VERSION 5.7 ;
  NOWIREEXTENSIONATPIN ON ;
  DIVIDERCHAR "/" ;
  BUSBITCHARS "[]" ;
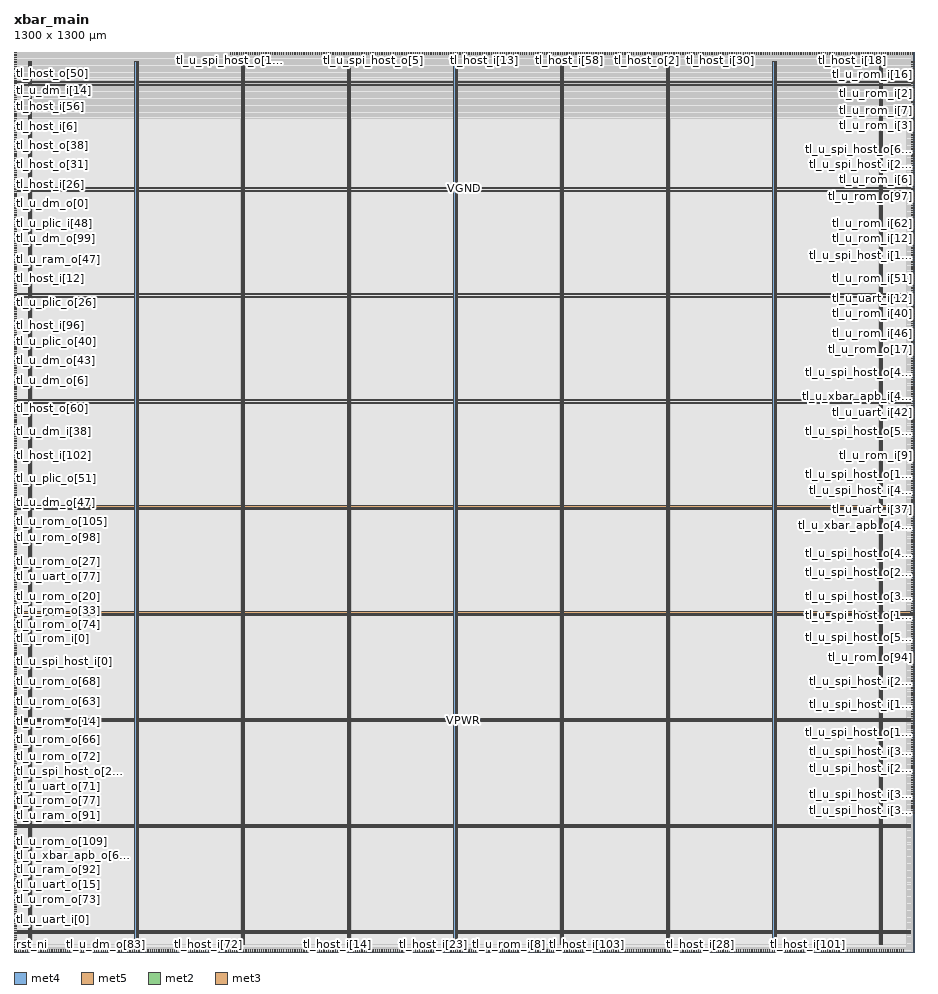
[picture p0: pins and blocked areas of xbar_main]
MACRO xbar_main
  CLASS BLOCK ;
  FOREIGN xbar_main ;
  ORIGIN 0.000 0.000 ;
  SIZE 1300.000 BY 1300.000 ;
  PIN VGND
    DIRECTION INOUT ;
    USE GROUND ;
    PORT
      LAYER met4 ;
        RECT 24.340 10.640 25.940 1286.800 ;
    END
    PORT
      LAYER met4 ;
        RECT 177.940 10.640 179.540 1286.800 ;
    END
    PORT
      LAYER met4 ;
        RECT 331.540 10.640 333.140 1286.800 ;
    END
    PORT
      LAYER met4 ;
        RECT 485.140 10.640 486.740 1286.800 ;
    END
    PORT
      LAYER met4 ;
        RECT 638.740 10.640 640.340 1286.800 ;
    END
    PORT
      LAYER met4 ;
        RECT 792.340 10.640 793.940 1286.800 ;
    END
    PORT
      LAYER met4 ;
        RECT 945.940 10.640 947.540 1286.800 ;
    END
    PORT
      LAYER met4 ;
        RECT 1099.540 10.640 1101.140 1286.800 ;
    END
    PORT
      LAYER met4 ;
        RECT 1253.140 10.640 1254.740 1286.800 ;
    END
    PORT
      LAYER met5 ;
        RECT 5.280 30.030 1294.680 31.630 ;
    END
    PORT
      LAYER met5 ;
        RECT 5.280 183.210 1294.680 184.810 ;
    END
    PORT
      LAYER met5 ;
        RECT 5.280 336.390 1294.680 337.990 ;
    END
    PORT
      LAYER met5 ;
        RECT 5.280 489.570 1294.680 491.170 ;
    END
    PORT
      LAYER met5 ;
        RECT 5.280 642.750 1294.680 644.350 ;
    END
    PORT
      LAYER met5 ;
        RECT 5.280 795.930 1294.680 797.530 ;
    END
    PORT
      LAYER met5 ;
        RECT 5.280 949.110 1294.680 950.710 ;
    END
    PORT
      LAYER met5 ;
        RECT 5.280 1102.290 1294.680 1103.890 ;
    END
    PORT
      LAYER met5 ;
        RECT 5.280 1255.470 1294.680 1257.070 ;
    END
  END VGND
  PIN VPWR
    DIRECTION INOUT ;
    USE POWER ;
    PORT
      LAYER met4 ;
        RECT 21.040 10.640 22.640 1286.800 ;
    END
    PORT
      LAYER met4 ;
        RECT 174.640 10.640 176.240 1286.800 ;
    END
    PORT
      LAYER met4 ;
        RECT 328.240 10.640 329.840 1286.800 ;
    END
    PORT
      LAYER met4 ;
        RECT 481.840 10.640 483.440 1286.800 ;
    END
    PORT
      LAYER met4 ;
        RECT 635.440 10.640 637.040 1286.800 ;
    END
    PORT
      LAYER met4 ;
        RECT 789.040 10.640 790.640 1286.800 ;
    END
    PORT
      LAYER met4 ;
        RECT 942.640 10.640 944.240 1286.800 ;
    END
    PORT
      LAYER met4 ;
        RECT 1096.240 10.640 1097.840 1286.800 ;
    END
    PORT
      LAYER met4 ;
        RECT 1249.840 10.640 1251.440 1286.800 ;
    END
    PORT
      LAYER met5 ;
        RECT 5.280 26.730 1294.680 28.330 ;
    END
    PORT
      LAYER met5 ;
        RECT 5.280 179.910 1294.680 181.510 ;
    END
    PORT
      LAYER met5 ;
        RECT 5.280 333.090 1294.680 334.690 ;
    END
    PORT
      LAYER met5 ;
        RECT 5.280 486.270 1294.680 487.870 ;
    END
    PORT
      LAYER met5 ;
        RECT 5.280 639.450 1294.680 641.050 ;
    END
    PORT
      LAYER met5 ;
        RECT 5.280 792.630 1294.680 794.230 ;
    END
    PORT
      LAYER met5 ;
        RECT 5.280 945.810 1294.680 947.410 ;
    END
    PORT
      LAYER met5 ;
        RECT 5.280 1098.990 1294.680 1100.590 ;
    END
    PORT
      LAYER met5 ;
        RECT 5.280 1252.170 1294.680 1253.770 ;
    END
  END VPWR
  PIN clk_i
    DIRECTION INPUT ;
    USE SIGNAL ;
    PORT
      LAYER met2 ;
        RECT 0.090 0.000 0.370 4.000 ;
    END
  END clk_i
  PIN rst_ni
    DIRECTION INPUT ;
    USE SIGNAL ;
    PORT
      LAYER met2 ;
        RECT 3.310 0.000 3.590 4.000 ;
    END
  END rst_ni
  PIN tl_host_i[0]
    DIRECTION INPUT ;
    USE SIGNAL ;
    ANTENNAGATEAREA 1.491900 ;
    ANTENNADIFFAREA 0.869400 ;
    PORT
      LAYER met3 ;
        RECT 0.000 1224.040 4.000 1224.640 ;
    END
  END tl_host_i[0]
  PIN tl_host_i[100]
    DIRECTION INPUT ;
    USE SIGNAL ;
    ANTENNAGATEAREA 1.491900 ;
    ANTENNADIFFAREA 0.869400 ;
    PORT
      LAYER met3 ;
        RECT 0.000 1105.040 4.000 1105.640 ;
    END
  END tl_host_i[100]
  PIN tl_host_i[101]
    DIRECTION INPUT ;
    USE SIGNAL ;
    ANTENNAGATEAREA 1.808400 ;
    ANTENNADIFFAREA 0.869400 ;
    PORT
      LAYER met2 ;
        RECT 1146.410 0.000 1146.690 4.000 ;
    END
  END tl_host_i[101]
  PIN tl_host_i[102]
    DIRECTION INPUT ;
    USE SIGNAL ;
    ANTENNAGATEAREA 1.560900 ;
    ANTENNADIFFAREA 0.869400 ;
    PORT
      LAYER met3 ;
        RECT 0.000 717.440 4.000 718.040 ;
    END
  END tl_host_i[102]
  PIN tl_host_i[103]
    DIRECTION INPUT ;
    USE SIGNAL ;
    ANTENNAGATEAREA 1.491900 ;
    ANTENNADIFFAREA 0.869400 ;
    PORT
      LAYER met2 ;
        RECT 827.630 0.000 827.910 4.000 ;
    END
  END tl_host_i[103]
  PIN tl_host_i[104]
    DIRECTION INPUT ;
    USE SIGNAL ;
    ANTENNAGATEAREA 1.808400 ;
    ANTENNADIFFAREA 0.869400 ;
    PORT
      LAYER met2 ;
        RECT 850.170 0.000 850.450 4.000 ;
    END
  END tl_host_i[104]
  PIN tl_host_i[105]
    DIRECTION INPUT ;
    USE SIGNAL ;
    ANTENNAGATEAREA 1.560900 ;
    ANTENNADIFFAREA 0.869400 ;
    PORT
      LAYER met2 ;
        RECT 6.530 0.000 6.810 4.000 ;
    END
  END tl_host_i[105]
  PIN tl_host_i[106]
    DIRECTION INPUT ;
    USE SIGNAL ;
    ANTENNAGATEAREA 1.313400 ;
    ANTENNADIFFAREA 0.869400 ;
    PORT
      LAYER met2 ;
        RECT 29.070 0.000 29.350 4.000 ;
    END
  END tl_host_i[106]
  PIN tl_host_i[107]
    DIRECTION INPUT ;
    USE SIGNAL ;
    ANTENNAGATEAREA 1.491900 ;
    ANTENNADIFFAREA 0.869400 ;
    PORT
      LAYER met3 ;
        RECT 0.000 877.240 4.000 877.840 ;
    END
  END tl_host_i[107]
  PIN tl_host_i[108]
    DIRECTION INPUT ;
    USE SIGNAL ;
    ANTENNAGATEAREA 1.491900 ;
    ANTENNADIFFAREA 0.869400 ;
    PORT
      LAYER met2 ;
        RECT 248.030 0.000 248.310 4.000 ;
    END
  END tl_host_i[108]
  PIN tl_host_i[109]
    DIRECTION INPUT ;
    USE SIGNAL ;
    ANTENNAGATEAREA 0.647700 ;
    ANTENNADIFFAREA 0.434700 ;
    PORT
      LAYER met2 ;
        RECT 241.590 0.000 241.870 4.000 ;
    END
  END tl_host_i[109]
  PIN tl_host_i[10]
    DIRECTION INPUT ;
    USE SIGNAL ;
    ANTENNAGATEAREA 1.313400 ;
    ANTENNADIFFAREA 0.869400 ;
    PORT
      LAYER met2 ;
        RECT 122.450 0.000 122.730 4.000 ;
    END
  END tl_host_i[10]
  PIN tl_host_i[11]
    DIRECTION INPUT ;
    USE SIGNAL ;
    ANTENNAGATEAREA 1.313400 ;
    ANTENNADIFFAREA 0.869400 ;
    PORT
      LAYER met2 ;
        RECT 1165.730 0.000 1166.010 4.000 ;
    END
  END tl_host_i[11]
  PIN tl_host_i[12]
    DIRECTION INPUT ;
    USE SIGNAL ;
    ANTENNAGATEAREA 1.560900 ;
    ANTENNADIFFAREA 0.869400 ;
    PORT
      LAYER met3 ;
        RECT 0.000 972.440 4.000 973.040 ;
    END
  END tl_host_i[12]
  PIN tl_host_i[13]
    DIRECTION INPUT ;
    USE SIGNAL ;
    ANTENNAGATEAREA 1.560900 ;
    ANTENNADIFFAREA 0.869400 ;
    PORT
      LAYER met2 ;
        RECT 679.510 1296.000 679.790 1300.000 ;
    END
  END tl_host_i[13]
  PIN tl_host_i[14]
    DIRECTION INPUT ;
    USE SIGNAL ;
    ANTENNAGATEAREA 1.491900 ;
    ANTENNADIFFAREA 0.869400 ;
    PORT
      LAYER met2 ;
        RECT 466.990 0.000 467.270 4.000 ;
    END
  END tl_host_i[14]
  PIN tl_host_i[15]
    DIRECTION INPUT ;
    USE SIGNAL ;
    ANTENNAGATEAREA 1.491900 ;
    ANTENNADIFFAREA 0.869400 ;
    PORT
      LAYER met2 ;
        RECT 512.070 0.000 512.350 4.000 ;
    END
  END tl_host_i[15]
  PIN tl_host_i[16]
    DIRECTION INPUT ;
    USE SIGNAL ;
    ANTENNAGATEAREA 1.560900 ;
    ANTENNADIFFAREA 0.869400 ;
    PORT
      LAYER met2 ;
        RECT 1011.170 0.000 1011.450 4.000 ;
    END
  END tl_host_i[16]
  PIN tl_host_i[17]
    DIRECTION INPUT ;
    USE SIGNAL ;
    ANTENNAGATEAREA 1.560900 ;
    ANTENNADIFFAREA 0.869400 ;
    PORT
      LAYER met2 ;
        RECT 769.670 1296.000 769.950 1300.000 ;
    END
  END tl_host_i[17]
  PIN tl_host_i[18]
    DIRECTION INPUT ;
    USE SIGNAL ;
    ANTENNAGATEAREA 1.808400 ;
    ANTENNADIFFAREA 0.869400 ;
    PORT
      LAYER met2 ;
        RECT 1210.810 1296.000 1211.090 1300.000 ;
    END
  END tl_host_i[18]
  PIN tl_host_i[19]
    DIRECTION INPUT ;
    USE SIGNAL ;
    ANTENNAGATEAREA 1.560900 ;
    ANTENNADIFFAREA 0.869400 ;
    PORT
      LAYER met3 ;
        RECT 0.000 697.040 4.000 697.640 ;
    END
  END tl_host_i[19]
  PIN tl_host_i[1]
    DIRECTION INPUT ;
    USE SIGNAL ;
    ANTENNAGATEAREA 1.560900 ;
    ANTENNADIFFAREA 0.869400 ;
    PORT
      LAYER met3 ;
        RECT 0.000 816.040 4.000 816.640 ;
    END
  END tl_host_i[1]
  PIN tl_host_i[20]
    DIRECTION INPUT ;
    USE SIGNAL ;
    ANTENNAGATEAREA 1.808400 ;
    ANTENNADIFFAREA 0.869400 ;
    PORT
      LAYER met2 ;
        RECT 173.970 0.000 174.250 4.000 ;
    END
  END tl_host_i[20]
  PIN tl_host_i[21]
    DIRECTION INPUT ;
    USE SIGNAL ;
    ANTENNAGATEAREA 1.491900 ;
    ANTENNADIFFAREA 0.869400 ;
    PORT
      LAYER met2 ;
        RECT 1085.230 0.000 1085.510 4.000 ;
    END
  END tl_host_i[21]
  PIN tl_host_i[22]
    DIRECTION INPUT ;
    USE SIGNAL ;
    ANTENNAGATEAREA 1.808400 ;
    ANTENNADIFFAREA 0.869400 ;
    PORT
      LAYER met2 ;
        RECT 956.430 1296.000 956.710 1300.000 ;
    END
  END tl_host_i[22]
  PIN tl_host_i[23]
    DIRECTION INPUT ;
    USE SIGNAL ;
    ANTENNAGATEAREA 1.808400 ;
    ANTENNADIFFAREA 0.869400 ;
    PORT
      LAYER met2 ;
        RECT 605.450 0.000 605.730 4.000 ;
    END
  END tl_host_i[23]
  PIN tl_host_i[24]
    DIRECTION INPUT ;
    USE SIGNAL ;
    ANTENNAGATEAREA 1.491900 ;
    ANTENNADIFFAREA 0.869400 ;
    PORT
      LAYER met3 ;
        RECT 0.000 914.640 4.000 915.240 ;
    END
  END tl_host_i[24]
  PIN tl_host_i[25]
    DIRECTION INPUT ;
    USE SIGNAL ;
    ANTENNAGATEAREA 1.313400 ;
    ANTENNADIFFAREA 0.869400 ;
    PORT
      LAYER met2 ;
        RECT 64.490 0.000 64.770 4.000 ;
    END
  END tl_host_i[25]
  PIN tl_host_i[26]
    DIRECTION INPUT ;
    USE SIGNAL ;
    ANTENNAGATEAREA 1.491900 ;
    ANTENNADIFFAREA 0.869400 ;
    PORT
      LAYER met3 ;
        RECT 0.000 1108.440 4.000 1109.040 ;
    END
  END tl_host_i[26]
  PIN tl_host_i[27]
    DIRECTION INPUT ;
    USE SIGNAL ;
    ANTENNAGATEAREA 2.055900 ;
    ANTENNADIFFAREA 0.869400 ;
    PORT
      LAYER met2 ;
        RECT 48.390 0.000 48.670 4.000 ;
    END
  END tl_host_i[27]
  PIN tl_host_i[28]
    DIRECTION INPUT ;
    USE SIGNAL ;
    ANTENNAGATEAREA 1.491900 ;
    ANTENNADIFFAREA 0.869400 ;
    PORT
      LAYER met2 ;
        RECT 991.850 0.000 992.130 4.000 ;
    END
  END tl_host_i[28]
  PIN tl_host_i[29]
    DIRECTION INPUT ;
    USE SIGNAL ;
    ANTENNAGATEAREA 1.491900 ;
    ANTENNADIFFAREA 0.869400 ;
    PORT
      LAYER met2 ;
        RECT 486.310 0.000 486.590 4.000 ;
    END
  END tl_host_i[29]
  PIN tl_host_i[2]
    DIRECTION INPUT ;
    USE SIGNAL ;
    ANTENNAGATEAREA 1.808400 ;
    ANTENNADIFFAREA 0.869400 ;
    PORT
      LAYER met3 ;
        RECT 0.000 663.040 4.000 663.640 ;
    END
  END tl_host_i[2]
  PIN tl_host_i[30]
    DIRECTION INPUT ;
    USE SIGNAL ;
    ANTENNAGATEAREA 1.560900 ;
    ANTENNADIFFAREA 0.869400 ;
    PORT
      LAYER met2 ;
        RECT 1020.830 1296.000 1021.110 1300.000 ;
    END
  END tl_host_i[30]
  PIN tl_host_i[31]
    DIRECTION INPUT ;
    USE SIGNAL ;
    ANTENNAGATEAREA 1.491900 ;
    ANTENNADIFFAREA 0.869400 ;
    PORT
      LAYER met2 ;
        RECT 1059.470 0.000 1059.750 4.000 ;
    END
  END tl_host_i[31]
  PIN tl_host_i[32]
    DIRECTION INPUT ;
    USE SIGNAL ;
    ANTENNAGATEAREA 1.808400 ;
    ANTENNADIFFAREA 0.869400 ;
    PORT
      LAYER met2 ;
        RECT 702.050 0.000 702.330 4.000 ;
    END
  END tl_host_i[32]
  PIN tl_host_i[33]
    DIRECTION INPUT ;
    USE SIGNAL ;
    ANTENNAGATEAREA 1.808400 ;
    ANTENNADIFFAREA 0.869400 ;
    PORT
      LAYER met2 ;
        RECT 96.690 0.000 96.970 4.000 ;
    END
  END tl_host_i[33]
  PIN tl_host_i[34]
    DIRECTION INPUT ;
    USE SIGNAL ;
    ANTENNAGATEAREA 2.711400 ;
    ANTENNADIFFAREA 0.869400 ;
    PORT
      LAYER met2 ;
        RECT 12.970 0.000 13.250 4.000 ;
    END
  END tl_host_i[34]
  PIN tl_host_i[35]
    DIRECTION INPUT ;
    USE SIGNAL ;
    ANTENNAGATEAREA 1.560900 ;
    ANTENNADIFFAREA 0.869400 ;
    PORT
      LAYER met2 ;
        RECT 917.790 0.000 918.070 4.000 ;
    END
  END tl_host_i[35]
  PIN tl_host_i[36]
    DIRECTION INPUT ;
    USE SIGNAL ;
    ANTENNAGATEAREA 1.560900 ;
    ANTENNADIFFAREA 0.869400 ;
    PORT
      LAYER met3 ;
        RECT 0.000 863.640 4.000 864.240 ;
    END
  END tl_host_i[36]
  PIN tl_host_i[37]
    DIRECTION INPUT ;
    USE SIGNAL ;
    ANTENNAGATEAREA 1.491900 ;
    ANTENNADIFFAREA 0.869400 ;
    PORT
      LAYER met2 ;
        RECT 1062.690 0.000 1062.970 4.000 ;
    END
  END tl_host_i[37]
  PIN tl_host_i[38]
    DIRECTION INPUT ;
    USE SIGNAL ;
    ANTENNAGATEAREA 1.313400 ;
    ANTENNADIFFAREA 0.869400 ;
    PORT
      LAYER met2 ;
        RECT 77.370 0.000 77.650 4.000 ;
    END
  END tl_host_i[38]
  PIN tl_host_i[39]
    DIRECTION INPUT ;
    USE SIGNAL ;
    ANTENNAGATEAREA 1.808400 ;
    ANTENNADIFFAREA 0.869400 ;
    PORT
      LAYER met2 ;
        RECT 995.070 0.000 995.350 4.000 ;
    END
  END tl_host_i[39]
  PIN tl_host_i[3]
    DIRECTION INPUT ;
    USE SIGNAL ;
    ANTENNAGATEAREA 1.491900 ;
    ANTENNADIFFAREA 0.869400 ;
    PORT
      LAYER met2 ;
        RECT 1230.130 0.000 1230.410 4.000 ;
    END
  END tl_host_i[3]
  PIN tl_host_i[40]
    DIRECTION INPUT ;
    USE SIGNAL ;
    ANTENNAGATEAREA 1.560900 ;
    ANTENNADIFFAREA 0.869400 ;
    PORT
      LAYER met3 ;
        RECT 0.000 761.640 4.000 762.240 ;
    END
  END tl_host_i[40]
  PIN tl_host_i[41]
    DIRECTION INPUT ;
    USE SIGNAL ;
    ANTENNAGATEAREA 1.491900 ;
    ANTENNADIFFAREA 0.869400 ;
    PORT
      LAYER met2 ;
        RECT 1036.930 0.000 1037.210 4.000 ;
    END
  END tl_host_i[41]
  PIN tl_host_i[42]
    DIRECTION INPUT ;
    USE SIGNAL ;
    ANTENNAGATEAREA 1.560900 ;
    ANTENNADIFFAREA 0.869400 ;
    PORT
      LAYER met2 ;
        RECT 1078.790 0.000 1079.070 4.000 ;
    END
  END tl_host_i[42]
  PIN tl_host_i[43]
    DIRECTION INPUT ;
    USE SIGNAL ;
    ANTENNAGATEAREA 1.917900 ;
    ANTENNADIFFAREA 0.869400 ;
    PORT
      LAYER met3 ;
        RECT 0.000 629.040 4.000 629.640 ;
    END
  END tl_host_i[43]
  PIN tl_host_i[44]
    DIRECTION INPUT ;
    USE SIGNAL ;
    ANTENNAGATEAREA 1.560900 ;
    ANTENNADIFFAREA 0.869400 ;
    PORT
      LAYER met3 ;
        RECT 0.000 969.040 4.000 969.640 ;
    END
  END tl_host_i[44]
  PIN tl_host_i[45]
    DIRECTION INPUT ;
    USE SIGNAL ;
    ANTENNAGATEAREA 1.560900 ;
    ANTENNADIFFAREA 0.869400 ;
    PORT
      LAYER met2 ;
        RECT 998.290 0.000 998.570 4.000 ;
    END
  END tl_host_i[45]
  PIN tl_host_i[46]
    DIRECTION INPUT ;
    USE SIGNAL ;
    ANTENNAGATEAREA 1.808400 ;
    ANTENNADIFFAREA 0.869400 ;
    PORT
      LAYER met2 ;
        RECT 933.890 1296.000 934.170 1300.000 ;
    END
  END tl_host_i[46]
  PIN tl_host_i[47]
    DIRECTION INPUT ;
    USE SIGNAL ;
    ANTENNAGATEAREA 1.808400 ;
    ANTENNADIFFAREA 0.869400 ;
    PORT
      LAYER met3 ;
        RECT 0.000 656.240 4.000 656.840 ;
    END
  END tl_host_i[47]
  PIN tl_host_i[48]
    DIRECTION INPUT ;
    USE SIGNAL ;
    ANTENNAGATEAREA 1.508400 ;
    ANTENNADIFFAREA 0.869400 ;
    PORT
      LAYER met3 ;
        RECT 0.000 992.840 4.000 993.440 ;
    END
  END tl_host_i[48]
  PIN tl_host_i[49]
    DIRECTION INPUT ;
    USE SIGNAL ;
    ANTENNAGATEAREA 1.808400 ;
    ANTENNADIFFAREA 0.869400 ;
    PORT
      LAYER met3 ;
        RECT 0.000 639.240 4.000 639.840 ;
    END
  END tl_host_i[49]
  PIN tl_host_i[4]
    DIRECTION INPUT ;
    USE SIGNAL ;
    ANTENNAGATEAREA 1.808400 ;
    ANTENNADIFFAREA 0.869400 ;
    PORT
      LAYER met2 ;
        RECT 61.270 0.000 61.550 4.000 ;
    END
  END tl_host_i[4]
  PIN tl_host_i[50]
    DIRECTION INPUT ;
    USE SIGNAL ;
    ANTENNAGATEAREA 1.808400 ;
    ANTENNADIFFAREA 0.869400 ;
    PORT
      LAYER met2 ;
        RECT 708.490 0.000 708.770 4.000 ;
    END
  END tl_host_i[50]
  PIN tl_host_i[51]
    DIRECTION INPUT ;
    USE SIGNAL ;
    ANTENNAGATEAREA 1.808400 ;
    ANTENNADIFFAREA 0.869400 ;
    PORT
      LAYER met3 ;
        RECT 0.000 686.840 4.000 687.440 ;
    END
  END tl_host_i[51]
  PIN tl_host_i[52]
    DIRECTION INPUT ;
    USE SIGNAL ;
    ANTENNAGATEAREA 1.313400 ;
    ANTENNADIFFAREA 0.869400 ;
    PORT
      LAYER met2 ;
        RECT 1139.970 0.000 1140.250 4.000 ;
    END
  END tl_host_i[52]
  PIN tl_host_i[53]
    DIRECTION INPUT ;
    USE SIGNAL ;
    ANTENNAGATEAREA 1.560900 ;
    ANTENNADIFFAREA 0.869400 ;
    PORT
      LAYER met2 ;
        RECT 666.630 0.000 666.910 4.000 ;
    END
  END tl_host_i[53]
  PIN tl_host_i[54]
    DIRECTION INPUT ;
    USE SIGNAL ;
    ANTENNAGATEAREA 1.808400 ;
    ANTENNADIFFAREA 0.869400 ;
    PORT
      LAYER met3 ;
        RECT 0.000 1173.040 4.000 1173.640 ;
    END
  END tl_host_i[54]
  PIN tl_host_i[55]
    DIRECTION INPUT ;
    USE SIGNAL ;
    ANTENNAGATEAREA 1.808400 ;
    ANTENNADIFFAREA 0.869400 ;
    PORT
      LAYER met3 ;
        RECT 0.000 846.640 4.000 847.240 ;
    END
  END tl_host_i[55]
  PIN tl_host_i[56]
    DIRECTION INPUT ;
    USE SIGNAL ;
    ANTENNAGATEAREA 1.491900 ;
    ANTENNADIFFAREA 0.869400 ;
    PORT
      LAYER met3 ;
        RECT 0.000 1220.640 4.000 1221.240 ;
    END
  END tl_host_i[56]
  PIN tl_host_i[57]
    DIRECTION INPUT ;
    USE SIGNAL ;
    ANTENNAGATEAREA 1.491900 ;
    ANTENNADIFFAREA 0.869400 ;
    PORT
      LAYER met3 ;
        RECT 0.000 1162.840 4.000 1163.440 ;
    END
  END tl_host_i[57]
  PIN tl_host_i[58]
    DIRECTION INPUT ;
    USE SIGNAL ;
    ANTENNAGATEAREA 1.313400 ;
    ANTENNADIFFAREA 0.869400 ;
    PORT
      LAYER met2 ;
        RECT 801.870 1296.000 802.150 1300.000 ;
    END
  END tl_host_i[58]
  PIN tl_host_i[59]
    DIRECTION INPUT ;
    USE SIGNAL ;
    ANTENNAGATEAREA 1.560900 ;
    ANTENNADIFFAREA 0.869400 ;
    PORT
      LAYER met2 ;
        RECT 888.810 0.000 889.090 4.000 ;
    END
  END tl_host_i[59]
  PIN tl_host_i[5]
    DIRECTION INPUT ;
    USE SIGNAL ;
    ANTENNAGATEAREA 1.917900 ;
    ANTENNADIFFAREA 0.869400 ;
    PORT
      LAYER met3 ;
        RECT 0.000 999.640 4.000 1000.240 ;
    END
  END tl_host_i[5]
  PIN tl_host_i[60]
    DIRECTION INPUT ;
    USE SIGNAL ;
    ANTENNAGATEAREA 1.491900 ;
    ANTENNADIFFAREA 0.869400 ;
    PORT
      LAYER met2 ;
        RECT 966.090 1296.000 966.370 1300.000 ;
    END
  END tl_host_i[60]
  PIN tl_host_i[61]
    DIRECTION INPUT ;
    USE SIGNAL ;
    ANTENNAGATEAREA 0.593700 ;
    ANTENNADIFFAREA 0.434700 ;
    PORT
      LAYER met2 ;
        RECT 322.090 0.000 322.370 4.000 ;
    END
  END tl_host_i[61]
  PIN tl_host_i[62]
    DIRECTION INPUT ;
    USE SIGNAL ;
    ANTENNAGATEAREA 0.593700 ;
    ANTENNADIFFAREA 0.434700 ;
    PORT
      LAYER met2 ;
        RECT 386.490 0.000 386.770 4.000 ;
    END
  END tl_host_i[62]
  PIN tl_host_i[63]
    DIRECTION INPUT ;
    USE SIGNAL ;
    ANTENNAGATEAREA 0.593700 ;
    ANTENNADIFFAREA 0.434700 ;
    PORT
      LAYER met2 ;
        RECT 351.070 0.000 351.350 4.000 ;
    END
  END tl_host_i[63]
  PIN tl_host_i[64]
    DIRECTION INPUT ;
    USE SIGNAL ;
    ANTENNAGATEAREA 0.647700 ;
    ANTENNADIFFAREA 0.434700 ;
    PORT
      LAYER met2 ;
        RECT 412.250 0.000 412.530 4.000 ;
    END
  END tl_host_i[64]
  PIN tl_host_i[65]
    DIRECTION INPUT ;
    USE SIGNAL ;
    ANTENNAGATEAREA 0.593700 ;
    ANTENNADIFFAREA 0.434700 ;
    PORT
      LAYER met2 ;
        RECT 380.050 0.000 380.330 4.000 ;
    END
  END tl_host_i[65]
  PIN tl_host_i[66]
    DIRECTION INPUT ;
    USE SIGNAL ;
    ANTENNAGATEAREA 0.647700 ;
    ANTENNADIFFAREA 0.434700 ;
    PORT
      LAYER met2 ;
        RECT 450.890 0.000 451.170 4.000 ;
    END
  END tl_host_i[66]
  PIN tl_host_i[67]
    DIRECTION INPUT ;
    USE SIGNAL ;
    ANTENNAGATEAREA 0.647700 ;
    ANTENNADIFFAREA 0.434700 ;
    PORT
      LAYER met2 ;
        RECT 534.610 0.000 534.890 4.000 ;
    END
  END tl_host_i[67]
  PIN tl_host_i[68]
    DIRECTION INPUT ;
    USE SIGNAL ;
    ANTENNAGATEAREA 0.647700 ;
    ANTENNADIFFAREA 0.434700 ;
    PORT
      LAYER met2 ;
        RECT 428.350 0.000 428.630 4.000 ;
    END
  END tl_host_i[68]
  PIN tl_host_i[69]
    DIRECTION INPUT ;
    USE SIGNAL ;
    ANTENNAGATEAREA 0.631200 ;
    ANTENNADIFFAREA 0.434700 ;
    PORT
      LAYER met2 ;
        RECT 209.390 0.000 209.670 4.000 ;
    END
  END tl_host_i[69]
  PIN tl_host_i[6]
    DIRECTION INPUT ;
    USE SIGNAL ;
    ANTENNAGATEAREA 1.560900 ;
    ANTENNADIFFAREA 0.869400 ;
    PORT
      LAYER met3 ;
        RECT 0.000 1203.640 4.000 1204.240 ;
    END
  END tl_host_i[6]
  PIN tl_host_i[70]
    DIRECTION INPUT ;
    USE SIGNAL ;
    ANTENNAGATEAREA 0.682200 ;
    ANTENNADIFFAREA 0.434700 ;
    PORT
      LAYER met2 ;
        RECT 219.050 0.000 219.330 4.000 ;
    END
  END tl_host_i[70]
  PIN tl_host_i[71]
    DIRECTION INPUT ;
    USE SIGNAL ;
    ANTENNAGATEAREA 0.682200 ;
    ANTENNADIFFAREA 0.434700 ;
    PORT
      LAYER met2 ;
        RECT 309.210 0.000 309.490 4.000 ;
    END
  END tl_host_i[71]
  PIN tl_host_i[72]
    DIRECTION INPUT ;
    USE SIGNAL ;
    ANTENNAGATEAREA 0.682200 ;
    ANTENNADIFFAREA 0.434700 ;
    PORT
      LAYER met2 ;
        RECT 280.230 0.000 280.510 4.000 ;
    END
  END tl_host_i[72]
  PIN tl_host_i[73]
    DIRECTION INPUT ;
    USE SIGNAL ;
    ANTENNAGATEAREA 0.631200 ;
    ANTENNADIFFAREA 0.434700 ;
    PORT
      LAYER met2 ;
        RECT 254.470 0.000 254.750 4.000 ;
    END
  END tl_host_i[73]
  PIN tl_host_i[74]
    DIRECTION INPUT ;
    USE SIGNAL ;
    ANTENNAGATEAREA 0.631200 ;
    ANTENNADIFFAREA 0.434700 ;
    PORT
      LAYER met2 ;
        RECT 235.150 0.000 235.430 4.000 ;
    END
  END tl_host_i[74]
  PIN tl_host_i[75]
    DIRECTION INPUT ;
    USE SIGNAL ;
    ANTENNAGATEAREA 0.631200 ;
    ANTENNADIFFAREA 0.434700 ;
    PORT
      LAYER met2 ;
        RECT 267.350 0.000 267.630 4.000 ;
    END
  END tl_host_i[75]
  PIN tl_host_i[76]
    DIRECTION INPUT ;
    USE SIGNAL ;
    ANTENNAGATEAREA 0.631200 ;
    ANTENNADIFFAREA 0.434700 ;
    PORT
      LAYER met2 ;
        RECT 128.890 0.000 129.170 4.000 ;
    END
  END tl_host_i[76]
  PIN tl_host_i[77]
    DIRECTION INPUT ;
    USE SIGNAL ;
    ANTENNAGATEAREA 0.631200 ;
    ANTENNADIFFAREA 0.434700 ;
    PORT
      LAYER met2 ;
        RECT 157.870 0.000 158.150 4.000 ;
    END
  END tl_host_i[77]
  PIN tl_host_i[78]
    DIRECTION INPUT ;
    USE SIGNAL ;
    ANTENNAGATEAREA 0.560700 ;
    ANTENNADIFFAREA 0.434700 ;
    PORT
      LAYER met2 ;
        RECT 135.330 0.000 135.610 4.000 ;
    END
  END tl_host_i[78]
  PIN tl_host_i[79]
    DIRECTION INPUT ;
    USE SIGNAL ;
    ANTENNAGATEAREA 0.647700 ;
    ANTENNADIFFAREA 0.434700 ;
    PORT
      LAYER met2 ;
        RECT 215.830 0.000 216.110 4.000 ;
    END
  END tl_host_i[79]
  PIN tl_host_i[7]
    DIRECTION INPUT ;
    USE SIGNAL ;
    ANTENNAGATEAREA 1.491900 ;
    ANTENNADIFFAREA 0.869400 ;
    PORT
      LAYER met2 ;
        RECT 1091.670 0.000 1091.950 4.000 ;
    END
  END tl_host_i[7]
  PIN tl_host_i[80]
    DIRECTION INPUT ;
    USE SIGNAL ;
    ANTENNAGATEAREA 0.631200 ;
    ANTENNADIFFAREA 0.434700 ;
    PORT
      LAYER met2 ;
        RECT 186.850 0.000 187.130 4.000 ;
    END
  END tl_host_i[80]
  PIN tl_host_i[81]
    DIRECTION INPUT ;
    USE SIGNAL ;
    ANTENNAGATEAREA 0.560700 ;
    ANTENNADIFFAREA 0.434700 ;
    PORT
      LAYER met2 ;
        RECT 141.770 0.000 142.050 4.000 ;
    END
  END tl_host_i[81]
  PIN tl_host_i[82]
    DIRECTION INPUT ;
    USE SIGNAL ;
    ANTENNAGATEAREA 0.631200 ;
    ANTENNADIFFAREA 0.434700 ;
    PORT
      LAYER met2 ;
        RECT 125.670 0.000 125.950 4.000 ;
    END
  END tl_host_i[82]
  PIN tl_host_i[83]
    DIRECTION INPUT ;
    USE SIGNAL ;
    ANTENNAGATEAREA 0.682200 ;
    ANTENNADIFFAREA 0.434700 ;
    PORT
      LAYER met2 ;
        RECT 106.350 0.000 106.630 4.000 ;
    END
  END tl_host_i[83]
  PIN tl_host_i[84]
    DIRECTION INPUT ;
    USE SIGNAL ;
    ANTENNAGATEAREA 0.682200 ;
    ANTENNADIFFAREA 0.434700 ;
    PORT
      LAYER met2 ;
        RECT 83.810 0.000 84.090 4.000 ;
    END
  END tl_host_i[84]
  PIN tl_host_i[85]
    DIRECTION INPUT ;
    USE SIGNAL ;
    ANTENNAGATEAREA 0.593700 ;
    ANTENNADIFFAREA 0.434700 ;
    PORT
      LAYER met2 ;
        RECT 341.410 0.000 341.690 4.000 ;
    END
  END tl_host_i[85]
  PIN tl_host_i[86]
    DIRECTION INPUT ;
    USE SIGNAL ;
    ANTENNAGATEAREA 0.682200 ;
    ANTENNADIFFAREA 0.434700 ;
    PORT
      LAYER met2 ;
        RECT 334.970 0.000 335.250 4.000 ;
    END
  END tl_host_i[86]
  PIN tl_host_i[87]
    DIRECTION INPUT ;
    USE SIGNAL ;
    ANTENNAGATEAREA 0.631200 ;
    ANTENNADIFFAREA 0.434700 ;
    PORT
      LAYER met2 ;
        RECT 438.010 0.000 438.290 4.000 ;
    END
  END tl_host_i[87]
  PIN tl_host_i[88]
    DIRECTION INPUT ;
    USE SIGNAL ;
    ANTENNAGATEAREA 0.631200 ;
    ANTENNADIFFAREA 0.434700 ;
    PORT
      LAYER met2 ;
        RECT 396.150 0.000 396.430 4.000 ;
    END
  END tl_host_i[88]
  PIN tl_host_i[89]
    DIRECTION INPUT ;
    USE SIGNAL ;
    ANTENNAGATEAREA 0.647700 ;
    ANTENNADIFFAREA 0.434700 ;
    PORT
      LAYER met2 ;
        RECT 302.770 0.000 303.050 4.000 ;
    END
  END tl_host_i[89]
  PIN tl_host_i[8]
    DIRECTION INPUT ;
    USE SIGNAL ;
    ANTENNAGATEAREA 1.313400 ;
    ANTENNADIFFAREA 0.869400 ;
    PORT
      LAYER met2 ;
        RECT 788.990 1296.000 789.270 1300.000 ;
    END
  END tl_host_i[8]
  PIN tl_host_i[90]
    DIRECTION INPUT ;
    USE SIGNAL ;
    ANTENNAGATEAREA 0.631200 ;
    ANTENNADIFFAREA 0.434700 ;
    PORT
      LAYER met2 ;
        RECT 421.910 0.000 422.190 4.000 ;
    END
  END tl_host_i[90]
  PIN tl_host_i[91]
    DIRECTION INPUT ;
    USE SIGNAL ;
    ANTENNAGATEAREA 0.631200 ;
    ANTENNADIFFAREA 0.434700 ;
    PORT
      LAYER met2 ;
        RECT 376.830 0.000 377.110 4.000 ;
    END
  END tl_host_i[91]
  PIN tl_host_i[92]
    DIRECTION INPUT ;
    USE SIGNAL ;
    ANTENNAGATEAREA 0.631200 ;
    ANTENNADIFFAREA 0.434700 ;
    PORT
      LAYER met2 ;
        RECT 399.370 0.000 399.650 4.000 ;
    END
  END tl_host_i[92]
  PIN tl_host_i[93]
    DIRECTION INPUT ;
    USE SIGNAL ;
    ANTENNAGATEAREA 2.072400 ;
    ANTENNADIFFAREA 0.869400 ;
    PORT
      LAYER met2 ;
        RECT 1101.330 1296.000 1101.610 1300.000 ;
    END
  END tl_host_i[93]
  PIN tl_host_i[94]
    DIRECTION INPUT ;
    USE SIGNAL ;
    ANTENNAGATEAREA 1.491900 ;
    ANTENNADIFFAREA 0.869400 ;
    PORT
      LAYER met2 ;
        RECT 1072.350 0.000 1072.630 4.000 ;
    END
  END tl_host_i[94]
  PIN tl_host_i[95]
    DIRECTION INPUT ;
    USE SIGNAL ;
    ANTENNAGATEAREA 1.808400 ;
    ANTENNADIFFAREA 0.869400 ;
    PORT
      LAYER met2 ;
        RECT 1098.110 1296.000 1098.390 1300.000 ;
    END
  END tl_host_i[95]
  PIN tl_host_i[96]
    DIRECTION INPUT ;
    USE SIGNAL ;
    ANTENNAGATEAREA 1.808400 ;
    ANTENNADIFFAREA 0.869400 ;
    PORT
      LAYER met3 ;
        RECT 0.000 904.440 4.000 905.040 ;
    END
  END tl_host_i[96]
  PIN tl_host_i[97]
    DIRECTION INPUT ;
    USE SIGNAL ;
    ANTENNAGATEAREA 1.491900 ;
    ANTENNADIFFAREA 0.869400 ;
    PORT
      LAYER met2 ;
        RECT 734.250 1296.000 734.530 1300.000 ;
    END
  END tl_host_i[97]
  PIN tl_host_i[98]
    DIRECTION INPUT ;
    USE SIGNAL ;
    ANTENNAGATEAREA 1.491900 ;
    ANTENNADIFFAREA 0.869400 ;
    PORT
      LAYER met2 ;
        RECT 41.950 0.000 42.230 4.000 ;
    END
  END tl_host_i[98]
  PIN tl_host_i[99]
    DIRECTION INPUT ;
    USE SIGNAL ;
    ANTENNAGATEAREA 1.808400 ;
    ANTENNADIFFAREA 0.869400 ;
    PORT
      LAYER met3 ;
        RECT 0.000 1037.040 4.000 1037.640 ;
    END
  END tl_host_i[99]
  PIN tl_host_i[9]
    DIRECTION INPUT ;
    USE SIGNAL ;
    ANTENNAGATEAREA 1.808400 ;
    ANTENNADIFFAREA 0.869400 ;
    PORT
      LAYER met2 ;
        RECT 695.610 1296.000 695.890 1300.000 ;
    END
  END tl_host_i[9]
  PIN tl_host_o[0]
    DIRECTION OUTPUT ;
    USE SIGNAL ;
    ANTENNADIFFAREA 0.445500 ;
    PORT
      LAYER met2 ;
        RECT 231.930 0.000 232.210 4.000 ;
    END
  END tl_host_o[0]
  PIN tl_host_o[10]
    DIRECTION OUTPUT ;
    USE SIGNAL ;
    ANTENNADIFFAREA 0.445500 ;
    PORT
      LAYER met3 ;
        RECT 0.000 754.840 4.000 755.440 ;
    END
  END tl_host_o[10]
  PIN tl_host_o[11]
    DIRECTION OUTPUT ;
    USE SIGNAL ;
    ANTENNADIFFAREA 0.445500 ;
    PORT
      LAYER met2 ;
        RECT 663.410 0.000 663.690 4.000 ;
    END
  END tl_host_o[11]
  PIN tl_host_o[12]
    DIRECTION OUTPUT ;
    USE SIGNAL ;
    ANTENNADIFFAREA 0.445500 ;
    PORT
      LAYER met2 ;
        RECT 949.990 1296.000 950.270 1300.000 ;
    END
  END tl_host_o[12]
  PIN tl_host_o[13]
    DIRECTION OUTPUT ;
    USE SIGNAL ;
    ANTENNADIFFAREA 0.445500 ;
    PORT
      LAYER met2 ;
        RECT 1181.830 0.000 1182.110 4.000 ;
    END
  END tl_host_o[13]
  PIN tl_host_o[14]
    DIRECTION OUTPUT ;
    USE SIGNAL ;
    ANTENNADIFFAREA 0.445500 ;
    PORT
      LAYER met3 ;
        RECT 0.000 1213.840 4.000 1214.440 ;
    END
  END tl_host_o[14]
  PIN tl_host_o[15]
    DIRECTION OUTPUT ;
    USE SIGNAL ;
    ANTENNADIFFAREA 0.445500 ;
    PORT
      LAYER met2 ;
        RECT 1249.450 0.000 1249.730 4.000 ;
    END
  END tl_host_o[15]
  PIN tl_host_o[16]
    DIRECTION OUTPUT ;
    USE SIGNAL ;
    ANTENNADIFFAREA 0.445500 ;
    PORT
      LAYER met2 ;
        RECT 978.970 1296.000 979.250 1300.000 ;
    END
  END tl_host_o[16]
  PIN tl_host_o[17]
    DIRECTION OUTPUT ;
    USE SIGNAL ;
    ANTENNADIFFAREA 0.445500 ;
    PORT
      LAYER met2 ;
        RECT 1007.950 1296.000 1008.230 1300.000 ;
    END
  END tl_host_o[17]
  PIN tl_host_o[18]
    DIRECTION OUTPUT ;
    USE SIGNAL ;
    ANTENNADIFFAREA 0.445500 ;
    PORT
      LAYER met2 ;
        RECT 1133.530 0.000 1133.810 4.000 ;
    END
  END tl_host_o[18]
  PIN tl_host_o[19]
    DIRECTION OUTPUT ;
    USE SIGNAL ;
    ANTENNADIFFAREA 0.445500 ;
    PORT
      LAYER met2 ;
        RECT 1149.630 1296.000 1149.910 1300.000 ;
    END
  END tl_host_o[19]
  PIN tl_host_o[1]
    DIRECTION OUTPUT ;
    USE SIGNAL ;
    ANTENNADIFFAREA 0.445500 ;
    PORT
      LAYER met2 ;
        RECT 1078.790 1296.000 1079.070 1300.000 ;
    END
  END tl_host_o[1]
  PIN tl_host_o[20]
    DIRECTION OUTPUT ;
    USE SIGNAL ;
    ANTENNADIFFAREA 0.445500 ;
    PORT
      LAYER met2 ;
        RECT 763.230 0.000 763.510 4.000 ;
    END
  END tl_host_o[20]
  PIN tl_host_o[21]
    DIRECTION OUTPUT ;
    USE SIGNAL ;
    ANTENNADIFFAREA 0.445500 ;
    PORT
      LAYER met2 ;
        RECT 692.390 0.000 692.670 4.000 ;
    END
  END tl_host_o[21]
  PIN tl_host_o[22]
    DIRECTION OUTPUT ;
    USE SIGNAL ;
    ANTENNADIFFAREA 0.445500 ;
    PORT
      LAYER met3 ;
        RECT 0.000 1227.440 4.000 1228.040 ;
    END
  END tl_host_o[22]
  PIN tl_host_o[23]
    DIRECTION OUTPUT ;
    USE SIGNAL ;
    ANTENNADIFFAREA 0.445500 ;
    PORT
      LAYER met2 ;
        RECT 892.030 1296.000 892.310 1300.000 ;
    END
  END tl_host_o[23]
  PIN tl_host_o[24]
    DIRECTION OUTPUT ;
    USE SIGNAL ;
    ANTENNADIFFAREA 0.445500 ;
    PORT
      LAYER met2 ;
        RECT 817.970 1296.000 818.250 1300.000 ;
    END
  END tl_host_o[24]
  PIN tl_host_o[25]
    DIRECTION OUTPUT ;
    USE SIGNAL ;
    ANTENNADIFFAREA 0.445500 ;
    PORT
      LAYER met2 ;
        RECT 824.410 1296.000 824.690 1300.000 ;
    END
  END tl_host_o[25]
  PIN tl_host_o[26]
    DIRECTION OUTPUT ;
    USE SIGNAL ;
    ANTENNADIFFAREA 0.445500 ;
    PORT
      LAYER met2 ;
        RECT 763.230 1296.000 763.510 1300.000 ;
    END
  END tl_host_o[26]
  PIN tl_host_o[27]
    DIRECTION OUTPUT ;
    USE SIGNAL ;
    ANTENNADIFFAREA 0.445500 ;
    PORT
      LAYER met2 ;
        RECT 805.090 0.000 805.370 4.000 ;
    END
  END tl_host_o[27]
  PIN tl_host_o[28]
    DIRECTION OUTPUT ;
    USE SIGNAL ;
    ANTENNADIFFAREA 0.445500 ;
    PORT
      LAYER met2 ;
        RECT 779.330 0.000 779.610 4.000 ;
    END
  END tl_host_o[28]
  PIN tl_host_o[29]
    DIRECTION OUTPUT ;
    USE SIGNAL ;
    ANTENNADIFFAREA 0.445500 ;
    PORT
      LAYER met2 ;
        RECT 953.210 1296.000 953.490 1300.000 ;
    END
  END tl_host_o[29]
  PIN tl_host_o[2]
    DIRECTION OUTPUT ;
    USE SIGNAL ;
    ANTENNADIFFAREA 0.445500 ;
    PORT
      LAYER met2 ;
        RECT 914.570 1296.000 914.850 1300.000 ;
    END
  END tl_host_o[2]
  PIN tl_host_o[30]
    DIRECTION OUTPUT ;
    USE SIGNAL ;
    ANTENNADIFFAREA 0.445500 ;
    PORT
      LAYER met2 ;
        RECT 1265.550 0.000 1265.830 4.000 ;
    END
  END tl_host_o[30]
  PIN tl_host_o[31]
    DIRECTION OUTPUT ;
    USE SIGNAL ;
    ANTENNADIFFAREA 0.445500 ;
    PORT
      LAYER met3 ;
        RECT 0.000 1125.440 4.000 1126.040 ;
    END
  END tl_host_o[31]
  PIN tl_host_o[32]
    DIRECTION OUTPUT ;
    USE SIGNAL ;
    ANTENNADIFFAREA 0.445500 ;
    PORT
      LAYER met2 ;
        RECT 1233.350 0.000 1233.630 4.000 ;
    END
  END tl_host_o[32]
  PIN tl_host_o[33]
    DIRECTION OUTPUT ;
    USE SIGNAL ;
    ANTENNADIFFAREA 0.445500 ;
    PORT
      LAYER met2 ;
        RECT 1178.610 1296.000 1178.890 1300.000 ;
    END
  END tl_host_o[33]
  PIN tl_host_o[34]
    DIRECTION OUTPUT ;
    USE SIGNAL ;
    ANTENNADIFFAREA 0.445500 ;
    PORT
      LAYER met2 ;
        RECT 1162.510 1296.000 1162.790 1300.000 ;
    END
  END tl_host_o[34]
  PIN tl_host_o[35]
    DIRECTION OUTPUT ;
    USE SIGNAL ;
    ANTENNADIFFAREA 0.445500 ;
    PORT
      LAYER met2 ;
        RECT 760.010 1296.000 760.290 1300.000 ;
    END
  END tl_host_o[35]
  PIN tl_host_o[36]
    DIRECTION OUTPUT ;
    USE SIGNAL ;
    ANTENNADIFFAREA 0.445500 ;
    PORT
      LAYER met2 ;
        RECT 1275.210 1296.000 1275.490 1300.000 ;
    END
  END tl_host_o[36]
  PIN tl_host_o[37]
    DIRECTION OUTPUT ;
    USE SIGNAL ;
    ANTENNADIFFAREA 0.445500 ;
    PORT
      LAYER met2 ;
        RECT 834.070 0.000 834.350 4.000 ;
    END
  END tl_host_o[37]
  PIN tl_host_o[38]
    DIRECTION OUTPUT ;
    USE SIGNAL ;
    ANTENNADIFFAREA 0.445500 ;
    PORT
      LAYER met3 ;
        RECT 0.000 1176.440 4.000 1177.040 ;
    END
  END tl_host_o[38]
  PIN tl_host_o[39]
    DIRECTION OUTPUT ;
    USE SIGNAL ;
    ANTENNADIFFAREA 0.445500 ;
    PORT
      LAYER met2 ;
        RECT 1255.890 0.000 1256.170 4.000 ;
    END
  END tl_host_o[39]
  PIN tl_host_o[3]
    DIRECTION OUTPUT ;
    USE SIGNAL ;
    ANTENNADIFFAREA 0.445500 ;
    PORT
      LAYER met2 ;
        RECT 1110.990 1296.000 1111.270 1300.000 ;
    END
  END tl_host_o[3]
  PIN tl_host_o[40]
    DIRECTION OUTPUT ;
    USE SIGNAL ;
    ANTENNADIFFAREA 0.445500 ;
    PORT
      LAYER met2 ;
        RECT 776.110 1296.000 776.390 1300.000 ;
    END
  END tl_host_o[40]
  PIN tl_host_o[41]
    DIRECTION OUTPUT ;
    USE SIGNAL ;
    ANTENNADIFFAREA 0.445500 ;
    PORT
      LAYER met2 ;
        RECT 1239.790 1296.000 1240.070 1300.000 ;
    END
  END tl_host_o[41]
  PIN tl_host_o[42]
    DIRECTION OUTPUT ;
    USE SIGNAL ;
    ANTENNADIFFAREA 0.445500 ;
    PORT
      LAYER met2 ;
        RECT 888.810 1296.000 889.090 1300.000 ;
    END
  END tl_host_o[42]
  PIN tl_host_o[43]
    DIRECTION OUTPUT ;
    USE SIGNAL ;
    ANTENNADIFFAREA 0.445500 ;
    PORT
      LAYER met2 ;
        RECT 1275.210 0.000 1275.490 4.000 ;
    END
  END tl_host_o[43]
  PIN tl_host_o[44]
    DIRECTION OUTPUT ;
    USE SIGNAL ;
    ANTENNADIFFAREA 0.445500 ;
    PORT
      LAYER met2 ;
        RECT 1036.930 1296.000 1037.210 1300.000 ;
    END
  END tl_host_o[44]
  PIN tl_host_o[45]
    DIRECTION OUTPUT ;
    USE SIGNAL ;
    ANTENNADIFFAREA 0.445500 ;
    PORT
      LAYER met2 ;
        RECT 885.590 1296.000 885.870 1300.000 ;
    END
  END tl_host_o[45]
  PIN tl_host_o[46]
    DIRECTION OUTPUT ;
    USE SIGNAL ;
    ANTENNADIFFAREA 0.445500 ;
    PORT
      LAYER met2 ;
        RECT 1133.530 1296.000 1133.810 1300.000 ;
    END
  END tl_host_o[46]
  PIN tl_host_o[47]
    DIRECTION OUTPUT ;
    USE SIGNAL ;
    ANTENNADIFFAREA 0.445500 ;
    PORT
      LAYER met2 ;
        RECT 666.630 1296.000 666.910 1300.000 ;
    END
  END tl_host_o[47]
  PIN tl_host_o[48]
    DIRECTION OUTPUT ;
    USE SIGNAL ;
    ANTENNADIFFAREA 0.445500 ;
    PORT
      LAYER met3 ;
        RECT 0.000 1210.440 4.000 1211.040 ;
    END
  END tl_host_o[48]
  PIN tl_host_o[49]
    DIRECTION OUTPUT ;
    USE SIGNAL ;
    ANTENNADIFFAREA 0.445500 ;
    PORT
      LAYER met2 ;
        RECT 1172.170 1296.000 1172.450 1300.000 ;
    END
  END tl_host_o[49]
  PIN tl_host_o[4]
    DIRECTION OUTPUT ;
    USE SIGNAL ;
    ANTENNADIFFAREA 0.445500 ;
    PORT
      LAYER met2 ;
        RECT 788.990 0.000 789.270 4.000 ;
    END
  END tl_host_o[4]
  PIN tl_host_o[50]
    DIRECTION OUTPUT ;
    USE SIGNAL ;
    ANTENNADIFFAREA 0.445500 ;
    PORT
      LAYER met3 ;
        RECT 0.000 1268.240 4.000 1268.840 ;
    END
  END tl_host_o[50]
  PIN tl_host_o[51]
    DIRECTION OUTPUT ;
    USE SIGNAL ;
    ANTENNADIFFAREA 0.445500 ;
    PORT
      LAYER met2 ;
        RECT 779.330 1296.000 779.610 1300.000 ;
    END
  END tl_host_o[51]
  PIN tl_host_o[52]
    DIRECTION OUTPUT ;
    USE SIGNAL ;
    ANTENNADIFFAREA 0.445500 ;
    PORT
      LAYER met2 ;
        RECT 1049.810 1296.000 1050.090 1300.000 ;
    END
  END tl_host_o[52]
  PIN tl_host_o[53]
    DIRECTION OUTPUT ;
    USE SIGNAL ;
    ANTENNADIFFAREA 0.445500 ;
    PORT
      LAYER met3 ;
        RECT 0.000 1264.840 4.000 1265.440 ;
    END
  END tl_host_o[53]
  PIN tl_host_o[54]
    DIRECTION OUTPUT ;
    USE SIGNAL ;
    ANTENNADIFFAREA 0.445500 ;
    PORT
      LAYER met2 ;
        RECT 760.010 0.000 760.290 4.000 ;
    END
  END tl_host_o[54]
  PIN tl_host_o[55]
    DIRECTION OUTPUT ;
    USE SIGNAL ;
    ANTENNADIFFAREA 0.445500 ;
    PORT
      LAYER met2 ;
        RECT 795.430 0.000 795.710 4.000 ;
    END
  END tl_host_o[55]
  PIN tl_host_o[56]
    DIRECTION OUTPUT ;
    USE SIGNAL ;
    ANTENNADIFFAREA 0.445500 ;
    PORT
      LAYER met3 ;
        RECT 0.000 765.040 4.000 765.640 ;
    END
  END tl_host_o[56]
  PIN tl_host_o[57]
    DIRECTION OUTPUT ;
    USE SIGNAL ;
    ANTENNADIFFAREA 0.445500 ;
    PORT
      LAYER met2 ;
        RECT 711.710 0.000 711.990 4.000 ;
    END
  END tl_host_o[57]
  PIN tl_host_o[58]
    DIRECTION OUTPUT ;
    USE SIGNAL ;
    ANTENNADIFFAREA 0.445500 ;
    PORT
      LAYER met2 ;
        RECT 837.290 1296.000 837.570 1300.000 ;
    END
  END tl_host_o[58]
  PIN tl_host_o[59]
    DIRECTION OUTPUT ;
    USE SIGNAL ;
    ANTENNADIFFAREA 0.445500 ;
    PORT
      LAYER met2 ;
        RECT 1194.710 1296.000 1194.990 1300.000 ;
    END
  END tl_host_o[59]
  PIN tl_host_o[5]
    DIRECTION OUTPUT ;
    USE SIGNAL ;
    ANTENNADIFFAREA 0.445500 ;
    PORT
      LAYER met2 ;
        RECT 866.270 1296.000 866.550 1300.000 ;
    END
  END tl_host_o[5]
  PIN tl_host_o[60]
    DIRECTION OUTPUT ;
    USE SIGNAL ;
    ANTENNADIFFAREA 0.445500 ;
    PORT
      LAYER met3 ;
        RECT 0.000 785.440 4.000 786.040 ;
    END
  END tl_host_o[60]
  PIN tl_host_o[61]
    DIRECTION OUTPUT ;
    USE SIGNAL ;
    ANTENNADIFFAREA 0.445500 ;
    PORT
      LAYER met2 ;
        RECT 1001.510 1296.000 1001.790 1300.000 ;
    END
  END tl_host_o[61]
  PIN tl_host_o[62]
    DIRECTION OUTPUT ;
    USE SIGNAL ;
    ANTENNADIFFAREA 0.445500 ;
    PORT
      LAYER met2 ;
        RECT 834.070 1296.000 834.350 1300.000 ;
    END
  END tl_host_o[62]
  PIN tl_host_o[63]
    DIRECTION OUTPUT ;
    USE SIGNAL ;
    ANTENNADIFFAREA 0.445500 ;
    PORT
      LAYER met2 ;
        RECT 656.970 1296.000 657.250 1300.000 ;
    END
  END tl_host_o[63]
  PIN tl_host_o[64]
    DIRECTION OUTPUT ;
    USE SIGNAL ;
    ANTENNADIFFAREA 0.445500 ;
    PORT
      LAYER met2 ;
        RECT 1130.310 1296.000 1130.590 1300.000 ;
    END
  END tl_host_o[64]
  PIN tl_host_o[65]
    DIRECTION OUTPUT ;
    USE SIGNAL ;
    ANTENNADIFFAREA 0.445500 ;
    PORT
      LAYER met2 ;
        RECT 898.470 1296.000 898.750 1300.000 ;
    END
  END tl_host_o[65]
  PIN tl_host_o[6]
    DIRECTION OUTPUT ;
    USE SIGNAL ;
    ANTENNADIFFAREA 0.445500 ;
    PORT
      LAYER met2 ;
        RECT 1085.230 1296.000 1085.510 1300.000 ;
    END
  END tl_host_o[6]
  PIN tl_host_o[7]
    DIRECTION OUTPUT ;
    USE SIGNAL ;
    ANTENNADIFFAREA 0.445500 ;
    PORT
      LAYER met2 ;
        RECT 1249.450 1296.000 1249.730 1300.000 ;
    END
  END tl_host_o[7]
  PIN tl_host_o[8]
    DIRECTION OUTPUT ;
    USE SIGNAL ;
    ANTENNADIFFAREA 0.445500 ;
    PORT
      LAYER met2 ;
        RECT 866.270 0.000 866.550 4.000 ;
    END
  END tl_host_o[8]
  PIN tl_host_o[9]
    DIRECTION OUTPUT ;
    USE SIGNAL ;
    ANTENNADIFFAREA 0.445500 ;
    PORT
      LAYER met2 ;
        RECT 1265.550 1296.000 1265.830 1300.000 ;
    END
  END tl_host_o[9]
  PIN tl_u_dm_i[0]
    DIRECTION INPUT ;
    USE SIGNAL ;
    ANTENNAGATEAREA 0.593700 ;
    ANTENNADIFFAREA 0.434700 ;
    PORT
      LAYER met2 ;
        RECT 338.190 0.000 338.470 4.000 ;
    END
  END tl_u_dm_i[0]
  PIN tl_u_dm_i[10]
    DIRECTION INPUT ;
    USE SIGNAL ;
    ANTENNAGATEAREA 0.647700 ;
    ANTENNADIFFAREA 0.434700 ;
    PORT
      LAYER met3 ;
        RECT 0.000 809.240 4.000 809.840 ;
    END
  END tl_u_dm_i[10]
  PIN tl_u_dm_i[11]
    DIRECTION INPUT ;
    USE SIGNAL ;
    ANTENNAGATEAREA 0.560700 ;
    ANTENNADIFFAREA 0.434700 ;
    PORT
      LAYER met2 ;
        RECT 669.850 0.000 670.130 4.000 ;
    END
  END tl_u_dm_i[11]
  PIN tl_u_dm_i[12]
    DIRECTION INPUT ;
    USE SIGNAL ;
    ANTENNAGATEAREA 0.560700 ;
    ANTENNADIFFAREA 0.434700 ;
    PORT
      LAYER met2 ;
        RECT 863.050 1296.000 863.330 1300.000 ;
    END
  END tl_u_dm_i[12]
  PIN tl_u_dm_i[13]
    DIRECTION INPUT ;
    USE SIGNAL ;
    ANTENNAGATEAREA 0.682200 ;
    ANTENNADIFFAREA 0.434700 ;
    PORT
      LAYER met2 ;
        RECT 734.250 0.000 734.530 4.000 ;
    END
  END tl_u_dm_i[13]
  PIN tl_u_dm_i[14]
    DIRECTION INPUT ;
    USE SIGNAL ;
    ANTENNAGATEAREA 0.631200 ;
    ANTENNADIFFAREA 0.434700 ;
    PORT
      LAYER met3 ;
        RECT 0.000 1254.640 4.000 1255.240 ;
    END
  END tl_u_dm_i[14]
  PIN tl_u_dm_i[15]
    DIRECTION INPUT ;
    USE SIGNAL ;
    ANTENNAGATEAREA 0.560700 ;
    ANTENNADIFFAREA 0.434700 ;
    PORT
      LAYER met2 ;
        RECT 1236.570 0.000 1236.850 4.000 ;
    END
  END tl_u_dm_i[15]
  PIN tl_u_dm_i[16]
    DIRECTION INPUT ;
    USE SIGNAL ;
    ANTENNAGATEAREA 0.631200 ;
    ANTENNADIFFAREA 0.434700 ;
    PORT
      LAYER met2 ;
        RECT 1175.390 1296.000 1175.670 1300.000 ;
    END
  END tl_u_dm_i[16]
  PIN tl_u_dm_i[17]
    DIRECTION INPUT ;
    USE SIGNAL ;
    ANTENNAGATEAREA 0.631200 ;
    ANTENNADIFFAREA 0.434700 ;
    PORT
      LAYER met2 ;
        RECT 985.410 1296.000 985.690 1300.000 ;
    END
  END tl_u_dm_i[17]
  PIN tl_u_dm_i[18]
    DIRECTION INPUT ;
    USE SIGNAL ;
    ANTENNAGATEAREA 0.631200 ;
    ANTENNADIFFAREA 0.434700 ;
    PORT
      LAYER met2 ;
        RECT 1075.570 0.000 1075.850 4.000 ;
    END
  END tl_u_dm_i[18]
  PIN tl_u_dm_i[19]
    DIRECTION INPUT ;
    USE SIGNAL ;
    ANTENNAGATEAREA 0.560700 ;
    ANTENNADIFFAREA 0.434700 ;
    PORT
      LAYER met2 ;
        RECT 1246.230 1296.000 1246.510 1300.000 ;
    END
  END tl_u_dm_i[19]
  PIN tl_u_dm_i[1]
    DIRECTION INPUT ;
    USE SIGNAL ;
    ANTENNAGATEAREA 0.647700 ;
    ANTENNADIFFAREA 0.434700 ;
    PORT
      LAYER met2 ;
        RECT 792.210 1296.000 792.490 1300.000 ;
    END
  END tl_u_dm_i[1]
  PIN tl_u_dm_i[20]
    DIRECTION INPUT ;
    USE SIGNAL ;
    ANTENNAGATEAREA 0.560700 ;
    ANTENNADIFFAREA 0.434700 ;
    PORT
      LAYER met2 ;
        RECT 946.770 0.000 947.050 4.000 ;
    END
  END tl_u_dm_i[20]
  PIN tl_u_dm_i[21]
    DIRECTION INPUT ;
    USE SIGNAL ;
    ANTENNAGATEAREA 0.560700 ;
    ANTENNADIFFAREA 0.434700 ;
    PORT
      LAYER met2 ;
        RECT 721.370 0.000 721.650 4.000 ;
    END
  END tl_u_dm_i[21]
  PIN tl_u_dm_i[22]
    DIRECTION INPUT ;
    USE SIGNAL ;
    ANTENNAGATEAREA 0.631200 ;
    ANTENNADIFFAREA 0.434700 ;
    PORT
      LAYER met3 ;
        RECT 0.000 1295.440 4.000 1296.040 ;
    END
  END tl_u_dm_i[22]
  PIN tl_u_dm_i[23]
    DIRECTION INPUT ;
    USE SIGNAL ;
    ANTENNAGATEAREA 0.631200 ;
    ANTENNADIFFAREA 0.434700 ;
    PORT
      LAYER met2 ;
        RECT 840.510 1296.000 840.790 1300.000 ;
    END
  END tl_u_dm_i[23]
  PIN tl_u_dm_i[24]
    DIRECTION INPUT ;
    USE SIGNAL ;
    ANTENNAGATEAREA 0.593700 ;
    ANTENNADIFFAREA 0.434700 ;
    PORT
      LAYER met2 ;
        RECT 1268.770 1296.000 1269.050 1300.000 ;
    END
  END tl_u_dm_i[24]
  PIN tl_u_dm_i[25]
    DIRECTION INPUT ;
    USE SIGNAL ;
    ANTENNAGATEAREA 0.560700 ;
    ANTENNADIFFAREA 0.434700 ;
    PORT
      LAYER met2 ;
        RECT 1014.390 1296.000 1014.670 1300.000 ;
    END
  END tl_u_dm_i[25]
  PIN tl_u_dm_i[26]
    DIRECTION INPUT ;
    USE SIGNAL ;
    ANTENNAGATEAREA 0.593700 ;
    ANTENNADIFFAREA 0.434700 ;
    PORT
      LAYER met2 ;
        RECT 798.650 1296.000 798.930 1300.000 ;
    END
  END tl_u_dm_i[26]
  PIN tl_u_dm_i[27]
    DIRECTION INPUT ;
    USE SIGNAL ;
    ANTENNAGATEAREA 0.647700 ;
    ANTENNADIFFAREA 0.434700 ;
    PORT
      LAYER met2 ;
        RECT 1214.030 0.000 1214.310 4.000 ;
    END
  END tl_u_dm_i[27]
  PIN tl_u_dm_i[28]
    DIRECTION INPUT ;
    USE SIGNAL ;
    ANTENNAGATEAREA 0.682200 ;
    ANTENNADIFFAREA 0.434700 ;
    PORT
      LAYER met2 ;
        RECT 1175.390 0.000 1175.670 4.000 ;
    END
  END tl_u_dm_i[28]
  PIN tl_u_dm_i[29]
    DIRECTION INPUT ;
    USE SIGNAL ;
    ANTENNAGATEAREA 0.631200 ;
    ANTENNADIFFAREA 0.434700 ;
    PORT
      LAYER met2 ;
        RECT 988.630 1296.000 988.910 1300.000 ;
    END
  END tl_u_dm_i[29]
  PIN tl_u_dm_i[2]
    DIRECTION INPUT ;
    USE SIGNAL ;
    ANTENNAGATEAREA 0.560700 ;
    ANTENNADIFFAREA 0.434700 ;
    PORT
      LAYER met2 ;
        RECT 808.310 1296.000 808.590 1300.000 ;
    END
  END tl_u_dm_i[2]
  PIN tl_u_dm_i[30]
    DIRECTION INPUT ;
    USE SIGNAL ;
    ANTENNAGATEAREA 0.560700 ;
    ANTENNADIFFAREA 0.434700 ;
    PORT
      LAYER met2 ;
        RECT 772.890 0.000 773.170 4.000 ;
    END
  END tl_u_dm_i[30]
  PIN tl_u_dm_i[31]
    DIRECTION INPUT ;
    USE SIGNAL ;
    ANTENNAGATEAREA 0.929700 ;
    ANTENNADIFFAREA 0.434700 ;
    PORT
      LAYER met2 ;
        RECT 1226.910 1296.000 1227.190 1300.000 ;
    END
  END tl_u_dm_i[31]
  PIN tl_u_dm_i[32]
    DIRECTION INPUT ;
    USE SIGNAL ;
    ANTENNAGATEAREA 0.593700 ;
    ANTENNADIFFAREA 0.434700 ;
    PORT
      LAYER met2 ;
        RECT 853.390 0.000 853.670 4.000 ;
    END
  END tl_u_dm_i[32]
  PIN tl_u_dm_i[33]
    DIRECTION INPUT ;
    USE SIGNAL ;
    ANTENNAGATEAREA 0.647700 ;
    ANTENNADIFFAREA 0.434700 ;
    PORT
      LAYER met2 ;
        RECT 1271.990 1296.000 1272.270 1300.000 ;
    END
  END tl_u_dm_i[33]
  PIN tl_u_dm_i[34]
    DIRECTION INPUT ;
    USE SIGNAL ;
    ANTENNAGATEAREA 0.647700 ;
    ANTENNADIFFAREA 0.434700 ;
    PORT
      LAYER met2 ;
        RECT 1181.830 1296.000 1182.110 1300.000 ;
    END
  END tl_u_dm_i[34]
  PIN tl_u_dm_i[35]
    DIRECTION INPUT ;
    USE SIGNAL ;
    ANTENNAGATEAREA 0.647700 ;
    ANTENNADIFFAREA 0.434700 ;
    PORT
      LAYER met2 ;
        RECT 753.570 1296.000 753.850 1300.000 ;
    END
  END tl_u_dm_i[35]
  PIN tl_u_dm_i[36]
    DIRECTION INPUT ;
    USE SIGNAL ;
    ANTENNAGATEAREA 0.647700 ;
    ANTENNADIFFAREA 0.434700 ;
    PORT
      LAYER met2 ;
        RECT 1123.870 1296.000 1124.150 1300.000 ;
    END
  END tl_u_dm_i[36]
  PIN tl_u_dm_i[37]
    DIRECTION INPUT ;
    USE SIGNAL ;
    ANTENNAGATEAREA 0.647700 ;
    ANTENNADIFFAREA 0.434700 ;
    PORT
      LAYER met2 ;
        RECT 901.690 0.000 901.970 4.000 ;
    END
  END tl_u_dm_i[37]
  PIN tl_u_dm_i[38]
    DIRECTION INPUT ;
    USE SIGNAL ;
    ANTENNAGATEAREA 0.647700 ;
    ANTENNADIFFAREA 0.434700 ;
    PORT
      LAYER met3 ;
        RECT 0.000 751.440 4.000 752.040 ;
    END
  END tl_u_dm_i[38]
  PIN tl_u_dm_i[39]
    DIRECTION INPUT ;
    USE SIGNAL ;
    ANTENNAGATEAREA 0.647700 ;
    ANTENNADIFFAREA 0.434700 ;
    PORT
      LAYER met2 ;
        RECT 985.410 0.000 985.690 4.000 ;
    END
  END tl_u_dm_i[39]
  PIN tl_u_dm_i[3]
    DIRECTION INPUT ;
    USE SIGNAL ;
    ANTENNAGATEAREA 0.560700 ;
    ANTENNADIFFAREA 0.434700 ;
    PORT
      LAYER met2 ;
        RECT 879.150 1296.000 879.430 1300.000 ;
    END
  END tl_u_dm_i[3]
  PIN tl_u_dm_i[40]
    DIRECTION INPUT ;
    USE SIGNAL ;
    ANTENNAGATEAREA 0.647700 ;
    ANTENNADIFFAREA 0.434700 ;
    PORT
      LAYER met2 ;
        RECT 908.130 1296.000 908.410 1300.000 ;
    END
  END tl_u_dm_i[40]
  PIN tl_u_dm_i[41]
    DIRECTION INPUT ;
    USE SIGNAL ;
    ANTENNAGATEAREA 0.647700 ;
    ANTENNADIFFAREA 0.434700 ;
    PORT
      LAYER met2 ;
        RECT 827.630 1296.000 827.910 1300.000 ;
    END
  END tl_u_dm_i[41]
  PIN tl_u_dm_i[42]
    DIRECTION INPUT ;
    USE SIGNAL ;
    ANTENNAGATEAREA 0.593700 ;
    ANTENNADIFFAREA 0.434700 ;
    PORT
      LAYER met2 ;
        RECT 1217.250 1296.000 1217.530 1300.000 ;
    END
  END tl_u_dm_i[42]
  PIN tl_u_dm_i[43]
    DIRECTION INPUT ;
    USE SIGNAL ;
    ANTENNAGATEAREA 0.631200 ;
    ANTENNADIFFAREA 0.434700 ;
    PORT
      LAYER met2 ;
        RECT 1194.710 0.000 1194.990 4.000 ;
    END
  END tl_u_dm_i[43]
  PIN tl_u_dm_i[44]
    DIRECTION INPUT ;
    USE SIGNAL ;
    ANTENNAGATEAREA 0.631200 ;
    ANTENNADIFFAREA 0.434700 ;
    PORT
      LAYER met2 ;
        RECT 1004.730 1296.000 1005.010 1300.000 ;
    END
  END tl_u_dm_i[44]
  PIN tl_u_dm_i[45]
    DIRECTION INPUT ;
    USE SIGNAL ;
    ANTENNAGATEAREA 0.647700 ;
    ANTENNADIFFAREA 0.434700 ;
    PORT
      LAYER met2 ;
        RECT 1082.010 1296.000 1082.290 1300.000 ;
    END
  END tl_u_dm_i[45]
  PIN tl_u_dm_i[46]
    DIRECTION INPUT ;
    USE SIGNAL ;
    ANTENNAGATEAREA 0.560700 ;
    ANTENNADIFFAREA 0.434700 ;
    PORT
      LAYER met2 ;
        RECT 1114.210 1296.000 1114.490 1300.000 ;
    END
  END tl_u_dm_i[46]
  PIN tl_u_dm_i[47]
    DIRECTION INPUT ;
    USE SIGNAL ;
    ANTENNAGATEAREA 0.631200 ;
    ANTENNADIFFAREA 0.434700 ;
    PORT
      LAYER met2 ;
        RECT 846.950 1296.000 847.230 1300.000 ;
    END
  END tl_u_dm_i[47]
  PIN tl_u_dm_i[48]
    DIRECTION INPUT ;
    USE SIGNAL ;
    ANTENNAGATEAREA 0.647700 ;
    ANTENNADIFFAREA 0.434700 ;
    PORT
      LAYER met3 ;
        RECT 0.000 941.840 4.000 942.440 ;
    END
  END tl_u_dm_i[48]
  PIN tl_u_dm_i[49]
    DIRECTION INPUT ;
    USE SIGNAL ;
    ANTENNAGATEAREA 0.560700 ;
    ANTENNADIFFAREA 0.434700 ;
    PORT
      LAYER met2 ;
        RECT 1281.650 1296.000 1281.930 1300.000 ;
    END
  END tl_u_dm_i[49]
  PIN tl_u_dm_i[4]
    DIRECTION INPUT ;
    USE SIGNAL ;
    ANTENNAGATEAREA 0.560700 ;
    ANTENNADIFFAREA 0.434700 ;
    PORT
      LAYER met2 ;
        RECT 830.850 0.000 831.130 4.000 ;
    END
  END tl_u_dm_i[4]
  PIN tl_u_dm_i[50]
    DIRECTION INPUT ;
    USE SIGNAL ;
    ANTENNAGATEAREA 1.177200 ;
    ANTENNADIFFAREA 0.434700 ;
    PORT
      LAYER met2 ;
        RECT 650.530 0.000 650.810 4.000 ;
    END
  END tl_u_dm_i[50]
  PIN tl_u_dm_i[51]
    DIRECTION INPUT ;
    USE SIGNAL ;
    ANTENNAGATEAREA 0.647700 ;
    ANTENNADIFFAREA 0.434700 ;
    PORT
      LAYER met2 ;
        RECT 1185.050 1296.000 1185.330 1300.000 ;
    END
  END tl_u_dm_i[51]
  PIN tl_u_dm_i[52]
    DIRECTION INPUT ;
    USE SIGNAL ;
    ANTENNAGATEAREA 0.631200 ;
    ANTENNADIFFAREA 0.434700 ;
    PORT
      LAYER met2 ;
        RECT 959.650 1296.000 959.930 1300.000 ;
    END
  END tl_u_dm_i[52]
  PIN tl_u_dm_i[53]
    DIRECTION INPUT ;
    USE SIGNAL ;
    ANTENNAGATEAREA 0.682200 ;
    ANTENNADIFFAREA 0.434700 ;
    PORT
      LAYER met3 ;
        RECT 0.000 792.240 4.000 792.840 ;
    END
  END tl_u_dm_i[53]
  PIN tl_u_dm_i[54]
    DIRECTION INPUT ;
    USE SIGNAL ;
    ANTENNAGATEAREA 0.631200 ;
    ANTENNADIFFAREA 0.434700 ;
    PORT
      LAYER met2 ;
        RECT 956.430 0.000 956.710 4.000 ;
    END
  END tl_u_dm_i[54]
  PIN tl_u_dm_i[55]
    DIRECTION INPUT ;
    USE SIGNAL ;
    ANTENNAGATEAREA 0.593700 ;
    ANTENNADIFFAREA 0.434700 ;
    PORT
      LAYER met2 ;
        RECT 966.090 0.000 966.370 4.000 ;
    END
  END tl_u_dm_i[55]
  PIN tl_u_dm_i[56]
    DIRECTION INPUT ;
    USE SIGNAL ;
    ANTENNAGATEAREA 0.560700 ;
    ANTENNADIFFAREA 0.434700 ;
    PORT
      LAYER met3 ;
        RECT 0.000 856.840 4.000 857.440 ;
    END
  END tl_u_dm_i[56]
  PIN tl_u_dm_i[57]
    DIRECTION INPUT ;
    USE SIGNAL ;
    ANTENNAGATEAREA 0.647700 ;
    ANTENNADIFFAREA 0.434700 ;
    PORT
      LAYER met2 ;
        RECT 705.270 0.000 705.550 4.000 ;
    END
  END tl_u_dm_i[57]
  PIN tl_u_dm_i[58]
    DIRECTION INPUT ;
    USE SIGNAL ;
    ANTENNAGATEAREA 0.631200 ;
    ANTENNADIFFAREA 0.434700 ;
    PORT
      LAYER met2 ;
        RECT 1072.350 1296.000 1072.630 1300.000 ;
    END
  END tl_u_dm_i[58]
  PIN tl_u_dm_i[59]
    DIRECTION INPUT ;
    USE SIGNAL ;
    ANTENNAGATEAREA 0.593700 ;
    ANTENNADIFFAREA 0.434700 ;
    PORT
      LAYER met2 ;
        RECT 1188.270 1296.000 1188.550 1300.000 ;
    END
  END tl_u_dm_i[59]
  PIN tl_u_dm_i[5]
    DIRECTION INPUT ;
    USE SIGNAL ;
    ANTENNAGATEAREA 0.631200 ;
    ANTENNADIFFAREA 0.434700 ;
    PORT
      LAYER met2 ;
        RECT 1204.370 1296.000 1204.650 1300.000 ;
    END
  END tl_u_dm_i[5]
  PIN tl_u_dm_i[60]
    DIRECTION INPUT ;
    USE SIGNAL ;
    ANTENNAGATEAREA 0.631200 ;
    ANTENNADIFFAREA 0.434700 ;
    PORT
      LAYER met3 ;
        RECT 0.000 935.040 4.000 935.640 ;
    END
  END tl_u_dm_i[60]
  PIN tl_u_dm_i[61]
    DIRECTION INPUT ;
    USE SIGNAL ;
    ANTENNAGATEAREA 0.647700 ;
    ANTENNADIFFAREA 0.434700 ;
    PORT
      LAYER met2 ;
        RECT 1284.870 1296.000 1285.150 1300.000 ;
    END
  END tl_u_dm_i[61]
  PIN tl_u_dm_i[62]
    DIRECTION INPUT ;
    USE SIGNAL ;
    ANTENNAGATEAREA 0.631200 ;
    ANTENNADIFFAREA 0.434700 ;
    PORT
      LAYER met2 ;
        RECT 1139.970 1296.000 1140.250 1300.000 ;
    END
  END tl_u_dm_i[62]
  PIN tl_u_dm_i[63]
    DIRECTION INPUT ;
    USE SIGNAL ;
    ANTENNAGATEAREA 0.631200 ;
    ANTENNADIFFAREA 0.434700 ;
    PORT
      LAYER met2 ;
        RECT 660.190 1296.000 660.470 1300.000 ;
    END
  END tl_u_dm_i[63]
  PIN tl_u_dm_i[64]
    DIRECTION INPUT ;
    USE SIGNAL ;
    ANTENNAGATEAREA 0.647700 ;
    ANTENNADIFFAREA 0.434700 ;
    PORT
      LAYER met2 ;
        RECT 811.530 1296.000 811.810 1300.000 ;
    END
  END tl_u_dm_i[64]
  PIN tl_u_dm_i[65]
    DIRECTION INPUT ;
    USE SIGNAL ;
    ANTENNAGATEAREA 0.631200 ;
    ANTENNADIFFAREA 0.434700 ;
    PORT
      LAYER met2 ;
        RECT 1297.750 1296.000 1298.030 1300.000 ;
    END
  END tl_u_dm_i[65]
  PIN tl_u_dm_i[6]
    DIRECTION INPUT ;
    USE SIGNAL ;
    ANTENNAGATEAREA 0.631200 ;
    ANTENNADIFFAREA 0.434700 ;
    PORT
      LAYER met2 ;
        RECT 1017.610 1296.000 1017.890 1300.000 ;
    END
  END tl_u_dm_i[6]
  PIN tl_u_dm_i[7]
    DIRECTION INPUT ;
    USE SIGNAL ;
    ANTENNAGATEAREA 0.631200 ;
    ANTENNADIFFAREA 0.434700 ;
    PORT
      LAYER met2 ;
        RECT 1278.430 1296.000 1278.710 1300.000 ;
    END
  END tl_u_dm_i[7]
  PIN tl_u_dm_i[8]
    DIRECTION INPUT ;
    USE SIGNAL ;
    ANTENNAGATEAREA 0.560700 ;
    ANTENNADIFFAREA 0.434700 ;
    PORT
      LAYER met2 ;
        RECT 695.610 0.000 695.890 4.000 ;
    END
  END tl_u_dm_i[8]
  PIN tl_u_dm_i[9]
    DIRECTION INPUT ;
    USE SIGNAL ;
    ANTENNAGATEAREA 0.560700 ;
    ANTENNADIFFAREA 0.434700 ;
    PORT
      LAYER met2 ;
        RECT 1262.330 1296.000 1262.610 1300.000 ;
    END
  END tl_u_dm_i[9]
  PIN tl_u_dm_o[0]
    DIRECTION OUTPUT ;
    USE SIGNAL ;
    ANTENNADIFFAREA 0.445500 ;
    PORT
      LAYER met3 ;
        RECT 0.000 1091.440 4.000 1092.040 ;
    END
  END tl_u_dm_o[0]
  PIN tl_u_dm_o[100]
    DIRECTION OUTPUT ;
    USE SIGNAL ;
    ANTENNADIFFAREA 0.445500 ;
    PORT
      LAYER met3 ;
        RECT 0.000 948.640 4.000 949.240 ;
    END
  END tl_u_dm_o[100]
  PIN tl_u_dm_o[101]
    DIRECTION OUTPUT ;
    USE SIGNAL ;
    ANTENNADIFFAREA 0.445500 ;
    PORT
      LAYER met2 ;
        RECT 885.590 0.000 885.870 4.000 ;
    END
  END tl_u_dm_o[101]
  PIN tl_u_dm_o[102]
    DIRECTION OUTPUT ;
    USE SIGNAL ;
    ANTENNADIFFAREA 0.445500 ;
    PORT
      LAYER met3 ;
        RECT 0.000 778.640 4.000 779.240 ;
    END
  END tl_u_dm_o[102]
  PIN tl_u_dm_o[103]
    DIRECTION OUTPUT ;
    USE SIGNAL ;
    ANTENNADIFFAREA 0.445500 ;
    PORT
      LAYER met2 ;
        RECT 911.350 0.000 911.630 4.000 ;
    END
  END tl_u_dm_o[103]
  PIN tl_u_dm_o[104]
    DIRECTION OUTPUT ;
    USE SIGNAL ;
    ANTENNADIFFAREA 0.445500 ;
    PORT
      LAYER met2 ;
        RECT 978.970 0.000 979.250 4.000 ;
    END
  END tl_u_dm_o[104]
  PIN tl_u_dm_o[105]
    DIRECTION OUTPUT ;
    USE SIGNAL ;
    ANTENNADIFFAREA 0.445500 ;
    PORT
      LAYER met2 ;
        RECT 277.010 0.000 277.290 4.000 ;
    END
  END tl_u_dm_o[105]
  PIN tl_u_dm_o[106]
    DIRECTION OUTPUT ;
    USE SIGNAL ;
    ANTENNADIFFAREA 0.445500 ;
    PORT
      LAYER met2 ;
        RECT 35.510 0.000 35.790 4.000 ;
    END
  END tl_u_dm_o[106]
  PIN tl_u_dm_o[107]
    DIRECTION OUTPUT ;
    USE SIGNAL ;
    ANTENNADIFFAREA 0.445500 ;
    PORT
      LAYER met3 ;
        RECT 0.000 1081.240 4.000 1081.840 ;
    END
  END tl_u_dm_o[107]
  PIN tl_u_dm_o[108]
    DIRECTION OUTPUT ;
    USE SIGNAL ;
    ANTENNADIFFAREA 0.445500 ;
    PORT
      LAYER met2 ;
        RECT 560.370 0.000 560.650 4.000 ;
    END
  END tl_u_dm_o[108]
  PIN tl_u_dm_o[109]
    DIRECTION OUTPUT ;
    USE SIGNAL ;
    ANTENNADIFFAREA 0.445500 ;
    PORT
      LAYER met2 ;
        RECT 312.430 0.000 312.710 4.000 ;
    END
  END tl_u_dm_o[109]
  PIN tl_u_dm_o[10]
    DIRECTION OUTPUT ;
    USE SIGNAL ;
    ANTENNADIFFAREA 0.445500 ;
    PORT
      LAYER met2 ;
        RECT 119.230 0.000 119.510 4.000 ;
    END
  END tl_u_dm_o[10]
  PIN tl_u_dm_o[11]
    DIRECTION OUTPUT ;
    USE SIGNAL ;
    ANTENNADIFFAREA 0.445500 ;
    PORT
      LAYER met2 ;
        RECT 1197.930 0.000 1198.210 4.000 ;
    END
  END tl_u_dm_o[11]
  PIN tl_u_dm_o[12]
    DIRECTION OUTPUT ;
    USE SIGNAL ;
    ANTENNADIFFAREA 0.445500 ;
    PORT
      LAYER met3 ;
        RECT 0.000 731.040 4.000 731.640 ;
    END
  END tl_u_dm_o[12]
  PIN tl_u_dm_o[13]
    DIRECTION OUTPUT ;
    USE SIGNAL ;
    ANTENNADIFFAREA 0.445500 ;
    PORT
      LAYER met2 ;
        RECT 927.450 1296.000 927.730 1300.000 ;
    END
  END tl_u_dm_o[13]
  PIN tl_u_dm_o[14]
    DIRECTION OUTPUT ;
    USE SIGNAL ;
    ANTENNADIFFAREA 0.445500 ;
    PORT
      LAYER met2 ;
        RECT 524.950 0.000 525.230 4.000 ;
    END
  END tl_u_dm_o[14]
  PIN tl_u_dm_o[15]
    DIRECTION OUTPUT ;
    USE SIGNAL ;
    ANTENNADIFFAREA 0.445500 ;
    PORT
      LAYER met2 ;
        RECT 521.730 0.000 522.010 4.000 ;
    END
  END tl_u_dm_o[15]
  PIN tl_u_dm_o[16]
    DIRECTION OUTPUT ;
    USE SIGNAL ;
    ANTENNADIFFAREA 0.445500 ;
    PORT
      LAYER met2 ;
        RECT 1207.590 0.000 1207.870 4.000 ;
    END
  END tl_u_dm_o[16]
  PIN tl_u_dm_o[17]
    DIRECTION OUTPUT ;
    USE SIGNAL ;
    ANTENNADIFFAREA 0.445500 ;
    PORT
      LAYER met2 ;
        RECT 1120.650 1296.000 1120.930 1300.000 ;
    END
  END tl_u_dm_o[17]
  PIN tl_u_dm_o[18]
    DIRECTION OUTPUT ;
    USE SIGNAL ;
    ANTENNADIFFAREA 0.445500 ;
    PORT
      LAYER met2 ;
        RECT 1091.670 1296.000 1091.950 1300.000 ;
    END
  END tl_u_dm_o[18]
  PIN tl_u_dm_o[19]
    DIRECTION OUTPUT ;
    USE SIGNAL ;
    ANTENNADIFFAREA 0.445500 ;
    PORT
      LAYER met3 ;
        RECT 0.000 669.840 4.000 670.440 ;
    END
  END tl_u_dm_o[19]
  PIN tl_u_dm_o[1]
    DIRECTION OUTPUT ;
    USE SIGNAL ;
    ANTENNADIFFAREA 0.445500 ;
    PORT
      LAYER met3 ;
        RECT 0.000 805.840 4.000 806.440 ;
    END
  END tl_u_dm_o[1]
  PIN tl_u_dm_o[20]
    DIRECTION OUTPUT ;
    USE SIGNAL ;
    ANTENNADIFFAREA 0.445500 ;
    PORT
      LAYER met2 ;
        RECT 164.310 0.000 164.590 4.000 ;
    END
  END tl_u_dm_o[20]
  PIN tl_u_dm_o[21]
    DIRECTION OUTPUT ;
    USE SIGNAL ;
    ANTENNADIFFAREA 0.445500 ;
    PORT
      LAYER met2 ;
        RECT 949.990 0.000 950.270 4.000 ;
    END
  END tl_u_dm_o[21]
  PIN tl_u_dm_o[22]
    DIRECTION OUTPUT ;
    USE SIGNAL ;
    ANTENNADIFFAREA 0.445500 ;
    PORT
      LAYER met2 ;
        RECT 1094.890 1296.000 1095.170 1300.000 ;
    END
  END tl_u_dm_o[22]
  PIN tl_u_dm_o[23]
    DIRECTION OUTPUT ;
    USE SIGNAL ;
    ANTENNADIFFAREA 0.445500 ;
    PORT
      LAYER met2 ;
        RECT 608.670 0.000 608.950 4.000 ;
    END
  END tl_u_dm_o[23]
  PIN tl_u_dm_o[24]
    DIRECTION OUTPUT ;
    USE SIGNAL ;
    ANTENNADIFFAREA 0.445500 ;
    PORT
      LAYER met3 ;
        RECT 0.000 1016.640 4.000 1017.240 ;
    END
  END tl_u_dm_o[24]
  PIN tl_u_dm_o[25]
    DIRECTION OUTPUT ;
    USE SIGNAL ;
    ANTENNADIFFAREA 0.445500 ;
    PORT
      LAYER met2 ;
        RECT 74.150 0.000 74.430 4.000 ;
    END
  END tl_u_dm_o[25]
  PIN tl_u_dm_o[26]
    DIRECTION OUTPUT ;
    USE SIGNAL ;
    ANTENNADIFFAREA 0.445500 ;
    PORT
      LAYER met3 ;
        RECT 0.000 890.840 4.000 891.440 ;
    END
  END tl_u_dm_o[26]
  PIN tl_u_dm_o[27]
    DIRECTION OUTPUT ;
    USE SIGNAL ;
    ANTENNADIFFAREA 0.445500 ;
    PORT
      LAYER met2 ;
        RECT 640.870 0.000 641.150 4.000 ;
    END
  END tl_u_dm_o[27]
  PIN tl_u_dm_o[28]
    DIRECTION OUTPUT ;
    USE SIGNAL ;
    ANTENNADIFFAREA 0.445500 ;
    PORT
      LAYER met2 ;
        RECT 1271.990 0.000 1272.270 4.000 ;
    END
  END tl_u_dm_o[28]
  PIN tl_u_dm_o[29]
    DIRECTION OUTPUT ;
    USE SIGNAL ;
    ANTENNADIFFAREA 0.445500 ;
    PORT
      LAYER met2 ;
        RECT 492.750 0.000 493.030 4.000 ;
    END
  END tl_u_dm_o[29]
  PIN tl_u_dm_o[2]
    DIRECTION OUTPUT ;
    USE SIGNAL ;
    ANTENNADIFFAREA 0.445500 ;
    PORT
      LAYER met3 ;
        RECT 0.000 782.040 4.000 782.640 ;
    END
  END tl_u_dm_o[2]
  PIN tl_u_dm_o[30]
    DIRECTION OUTPUT ;
    USE SIGNAL ;
    ANTENNADIFFAREA 0.445500 ;
    PORT
      LAYER met2 ;
        RECT 782.550 1296.000 782.830 1300.000 ;
    END
  END tl_u_dm_o[30]
  PIN tl_u_dm_o[31]
    DIRECTION OUTPUT ;
    USE SIGNAL ;
    ANTENNADIFFAREA 0.445500 ;
    PORT
      LAYER met2 ;
        RECT 1020.830 0.000 1021.110 4.000 ;
    END
  END tl_u_dm_o[31]
  PIN tl_u_dm_o[32]
    DIRECTION OUTPUT ;
    USE SIGNAL ;
    ANTENNADIFFAREA 0.445500 ;
    PORT
      LAYER met2 ;
        RECT 1127.090 0.000 1127.370 4.000 ;
    END
  END tl_u_dm_o[32]
  PIN tl_u_dm_o[33]
    DIRECTION OUTPUT ;
    USE SIGNAL ;
    ANTENNADIFFAREA 0.445500 ;
    PORT
      LAYER met2 ;
        RECT 624.770 0.000 625.050 4.000 ;
    END
  END tl_u_dm_o[33]
  PIN tl_u_dm_o[34]
    DIRECTION OUTPUT ;
    USE SIGNAL ;
    ANTENNADIFFAREA 0.445500 ;
    PORT
      LAYER met2 ;
        RECT 25.850 0.000 26.130 4.000 ;
    END
  END tl_u_dm_o[34]
  PIN tl_u_dm_o[35]
    DIRECTION OUTPUT ;
    USE SIGNAL ;
    ANTENNADIFFAREA 0.445500 ;
    PORT
      LAYER met2 ;
        RECT 908.130 0.000 908.410 4.000 ;
    END
  END tl_u_dm_o[35]
  PIN tl_u_dm_o[36]
    DIRECTION OUTPUT ;
    USE SIGNAL ;
    ANTENNADIFFAREA 0.445500 ;
    PORT
      LAYER met3 ;
        RECT 0.000 727.640 4.000 728.240 ;
    END
  END tl_u_dm_o[36]
  PIN tl_u_dm_o[37]
    DIRECTION OUTPUT ;
    USE SIGNAL ;
    ANTENNADIFFAREA 0.445500 ;
    PORT
      LAYER met2 ;
        RECT 940.330 0.000 940.610 4.000 ;
    END
  END tl_u_dm_o[37]
  PIN tl_u_dm_o[38]
    DIRECTION OUTPUT ;
    USE SIGNAL ;
    ANTENNADIFFAREA 0.445500 ;
    PORT
      LAYER met2 ;
        RECT 103.130 0.000 103.410 4.000 ;
    END
  END tl_u_dm_o[38]
  PIN tl_u_dm_o[39]
    DIRECTION OUTPUT ;
    USE SIGNAL ;
    ANTENNADIFFAREA 0.445500 ;
    PORT
      LAYER met2 ;
        RECT 724.590 0.000 724.870 4.000 ;
    END
  END tl_u_dm_o[39]
  PIN tl_u_dm_o[3]
    DIRECTION OUTPUT ;
    USE SIGNAL ;
    ANTENNADIFFAREA 0.445500 ;
    PORT
      LAYER met2 ;
        RECT 1098.110 0.000 1098.390 4.000 ;
    END
  END tl_u_dm_o[3]
  PIN tl_u_dm_o[40]
    DIRECTION OUTPUT ;
    USE SIGNAL ;
    ANTENNADIFFAREA 0.445500 ;
    PORT
      LAYER met3 ;
        RECT 0.000 1166.240 4.000 1166.840 ;
    END
  END tl_u_dm_o[40]
  PIN tl_u_dm_o[41]
    DIRECTION OUTPUT ;
    USE SIGNAL ;
    ANTENNADIFFAREA 0.445500 ;
    PORT
      LAYER met2 ;
        RECT 1017.610 0.000 1017.890 4.000 ;
    END
  END tl_u_dm_o[41]
  PIN tl_u_dm_o[42]
    DIRECTION OUTPUT ;
    USE SIGNAL ;
    ANTENNADIFFAREA 0.445500 ;
    PORT
      LAYER met2 ;
        RECT 969.310 0.000 969.590 4.000 ;
    END
  END tl_u_dm_o[42]
  PIN tl_u_dm_o[43]
    DIRECTION OUTPUT ;
    USE SIGNAL ;
    ANTENNADIFFAREA 0.445500 ;
    PORT
      LAYER met3 ;
        RECT 0.000 853.440 4.000 854.040 ;
    END
  END tl_u_dm_o[43]
  PIN tl_u_dm_o[44]
    DIRECTION OUTPUT ;
    USE SIGNAL ;
    ANTENNADIFFAREA 0.445500 ;
    PORT
      LAYER met3 ;
        RECT 0.000 1183.240 4.000 1183.840 ;
    END
  END tl_u_dm_o[44]
  PIN tl_u_dm_o[45]
    DIRECTION OUTPUT ;
    USE SIGNAL ;
    ANTENNADIFFAREA 0.445500 ;
    PORT
      LAYER met2 ;
        RECT 1049.810 0.000 1050.090 4.000 ;
    END
  END tl_u_dm_o[45]
  PIN tl_u_dm_o[46]
    DIRECTION OUTPUT ;
    USE SIGNAL ;
    ANTENNADIFFAREA 0.445500 ;
    PORT
      LAYER met2 ;
        RECT 692.390 1296.000 692.670 1300.000 ;
    END
  END tl_u_dm_o[46]
  PIN tl_u_dm_o[47]
    DIRECTION OUTPUT ;
    USE SIGNAL ;
    ANTENNADIFFAREA 0.445500 ;
    PORT
      LAYER met3 ;
        RECT 0.000 649.440 4.000 650.040 ;
    END
  END tl_u_dm_o[47]
  PIN tl_u_dm_o[48]
    DIRECTION OUTPUT ;
    USE SIGNAL ;
    ANTENNADIFFAREA 0.445500 ;
    PORT
      LAYER met3 ;
        RECT 0.000 1186.640 4.000 1187.240 ;
    END
  END tl_u_dm_o[48]
  PIN tl_u_dm_o[49]
    DIRECTION OUTPUT ;
    USE SIGNAL ;
    ANTENNADIFFAREA 0.445500 ;
    PORT
      LAYER met3 ;
        RECT 0.000 646.040 4.000 646.640 ;
    END
  END tl_u_dm_o[49]
  PIN tl_u_dm_o[4]
    DIRECTION OUTPUT ;
    USE SIGNAL ;
    ANTENNADIFFAREA 0.445500 ;
    PORT
      LAYER met2 ;
        RECT 1123.870 0.000 1124.150 4.000 ;
    END
  END tl_u_dm_o[4]
  PIN tl_u_dm_o[50]
    DIRECTION OUTPUT ;
    USE SIGNAL ;
    ANTENNADIFFAREA 0.445500 ;
    PORT
      LAYER met2 ;
        RECT 782.550 0.000 782.830 4.000 ;
    END
  END tl_u_dm_o[50]
  PIN tl_u_dm_o[51]
    DIRECTION OUTPUT ;
    USE SIGNAL ;
    ANTENNADIFFAREA 0.445500 ;
    PORT
      LAYER met3 ;
        RECT 0.000 676.640 4.000 677.240 ;
    END
  END tl_u_dm_o[51]
  PIN tl_u_dm_o[52]
    DIRECTION OUTPUT ;
    USE SIGNAL ;
    ANTENNADIFFAREA 0.445500 ;
    PORT
      LAYER met2 ;
        RECT 892.030 0.000 892.310 4.000 ;
    END
  END tl_u_dm_o[52]
  PIN tl_u_dm_o[53]
    DIRECTION OUTPUT ;
    USE SIGNAL ;
    ANTENNADIFFAREA 0.445500 ;
    PORT
      LAYER met2 ;
        RECT 1149.630 0.000 1149.910 4.000 ;
    END
  END tl_u_dm_o[53]
  PIN tl_u_dm_o[54]
    DIRECTION OUTPUT ;
    USE SIGNAL ;
    ANTENNADIFFAREA 0.445500 ;
    PORT
      LAYER met3 ;
        RECT 0.000 799.040 4.000 799.640 ;
    END
  END tl_u_dm_o[54]
  PIN tl_u_dm_o[55]
    DIRECTION OUTPUT ;
    USE SIGNAL ;
    ANTENNADIFFAREA 0.445500 ;
    PORT
      LAYER met3 ;
        RECT 0.000 822.840 4.000 823.440 ;
    END
  END tl_u_dm_o[55]
  PIN tl_u_dm_o[56]
    DIRECTION OUTPUT ;
    USE SIGNAL ;
    ANTENNADIFFAREA 0.445500 ;
    PORT
      LAYER met3 ;
        RECT 0.000 1271.640 4.000 1272.240 ;
    END
  END tl_u_dm_o[56]
  PIN tl_u_dm_o[57]
    DIRECTION OUTPUT ;
    USE SIGNAL ;
    ANTENNADIFFAREA 0.445500 ;
    PORT
      LAYER met3 ;
        RECT 0.000 894.240 4.000 894.840 ;
    END
  END tl_u_dm_o[57]
  PIN tl_u_dm_o[58]
    DIRECTION OUTPUT ;
    USE SIGNAL ;
    ANTENNADIFFAREA 0.445500 ;
    PORT
      LAYER met2 ;
        RECT 946.770 1296.000 947.050 1300.000 ;
    END
  END tl_u_dm_o[58]
  PIN tl_u_dm_o[59]
    DIRECTION OUTPUT ;
    USE SIGNAL ;
    ANTENNADIFFAREA 0.445500 ;
    PORT
      LAYER met2 ;
        RECT 1004.730 0.000 1005.010 4.000 ;
    END
  END tl_u_dm_o[59]
  PIN tl_u_dm_o[5]
    DIRECTION OUTPUT ;
    USE SIGNAL ;
    ANTENNADIFFAREA 0.445500 ;
    PORT
      LAYER met2 ;
        RECT 1294.530 1296.000 1294.810 1300.000 ;
    END
  END tl_u_dm_o[5]
  PIN tl_u_dm_o[60]
    DIRECTION OUTPUT ;
    USE SIGNAL ;
    ANTENNADIFFAREA 0.445500 ;
    PORT
      LAYER met2 ;
        RECT 1024.050 1296.000 1024.330 1300.000 ;
    END
  END tl_u_dm_o[60]
  PIN tl_u_dm_o[61]
    DIRECTION OUTPUT ;
    USE SIGNAL ;
    ANTENNADIFFAREA 0.445500 ;
    PORT
      LAYER met2 ;
        RECT 257.690 0.000 257.970 4.000 ;
    END
  END tl_u_dm_o[61]
  PIN tl_u_dm_o[62]
    DIRECTION OUTPUT ;
    USE SIGNAL ;
    ANTENNADIFFAREA 0.445500 ;
    PORT
      LAYER met2 ;
        RECT 347.850 0.000 348.130 4.000 ;
    END
  END tl_u_dm_o[62]
  PIN tl_u_dm_o[63]
    DIRECTION OUTPUT ;
    USE SIGNAL ;
    ANTENNADIFFAREA 0.445500 ;
    PORT
      LAYER met2 ;
        RECT 357.510 0.000 357.790 4.000 ;
    END
  END tl_u_dm_o[63]
  PIN tl_u_dm_o[64]
    DIRECTION OUTPUT ;
    USE SIGNAL ;
    ANTENNADIFFAREA 0.445500 ;
    PORT
      LAYER met2 ;
        RECT 392.930 0.000 393.210 4.000 ;
    END
  END tl_u_dm_o[64]
  PIN tl_u_dm_o[65]
    DIRECTION OUTPUT ;
    USE SIGNAL ;
    ANTENNADIFFAREA 0.445500 ;
    PORT
      LAYER met2 ;
        RECT 409.030 0.000 409.310 4.000 ;
    END
  END tl_u_dm_o[65]
  PIN tl_u_dm_o[66]
    DIRECTION OUTPUT ;
    USE SIGNAL ;
    ANTENNADIFFAREA 0.445500 ;
    PORT
      LAYER met2 ;
        RECT 547.490 0.000 547.770 4.000 ;
    END
  END tl_u_dm_o[66]
  PIN tl_u_dm_o[67]
    DIRECTION OUTPUT ;
    USE SIGNAL ;
    ANTENNADIFFAREA 0.445500 ;
    PORT
      LAYER met2 ;
        RECT 550.710 0.000 550.990 4.000 ;
    END
  END tl_u_dm_o[67]
  PIN tl_u_dm_o[68]
    DIRECTION OUTPUT ;
    USE SIGNAL ;
    ANTENNADIFFAREA 0.445500 ;
    PORT
      LAYER met2 ;
        RECT 457.330 0.000 457.610 4.000 ;
    END
  END tl_u_dm_o[68]
  PIN tl_u_dm_o[69]
    DIRECTION OUTPUT ;
    USE SIGNAL ;
    ANTENNADIFFAREA 0.445500 ;
    PORT
      LAYER met2 ;
        RECT 228.710 0.000 228.990 4.000 ;
    END
  END tl_u_dm_o[69]
  PIN tl_u_dm_o[6]
    DIRECTION OUTPUT ;
    USE SIGNAL ;
    ANTENNADIFFAREA 0.445500 ;
    PORT
      LAYER met3 ;
        RECT 0.000 836.440 4.000 837.040 ;
    END
  END tl_u_dm_o[6]
  PIN tl_u_dm_o[70]
    DIRECTION OUTPUT ;
    USE SIGNAL ;
    ANTENNADIFFAREA 0.445500 ;
    PORT
      LAYER met2 ;
        RECT 244.810 0.000 245.090 4.000 ;
    END
  END tl_u_dm_o[70]
  PIN tl_u_dm_o[71]
    DIRECTION OUTPUT ;
    USE SIGNAL ;
    ANTENNADIFFAREA 0.445500 ;
    PORT
      LAYER met2 ;
        RECT 363.950 0.000 364.230 4.000 ;
    END
  END tl_u_dm_o[71]
  PIN tl_u_dm_o[72]
    DIRECTION OUTPUT ;
    USE SIGNAL ;
    ANTENNADIFFAREA 0.445500 ;
    PORT
      LAYER met2 ;
        RECT 299.550 0.000 299.830 4.000 ;
    END
  END tl_u_dm_o[72]
  PIN tl_u_dm_o[73]
    DIRECTION OUTPUT ;
    USE SIGNAL ;
    ANTENNADIFFAREA 0.445500 ;
    PORT
      LAYER met2 ;
        RECT 354.290 0.000 354.570 4.000 ;
    END
  END tl_u_dm_o[73]
  PIN tl_u_dm_o[74]
    DIRECTION OUTPUT ;
    USE SIGNAL ;
    ANTENNADIFFAREA 0.445500 ;
    PORT
      LAYER met2 ;
        RECT 264.130 0.000 264.410 4.000 ;
    END
  END tl_u_dm_o[74]
  PIN tl_u_dm_o[75]
    DIRECTION OUTPUT ;
    USE SIGNAL ;
    ANTENNADIFFAREA 0.445500 ;
    PORT
      LAYER met2 ;
        RECT 360.730 0.000 361.010 4.000 ;
    END
  END tl_u_dm_o[75]
  PIN tl_u_dm_o[76]
    DIRECTION OUTPUT ;
    USE SIGNAL ;
    ANTENNADIFFAREA 0.445500 ;
    PORT
      LAYER met2 ;
        RECT 151.430 0.000 151.710 4.000 ;
    END
  END tl_u_dm_o[76]
  PIN tl_u_dm_o[77]
    DIRECTION OUTPUT ;
    USE SIGNAL ;
    ANTENNADIFFAREA 0.445500 ;
    PORT
      LAYER met2 ;
        RECT 170.750 0.000 171.030 4.000 ;
    END
  END tl_u_dm_o[77]
  PIN tl_u_dm_o[78]
    DIRECTION OUTPUT ;
    USE SIGNAL ;
    ANTENNADIFFAREA 0.445500 ;
    PORT
      LAYER met2 ;
        RECT 202.950 0.000 203.230 4.000 ;
    END
  END tl_u_dm_o[78]
  PIN tl_u_dm_o[79]
    DIRECTION OUTPUT ;
    USE SIGNAL ;
    ANTENNADIFFAREA 0.445500 ;
    PORT
      LAYER met2 ;
        RECT 305.990 0.000 306.270 4.000 ;
    END
  END tl_u_dm_o[79]
  PIN tl_u_dm_o[7]
    DIRECTION OUTPUT ;
    USE SIGNAL ;
    ANTENNADIFFAREA 0.445500 ;
    PORT
      LAYER met2 ;
        RECT 1088.450 0.000 1088.730 4.000 ;
    END
  END tl_u_dm_o[7]
  PIN tl_u_dm_o[80]
    DIRECTION OUTPUT ;
    USE SIGNAL ;
    ANTENNADIFFAREA 0.445500 ;
    PORT
      LAYER met2 ;
        RECT 190.070 0.000 190.350 4.000 ;
    END
  END tl_u_dm_o[80]
  PIN tl_u_dm_o[81]
    DIRECTION OUTPUT ;
    USE SIGNAL ;
    ANTENNADIFFAREA 0.445500 ;
    PORT
      LAYER met2 ;
        RECT 296.330 0.000 296.610 4.000 ;
    END
  END tl_u_dm_o[81]
  PIN tl_u_dm_o[82]
    DIRECTION OUTPUT ;
    USE SIGNAL ;
    ANTENNADIFFAREA 0.445500 ;
    PORT
      LAYER met2 ;
        RECT 177.190 0.000 177.470 4.000 ;
    END
  END tl_u_dm_o[82]
  PIN tl_u_dm_o[83]
    DIRECTION OUTPUT ;
    USE SIGNAL ;
    ANTENNADIFFAREA 0.445500 ;
    PORT
      LAYER met2 ;
        RECT 132.110 0.000 132.390 4.000 ;
    END
  END tl_u_dm_o[83]
  PIN tl_u_dm_o[84]
    DIRECTION OUTPUT ;
    USE SIGNAL ;
    ANTENNADIFFAREA 0.445500 ;
    PORT
      LAYER met2 ;
        RECT 93.470 0.000 93.750 4.000 ;
    END
  END tl_u_dm_o[84]
  PIN tl_u_dm_o[85]
    DIRECTION OUTPUT ;
    USE SIGNAL ;
    ANTENNADIFFAREA 0.445500 ;
    PORT
      LAYER met2 ;
        RECT 370.390 0.000 370.670 4.000 ;
    END
  END tl_u_dm_o[85]
  PIN tl_u_dm_o[86]
    DIRECTION OUTPUT ;
    USE SIGNAL ;
    ANTENNADIFFAREA 0.445500 ;
    PORT
      LAYER met2 ;
        RECT 331.750 0.000 332.030 4.000 ;
    END
  END tl_u_dm_o[86]
  PIN tl_u_dm_o[87]
    DIRECTION OUTPUT ;
    USE SIGNAL ;
    ANTENNADIFFAREA 0.445500 ;
    PORT
      LAYER met2 ;
        RECT 473.430 0.000 473.710 4.000 ;
    END
  END tl_u_dm_o[87]
  PIN tl_u_dm_o[88]
    DIRECTION OUTPUT ;
    USE SIGNAL ;
    ANTENNADIFFAREA 0.445500 ;
    PORT
      LAYER met2 ;
        RECT 431.570 0.000 431.850 4.000 ;
    END
  END tl_u_dm_o[88]
  PIN tl_u_dm_o[89]
    DIRECTION OUTPUT ;
    USE SIGNAL ;
    ANTENNADIFFAREA 0.445500 ;
    PORT
      LAYER met2 ;
        RECT 463.770 0.000 464.050 4.000 ;
    END
  END tl_u_dm_o[89]
  PIN tl_u_dm_o[8]
    DIRECTION OUTPUT ;
    USE SIGNAL ;
    ANTENNADIFFAREA 0.445500 ;
    PORT
      LAYER met2 ;
        RECT 740.690 1296.000 740.970 1300.000 ;
    END
  END tl_u_dm_o[8]
  PIN tl_u_dm_o[90]
    DIRECTION OUTPUT ;
    USE SIGNAL ;
    ANTENNADIFFAREA 0.445500 ;
    PORT
      LAYER met2 ;
        RECT 505.630 0.000 505.910 4.000 ;
    END
  END tl_u_dm_o[90]
  PIN tl_u_dm_o[91]
    DIRECTION OUTPUT ;
    USE SIGNAL ;
    ANTENNADIFFAREA 0.445500 ;
    PORT
      LAYER met2 ;
        RECT 454.110 0.000 454.390 4.000 ;
    END
  END tl_u_dm_o[91]
  PIN tl_u_dm_o[92]
    DIRECTION OUTPUT ;
    USE SIGNAL ;
    ANTENNADIFFAREA 0.445500 ;
    PORT
      LAYER met2 ;
        RECT 499.190 0.000 499.470 4.000 ;
    END
  END tl_u_dm_o[92]
  PIN tl_u_dm_o[93]
    DIRECTION OUTPUT ;
    USE SIGNAL ;
    ANTENNADIFFAREA 0.445500 ;
    PORT
      LAYER met2 ;
        RECT 795.430 1296.000 795.710 1300.000 ;
    END
  END tl_u_dm_o[93]
  PIN tl_u_dm_o[94]
    DIRECTION OUTPUT ;
    USE SIGNAL ;
    ANTENNADIFFAREA 0.445500 ;
    PORT
      LAYER met2 ;
        RECT 972.530 0.000 972.810 4.000 ;
    END
  END tl_u_dm_o[94]
  PIN tl_u_dm_o[95]
    DIRECTION OUTPUT ;
    USE SIGNAL ;
    ANTENNADIFFAREA 0.445500 ;
    PORT
      LAYER met2 ;
        RECT 718.150 1296.000 718.430 1300.000 ;
    END
  END tl_u_dm_o[95]
  PIN tl_u_dm_o[96]
    DIRECTION OUTPUT ;
    USE SIGNAL ;
    ANTENNADIFFAREA 0.445500 ;
    PORT
      LAYER met3 ;
        RECT 0.000 693.640 4.000 694.240 ;
    END
  END tl_u_dm_o[96]
  PIN tl_u_dm_o[97]
    DIRECTION OUTPUT ;
    USE SIGNAL ;
    ANTENNADIFFAREA 0.445500 ;
    PORT
      LAYER met2 ;
        RECT 727.810 1296.000 728.090 1300.000 ;
    END
  END tl_u_dm_o[97]
  PIN tl_u_dm_o[98]
    DIRECTION OUTPUT ;
    USE SIGNAL ;
    ANTENNADIFFAREA 0.445500 ;
    PORT
      LAYER met2 ;
        RECT 38.730 0.000 39.010 4.000 ;
    END
  END tl_u_dm_o[98]
  PIN tl_u_dm_o[99]
    DIRECTION OUTPUT ;
    USE SIGNAL ;
    ANTENNADIFFAREA 0.445500 ;
    PORT
      LAYER met3 ;
        RECT 0.000 1030.240 4.000 1030.840 ;
    END
  END tl_u_dm_o[99]
  PIN tl_u_dm_o[9]
    DIRECTION OUTPUT ;
    USE SIGNAL ;
    ANTENNADIFFAREA 0.445500 ;
    PORT
      LAYER met2 ;
        RECT 698.830 1296.000 699.110 1300.000 ;
    END
  END tl_u_dm_o[9]
  PIN tl_u_plic_i[0]
    DIRECTION INPUT ;
    USE SIGNAL ;
    ANTENNAGATEAREA 0.631200 ;
    ANTENNADIFFAREA 0.434700 ;
    PORT
      LAYER met2 ;
        RECT 199.730 0.000 200.010 4.000 ;
    END
  END tl_u_plic_i[0]
  PIN tl_u_plic_i[10]
    DIRECTION INPUT ;
    USE SIGNAL ;
    ANTENNAGATEAREA 0.647700 ;
    ANTENNADIFFAREA 0.434700 ;
    PORT
      LAYER met3 ;
        RECT 0.000 826.240 4.000 826.840 ;
    END
  END tl_u_plic_i[10]
  PIN tl_u_plic_i[11]
    DIRECTION INPUT ;
    USE SIGNAL ;
    ANTENNAGATEAREA 0.860700 ;
    ANTENNADIFFAREA 0.434700 ;
    PORT
      LAYER met2 ;
        RECT 9.750 0.000 10.030 4.000 ;
    END
  END tl_u_plic_i[11]
  PIN tl_u_plic_i[12]
    DIRECTION INPUT ;
    USE SIGNAL ;
    ANTENNAGATEAREA 0.560700 ;
    ANTENNADIFFAREA 0.434700 ;
    PORT
      LAYER met2 ;
        RECT 1062.690 1296.000 1062.970 1300.000 ;
    END
  END tl_u_plic_i[12]
  PIN tl_u_plic_i[13]
    DIRECTION INPUT ;
    USE SIGNAL ;
    ANTENNAGATEAREA 0.647700 ;
    ANTENNADIFFAREA 0.434700 ;
    PORT
      LAYER met2 ;
        RECT 1110.990 0.000 1111.270 4.000 ;
    END
  END tl_u_plic_i[13]
  PIN tl_u_plic_i[14]
    DIRECTION INPUT ;
    USE SIGNAL ;
    ANTENNAGATEAREA 0.631200 ;
    ANTENNADIFFAREA 0.434700 ;
    PORT
      LAYER met3 ;
        RECT 0.000 1118.640 4.000 1119.240 ;
    END
  END tl_u_plic_i[14]
  PIN tl_u_plic_i[15]
    DIRECTION INPUT ;
    USE SIGNAL ;
    ANTENNAGATEAREA 0.647700 ;
    ANTENNADIFFAREA 0.434700 ;
    PORT
      LAYER met2 ;
        RECT 1156.070 0.000 1156.350 4.000 ;
    END
  END tl_u_plic_i[15]
  PIN tl_u_plic_i[16]
    DIRECTION INPUT ;
    USE SIGNAL ;
    ANTENNAGATEAREA 0.631200 ;
    ANTENNADIFFAREA 0.434700 ;
    PORT
      LAYER met2 ;
        RECT 1168.950 1296.000 1169.230 1300.000 ;
    END
  END tl_u_plic_i[16]
  PIN tl_u_plic_i[17]
    DIRECTION INPUT ;
    USE SIGNAL ;
    ANTENNAGATEAREA 0.593700 ;
    ANTENNADIFFAREA 0.434700 ;
    PORT
      LAYER met2 ;
        RECT 882.370 1296.000 882.650 1300.000 ;
    END
  END tl_u_plic_i[17]
  PIN tl_u_plic_i[18]
    DIRECTION INPUT ;
    USE SIGNAL ;
    ANTENNAGATEAREA 0.631200 ;
    ANTENNADIFFAREA 0.434700 ;
    PORT
      LAYER met2 ;
        RECT 1094.890 0.000 1095.170 4.000 ;
    END
  END tl_u_plic_i[18]
  PIN tl_u_plic_i[19]
    DIRECTION INPUT ;
    USE SIGNAL ;
    ANTENNAGATEAREA 0.647700 ;
    ANTENNADIFFAREA 0.434700 ;
    PORT
      LAYER met2 ;
        RECT 821.190 1296.000 821.470 1300.000 ;
    END
  END tl_u_plic_i[19]
  PIN tl_u_plic_i[1]
    DIRECTION INPUT ;
    USE SIGNAL ;
    ANTENNAGATEAREA 0.647700 ;
    ANTENNADIFFAREA 0.434700 ;
    PORT
      LAYER met2 ;
        RECT 991.850 1296.000 992.130 1300.000 ;
    END
  END tl_u_plic_i[1]
  PIN tl_u_plic_i[20]
    DIRECTION INPUT ;
    USE SIGNAL ;
    ANTENNAGATEAREA 0.560700 ;
    ANTENNADIFFAREA 0.434700 ;
    PORT
      LAYER met2 ;
        RECT 933.890 0.000 934.170 4.000 ;
    END
  END tl_u_plic_i[20]
  PIN tl_u_plic_i[21]
    DIRECTION INPUT ;
    USE SIGNAL ;
    ANTENNAGATEAREA 0.647700 ;
    ANTENNADIFFAREA 0.434700 ;
    PORT
      LAYER met2 ;
        RECT 1159.290 0.000 1159.570 4.000 ;
    END
  END tl_u_plic_i[21]
  PIN tl_u_plic_i[22]
    DIRECTION INPUT ;
    USE SIGNAL ;
    ANTENNAGATEAREA 0.631200 ;
    ANTENNADIFFAREA 0.434700 ;
    PORT
      LAYER met3 ;
        RECT 0.000 1281.840 4.000 1282.440 ;
    END
  END tl_u_plic_i[22]
  PIN tl_u_plic_i[23]
    DIRECTION INPUT ;
    USE SIGNAL ;
    ANTENNAGATEAREA 0.631200 ;
    ANTENNADIFFAREA 0.434700 ;
    PORT
      LAYER met2 ;
        RECT 917.790 1296.000 918.070 1300.000 ;
    END
  END tl_u_plic_i[23]
  PIN tl_u_plic_i[24]
    DIRECTION INPUT ;
    USE SIGNAL ;
    ANTENNAGATEAREA 0.560700 ;
    ANTENNADIFFAREA 0.434700 ;
    PORT
      LAYER met2 ;
        RECT 1220.470 1296.000 1220.750 1300.000 ;
    END
  END tl_u_plic_i[24]
  PIN tl_u_plic_i[25]
    DIRECTION INPUT ;
    USE SIGNAL ;
    ANTENNAGATEAREA 0.647700 ;
    ANTENNADIFFAREA 0.434700 ;
    PORT
      LAYER met2 ;
        RECT 1230.130 1296.000 1230.410 1300.000 ;
    END
  END tl_u_plic_i[25]
  PIN tl_u_plic_i[26]
    DIRECTION INPUT ;
    USE SIGNAL ;
    ANTENNAGATEAREA 0.593700 ;
    ANTENNADIFFAREA 0.434700 ;
    PORT
      LAYER met2 ;
        RECT 998.290 1296.000 998.570 1300.000 ;
    END
  END tl_u_plic_i[26]
  PIN tl_u_plic_i[27]
    DIRECTION INPUT ;
    USE SIGNAL ;
    ANTENNAGATEAREA 0.560700 ;
    ANTENNADIFFAREA 0.434700 ;
    PORT
      LAYER met2 ;
        RECT 1046.590 0.000 1046.870 4.000 ;
    END
  END tl_u_plic_i[27]
  PIN tl_u_plic_i[28]
    DIRECTION INPUT ;
    USE SIGNAL ;
    ANTENNAGATEAREA 0.647700 ;
    ANTENNADIFFAREA 0.434700 ;
    PORT
      LAYER met2 ;
        RECT 740.690 0.000 740.970 4.000 ;
    END
  END tl_u_plic_i[28]
  PIN tl_u_plic_i[29]
    DIRECTION INPUT ;
    USE SIGNAL ;
    ANTENNAGATEAREA 0.593700 ;
    ANTENNADIFFAREA 0.434700 ;
    PORT
      LAYER met2 ;
        RECT 785.770 1296.000 786.050 1300.000 ;
    END
  END tl_u_plic_i[29]
  PIN tl_u_plic_i[2]
    DIRECTION INPUT ;
    USE SIGNAL ;
    ANTENNAGATEAREA 0.593700 ;
    ANTENNADIFFAREA 0.434700 ;
    PORT
      LAYER met2 ;
        RECT 853.390 1296.000 853.670 1300.000 ;
    END
  END tl_u_plic_i[2]
  PIN tl_u_plic_i[30]
    DIRECTION INPUT ;
    USE SIGNAL ;
    ANTENNAGATEAREA 0.593700 ;
    ANTENNADIFFAREA 0.434700 ;
    PORT
      LAYER met2 ;
        RECT 747.130 0.000 747.410 4.000 ;
    END
  END tl_u_plic_i[30]
  PIN tl_u_plic_i[31]
    DIRECTION INPUT ;
    USE SIGNAL ;
    ANTENNAGATEAREA 0.647700 ;
    ANTENNADIFFAREA 0.434700 ;
    PORT
      LAYER met3 ;
        RECT 0.000 768.440 4.000 769.040 ;
    END
  END tl_u_plic_i[31]
  PIN tl_u_plic_i[32]
    DIRECTION INPUT ;
    USE SIGNAL ;
    ANTENNAGATEAREA 0.631200 ;
    ANTENNADIFFAREA 0.434700 ;
    PORT
      LAYER met2 ;
        RECT 1114.210 0.000 1114.490 4.000 ;
    END
  END tl_u_plic_i[32]
  PIN tl_u_plic_i[33]
    DIRECTION INPUT ;
    USE SIGNAL ;
    ANTENNAGATEAREA 0.647700 ;
    ANTENNADIFFAREA 0.434700 ;
    PORT
      LAYER met2 ;
        RECT 911.350 1296.000 911.630 1300.000 ;
    END
  END tl_u_plic_i[33]
  PIN tl_u_plic_i[34]
    DIRECTION INPUT ;
    USE SIGNAL ;
    ANTENNAGATEAREA 0.682200 ;
    ANTENNADIFFAREA 0.434700 ;
    PORT
      LAYER met2 ;
        RECT 1239.790 0.000 1240.070 4.000 ;
    END
  END tl_u_plic_i[34]
  PIN tl_u_plic_i[35]
    DIRECTION INPUT ;
    USE SIGNAL ;
    ANTENNAGATEAREA 0.647700 ;
    ANTENNADIFFAREA 0.434700 ;
    PORT
      LAYER met2 ;
        RECT 1040.150 1296.000 1040.430 1300.000 ;
    END
  END tl_u_plic_i[35]
  PIN tl_u_plic_i[36]
    DIRECTION INPUT ;
    USE SIGNAL ;
    ANTENNAGATEAREA 0.593700 ;
    ANTENNADIFFAREA 0.434700 ;
    PORT
      LAYER met2 ;
        RECT 1288.090 1296.000 1288.370 1300.000 ;
    END
  END tl_u_plic_i[36]
  PIN tl_u_plic_i[37]
    DIRECTION INPUT ;
    USE SIGNAL ;
    ANTENNAGATEAREA 0.593700 ;
    ANTENNADIFFAREA 0.434700 ;
    PORT
      LAYER met2 ;
        RECT 679.510 0.000 679.790 4.000 ;
    END
  END tl_u_plic_i[37]
  PIN tl_u_plic_i[38]
    DIRECTION INPUT ;
    USE SIGNAL ;
    ANTENNAGATEAREA 0.631200 ;
    ANTENNADIFFAREA 0.434700 ;
    PORT
      LAYER met3 ;
        RECT 0.000 1288.640 4.000 1289.240 ;
    END
  END tl_u_plic_i[38]
  PIN tl_u_plic_i[39]
    DIRECTION INPUT ;
    USE SIGNAL ;
    ANTENNAGATEAREA 0.593700 ;
    ANTENNADIFFAREA 0.434700 ;
    PORT
      LAYER met2 ;
        RECT 808.310 0.000 808.590 4.000 ;
    END
  END tl_u_plic_i[39]
  PIN tl_u_plic_i[3]
    DIRECTION INPUT ;
    USE SIGNAL ;
    ANTENNAGATEAREA 0.647700 ;
    ANTENNADIFFAREA 0.434700 ;
    PORT
      LAYER met2 ;
        RECT 924.230 1296.000 924.510 1300.000 ;
    END
  END tl_u_plic_i[3]
  PIN tl_u_plic_i[40]
    DIRECTION INPUT ;
    USE SIGNAL ;
    ANTENNAGATEAREA 0.647700 ;
    ANTENNADIFFAREA 0.434700 ;
    PORT
      LAYER met2 ;
        RECT 872.710 1296.000 872.990 1300.000 ;
    END
  END tl_u_plic_i[40]
  PIN tl_u_plic_i[41]
    DIRECTION INPUT ;
    USE SIGNAL ;
    ANTENNAGATEAREA 0.647700 ;
    ANTENNADIFFAREA 0.434700 ;
    PORT
      LAYER met2 ;
        RECT 1046.590 1296.000 1046.870 1300.000 ;
    END
  END tl_u_plic_i[41]
  PIN tl_u_plic_i[42]
    DIRECTION INPUT ;
    USE SIGNAL ;
    ANTENNAGATEAREA 0.860700 ;
    ANTENNADIFFAREA 0.434700 ;
    PORT
      LAYER met2 ;
        RECT 766.450 1296.000 766.730 1300.000 ;
    END
  END tl_u_plic_i[42]
  PIN tl_u_plic_i[43]
    DIRECTION INPUT ;
    USE SIGNAL ;
    ANTENNAGATEAREA 0.647700 ;
    ANTENNADIFFAREA 0.434700 ;
    PORT
      LAYER met2 ;
        RECT 869.490 0.000 869.770 4.000 ;
    END
  END tl_u_plic_i[43]
  PIN tl_u_plic_i[44]
    DIRECTION INPUT ;
    USE SIGNAL ;
    ANTENNAGATEAREA 0.593700 ;
    ANTENNADIFFAREA 0.434700 ;
    PORT
      LAYER met2 ;
        RECT 921.010 1296.000 921.290 1300.000 ;
    END
  END tl_u_plic_i[44]
  PIN tl_u_plic_i[45]
    DIRECTION INPUT ;
    USE SIGNAL ;
    ANTENNAGATEAREA 0.647700 ;
    ANTENNADIFFAREA 0.434700 ;
    PORT
      LAYER met2 ;
        RECT 1065.910 1296.000 1066.190 1300.000 ;
    END
  END tl_u_plic_i[45]
  PIN tl_u_plic_i[46]
    DIRECTION INPUT ;
    USE SIGNAL ;
    ANTENNAGATEAREA 0.593700 ;
    ANTENNADIFFAREA 0.434700 ;
    PORT
      LAYER met2 ;
        RECT 1027.270 1296.000 1027.550 1300.000 ;
    END
  END tl_u_plic_i[46]
  PIN tl_u_plic_i[47]
    DIRECTION INPUT ;
    USE SIGNAL ;
    ANTENNAGATEAREA 0.631200 ;
    ANTENNADIFFAREA 0.434700 ;
    PORT
      LAYER met2 ;
        RECT 663.410 1296.000 663.690 1300.000 ;
    END
  END tl_u_plic_i[47]
  PIN tl_u_plic_i[48]
    DIRECTION INPUT ;
    USE SIGNAL ;
    ANTENNAGATEAREA 0.631200 ;
    ANTENNADIFFAREA 0.434700 ;
    PORT
      LAYER met3 ;
        RECT 0.000 1040.440 4.000 1041.040 ;
    END
  END tl_u_plic_i[48]
  PIN tl_u_plic_i[49]
    DIRECTION INPUT ;
    USE SIGNAL ;
    ANTENNAGATEAREA 0.647700 ;
    ANTENNADIFFAREA 0.434700 ;
    PORT
      LAYER met2 ;
        RECT 1291.310 1296.000 1291.590 1300.000 ;
    END
  END tl_u_plic_i[49]
  PIN tl_u_plic_i[4]
    DIRECTION INPUT ;
    USE SIGNAL ;
    ANTENNAGATEAREA 0.860700 ;
    ANTENNADIFFAREA 0.434700 ;
    PORT
      LAYER met2 ;
        RECT 1214.030 1296.000 1214.310 1300.000 ;
    END
  END tl_u_plic_i[4]
  PIN tl_u_plic_i[50]
    DIRECTION INPUT ;
    USE SIGNAL ;
    ANTENNAGATEAREA 0.682200 ;
    ANTENNADIFFAREA 0.434700 ;
    PORT
      LAYER met3 ;
        RECT 0.000 1292.040 4.000 1292.640 ;
    END
  END tl_u_plic_i[50]
  PIN tl_u_plic_i[51]
    DIRECTION INPUT ;
    USE SIGNAL ;
    ANTENNAGATEAREA 0.647700 ;
    ANTENNADIFFAREA 0.434700 ;
    PORT
      LAYER met2 ;
        RECT 859.830 1296.000 860.110 1300.000 ;
    END
  END tl_u_plic_i[51]
  PIN tl_u_plic_i[52]
    DIRECTION INPUT ;
    USE SIGNAL ;
    ANTENNAGATEAREA 0.647700 ;
    ANTENNADIFFAREA 0.434700 ;
    PORT
      LAYER met2 ;
        RECT 711.710 1296.000 711.990 1300.000 ;
    END
  END tl_u_plic_i[52]
  PIN tl_u_plic_i[53]
    DIRECTION INPUT ;
    USE SIGNAL ;
    ANTENNAGATEAREA 0.647700 ;
    ANTENNADIFFAREA 0.434700 ;
    PORT
      LAYER met3 ;
        RECT 0.000 1122.040 4.000 1122.640 ;
    END
  END tl_u_plic_i[53]
  PIN tl_u_plic_i[54]
    DIRECTION INPUT ;
    USE SIGNAL ;
    ANTENNAGATEAREA 0.593700 ;
    ANTENNADIFFAREA 0.434700 ;
    PORT
      LAYER met2 ;
        RECT 656.970 0.000 657.250 4.000 ;
    END
  END tl_u_plic_i[54]
  PIN tl_u_plic_i[55]
    DIRECTION INPUT ;
    USE SIGNAL ;
    ANTENNAGATEAREA 0.631200 ;
    ANTENNADIFFAREA 0.434700 ;
    PORT
      LAYER met2 ;
        RECT 1252.670 0.000 1252.950 4.000 ;
    END
  END tl_u_plic_i[55]
  PIN tl_u_plic_i[56]
    DIRECTION INPUT ;
    USE SIGNAL ;
    ANTENNAGATEAREA 0.647700 ;
    ANTENNADIFFAREA 0.434700 ;
    PORT
      LAYER met3 ;
        RECT 0.000 1071.040 4.000 1071.640 ;
    END
  END tl_u_plic_i[56]
  PIN tl_u_plic_i[57]
    DIRECTION INPUT ;
    USE SIGNAL ;
    ANTENNAGATEAREA 0.647700 ;
    ANTENNADIFFAREA 0.434700 ;
    PORT
      LAYER met2 ;
        RECT 731.030 0.000 731.310 4.000 ;
    END
  END tl_u_plic_i[57]
  PIN tl_u_plic_i[58]
    DIRECTION INPUT ;
    USE SIGNAL ;
    ANTENNAGATEAREA 0.593700 ;
    ANTENNADIFFAREA 0.434700 ;
    PORT
      LAYER met2 ;
        RECT 901.690 1296.000 901.970 1300.000 ;
    END
  END tl_u_plic_i[58]
  PIN tl_u_plic_i[59]
    DIRECTION INPUT ;
    USE SIGNAL ;
    ANTENNAGATEAREA 0.647700 ;
    ANTENNADIFFAREA 0.434700 ;
    PORT
      LAYER met2 ;
        RECT 1146.410 1296.000 1146.690 1300.000 ;
    END
  END tl_u_plic_i[59]
  PIN tl_u_plic_i[5]
    DIRECTION INPUT ;
    USE SIGNAL ;
    ANTENNAGATEAREA 0.593700 ;
    ANTENNADIFFAREA 0.434700 ;
    PORT
      LAYER met2 ;
        RECT 1243.010 1296.000 1243.290 1300.000 ;
    END
  END tl_u_plic_i[5]
  PIN tl_u_plic_i[60]
    DIRECTION INPUT ;
    USE SIGNAL ;
    ANTENNAGATEAREA 0.647700 ;
    ANTENNADIFFAREA 0.434700 ;
    PORT
      LAYER met3 ;
        RECT 0.000 758.240 4.000 758.840 ;
    END
  END tl_u_plic_i[60]
  PIN tl_u_plic_i[61]
    DIRECTION INPUT ;
    USE SIGNAL ;
    ANTENNAGATEAREA 0.647700 ;
    ANTENNADIFFAREA 0.434700 ;
    PORT
      LAYER met2 ;
        RECT 937.110 1296.000 937.390 1300.000 ;
    END
  END tl_u_plic_i[61]
  PIN tl_u_plic_i[62]
    DIRECTION INPUT ;
    USE SIGNAL ;
    ANTENNAGATEAREA 0.560700 ;
    ANTENNADIFFAREA 0.434700 ;
    PORT
      LAYER met2 ;
        RECT 1127.090 1296.000 1127.370 1300.000 ;
    END
  END tl_u_plic_i[62]
  PIN tl_u_plic_i[63]
    DIRECTION INPUT ;
    USE SIGNAL ;
    ANTENNAGATEAREA 0.682200 ;
    ANTENNADIFFAREA 0.434700 ;
    PORT
      LAYER met2 ;
        RECT 1233.350 1296.000 1233.630 1300.000 ;
    END
  END tl_u_plic_i[63]
  PIN tl_u_plic_i[64]
    DIRECTION INPUT ;
    USE SIGNAL ;
    ANTENNAGATEAREA 0.647700 ;
    ANTENNADIFFAREA 0.434700 ;
    PORT
      LAYER met2 ;
        RECT 1236.570 1296.000 1236.850 1300.000 ;
    END
  END tl_u_plic_i[64]
  PIN tl_u_plic_i[65]
    DIRECTION INPUT ;
    USE SIGNAL ;
    ANTENNAGATEAREA 0.631200 ;
    ANTENNADIFFAREA 0.434700 ;
    PORT
      LAYER met2 ;
        RECT 1207.590 1296.000 1207.870 1300.000 ;
    END
  END tl_u_plic_i[65]
  PIN tl_u_plic_i[6]
    DIRECTION INPUT ;
    USE SIGNAL ;
    ANTENNAGATEAREA 0.631200 ;
    ANTENNADIFFAREA 0.434700 ;
    PORT
      LAYER met2 ;
        RECT 1053.030 1296.000 1053.310 1300.000 ;
    END
  END tl_u_plic_i[6]
  PIN tl_u_plic_i[7]
    DIRECTION INPUT ;
    USE SIGNAL ;
    ANTENNAGATEAREA 0.860700 ;
    ANTENNADIFFAREA 0.434700 ;
    PORT
      LAYER met3 ;
        RECT 0.000 965.640 4.000 966.240 ;
    END
  END tl_u_plic_i[7]
  PIN tl_u_plic_i[8]
    DIRECTION INPUT ;
    USE SIGNAL ;
    ANTENNAGATEAREA 0.631200 ;
    ANTENNADIFFAREA 0.434700 ;
    PORT
      LAYER met2 ;
        RECT 817.970 0.000 818.250 4.000 ;
    END
  END tl_u_plic_i[8]
  PIN tl_u_plic_i[9]
    DIRECTION INPUT ;
    USE SIGNAL ;
    ANTENNAGATEAREA 0.593700 ;
    ANTENNADIFFAREA 0.434700 ;
    PORT
      LAYER met2 ;
        RECT 1104.550 1296.000 1104.830 1300.000 ;
    END
  END tl_u_plic_i[9]
  PIN tl_u_plic_o[0]
    DIRECTION OUTPUT ;
    USE SIGNAL ;
    ANTENNADIFFAREA 0.445500 ;
    PORT
      LAYER met3 ;
        RECT 0.000 741.240 4.000 741.840 ;
    END
  END tl_u_plic_o[0]
  PIN tl_u_plic_o[100]
    DIRECTION OUTPUT ;
    USE SIGNAL ;
    ANTENNADIFFAREA 0.445500 ;
    PORT
      LAYER met3 ;
        RECT 0.000 928.240 4.000 928.840 ;
    END
  END tl_u_plic_o[100]
  PIN tl_u_plic_o[101]
    DIRECTION OUTPUT ;
    USE SIGNAL ;
    ANTENNADIFFAREA 0.445500 ;
    PORT
      LAYER met2 ;
        RECT 875.930 0.000 876.210 4.000 ;
    END
  END tl_u_plic_o[101]
  PIN tl_u_plic_o[102]
    DIRECTION OUTPUT ;
    USE SIGNAL ;
    ANTENNADIFFAREA 0.445500 ;
    PORT
      LAYER met3 ;
        RECT 0.000 707.240 4.000 707.840 ;
    END
  END tl_u_plic_o[102]
  PIN tl_u_plic_o[103]
    DIRECTION OUTPUT ;
    USE SIGNAL ;
    ANTENNADIFFAREA 0.445500 ;
    PORT
      LAYER met2 ;
        RECT 882.370 0.000 882.650 4.000 ;
    END
  END tl_u_plic_o[103]
  PIN tl_u_plic_o[104]
    DIRECTION OUTPUT ;
    USE SIGNAL ;
    ANTENNADIFFAREA 0.445500 ;
    PORT
      LAYER met2 ;
        RECT 846.950 0.000 847.230 4.000 ;
    END
  END tl_u_plic_o[104]
  PIN tl_u_plic_o[105]
    DIRECTION OUTPUT ;
    USE SIGNAL ;
    ANTENNADIFFAREA 0.445500 ;
    PORT
      LAYER met2 ;
        RECT 273.790 0.000 274.070 4.000 ;
    END
  END tl_u_plic_o[105]
  PIN tl_u_plic_o[106]
    DIRECTION OUTPUT ;
    USE SIGNAL ;
    ANTENNADIFFAREA 0.445500 ;
    PORT
      LAYER met2 ;
        RECT 22.630 0.000 22.910 4.000 ;
    END
  END tl_u_plic_o[106]
  PIN tl_u_plic_o[107]
    DIRECTION OUTPUT ;
    USE SIGNAL ;
    ANTENNADIFFAREA 0.445500 ;
    PORT
      LAYER met3 ;
        RECT 0.000 880.640 4.000 881.240 ;
    END
  END tl_u_plic_o[107]
  PIN tl_u_plic_o[108]
    DIRECTION OUTPUT ;
    USE SIGNAL ;
    ANTENNADIFFAREA 0.445500 ;
    PORT
      LAYER met2 ;
        RECT 563.590 0.000 563.870 4.000 ;
    END
  END tl_u_plic_o[108]
  PIN tl_u_plic_o[109]
    DIRECTION OUTPUT ;
    USE SIGNAL ;
    ANTENNADIFFAREA 0.445500 ;
    PORT
      LAYER met2 ;
        RECT 222.270 0.000 222.550 4.000 ;
    END
  END tl_u_plic_o[109]
  PIN tl_u_plic_o[10]
    DIRECTION OUTPUT ;
    USE SIGNAL ;
    ANTENNADIFFAREA 0.445500 ;
    PORT
      LAYER met2 ;
        RECT 116.010 0.000 116.290 4.000 ;
    END
  END tl_u_plic_o[10]
  PIN tl_u_plic_o[11]
    DIRECTION OUTPUT ;
    USE SIGNAL ;
    ANTENNADIFFAREA 0.445500 ;
    PORT
      LAYER met2 ;
        RECT 1120.650 0.000 1120.930 4.000 ;
    END
  END tl_u_plic_o[11]
  PIN tl_u_plic_o[12]
    DIRECTION OUTPUT ;
    USE SIGNAL ;
    ANTENNADIFFAREA 0.445500 ;
    PORT
      LAYER met3 ;
        RECT 0.000 1047.240 4.000 1047.840 ;
    END
  END tl_u_plic_o[12]
  PIN tl_u_plic_o[13]
    DIRECTION OUTPUT ;
    USE SIGNAL ;
    ANTENNADIFFAREA 0.445500 ;
    PORT
      LAYER met2 ;
        RECT 685.950 1296.000 686.230 1300.000 ;
    END
  END tl_u_plic_o[13]
  PIN tl_u_plic_o[14]
    DIRECTION OUTPUT ;
    USE SIGNAL ;
    ANTENNADIFFAREA 0.445500 ;
    PORT
      LAYER met2 ;
        RECT 528.170 0.000 528.450 4.000 ;
    END
  END tl_u_plic_o[14]
  PIN tl_u_plic_o[15]
    DIRECTION OUTPUT ;
    USE SIGNAL ;
    ANTENNADIFFAREA 0.445500 ;
    PORT
      LAYER met2 ;
        RECT 515.290 0.000 515.570 4.000 ;
    END
  END tl_u_plic_o[15]
  PIN tl_u_plic_o[16]
    DIRECTION OUTPUT ;
    USE SIGNAL ;
    ANTENNADIFFAREA 0.445500 ;
    PORT
      LAYER met2 ;
        RECT 1040.150 0.000 1040.430 4.000 ;
    END
  END tl_u_plic_o[16]
  PIN tl_u_plic_o[17]
    DIRECTION OUTPUT ;
    USE SIGNAL ;
    ANTENNADIFFAREA 0.445500 ;
    PORT
      LAYER met2 ;
        RECT 1033.710 1296.000 1033.990 1300.000 ;
    END
  END tl_u_plic_o[17]
  PIN tl_u_plic_o[18]
    DIRECTION OUTPUT ;
    USE SIGNAL ;
    ANTENNADIFFAREA 0.445500 ;
    PORT
      LAYER met2 ;
        RECT 669.850 1296.000 670.130 1300.000 ;
    END
  END tl_u_plic_o[18]
  PIN tl_u_plic_o[19]
    DIRECTION OUTPUT ;
    USE SIGNAL ;
    ANTENNADIFFAREA 0.445500 ;
    PORT
      LAYER met3 ;
        RECT 0.000 931.640 4.000 932.240 ;
    END
  END tl_u_plic_o[19]
  PIN tl_u_plic_o[1]
    DIRECTION OUTPUT ;
    USE SIGNAL ;
    ANTENNADIFFAREA 0.445500 ;
    PORT
      LAYER met3 ;
        RECT 0.000 867.040 4.000 867.640 ;
    END
  END tl_u_plic_o[1]
  PIN tl_u_plic_o[20]
    DIRECTION OUTPUT ;
    USE SIGNAL ;
    ANTENNADIFFAREA 0.445500 ;
    PORT
      LAYER met2 ;
        RECT 621.550 0.000 621.830 4.000 ;
    END
  END tl_u_plic_o[20]
  PIN tl_u_plic_o[21]
    DIRECTION OUTPUT ;
    USE SIGNAL ;
    ANTENNADIFFAREA 0.445500 ;
    PORT
      LAYER met2 ;
        RECT 1210.810 0.000 1211.090 4.000 ;
    END
  END tl_u_plic_o[21]
  PIN tl_u_plic_o[22]
    DIRECTION OUTPUT ;
    USE SIGNAL ;
    ANTENNADIFFAREA 0.445500 ;
    PORT
      LAYER met2 ;
        RECT 747.130 1296.000 747.410 1300.000 ;
    END
  END tl_u_plic_o[22]
  PIN tl_u_plic_o[23]
    DIRECTION OUTPUT ;
    USE SIGNAL ;
    ANTENNADIFFAREA 0.445500 ;
    PORT
      LAYER met2 ;
        RECT 611.890 0.000 612.170 4.000 ;
    END
  END tl_u_plic_o[23]
  PIN tl_u_plic_o[24]
    DIRECTION OUTPUT ;
    USE SIGNAL ;
    ANTENNADIFFAREA 0.445500 ;
    PORT
      LAYER met3 ;
        RECT 0.000 1115.240 4.000 1115.840 ;
    END
  END tl_u_plic_o[24]
  PIN tl_u_plic_o[25]
    DIRECTION OUTPUT ;
    USE SIGNAL ;
    ANTENNADIFFAREA 0.445500 ;
    PORT
      LAYER met2 ;
        RECT 58.050 0.000 58.330 4.000 ;
    END
  END tl_u_plic_o[25]
  PIN tl_u_plic_o[26]
    DIRECTION OUTPUT ;
    USE SIGNAL ;
    ANTENNADIFFAREA 0.445500 ;
    PORT
      LAYER met3 ;
        RECT 0.000 938.440 4.000 939.040 ;
    END
  END tl_u_plic_o[26]
  PIN tl_u_plic_o[27]
    DIRECTION OUTPUT ;
    USE SIGNAL ;
    ANTENNADIFFAREA 0.445500 ;
    PORT
      LAYER met2 ;
        RECT 637.650 0.000 637.930 4.000 ;
    END
  END tl_u_plic_o[27]
  PIN tl_u_plic_o[28]
    DIRECTION OUTPUT ;
    USE SIGNAL ;
    ANTENNADIFFAREA 0.445500 ;
    PORT
      LAYER met2 ;
        RECT 1168.950 0.000 1169.230 4.000 ;
    END
  END tl_u_plic_o[28]
  PIN tl_u_plic_o[29]
    DIRECTION OUTPUT ;
    USE SIGNAL ;
    ANTENNADIFFAREA 0.445500 ;
    PORT
      LAYER met2 ;
        RECT 495.970 0.000 496.250 4.000 ;
    END
  END tl_u_plic_o[29]
  PIN tl_u_plic_o[2]
    DIRECTION OUTPUT ;
    USE SIGNAL ;
    ANTENNADIFFAREA 0.445500 ;
    PORT
      LAYER met3 ;
        RECT 0.000 1043.840 4.000 1044.440 ;
    END
  END tl_u_plic_o[2]
  PIN tl_u_plic_o[30]
    DIRECTION OUTPUT ;
    USE SIGNAL ;
    ANTENNADIFFAREA 0.445500 ;
    PORT
      LAYER met2 ;
        RECT 1056.250 1296.000 1056.530 1300.000 ;
    END
  END tl_u_plic_o[30]
  PIN tl_u_plic_o[31]
    DIRECTION OUTPUT ;
    USE SIGNAL ;
    ANTENNADIFFAREA 0.445500 ;
    PORT
      LAYER met2 ;
        RECT 930.670 0.000 930.950 4.000 ;
    END
  END tl_u_plic_o[31]
  PIN tl_u_plic_o[32]
    DIRECTION OUTPUT ;
    USE SIGNAL ;
    ANTENNADIFFAREA 0.445500 ;
    PORT
      LAYER met2 ;
        RECT 1185.050 0.000 1185.330 4.000 ;
    END
  END tl_u_plic_o[32]
  PIN tl_u_plic_o[33]
    DIRECTION OUTPUT ;
    USE SIGNAL ;
    ANTENNADIFFAREA 0.445500 ;
    PORT
      LAYER met2 ;
        RECT 618.330 0.000 618.610 4.000 ;
    END
  END tl_u_plic_o[33]
  PIN tl_u_plic_o[34]
    DIRECTION OUTPUT ;
    USE SIGNAL ;
    ANTENNADIFFAREA 0.445500 ;
    PORT
      LAYER met2 ;
        RECT 19.410 0.000 19.690 4.000 ;
    END
  END tl_u_plic_o[34]
  PIN tl_u_plic_o[35]
    DIRECTION OUTPUT ;
    USE SIGNAL ;
    ANTENNADIFFAREA 0.445500 ;
    PORT
      LAYER met2 ;
        RECT 1065.910 0.000 1066.190 4.000 ;
    END
  END tl_u_plic_o[35]
  PIN tl_u_plic_o[36]
    DIRECTION OUTPUT ;
    USE SIGNAL ;
    ANTENNADIFFAREA 0.445500 ;
    PORT
      LAYER met3 ;
        RECT 0.000 720.840 4.000 721.440 ;
    END
  END tl_u_plic_o[36]
  PIN tl_u_plic_o[37]
    DIRECTION OUTPUT ;
    USE SIGNAL ;
    ANTENNADIFFAREA 0.445500 ;
    PORT
      LAYER met2 ;
        RECT 1033.710 0.000 1033.990 4.000 ;
    END
  END tl_u_plic_o[37]
  PIN tl_u_plic_o[38]
    DIRECTION OUTPUT ;
    USE SIGNAL ;
    ANTENNADIFFAREA 0.445500 ;
    PORT
      LAYER met2 ;
        RECT 80.590 0.000 80.870 4.000 ;
    END
  END tl_u_plic_o[38]
  PIN tl_u_plic_o[39]
    DIRECTION OUTPUT ;
    USE SIGNAL ;
    ANTENNADIFFAREA 0.445500 ;
    PORT
      LAYER met2 ;
        RECT 1117.430 0.000 1117.710 4.000 ;
    END
  END tl_u_plic_o[39]
  PIN tl_u_plic_o[3]
    DIRECTION OUTPUT ;
    USE SIGNAL ;
    ANTENNADIFFAREA 0.445500 ;
    PORT
      LAYER met2 ;
        RECT 1281.650 0.000 1281.930 4.000 ;
    END
  END tl_u_plic_o[3]
  PIN tl_u_plic_o[40]
    DIRECTION OUTPUT ;
    USE SIGNAL ;
    ANTENNADIFFAREA 0.445500 ;
    PORT
      LAYER met3 ;
        RECT 0.000 870.440 4.000 871.040 ;
    END
  END tl_u_plic_o[40]
  PIN tl_u_plic_o[41]
    DIRECTION OUTPUT ;
    USE SIGNAL ;
    ANTENNADIFFAREA 0.445500 ;
    PORT
      LAYER met2 ;
        RECT 1014.390 0.000 1014.670 4.000 ;
    END
  END tl_u_plic_o[41]
  PIN tl_u_plic_o[42]
    DIRECTION OUTPUT ;
    USE SIGNAL ;
    ANTENNADIFFAREA 0.445500 ;
    PORT
      LAYER met2 ;
        RECT 1101.330 0.000 1101.610 4.000 ;
    END
  END tl_u_plic_o[42]
  PIN tl_u_plic_o[43]
    DIRECTION OUTPUT ;
    USE SIGNAL ;
    ANTENNADIFFAREA 0.445500 ;
    PORT
      LAYER met2 ;
        RECT 54.830 0.000 55.110 4.000 ;
    END
  END tl_u_plic_o[43]
  PIN tl_u_plic_o[44]
    DIRECTION OUTPUT ;
    USE SIGNAL ;
    ANTENNADIFFAREA 0.445500 ;
    PORT
      LAYER met3 ;
        RECT 0.000 748.040 4.000 748.640 ;
    END
  END tl_u_plic_o[44]
  PIN tl_u_plic_o[45]
    DIRECTION OUTPUT ;
    USE SIGNAL ;
    ANTENNADIFFAREA 0.445500 ;
    PORT
      LAYER met2 ;
        RECT 718.150 0.000 718.430 4.000 ;
    END
  END tl_u_plic_o[45]
  PIN tl_u_plic_o[46]
    DIRECTION OUTPUT ;
    USE SIGNAL ;
    ANTENNADIFFAREA 0.445500 ;
    PORT
      LAYER met2 ;
        RECT 689.170 1296.000 689.450 1300.000 ;
    END
  END tl_u_plic_o[46]
  PIN tl_u_plic_o[47]
    DIRECTION OUTPUT ;
    USE SIGNAL ;
    ANTENNADIFFAREA 0.445500 ;
    PORT
      LAYER met3 ;
        RECT 0.000 1057.440 4.000 1058.040 ;
    END
  END tl_u_plic_o[47]
  PIN tl_u_plic_o[48]
    DIRECTION OUTPUT ;
    USE SIGNAL ;
    ANTENNADIFFAREA 0.445500 ;
    PORT
      LAYER met3 ;
        RECT 0.000 819.440 4.000 820.040 ;
    END
  END tl_u_plic_o[48]
  PIN tl_u_plic_o[49]
    DIRECTION OUTPUT ;
    USE SIGNAL ;
    ANTENNADIFFAREA 0.445500 ;
    PORT
      LAYER met3 ;
        RECT 0.000 1128.840 4.000 1129.440 ;
    END
  END tl_u_plic_o[49]
  PIN tl_u_plic_o[4]
    DIRECTION OUTPUT ;
    USE SIGNAL ;
    ANTENNADIFFAREA 0.445500 ;
    PORT
      LAYER met2 ;
        RECT 627.990 0.000 628.270 4.000 ;
    END
  END tl_u_plic_o[4]
  PIN tl_u_plic_o[50]
    DIRECTION OUTPUT ;
    USE SIGNAL ;
    ANTENNADIFFAREA 0.445500 ;
    PORT
      LAYER met2 ;
        RECT 975.750 0.000 976.030 4.000 ;
    END
  END tl_u_plic_o[50]
  PIN tl_u_plic_o[51]
    DIRECTION OUTPUT ;
    USE SIGNAL ;
    ANTENNADIFFAREA 0.445500 ;
    PORT
      LAYER met3 ;
        RECT 0.000 683.440 4.000 684.040 ;
    END
  END tl_u_plic_o[51]
  PIN tl_u_plic_o[52]
    DIRECTION OUTPUT ;
    USE SIGNAL ;
    ANTENNADIFFAREA 0.445500 ;
    PORT
      LAYER met2 ;
        RECT 1188.270 0.000 1188.550 4.000 ;
    END
  END tl_u_plic_o[52]
  PIN tl_u_plic_o[53]
    DIRECTION OUTPUT ;
    USE SIGNAL ;
    ANTENNADIFFAREA 0.445500 ;
    PORT
      LAYER met2 ;
        RECT 769.670 0.000 769.950 4.000 ;
    END
  END tl_u_plic_o[53]
  PIN tl_u_plic_o[54]
    DIRECTION OUTPUT ;
    USE SIGNAL ;
    ANTENNADIFFAREA 0.445500 ;
    PORT
      LAYER met3 ;
        RECT 0.000 1149.240 4.000 1149.840 ;
    END
  END tl_u_plic_o[54]
  PIN tl_u_plic_o[55]
    DIRECTION OUTPUT ;
    USE SIGNAL ;
    ANTENNADIFFAREA 0.445500 ;
    PORT
      LAYER met3 ;
        RECT 0.000 775.240 4.000 775.840 ;
    END
  END tl_u_plic_o[55]
  PIN tl_u_plic_o[56]
    DIRECTION OUTPUT ;
    USE SIGNAL ;
    ANTENNADIFFAREA 0.445500 ;
    PORT
      LAYER met3 ;
        RECT 0.000 829.640 4.000 830.240 ;
    END
  END tl_u_plic_o[56]
  PIN tl_u_plic_o[57]
    DIRECTION OUTPUT ;
    USE SIGNAL ;
    ANTENNADIFFAREA 0.445500 ;
    PORT
      LAYER met3 ;
        RECT 0.000 1094.840 4.000 1095.440 ;
    END
  END tl_u_plic_o[57]
  PIN tl_u_plic_o[58]
    DIRECTION OUTPUT ;
    USE SIGNAL ;
    ANTENNADIFFAREA 0.445500 ;
    PORT
      LAYER met2 ;
        RECT 1191.490 1296.000 1191.770 1300.000 ;
    END
  END tl_u_plic_o[58]
  PIN tl_u_plic_o[59]
    DIRECTION OUTPUT ;
    USE SIGNAL ;
    ANTENNADIFFAREA 0.445500 ;
    PORT
      LAYER met2 ;
        RECT 1069.130 0.000 1069.410 4.000 ;
    END
  END tl_u_plic_o[59]
  PIN tl_u_plic_o[5]
    DIRECTION OUTPUT ;
    USE SIGNAL ;
    ANTENNADIFFAREA 0.445500 ;
    PORT
      LAYER met3 ;
        RECT 0.000 958.840 4.000 959.440 ;
    END
  END tl_u_plic_o[5]
  PIN tl_u_plic_o[60]
    DIRECTION OUTPUT ;
    USE SIGNAL ;
    ANTENNADIFFAREA 0.445500 ;
    PORT
      LAYER met2 ;
        RECT 904.910 1296.000 905.190 1300.000 ;
    END
  END tl_u_plic_o[60]
  PIN tl_u_plic_o[61]
    DIRECTION OUTPUT ;
    USE SIGNAL ;
    ANTENNADIFFAREA 0.445500 ;
    PORT
      LAYER met2 ;
        RECT 592.570 0.000 592.850 4.000 ;
    END
  END tl_u_plic_o[61]
  PIN tl_u_plic_o[62]
    DIRECTION OUTPUT ;
    USE SIGNAL ;
    ANTENNADIFFAREA 0.445500 ;
    PORT
      LAYER met2 ;
        RECT 573.250 0.000 573.530 4.000 ;
    END
  END tl_u_plic_o[62]
  PIN tl_u_plic_o[63]
    DIRECTION OUTPUT ;
    USE SIGNAL ;
    ANTENNADIFFAREA 0.445500 ;
    PORT
      LAYER met2 ;
        RECT 589.350 0.000 589.630 4.000 ;
    END
  END tl_u_plic_o[63]
  PIN tl_u_plic_o[64]
    DIRECTION OUTPUT ;
    USE SIGNAL ;
    ANTENNADIFFAREA 0.445500 ;
    PORT
      LAYER met2 ;
        RECT 537.830 0.000 538.110 4.000 ;
    END
  END tl_u_plic_o[64]
  PIN tl_u_plic_o[65]
    DIRECTION OUTPUT ;
    USE SIGNAL ;
    ANTENNADIFFAREA 0.445500 ;
    PORT
      LAYER met2 ;
        RECT 389.710 0.000 389.990 4.000 ;
    END
  END tl_u_plic_o[65]
  PIN tl_u_plic_o[66]
    DIRECTION OUTPUT ;
    USE SIGNAL ;
    ANTENNADIFFAREA 0.445500 ;
    PORT
      LAYER met2 ;
        RECT 553.930 0.000 554.210 4.000 ;
    END
  END tl_u_plic_o[66]
  PIN tl_u_plic_o[67]
    DIRECTION OUTPUT ;
    USE SIGNAL ;
    ANTENNADIFFAREA 0.445500 ;
    PORT
      LAYER met2 ;
        RECT 541.050 0.000 541.330 4.000 ;
    END
  END tl_u_plic_o[67]
  PIN tl_u_plic_o[68]
    DIRECTION OUTPUT ;
    USE SIGNAL ;
    ANTENNADIFFAREA 0.445500 ;
    PORT
      LAYER met2 ;
        RECT 444.450 0.000 444.730 4.000 ;
    END
  END tl_u_plic_o[68]
  PIN tl_u_plic_o[69]
    DIRECTION OUTPUT ;
    USE SIGNAL ;
    ANTENNADIFFAREA 0.445500 ;
    PORT
      LAYER met2 ;
        RECT 599.010 0.000 599.290 4.000 ;
    END
  END tl_u_plic_o[69]
  PIN tl_u_plic_o[6]
    DIRECTION OUTPUT ;
    USE SIGNAL ;
    ANTENNADIFFAREA 0.445500 ;
    PORT
      LAYER met3 ;
        RECT 0.000 812.640 4.000 813.240 ;
    END
  END tl_u_plic_o[6]
  PIN tl_u_plic_o[70]
    DIRECTION OUTPUT ;
    USE SIGNAL ;
    ANTENNADIFFAREA 0.445500 ;
    PORT
      LAYER met2 ;
        RECT 212.610 0.000 212.890 4.000 ;
    END
  END tl_u_plic_o[70]
  PIN tl_u_plic_o[71]
    DIRECTION OUTPUT ;
    USE SIGNAL ;
    ANTENNADIFFAREA 0.445500 ;
    PORT
      LAYER met2 ;
        RECT 318.870 0.000 319.150 4.000 ;
    END
  END tl_u_plic_o[71]
  PIN tl_u_plic_o[72]
    DIRECTION OUTPUT ;
    USE SIGNAL ;
    ANTENNADIFFAREA 0.445500 ;
    PORT
      LAYER met2 ;
        RECT 586.130 0.000 586.410 4.000 ;
    END
  END tl_u_plic_o[72]
  PIN tl_u_plic_o[73]
    DIRECTION OUTPUT ;
    USE SIGNAL ;
    ANTENNADIFFAREA 0.445500 ;
    PORT
      LAYER met2 ;
        RECT 418.690 0.000 418.970 4.000 ;
    END
  END tl_u_plic_o[73]
  PIN tl_u_plic_o[74]
    DIRECTION OUTPUT ;
    USE SIGNAL ;
    ANTENNADIFFAREA 0.445500 ;
    PORT
      LAYER met2 ;
        RECT 251.250 0.000 251.530 4.000 ;
    END
  END tl_u_plic_o[74]
  PIN tl_u_plic_o[75]
    DIRECTION OUTPUT ;
    USE SIGNAL ;
    ANTENNADIFFAREA 0.445500 ;
    PORT
      LAYER met2 ;
        RECT 373.610 0.000 373.890 4.000 ;
    END
  END tl_u_plic_o[75]
  PIN tl_u_plic_o[76]
    DIRECTION OUTPUT ;
    USE SIGNAL ;
    ANTENNADIFFAREA 0.445500 ;
    PORT
      LAYER met2 ;
        RECT 148.210 0.000 148.490 4.000 ;
    END
  END tl_u_plic_o[76]
  PIN tl_u_plic_o[77]
    DIRECTION OUTPUT ;
    USE SIGNAL ;
    ANTENNADIFFAREA 0.445500 ;
    PORT
      LAYER met2 ;
        RECT 154.650 0.000 154.930 4.000 ;
    END
  END tl_u_plic_o[77]
  PIN tl_u_plic_o[78]
    DIRECTION OUTPUT ;
    USE SIGNAL ;
    ANTENNADIFFAREA 0.445500 ;
    PORT
      LAYER met2 ;
        RECT 180.410 0.000 180.690 4.000 ;
    END
  END tl_u_plic_o[78]
  PIN tl_u_plic_o[79]
    DIRECTION OUTPUT ;
    USE SIGNAL ;
    ANTENNADIFFAREA 0.445500 ;
    PORT
      LAYER met2 ;
        RECT 289.890 0.000 290.170 4.000 ;
    END
  END tl_u_plic_o[79]
  PIN tl_u_plic_o[7]
    DIRECTION OUTPUT ;
    USE SIGNAL ;
    ANTENNADIFFAREA 0.445500 ;
    PORT
      LAYER met2 ;
        RECT 1082.010 0.000 1082.290 4.000 ;
    END
  END tl_u_plic_o[7]
  PIN tl_u_plic_o[80]
    DIRECTION OUTPUT ;
    USE SIGNAL ;
    ANTENNADIFFAREA 0.445500 ;
    PORT
      LAYER met2 ;
        RECT 225.490 0.000 225.770 4.000 ;
    END
  END tl_u_plic_o[80]
  PIN tl_u_plic_o[81]
    DIRECTION OUTPUT ;
    USE SIGNAL ;
    ANTENNADIFFAREA 0.445500 ;
    PORT
      LAYER met2 ;
        RECT 315.650 0.000 315.930 4.000 ;
    END
  END tl_u_plic_o[81]
  PIN tl_u_plic_o[82]
    DIRECTION OUTPUT ;
    USE SIGNAL ;
    ANTENNADIFFAREA 0.445500 ;
    PORT
      LAYER met2 ;
        RECT 183.630 0.000 183.910 4.000 ;
    END
  END tl_u_plic_o[82]
  PIN tl_u_plic_o[83]
    DIRECTION OUTPUT ;
    USE SIGNAL ;
    ANTENNADIFFAREA 0.445500 ;
    PORT
      LAYER met2 ;
        RECT 109.570 0.000 109.850 4.000 ;
    END
  END tl_u_plic_o[83]
  PIN tl_u_plic_o[84]
    DIRECTION OUTPUT ;
    USE SIGNAL ;
    ANTENNADIFFAREA 0.445500 ;
    PORT
      LAYER met2 ;
        RECT 90.250 0.000 90.530 4.000 ;
    END
  END tl_u_plic_o[84]
  PIN tl_u_plic_o[85]
    DIRECTION OUTPUT ;
    USE SIGNAL ;
    ANTENNADIFFAREA 0.445500 ;
    PORT
      LAYER met2 ;
        RECT 405.810 0.000 406.090 4.000 ;
    END
  END tl_u_plic_o[85]
  PIN tl_u_plic_o[86]
    DIRECTION OUTPUT ;
    USE SIGNAL ;
    ANTENNADIFFAREA 0.445500 ;
    PORT
      LAYER met2 ;
        RECT 328.530 0.000 328.810 4.000 ;
    END
  END tl_u_plic_o[86]
  PIN tl_u_plic_o[87]
    DIRECTION OUTPUT ;
    USE SIGNAL ;
    ANTENNADIFFAREA 0.445500 ;
    PORT
      LAYER met2 ;
        RECT 476.650 0.000 476.930 4.000 ;
    END
  END tl_u_plic_o[87]
  PIN tl_u_plic_o[88]
    DIRECTION OUTPUT ;
    USE SIGNAL ;
    ANTENNADIFFAREA 0.445500 ;
    PORT
      LAYER met2 ;
        RECT 402.590 0.000 402.870 4.000 ;
    END
  END tl_u_plic_o[88]
  PIN tl_u_plic_o[89]
    DIRECTION OUTPUT ;
    USE SIGNAL ;
    ANTENNADIFFAREA 0.445500 ;
    PORT
      LAYER met2 ;
        RECT 460.550 0.000 460.830 4.000 ;
    END
  END tl_u_plic_o[89]
  PIN tl_u_plic_o[8]
    DIRECTION OUTPUT ;
    USE SIGNAL ;
    ANTENNADIFFAREA 0.445500 ;
    PORT
      LAYER met2 ;
        RECT 737.470 1296.000 737.750 1300.000 ;
    END
  END tl_u_plic_o[8]
  PIN tl_u_plic_o[90]
    DIRECTION OUTPUT ;
    USE SIGNAL ;
    ANTENNADIFFAREA 0.445500 ;
    PORT
      LAYER met2 ;
        RECT 479.870 0.000 480.150 4.000 ;
    END
  END tl_u_plic_o[90]
  PIN tl_u_plic_o[91]
    DIRECTION OUTPUT ;
    USE SIGNAL ;
    ANTENNADIFFAREA 0.445500 ;
    PORT
      LAYER met2 ;
        RECT 425.130 0.000 425.410 4.000 ;
    END
  END tl_u_plic_o[91]
  PIN tl_u_plic_o[92]
    DIRECTION OUTPUT ;
    USE SIGNAL ;
    ANTENNADIFFAREA 0.445500 ;
    PORT
      LAYER met2 ;
        RECT 470.210 0.000 470.490 4.000 ;
    END
  END tl_u_plic_o[92]
  PIN tl_u_plic_o[93]
    DIRECTION OUTPUT ;
    USE SIGNAL ;
    ANTENNADIFFAREA 0.445500 ;
    PORT
      LAYER met2 ;
        RECT 975.750 1296.000 976.030 1300.000 ;
    END
  END tl_u_plic_o[93]
  PIN tl_u_plic_o[94]
    DIRECTION OUTPUT ;
    USE SIGNAL ;
    ANTENNADIFFAREA 0.445500 ;
    PORT
      LAYER met2 ;
        RECT 1268.770 0.000 1269.050 4.000 ;
    END
  END tl_u_plic_o[94]
  PIN tl_u_plic_o[95]
    DIRECTION OUTPUT ;
    USE SIGNAL ;
    ANTENNADIFFAREA 0.445500 ;
    PORT
      LAYER met2 ;
        RECT 708.490 1296.000 708.770 1300.000 ;
    END
  END tl_u_plic_o[95]
  PIN tl_u_plic_o[96]
    DIRECTION OUTPUT ;
    USE SIGNAL ;
    ANTENNADIFFAREA 0.445500 ;
    PORT
      LAYER met3 ;
        RECT 0.000 843.240 4.000 843.840 ;
    END
  END tl_u_plic_o[96]
  PIN tl_u_plic_o[97]
    DIRECTION OUTPUT ;
    USE SIGNAL ;
    ANTENNADIFFAREA 0.445500 ;
    PORT
      LAYER met2 ;
        RECT 731.030 1296.000 731.310 1300.000 ;
    END
  END tl_u_plic_o[97]
  PIN tl_u_plic_o[98]
    DIRECTION OUTPUT ;
    USE SIGNAL ;
    ANTENNADIFFAREA 0.445500 ;
    PORT
      LAYER met2 ;
        RECT 45.170 0.000 45.450 4.000 ;
    END
  END tl_u_plic_o[98]
  PIN tl_u_plic_o[99]
    DIRECTION OUTPUT ;
    USE SIGNAL ;
    ANTENNADIFFAREA 0.445500 ;
    PORT
      LAYER met3 ;
        RECT 0.000 1023.440 4.000 1024.040 ;
    END
  END tl_u_plic_o[99]
  PIN tl_u_plic_o[9]
    DIRECTION OUTPUT ;
    USE SIGNAL ;
    ANTENNADIFFAREA 0.445500 ;
    PORT
      LAYER met2 ;
        RECT 702.050 1296.000 702.330 1300.000 ;
    END
  END tl_u_plic_o[9]
  PIN tl_u_ram_i[0]
    DIRECTION INPUT ;
    USE SIGNAL ;
    ANTENNAGATEAREA 0.647700 ;
    ANTENNADIFFAREA 0.434700 ;
    PORT
      LAYER met2 ;
        RECT 293.110 0.000 293.390 4.000 ;
    END
  END tl_u_ram_i[0]
  PIN tl_u_ram_i[10]
    DIRECTION INPUT ;
    USE SIGNAL ;
    ANTENNAGATEAREA 0.647700 ;
    ANTENNADIFFAREA 0.434700 ;
    PORT
      LAYER met3 ;
        RECT 0.000 1020.040 4.000 1020.640 ;
    END
  END tl_u_ram_i[10]
  PIN tl_u_ram_i[11]
    DIRECTION INPUT ;
    USE SIGNAL ;
    ANTENNAGATEAREA 0.560700 ;
    ANTENNADIFFAREA 0.434700 ;
    PORT
      LAYER met2 ;
        RECT 647.310 0.000 647.590 4.000 ;
    END
  END tl_u_ram_i[11]
  PIN tl_u_ram_i[12]
    DIRECTION INPUT ;
    USE SIGNAL ;
    ANTENNAGATEAREA 0.560700 ;
    ANTENNADIFFAREA 0.434700 ;
    PORT
      LAYER met2 ;
        RECT 869.490 1296.000 869.770 1300.000 ;
    END
  END tl_u_ram_i[12]
  PIN tl_u_ram_i[13]
    DIRECTION INPUT ;
    USE SIGNAL ;
    ANTENNAGATEAREA 0.647700 ;
    ANTENNADIFFAREA 0.434700 ;
    PORT
      LAYER met2 ;
        RECT 1262.330 0.000 1262.610 4.000 ;
    END
  END tl_u_ram_i[13]
  PIN tl_u_ram_i[14]
    DIRECTION INPUT ;
    USE SIGNAL ;
    ANTENNAGATEAREA 0.631200 ;
    ANTENNADIFFAREA 0.434700 ;
    PORT
      LAYER met3 ;
        RECT 0.000 1207.040 4.000 1207.640 ;
    END
  END tl_u_ram_i[14]
  PIN tl_u_ram_i[15]
    DIRECTION INPUT ;
    USE SIGNAL ;
    ANTENNAGATEAREA 0.560700 ;
    ANTENNADIFFAREA 0.434700 ;
    PORT
      LAYER met2 ;
        RECT 1217.250 0.000 1217.530 4.000 ;
    END
  END tl_u_ram_i[15]
  PIN tl_u_ram_i[16]
    DIRECTION INPUT ;
    USE SIGNAL ;
    ANTENNAGATEAREA 0.593700 ;
    ANTENNADIFFAREA 0.434700 ;
    PORT
      LAYER met2 ;
        RECT 843.730 1296.000 844.010 1300.000 ;
    END
  END tl_u_ram_i[16]
  PIN tl_u_ram_i[17]
    DIRECTION INPUT ;
    USE SIGNAL ;
    ANTENNAGATEAREA 0.593700 ;
    ANTENNADIFFAREA 0.434700 ;
    PORT
      LAYER met2 ;
        RECT 724.590 1296.000 724.870 1300.000 ;
    END
  END tl_u_ram_i[17]
  PIN tl_u_ram_i[18]
    DIRECTION INPUT ;
    USE SIGNAL ;
    ANTENNAGATEAREA 0.647700 ;
    ANTENNADIFFAREA 0.434700 ;
    PORT
      LAYER met2 ;
        RECT 785.770 0.000 786.050 4.000 ;
    END
  END tl_u_ram_i[18]
  PIN tl_u_ram_i[19]
    DIRECTION INPUT ;
    USE SIGNAL ;
    ANTENNAGATEAREA 0.560700 ;
    ANTENNADIFFAREA 0.434700 ;
    PORT
      LAYER met2 ;
        RECT 1136.750 1296.000 1137.030 1300.000 ;
    END
  END tl_u_ram_i[19]
  PIN tl_u_ram_i[1]
    DIRECTION INPUT ;
    USE SIGNAL ;
    ANTENNAGATEAREA 0.631200 ;
    ANTENNADIFFAREA 0.434700 ;
    PORT
      LAYER met2 ;
        RECT 940.330 1296.000 940.610 1300.000 ;
    END
  END tl_u_ram_i[1]
  PIN tl_u_ram_i[20]
    DIRECTION INPUT ;
    USE SIGNAL ;
    ANTENNAGATEAREA 0.560700 ;
    ANTENNADIFFAREA 0.434700 ;
    PORT
      LAYER met2 ;
        RECT 953.210 0.000 953.490 4.000 ;
    END
  END tl_u_ram_i[20]
  PIN tl_u_ram_i[21]
    DIRECTION INPUT ;
    USE SIGNAL ;
    ANTENNAGATEAREA 0.560700 ;
    ANTENNADIFFAREA 0.434700 ;
    PORT
      LAYER met2 ;
        RECT 689.170 0.000 689.450 4.000 ;
    END
  END tl_u_ram_i[21]
  PIN tl_u_ram_i[22]
    DIRECTION INPUT ;
    USE SIGNAL ;
    ANTENNAGATEAREA 0.631200 ;
    ANTENNADIFFAREA 0.434700 ;
    PORT
      LAYER met3 ;
        RECT 0.000 1275.040 4.000 1275.640 ;
    END
  END tl_u_ram_i[22]
  PIN tl_u_ram_i[23]
    DIRECTION INPUT ;
    USE SIGNAL ;
    ANTENNAGATEAREA 0.631200 ;
    ANTENNADIFFAREA 0.434700 ;
    PORT
      LAYER met2 ;
        RECT 830.850 1296.000 831.130 1300.000 ;
    END
  END tl_u_ram_i[23]
  PIN tl_u_ram_i[24]
    DIRECTION INPUT ;
    USE SIGNAL ;
    ANTENNAGATEAREA 0.631200 ;
    ANTENNADIFFAREA 0.434700 ;
    PORT
      LAYER met2 ;
        RECT 875.930 1296.000 876.210 1300.000 ;
    END
  END tl_u_ram_i[24]
  PIN tl_u_ram_i[25]
    DIRECTION INPUT ;
    USE SIGNAL ;
    ANTENNAGATEAREA 0.631200 ;
    ANTENNADIFFAREA 0.434700 ;
    PORT
      LAYER met2 ;
        RECT 1059.470 1296.000 1059.750 1300.000 ;
    END
  END tl_u_ram_i[25]
  PIN tl_u_ram_i[26]
    DIRECTION INPUT ;
    USE SIGNAL ;
    ANTENNAGATEAREA 0.647700 ;
    ANTENNADIFFAREA 0.434700 ;
    PORT
      LAYER met2 ;
        RECT 1156.070 1296.000 1156.350 1300.000 ;
    END
  END tl_u_ram_i[26]
  PIN tl_u_ram_i[27]
    DIRECTION INPUT ;
    USE SIGNAL ;
    ANTENNAGATEAREA 0.560700 ;
    ANTENNADIFFAREA 0.434700 ;
    PORT
      LAYER met2 ;
        RECT 1162.510 0.000 1162.790 4.000 ;
    END
  END tl_u_ram_i[27]
  PIN tl_u_ram_i[28]
    DIRECTION INPUT ;
    USE SIGNAL ;
    ANTENNAGATEAREA 0.647700 ;
    ANTENNADIFFAREA 0.434700 ;
    PORT
      LAYER met2 ;
        RECT 756.790 0.000 757.070 4.000 ;
    END
  END tl_u_ram_i[28]
  PIN tl_u_ram_i[29]
    DIRECTION INPUT ;
    USE SIGNAL ;
    ANTENNAGATEAREA 0.593700 ;
    ANTENNADIFFAREA 0.434700 ;
    PORT
      LAYER met2 ;
        RECT 772.890 1296.000 773.170 1300.000 ;
    END
  END tl_u_ram_i[29]
  PIN tl_u_ram_i[2]
    DIRECTION INPUT ;
    USE SIGNAL ;
    ANTENNAGATEAREA 0.560700 ;
    ANTENNADIFFAREA 0.434700 ;
    PORT
      LAYER met2 ;
        RECT 805.090 1296.000 805.370 1300.000 ;
    END
  END tl_u_ram_i[2]
  PIN tl_u_ram_i[30]
    DIRECTION INPUT ;
    USE SIGNAL ;
    ANTENNAGATEAREA 0.631200 ;
    ANTENNADIFFAREA 0.434700 ;
    PORT
      LAYER met2 ;
        RECT 798.650 0.000 798.930 4.000 ;
    END
  END tl_u_ram_i[30]
  PIN tl_u_ram_i[31]
    DIRECTION INPUT ;
    USE SIGNAL ;
    ANTENNAGATEAREA 0.682200 ;
    ANTENNADIFFAREA 0.434700 ;
    PORT
      LAYER met3 ;
        RECT 0.000 907.840 4.000 908.440 ;
    END
  END tl_u_ram_i[31]
  PIN tl_u_ram_i[32]
    DIRECTION INPUT ;
    USE SIGNAL ;
    ANTENNAGATEAREA 0.631200 ;
    ANTENNADIFFAREA 0.434700 ;
    PORT
      LAYER met2 ;
        RECT 1024.050 0.000 1024.330 4.000 ;
    END
  END tl_u_ram_i[32]
  PIN tl_u_ram_i[33]
    DIRECTION INPUT ;
    USE SIGNAL ;
    ANTENNAGATEAREA 0.647700 ;
    ANTENNADIFFAREA 0.434700 ;
    PORT
      LAYER met2 ;
        RECT 856.610 1296.000 856.890 1300.000 ;
    END
  END tl_u_ram_i[33]
  PIN tl_u_ram_i[34]
    DIRECTION INPUT ;
    USE SIGNAL ;
    ANTENNAGATEAREA 0.682200 ;
    ANTENNADIFFAREA 0.434700 ;
    PORT
      LAYER met2 ;
        RECT 930.670 1296.000 930.950 1300.000 ;
    END
  END tl_u_ram_i[34]
  PIN tl_u_ram_i[35]
    DIRECTION INPUT ;
    USE SIGNAL ;
    ANTENNAGATEAREA 0.631200 ;
    ANTENNADIFFAREA 0.434700 ;
    PORT
      LAYER met2 ;
        RECT 1069.130 1296.000 1069.410 1300.000 ;
    END
  END tl_u_ram_i[35]
  PIN tl_u_ram_i[36]
    DIRECTION INPUT ;
    USE SIGNAL ;
    ANTENNAGATEAREA 0.631200 ;
    ANTENNADIFFAREA 0.434700 ;
    PORT
      LAYER met2 ;
        RECT 1259.110 1296.000 1259.390 1300.000 ;
    END
  END tl_u_ram_i[36]
  PIN tl_u_ram_i[37]
    DIRECTION INPUT ;
    USE SIGNAL ;
    ANTENNAGATEAREA 0.593700 ;
    ANTENNADIFFAREA 0.434700 ;
    PORT
      LAYER met2 ;
        RECT 673.070 0.000 673.350 4.000 ;
    END
  END tl_u_ram_i[37]
  PIN tl_u_ram_i[38]
    DIRECTION INPUT ;
    USE SIGNAL ;
    ANTENNAGATEAREA 0.647700 ;
    ANTENNADIFFAREA 0.434700 ;
    PORT
      LAYER met3 ;
        RECT 0.000 1285.240 4.000 1285.840 ;
    END
  END tl_u_ram_i[38]
  PIN tl_u_ram_i[39]
    DIRECTION INPUT ;
    USE SIGNAL ;
    ANTENNAGATEAREA 0.631200 ;
    ANTENNADIFFAREA 0.434700 ;
    PORT
      LAYER met2 ;
        RECT 1027.270 0.000 1027.550 4.000 ;
    END
  END tl_u_ram_i[39]
  PIN tl_u_ram_i[3]
    DIRECTION INPUT ;
    USE SIGNAL ;
    ANTENNAGATEAREA 0.631200 ;
    ANTENNADIFFAREA 0.434700 ;
    PORT
      LAYER met2 ;
        RECT 995.070 1296.000 995.350 1300.000 ;
    END
  END tl_u_ram_i[3]
  PIN tl_u_ram_i[40]
    DIRECTION INPUT ;
    USE SIGNAL ;
    ANTENNAGATEAREA 0.647700 ;
    ANTENNADIFFAREA 0.434700 ;
    PORT
      LAYER met2 ;
        RECT 1152.850 1296.000 1153.130 1300.000 ;
    END
  END tl_u_ram_i[40]
  PIN tl_u_ram_i[41]
    DIRECTION INPUT ;
    USE SIGNAL ;
    ANTENNAGATEAREA 0.631200 ;
    ANTENNADIFFAREA 0.434700 ;
    PORT
      LAYER met2 ;
        RECT 1143.190 1296.000 1143.470 1300.000 ;
    END
  END tl_u_ram_i[41]
  PIN tl_u_ram_i[42]
    DIRECTION INPUT ;
    USE SIGNAL ;
    ANTENNAGATEAREA 0.593700 ;
    ANTENNADIFFAREA 0.434700 ;
    PORT
      LAYER met2 ;
        RECT 1223.690 1296.000 1223.970 1300.000 ;
    END
  END tl_u_ram_i[42]
  PIN tl_u_ram_i[43]
    DIRECTION INPUT ;
    USE SIGNAL ;
    ANTENNAGATEAREA 0.682200 ;
    ANTENNADIFFAREA 0.434700 ;
    PORT
      LAYER met2 ;
        RECT 766.450 0.000 766.730 4.000 ;
    END
  END tl_u_ram_i[43]
  PIN tl_u_ram_i[44]
    DIRECTION INPUT ;
    USE SIGNAL ;
    ANTENNAGATEAREA 0.631200 ;
    ANTENNADIFFAREA 0.434700 ;
    PORT
      LAYER met2 ;
        RECT 1030.490 1296.000 1030.770 1300.000 ;
    END
  END tl_u_ram_i[44]
  PIN tl_u_ram_i[45]
    DIRECTION INPUT ;
    USE SIGNAL ;
    ANTENNAGATEAREA 0.593700 ;
    ANTENNADIFFAREA 0.434700 ;
    PORT
      LAYER met2 ;
        RECT 814.750 1296.000 815.030 1300.000 ;
    END
  END tl_u_ram_i[45]
  PIN tl_u_ram_i[46]
    DIRECTION INPUT ;
    USE SIGNAL ;
    ANTENNAGATEAREA 0.560700 ;
    ANTENNADIFFAREA 0.434700 ;
    PORT
      LAYER met2 ;
        RECT 1043.370 1296.000 1043.650 1300.000 ;
    END
  END tl_u_ram_i[46]
  PIN tl_u_ram_i[47]
    DIRECTION INPUT ;
    USE SIGNAL ;
    ANTENNAGATEAREA 0.631200 ;
    ANTENNADIFFAREA 0.434700 ;
    PORT
      LAYER met2 ;
        RECT 850.170 1296.000 850.450 1300.000 ;
    END
  END tl_u_ram_i[47]
  PIN tl_u_ram_i[48]
    DIRECTION INPUT ;
    USE SIGNAL ;
    ANTENNAGATEAREA 0.631200 ;
    ANTENNADIFFAREA 0.434700 ;
    PORT
      LAYER met3 ;
        RECT 0.000 1152.640 4.000 1153.240 ;
    END
  END tl_u_ram_i[48]
  PIN tl_u_ram_i[49]
    DIRECTION INPUT ;
    USE SIGNAL ;
    ANTENNAGATEAREA 0.631200 ;
    ANTENNADIFFAREA 0.434700 ;
    PORT
      LAYER met2 ;
        RECT 1252.670 1296.000 1252.950 1300.000 ;
    END
  END tl_u_ram_i[49]
  PIN tl_u_ram_i[4]
    DIRECTION INPUT ;
    USE SIGNAL ;
    ANTENNAGATEAREA 0.560700 ;
    ANTENNADIFFAREA 0.434700 ;
    PORT
      LAYER met2 ;
        RECT 895.250 0.000 895.530 4.000 ;
    END
  END tl_u_ram_i[4]
  PIN tl_u_ram_i[50]
    DIRECTION INPUT ;
    USE SIGNAL ;
    ANTENNAGATEAREA 0.682200 ;
    ANTENNADIFFAREA 0.434700 ;
    PORT
      LAYER met3 ;
        RECT 0.000 1298.840 4.000 1299.440 ;
    END
  END tl_u_ram_i[50]
  PIN tl_u_ram_i[51]
    DIRECTION INPUT ;
    USE SIGNAL ;
    ANTENNAGATEAREA 0.647700 ;
    ANTENNADIFFAREA 0.434700 ;
    PORT
      LAYER met2 ;
        RECT 1011.170 1296.000 1011.450 1300.000 ;
    END
  END tl_u_ram_i[51]
  PIN tl_u_ram_i[52]
    DIRECTION INPUT ;
    USE SIGNAL ;
    ANTENNAGATEAREA 0.631200 ;
    ANTENNADIFFAREA 0.434700 ;
    PORT
      LAYER met2 ;
        RECT 943.550 1296.000 943.830 1300.000 ;
    END
  END tl_u_ram_i[52]
  PIN tl_u_ram_i[53]
    DIRECTION INPUT ;
    USE SIGNAL ;
    ANTENNAGATEAREA 0.647700 ;
    ANTENNADIFFAREA 0.434700 ;
    PORT
      LAYER met3 ;
        RECT 0.000 1234.240 4.000 1234.840 ;
    END
  END tl_u_ram_i[53]
  PIN tl_u_ram_i[54]
    DIRECTION INPUT ;
    USE SIGNAL ;
    ANTENNAGATEAREA 0.647700 ;
    ANTENNADIFFAREA 0.434700 ;
    PORT
      LAYER met2 ;
        RECT 1243.010 0.000 1243.290 4.000 ;
    END
  END tl_u_ram_i[54]
  PIN tl_u_ram_i[55]
    DIRECTION INPUT ;
    USE SIGNAL ;
    ANTENNAGATEAREA 0.631200 ;
    ANTENNADIFFAREA 0.434700 ;
    PORT
      LAYER met2 ;
        RECT 1104.550 0.000 1104.830 4.000 ;
    END
  END tl_u_ram_i[55]
  PIN tl_u_ram_i[56]
    DIRECTION INPUT ;
    USE SIGNAL ;
    ANTENNAGATEAREA 0.631200 ;
    ANTENNADIFFAREA 0.434700 ;
    PORT
      LAYER met3 ;
        RECT 0.000 911.240 4.000 911.840 ;
    END
  END tl_u_ram_i[56]
  PIN tl_u_ram_i[57]
    DIRECTION INPUT ;
    USE SIGNAL ;
    ANTENNAGATEAREA 0.593700 ;
    ANTENNADIFFAREA 0.434700 ;
    PORT
      LAYER met2 ;
        RECT 1172.170 0.000 1172.450 4.000 ;
    END
  END tl_u_ram_i[57]
  PIN tl_u_ram_i[58]
    DIRECTION INPUT ;
    USE SIGNAL ;
    ANTENNAGATEAREA 0.631200 ;
    ANTENNADIFFAREA 0.434700 ;
    PORT
      LAYER met2 ;
        RECT 982.190 1296.000 982.470 1300.000 ;
    END
  END tl_u_ram_i[58]
  PIN tl_u_ram_i[59]
    DIRECTION INPUT ;
    USE SIGNAL ;
    ANTENNAGATEAREA 0.593700 ;
    ANTENNADIFFAREA 0.434700 ;
    PORT
      LAYER met2 ;
        RECT 1159.290 1296.000 1159.570 1300.000 ;
    END
  END tl_u_ram_i[59]
  PIN tl_u_ram_i[5]
    DIRECTION INPUT ;
    USE SIGNAL ;
    ANTENNAGATEAREA 0.631200 ;
    ANTENNADIFFAREA 0.434700 ;
    PORT
      LAYER met2 ;
        RECT 1201.150 1296.000 1201.430 1300.000 ;
    END
  END tl_u_ram_i[5]
  PIN tl_u_ram_i[60]
    DIRECTION INPUT ;
    USE SIGNAL ;
    ANTENNAGATEAREA 0.631200 ;
    ANTENNADIFFAREA 0.434700 ;
    PORT
      LAYER met3 ;
        RECT 0.000 873.840 4.000 874.440 ;
    END
  END tl_u_ram_i[60]
  PIN tl_u_ram_i[61]
    DIRECTION INPUT ;
    USE SIGNAL ;
    ANTENNAGATEAREA 0.647700 ;
    ANTENNADIFFAREA 0.434700 ;
    PORT
      LAYER met2 ;
        RECT 969.310 1296.000 969.590 1300.000 ;
    END
  END tl_u_ram_i[61]
  PIN tl_u_ram_i[62]
    DIRECTION INPUT ;
    USE SIGNAL ;
    ANTENNAGATEAREA 0.593700 ;
    ANTENNADIFFAREA 0.434700 ;
    PORT
      LAYER met2 ;
        RECT 962.870 1296.000 963.150 1300.000 ;
    END
  END tl_u_ram_i[62]
  PIN tl_u_ram_i[63]
    DIRECTION INPUT ;
    USE SIGNAL ;
    ANTENNAGATEAREA 0.860700 ;
    ANTENNADIFFAREA 0.434700 ;
    PORT
      LAYER met3 ;
        RECT 0.000 1067.640 4.000 1068.240 ;
    END
  END tl_u_ram_i[63]
  PIN tl_u_ram_i[64]
    DIRECTION INPUT ;
    USE SIGNAL ;
    ANTENNAGATEAREA 0.631200 ;
    ANTENNADIFFAREA 0.434700 ;
    PORT
      LAYER met2 ;
        RECT 1197.930 1296.000 1198.210 1300.000 ;
    END
  END tl_u_ram_i[64]
  PIN tl_u_ram_i[65]
    DIRECTION INPUT ;
    USE SIGNAL ;
    ANTENNAGATEAREA 0.593700 ;
    ANTENNADIFFAREA 0.434700 ;
    PORT
      LAYER met2 ;
        RECT 1117.430 1296.000 1117.710 1300.000 ;
    END
  END tl_u_ram_i[65]
  PIN tl_u_ram_i[6]
    DIRECTION INPUT ;
    USE SIGNAL ;
    ANTENNAGATEAREA 0.631200 ;
    ANTENNADIFFAREA 0.434700 ;
    PORT
      LAYER met2 ;
        RECT 1075.570 1296.000 1075.850 1300.000 ;
    END
  END tl_u_ram_i[6]
  PIN tl_u_ram_i[7]
    DIRECTION INPUT ;
    USE SIGNAL ;
    ANTENNAGATEAREA 0.631200 ;
    ANTENNADIFFAREA 0.434700 ;
    PORT
      LAYER met2 ;
        RECT 1255.890 1296.000 1256.170 1300.000 ;
    END
  END tl_u_ram_i[7]
  PIN tl_u_ram_i[8]
    DIRECTION INPUT ;
    USE SIGNAL ;
    ANTENNAGATEAREA 0.631200 ;
    ANTENNADIFFAREA 0.434700 ;
    PORT
      LAYER met2 ;
        RECT 685.950 0.000 686.230 4.000 ;
    END
  END tl_u_ram_i[8]
  PIN tl_u_ram_i[9]
    DIRECTION INPUT ;
    USE SIGNAL ;
    ANTENNAGATEAREA 0.647700 ;
    ANTENNADIFFAREA 0.434700 ;
    PORT
      LAYER met2 ;
        RECT 972.530 1296.000 972.810 1300.000 ;
    END
  END tl_u_ram_i[9]
  PIN tl_u_ram_o[0]
    DIRECTION OUTPUT ;
    USE SIGNAL ;
    ANTENNADIFFAREA 0.445500 ;
    PORT
      LAYER met3 ;
        RECT 0.000 1084.640 4.000 1085.240 ;
    END
  END tl_u_ram_o[0]
  PIN tl_u_ram_o[100]
    DIRECTION OUTPUT ;
    USE SIGNAL ;
    ANTENNADIFFAREA 0.445500 ;
    PORT
      LAYER met3 ;
        RECT 0.000 1142.440 4.000 1143.040 ;
    END
  END tl_u_ram_o[100]
  PIN tl_u_ram_o[101]
    DIRECTION OUTPUT ;
    USE SIGNAL ;
    ANTENNADIFFAREA 0.445500 ;
    PORT
      LAYER met2 ;
        RECT 1201.150 0.000 1201.430 4.000 ;
    END
  END tl_u_ram_o[101]
  PIN tl_u_ram_o[102]
    DIRECTION OUTPUT ;
    USE SIGNAL ;
    ANTENNADIFFAREA 0.445500 ;
    PORT
      LAYER met3 ;
        RECT 0.000 703.840 4.000 704.440 ;
    END
  END tl_u_ram_o[102]
  PIN tl_u_ram_o[103]
    DIRECTION OUTPUT ;
    USE SIGNAL ;
    ANTENNADIFFAREA 0.445500 ;
    PORT
      LAYER met2 ;
        RECT 1136.750 0.000 1137.030 4.000 ;
    END
  END tl_u_ram_o[103]
  PIN tl_u_ram_o[104]
    DIRECTION OUTPUT ;
    USE SIGNAL ;
    ANTENNADIFFAREA 0.445500 ;
    PORT
      LAYER met2 ;
        RECT 962.870 0.000 963.150 4.000 ;
    END
  END tl_u_ram_o[104]
  PIN tl_u_ram_o[105]
    DIRECTION OUTPUT ;
    USE SIGNAL ;
    ANTENNADIFFAREA 0.445500 ;
    PORT
      LAYER met3 ;
        RECT 0.000 642.640 4.000 643.240 ;
    END
  END tl_u_ram_o[105]
  PIN tl_u_ram_o[106]
    DIRECTION OUTPUT ;
    USE SIGNAL ;
    ANTENNADIFFAREA 0.445500 ;
    PORT
      LAYER met2 ;
        RECT 32.290 0.000 32.570 4.000 ;
    END
  END tl_u_ram_o[106]
  PIN tl_u_ram_o[107]
    DIRECTION OUTPUT ;
    USE SIGNAL ;
    ANTENNADIFFAREA 0.445500 ;
    PORT
      LAYER met3 ;
        RECT 0.000 1003.040 4.000 1003.640 ;
    END
  END tl_u_ram_o[107]
  PIN tl_u_ram_o[108]
    DIRECTION OUTPUT ;
    USE SIGNAL ;
    ANTENNADIFFAREA 0.445500 ;
    PORT
      LAYER met2 ;
        RECT 566.810 0.000 567.090 4.000 ;
    END
  END tl_u_ram_o[108]
  PIN tl_u_ram_o[109]
    DIRECTION OUTPUT ;
    USE SIGNAL ;
    ANTENNADIFFAREA 0.445500 ;
    PORT
      LAYER met2 ;
        RECT 344.630 0.000 344.910 4.000 ;
    END
  END tl_u_ram_o[109]
  PIN tl_u_ram_o[10]
    DIRECTION OUTPUT ;
    USE SIGNAL ;
    ANTENNADIFFAREA 0.445500 ;
    PORT
      LAYER met2 ;
        RECT 167.530 0.000 167.810 4.000 ;
    END
  END tl_u_ram_o[10]
  PIN tl_u_ram_o[11]
    DIRECTION OUTPUT ;
    USE SIGNAL ;
    ANTENNADIFFAREA 0.445500 ;
    PORT
      LAYER met2 ;
        RECT 814.750 0.000 815.030 4.000 ;
    END
  END tl_u_ram_o[11]
  PIN tl_u_ram_o[12]
    DIRECTION OUTPUT ;
    USE SIGNAL ;
    ANTENNADIFFAREA 0.445500 ;
    PORT
      LAYER met3 ;
        RECT 0.000 1179.840 4.000 1180.440 ;
    END
  END tl_u_ram_o[12]
  PIN tl_u_ram_o[13]
    DIRECTION OUTPUT ;
    USE SIGNAL ;
    ANTENNADIFFAREA 0.445500 ;
    PORT
      LAYER met2 ;
        RECT 682.730 1296.000 683.010 1300.000 ;
    END
  END tl_u_ram_o[13]
  PIN tl_u_ram_o[14]
    DIRECTION OUTPUT ;
    USE SIGNAL ;
    ANTENNADIFFAREA 0.445500 ;
    PORT
      LAYER met2 ;
        RECT 531.390 0.000 531.670 4.000 ;
    END
  END tl_u_ram_o[14]
  PIN tl_u_ram_o[15]
    DIRECTION OUTPUT ;
    USE SIGNAL ;
    ANTENNADIFFAREA 0.445500 ;
    PORT
      LAYER met2 ;
        RECT 518.510 0.000 518.790 4.000 ;
    END
  END tl_u_ram_o[15]
  PIN tl_u_ram_o[16]
    DIRECTION OUTPUT ;
    USE SIGNAL ;
    ANTENNADIFFAREA 0.445500 ;
    PORT
      LAYER met2 ;
        RECT 750.350 0.000 750.630 4.000 ;
    END
  END tl_u_ram_o[16]
  PIN tl_u_ram_o[17]
    DIRECTION OUTPUT ;
    USE SIGNAL ;
    ANTENNADIFFAREA 0.445500 ;
    PORT
      LAYER met2 ;
        RECT 895.250 1296.000 895.530 1300.000 ;
    END
  END tl_u_ram_o[17]
  PIN tl_u_ram_o[18]
    DIRECTION OUTPUT ;
    USE SIGNAL ;
    ANTENNADIFFAREA 0.445500 ;
    PORT
      LAYER met2 ;
        RECT 673.070 1296.000 673.350 1300.000 ;
    END
  END tl_u_ram_o[18]
  PIN tl_u_ram_o[19]
    DIRECTION OUTPUT ;
    USE SIGNAL ;
    ANTENNADIFFAREA 0.445500 ;
    PORT
      LAYER met3 ;
        RECT 0.000 673.240 4.000 673.840 ;
    END
  END tl_u_ram_o[19]
  PIN tl_u_ram_o[1]
    DIRECTION OUTPUT ;
    USE SIGNAL ;
    ANTENNADIFFAREA 0.445500 ;
    PORT
      LAYER met3 ;
        RECT 0.000 802.440 4.000 803.040 ;
    END
  END tl_u_ram_o[1]
  PIN tl_u_ram_o[20]
    DIRECTION OUTPUT ;
    USE SIGNAL ;
    ANTENNADIFFAREA 0.445500 ;
    PORT
      LAYER met2 ;
        RECT 615.110 0.000 615.390 4.000 ;
    END
  END tl_u_ram_o[20]
  PIN tl_u_ram_o[21]
    DIRECTION OUTPUT ;
    USE SIGNAL ;
    ANTENNADIFFAREA 0.445500 ;
    PORT
      LAYER met2 ;
        RECT 859.830 0.000 860.110 4.000 ;
    END
  END tl_u_ram_o[21]
  PIN tl_u_ram_o[22]
    DIRECTION OUTPUT ;
    USE SIGNAL ;
    ANTENNADIFFAREA 0.445500 ;
    PORT
      LAYER met2 ;
        RECT 750.350 1296.000 750.630 1300.000 ;
    END
  END tl_u_ram_o[22]
  PIN tl_u_ram_o[23]
    DIRECTION OUTPUT ;
    USE SIGNAL ;
    ANTENNADIFFAREA 0.445500 ;
    PORT
      LAYER met2 ;
        RECT 67.710 0.000 67.990 4.000 ;
    END
  END tl_u_ram_o[23]
  PIN tl_u_ram_o[24]
    DIRECTION OUTPUT ;
    USE SIGNAL ;
    ANTENNADIFFAREA 0.445500 ;
    PORT
      LAYER met3 ;
        RECT 0.000 975.840 4.000 976.440 ;
    END
  END tl_u_ram_o[24]
  PIN tl_u_ram_o[25]
    DIRECTION OUTPUT ;
    USE SIGNAL ;
    ANTENNADIFFAREA 0.445500 ;
    PORT
      LAYER met2 ;
        RECT 70.930 0.000 71.210 4.000 ;
    END
  END tl_u_ram_o[25]
  PIN tl_u_ram_o[26]
    DIRECTION OUTPUT ;
    USE SIGNAL ;
    ANTENNADIFFAREA 0.445500 ;
    PORT
      LAYER met3 ;
        RECT 0.000 955.440 4.000 956.040 ;
    END
  END tl_u_ram_o[26]
  PIN tl_u_ram_o[27]
    DIRECTION OUTPUT ;
    USE SIGNAL ;
    ANTENNADIFFAREA 0.445500 ;
    PORT
      LAYER met2 ;
        RECT 631.210 0.000 631.490 4.000 ;
    END
  END tl_u_ram_o[27]
  PIN tl_u_ram_o[28]
    DIRECTION OUTPUT ;
    USE SIGNAL ;
    ANTENNADIFFAREA 0.445500 ;
    PORT
      LAYER met2 ;
        RECT 904.910 0.000 905.190 4.000 ;
    END
  END tl_u_ram_o[28]
  PIN tl_u_ram_o[29]
    DIRECTION OUTPUT ;
    USE SIGNAL ;
    ANTENNADIFFAREA 0.445500 ;
    PORT
      LAYER met2 ;
        RECT 489.530 0.000 489.810 4.000 ;
    END
  END tl_u_ram_o[29]
  PIN tl_u_ram_o[2]
    DIRECTION OUTPUT ;
    USE SIGNAL ;
    ANTENNADIFFAREA 0.445500 ;
    PORT
      LAYER met3 ;
        RECT 0.000 1244.440 4.000 1245.040 ;
    END
  END tl_u_ram_o[2]
  PIN tl_u_ram_o[30]
    DIRECTION OUTPUT ;
    USE SIGNAL ;
    ANTENNADIFFAREA 0.445500 ;
    PORT
      LAYER met2 ;
        RECT 756.790 1296.000 757.070 1300.000 ;
    END
  END tl_u_ram_o[30]
  PIN tl_u_ram_o[31]
    DIRECTION OUTPUT ;
    USE SIGNAL ;
    ANTENNADIFFAREA 0.445500 ;
    PORT
      LAYER met2 ;
        RECT 1053.030 0.000 1053.310 4.000 ;
    END
  END tl_u_ram_o[31]
  PIN tl_u_ram_o[32]
    DIRECTION OUTPUT ;
    USE SIGNAL ;
    ANTENNADIFFAREA 0.445500 ;
    PORT
      LAYER met2 ;
        RECT 1204.370 0.000 1204.650 4.000 ;
    END
  END tl_u_ram_o[32]
  PIN tl_u_ram_o[33]
    DIRECTION OUTPUT ;
    USE SIGNAL ;
    ANTENNADIFFAREA 0.445500 ;
    PORT
      LAYER met2 ;
        RECT 602.230 0.000 602.510 4.000 ;
    END
  END tl_u_ram_o[33]
  PIN tl_u_ram_o[34]
    DIRECTION OUTPUT ;
    USE SIGNAL ;
    ANTENNADIFFAREA 0.445500 ;
    PORT
      LAYER met2 ;
        RECT 16.190 0.000 16.470 4.000 ;
    END
  END tl_u_ram_o[34]
  PIN tl_u_ram_o[35]
    DIRECTION OUTPUT ;
    USE SIGNAL ;
    ANTENNADIFFAREA 0.445500 ;
    PORT
      LAYER met2 ;
        RECT 837.290 0.000 837.570 4.000 ;
    END
  END tl_u_ram_o[35]
  PIN tl_u_ram_o[36]
    DIRECTION OUTPUT ;
    USE SIGNAL ;
    ANTENNADIFFAREA 0.445500 ;
    PORT
      LAYER met3 ;
        RECT 0.000 887.440 4.000 888.040 ;
    END
  END tl_u_ram_o[36]
  PIN tl_u_ram_o[37]
    DIRECTION OUTPUT ;
    USE SIGNAL ;
    ANTENNADIFFAREA 0.445500 ;
    PORT
      LAYER met2 ;
        RECT 840.510 0.000 840.790 4.000 ;
    END
  END tl_u_ram_o[37]
  PIN tl_u_ram_o[38]
    DIRECTION OUTPUT ;
    USE SIGNAL ;
    ANTENNADIFFAREA 0.445500 ;
    PORT
      LAYER met2 ;
        RECT 99.910 0.000 100.190 4.000 ;
    END
  END tl_u_ram_o[38]
  PIN tl_u_ram_o[39]
    DIRECTION OUTPUT ;
    USE SIGNAL ;
    ANTENNADIFFAREA 0.445500 ;
    PORT
      LAYER met2 ;
        RECT 792.210 0.000 792.490 4.000 ;
    END
  END tl_u_ram_o[39]
  PIN tl_u_ram_o[3]
    DIRECTION OUTPUT ;
    USE SIGNAL ;
    ANTENNADIFFAREA 0.445500 ;
    PORT
      LAYER met2 ;
        RECT 863.050 0.000 863.330 4.000 ;
    END
  END tl_u_ram_o[3]
  PIN tl_u_ram_o[40]
    DIRECTION OUTPUT ;
    USE SIGNAL ;
    ANTENNADIFFAREA 0.445500 ;
    PORT
      LAYER met3 ;
        RECT 0.000 1111.840 4.000 1112.440 ;
    END
  END tl_u_ram_o[40]
  PIN tl_u_ram_o[41]
    DIRECTION OUTPUT ;
    USE SIGNAL ;
    ANTENNADIFFAREA 0.445500 ;
    PORT
      LAYER met2 ;
        RECT 1001.510 0.000 1001.790 4.000 ;
    END
  END tl_u_ram_o[41]
  PIN tl_u_ram_o[42]
    DIRECTION OUTPUT ;
    USE SIGNAL ;
    ANTENNADIFFAREA 0.445500 ;
    PORT
      LAYER met2 ;
        RECT 821.190 0.000 821.470 4.000 ;
    END
  END tl_u_ram_o[42]
  PIN tl_u_ram_o[43]
    DIRECTION OUTPUT ;
    USE SIGNAL ;
    ANTENNADIFFAREA 0.445500 ;
    PORT
      LAYER met2 ;
        RECT 51.610 0.000 51.890 4.000 ;
    END
  END tl_u_ram_o[43]
  PIN tl_u_ram_o[44]
    DIRECTION OUTPUT ;
    USE SIGNAL ;
    ANTENNADIFFAREA 0.445500 ;
    PORT
      LAYER met3 ;
        RECT 0.000 1132.240 4.000 1132.840 ;
    END
  END tl_u_ram_o[44]
  PIN tl_u_ram_o[45]
    DIRECTION OUTPUT ;
    USE SIGNAL ;
    ANTENNADIFFAREA 0.445500 ;
    PORT
      LAYER met2 ;
        RECT 1007.950 0.000 1008.230 4.000 ;
    END
  END tl_u_ram_o[45]
  PIN tl_u_ram_o[46]
    DIRECTION OUTPUT ;
    USE SIGNAL ;
    ANTENNADIFFAREA 0.445500 ;
    PORT
      LAYER met2 ;
        RECT 705.270 1296.000 705.550 1300.000 ;
    END
  END tl_u_ram_o[46]
  PIN tl_u_ram_o[47]
    DIRECTION OUTPUT ;
    USE SIGNAL ;
    ANTENNADIFFAREA 0.445500 ;
    PORT
      LAYER met3 ;
        RECT 0.000 989.440 4.000 990.040 ;
    END
  END tl_u_ram_o[47]
  PIN tl_u_ram_o[48]
    DIRECTION OUTPUT ;
    USE SIGNAL ;
    ANTENNADIFFAREA 0.445500 ;
    PORT
      LAYER met3 ;
        RECT 0.000 986.040 4.000 986.640 ;
    END
  END tl_u_ram_o[48]
  PIN tl_u_ram_o[49]
    DIRECTION OUTPUT ;
    USE SIGNAL ;
    ANTENNADIFFAREA 0.445500 ;
    PORT
      LAYER met3 ;
        RECT 0.000 737.840 4.000 738.440 ;
    END
  END tl_u_ram_o[49]
  PIN tl_u_ram_o[4]
    DIRECTION OUTPUT ;
    USE SIGNAL ;
    ANTENNADIFFAREA 0.445500 ;
    PORT
      LAYER met2 ;
        RECT 634.430 0.000 634.710 4.000 ;
    END
  END tl_u_ram_o[4]
  PIN tl_u_ram_o[50]
    DIRECTION OUTPUT ;
    USE SIGNAL ;
    ANTENNADIFFAREA 0.445500 ;
    PORT
      LAYER met2 ;
        RECT 743.910 0.000 744.190 4.000 ;
    END
  END tl_u_ram_o[50]
  PIN tl_u_ram_o[51]
    DIRECTION OUTPUT ;
    USE SIGNAL ;
    ANTENNADIFFAREA 0.445500 ;
    PORT
      LAYER met3 ;
        RECT 0.000 680.040 4.000 680.640 ;
    END
  END tl_u_ram_o[51]
  PIN tl_u_ram_o[52]
    DIRECTION OUTPUT ;
    USE SIGNAL ;
    ANTENNADIFFAREA 0.445500 ;
    PORT
      LAYER met2 ;
        RECT 988.630 0.000 988.910 4.000 ;
    END
  END tl_u_ram_o[52]
  PIN tl_u_ram_o[53]
    DIRECTION OUTPUT ;
    USE SIGNAL ;
    ANTENNADIFFAREA 0.445500 ;
    PORT
      LAYER met2 ;
        RECT 1220.470 0.000 1220.750 4.000 ;
    END
  END tl_u_ram_o[53]
  PIN tl_u_ram_o[54]
    DIRECTION OUTPUT ;
    USE SIGNAL ;
    ANTENNADIFFAREA 0.445500 ;
    PORT
      LAYER met3 ;
        RECT 0.000 884.040 4.000 884.640 ;
    END
  END tl_u_ram_o[54]
  PIN tl_u_ram_o[55]
    DIRECTION OUTPUT ;
    USE SIGNAL ;
    ANTENNADIFFAREA 0.445500 ;
    PORT
      LAYER met3 ;
        RECT 0.000 1064.240 4.000 1064.840 ;
    END
  END tl_u_ram_o[55]
  PIN tl_u_ram_o[56]
    DIRECTION OUTPUT ;
    USE SIGNAL ;
    ANTENNADIFFAREA 0.445500 ;
    PORT
      LAYER met3 ;
        RECT 0.000 1278.440 4.000 1279.040 ;
    END
  END tl_u_ram_o[56]
  PIN tl_u_ram_o[57]
    DIRECTION OUTPUT ;
    USE SIGNAL ;
    ANTENNADIFFAREA 0.445500 ;
    PORT
      LAYER met3 ;
        RECT 0.000 996.240 4.000 996.840 ;
    END
  END tl_u_ram_o[57]
  PIN tl_u_ram_o[58]
    DIRECTION OUTPUT ;
    USE SIGNAL ;
    ANTENNADIFFAREA 0.445500 ;
    PORT
      LAYER met2 ;
        RECT 1107.770 1296.000 1108.050 1300.000 ;
    END
  END tl_u_ram_o[58]
  PIN tl_u_ram_o[59]
    DIRECTION OUTPUT ;
    USE SIGNAL ;
    ANTENNADIFFAREA 0.445500 ;
    PORT
      LAYER met2 ;
        RECT 753.570 0.000 753.850 4.000 ;
    END
  END tl_u_ram_o[59]
  PIN tl_u_ram_o[5]
    DIRECTION OUTPUT ;
    USE SIGNAL ;
    ANTENNADIFFAREA 0.445500 ;
    PORT
      LAYER met2 ;
        RECT 1165.730 1296.000 1166.010 1300.000 ;
    END
  END tl_u_ram_o[5]
  PIN tl_u_ram_o[60]
    DIRECTION OUTPUT ;
    USE SIGNAL ;
    ANTENNADIFFAREA 0.445500 ;
    PORT
      LAYER met2 ;
        RECT 676.290 1296.000 676.570 1300.000 ;
    END
  END tl_u_ram_o[60]
  PIN tl_u_ram_o[61]
    DIRECTION OUTPUT ;
    USE SIGNAL ;
    ANTENNADIFFAREA 0.445500 ;
    PORT
      LAYER met2 ;
        RECT 270.570 0.000 270.850 4.000 ;
    END
  END tl_u_ram_o[61]
  PIN tl_u_ram_o[62]
    DIRECTION OUTPUT ;
    USE SIGNAL ;
    ANTENNADIFFAREA 0.445500 ;
    PORT
      LAYER met2 ;
        RECT 576.470 0.000 576.750 4.000 ;
    END
  END tl_u_ram_o[62]
  PIN tl_u_ram_o[63]
    DIRECTION OUTPUT ;
    USE SIGNAL ;
    ANTENNADIFFAREA 0.445500 ;
    PORT
      LAYER met2 ;
        RECT 582.910 0.000 583.190 4.000 ;
    END
  END tl_u_ram_o[63]
  PIN tl_u_ram_o[64]
    DIRECTION OUTPUT ;
    USE SIGNAL ;
    ANTENNADIFFAREA 0.445500 ;
    PORT
      LAYER met2 ;
        RECT 447.670 0.000 447.950 4.000 ;
    END
  END tl_u_ram_o[64]
  PIN tl_u_ram_o[65]
    DIRECTION OUTPUT ;
    USE SIGNAL ;
    ANTENNADIFFAREA 0.445500 ;
    PORT
      LAYER met2 ;
        RECT 570.030 0.000 570.310 4.000 ;
    END
  END tl_u_ram_o[65]
  PIN tl_u_ram_o[66]
    DIRECTION OUTPUT ;
    USE SIGNAL ;
    ANTENNADIFFAREA 0.445500 ;
    PORT
      LAYER met2 ;
        RECT 557.150 0.000 557.430 4.000 ;
    END
  END tl_u_ram_o[66]
  PIN tl_u_ram_o[67]
    DIRECTION OUTPUT ;
    USE SIGNAL ;
    ANTENNADIFFAREA 0.445500 ;
    PORT
      LAYER met2 ;
        RECT 544.270 0.000 544.550 4.000 ;
    END
  END tl_u_ram_o[67]
  PIN tl_u_ram_o[68]
    DIRECTION OUTPUT ;
    USE SIGNAL ;
    ANTENNADIFFAREA 0.445500 ;
    PORT
      LAYER met2 ;
        RECT 434.790 0.000 435.070 4.000 ;
    END
  END tl_u_ram_o[68]
  PIN tl_u_ram_o[69]
    DIRECTION OUTPUT ;
    USE SIGNAL ;
    ANTENNADIFFAREA 0.445500 ;
    PORT
      LAYER met2 ;
        RECT 595.790 0.000 596.070 4.000 ;
    END
  END tl_u_ram_o[69]
  PIN tl_u_ram_o[6]
    DIRECTION OUTPUT ;
    USE SIGNAL ;
    ANTENNADIFFAREA 0.445500 ;
    PORT
      LAYER met3 ;
        RECT 0.000 734.440 4.000 735.040 ;
    END
  END tl_u_ram_o[6]
  PIN tl_u_ram_o[70]
    DIRECTION OUTPUT ;
    USE SIGNAL ;
    ANTENNADIFFAREA 0.445500 ;
    PORT
      LAYER met2 ;
        RECT 206.170 0.000 206.450 4.000 ;
    END
  END tl_u_ram_o[70]
  PIN tl_u_ram_o[71]
    DIRECTION OUTPUT ;
    USE SIGNAL ;
    ANTENNADIFFAREA 0.445500 ;
    PORT
      LAYER met2 ;
        RECT 579.690 0.000 579.970 4.000 ;
    END
  END tl_u_ram_o[71]
  PIN tl_u_ram_o[72]
    DIRECTION OUTPUT ;
    USE SIGNAL ;
    ANTENNADIFFAREA 0.445500 ;
    PORT
      LAYER met2 ;
        RECT 283.450 0.000 283.730 4.000 ;
    END
  END tl_u_ram_o[72]
  PIN tl_u_ram_o[73]
    DIRECTION OUTPUT ;
    USE SIGNAL ;
    ANTENNADIFFAREA 0.445500 ;
    PORT
      LAYER met2 ;
        RECT 415.470 0.000 415.750 4.000 ;
    END
  END tl_u_ram_o[73]
  PIN tl_u_ram_o[74]
    DIRECTION OUTPUT ;
    USE SIGNAL ;
    ANTENNADIFFAREA 0.445500 ;
    PORT
      LAYER met2 ;
        RECT 238.370 0.000 238.650 4.000 ;
    END
  END tl_u_ram_o[74]
  PIN tl_u_ram_o[75]
    DIRECTION OUTPUT ;
    USE SIGNAL ;
    ANTENNADIFFAREA 0.445500 ;
    PORT
      LAYER met2 ;
        RECT 383.270 0.000 383.550 4.000 ;
    END
  END tl_u_ram_o[75]
  PIN tl_u_ram_o[76]
    DIRECTION OUTPUT ;
    USE SIGNAL ;
    ANTENNADIFFAREA 0.445500 ;
    PORT
      LAYER met2 ;
        RECT 144.990 0.000 145.270 4.000 ;
    END
  END tl_u_ram_o[76]
  PIN tl_u_ram_o[77]
    DIRECTION OUTPUT ;
    USE SIGNAL ;
    ANTENNADIFFAREA 0.445500 ;
    PORT
      LAYER met2 ;
        RECT 196.510 0.000 196.790 4.000 ;
    END
  END tl_u_ram_o[77]
  PIN tl_u_ram_o[78]
    DIRECTION OUTPUT ;
    USE SIGNAL ;
    ANTENNADIFFAREA 0.445500 ;
    PORT
      LAYER met2 ;
        RECT 161.090 0.000 161.370 4.000 ;
    END
  END tl_u_ram_o[78]
  PIN tl_u_ram_o[79]
    DIRECTION OUTPUT ;
    USE SIGNAL ;
    ANTENNADIFFAREA 0.445500 ;
    PORT
      LAYER met2 ;
        RECT 260.910 0.000 261.190 4.000 ;
    END
  END tl_u_ram_o[79]
  PIN tl_u_ram_o[7]
    DIRECTION OUTPUT ;
    USE SIGNAL ;
    ANTENNADIFFAREA 0.445500 ;
    PORT
      LAYER met2 ;
        RECT 843.730 0.000 844.010 4.000 ;
    END
  END tl_u_ram_o[7]
  PIN tl_u_ram_o[80]
    DIRECTION OUTPUT ;
    USE SIGNAL ;
    ANTENNADIFFAREA 0.445500 ;
    PORT
      LAYER met2 ;
        RECT 193.290 0.000 193.570 4.000 ;
    END
  END tl_u_ram_o[80]
  PIN tl_u_ram_o[81]
    DIRECTION OUTPUT ;
    USE SIGNAL ;
    ANTENNADIFFAREA 0.445500 ;
    PORT
      LAYER met2 ;
        RECT 286.670 0.000 286.950 4.000 ;
    END
  END tl_u_ram_o[81]
  PIN tl_u_ram_o[82]
    DIRECTION OUTPUT ;
    USE SIGNAL ;
    ANTENNADIFFAREA 0.445500 ;
    PORT
      LAYER met2 ;
        RECT 138.550 0.000 138.830 4.000 ;
    END
  END tl_u_ram_o[82]
  PIN tl_u_ram_o[83]
    DIRECTION OUTPUT ;
    USE SIGNAL ;
    ANTENNADIFFAREA 0.445500 ;
    PORT
      LAYER met2 ;
        RECT 112.790 0.000 113.070 4.000 ;
    END
  END tl_u_ram_o[83]
  PIN tl_u_ram_o[84]
    DIRECTION OUTPUT ;
    USE SIGNAL ;
    ANTENNADIFFAREA 0.445500 ;
    PORT
      LAYER met2 ;
        RECT 87.030 0.000 87.310 4.000 ;
    END
  END tl_u_ram_o[84]
  PIN tl_u_ram_o[85]
    DIRECTION OUTPUT ;
    USE SIGNAL ;
    ANTENNADIFFAREA 0.445500 ;
    PORT
      LAYER met2 ;
        RECT 367.170 0.000 367.450 4.000 ;
    END
  END tl_u_ram_o[85]
  PIN tl_u_ram_o[86]
    DIRECTION OUTPUT ;
    USE SIGNAL ;
    ANTENNADIFFAREA 0.445500 ;
    PORT
      LAYER met2 ;
        RECT 325.310 0.000 325.590 4.000 ;
    END
  END tl_u_ram_o[86]
  PIN tl_u_ram_o[87]
    DIRECTION OUTPUT ;
    USE SIGNAL ;
    ANTENNADIFFAREA 0.445500 ;
    PORT
      LAYER met2 ;
        RECT 508.850 0.000 509.130 4.000 ;
    END
  END tl_u_ram_o[87]
  PIN tl_u_ram_o[88]
    DIRECTION OUTPUT ;
    USE SIGNAL ;
    ANTENNADIFFAREA 0.445500 ;
    PORT
      LAYER met2 ;
        RECT 441.230 0.000 441.510 4.000 ;
    END
  END tl_u_ram_o[88]
  PIN tl_u_ram_o[89]
    DIRECTION OUTPUT ;
    USE SIGNAL ;
    ANTENNADIFFAREA 0.445500 ;
    PORT
      LAYER met2 ;
        RECT 483.090 0.000 483.370 4.000 ;
    END
  END tl_u_ram_o[89]
  PIN tl_u_ram_o[8]
    DIRECTION OUTPUT ;
    USE SIGNAL ;
    ANTENNADIFFAREA 0.445500 ;
    PORT
      LAYER met2 ;
        RECT 743.910 1296.000 744.190 1300.000 ;
    END
  END tl_u_ram_o[8]
  PIN tl_u_ram_o[90]
    DIRECTION OUTPUT ;
    USE SIGNAL ;
    ANTENNADIFFAREA 0.445500 ;
    PORT
      LAYER met2 ;
        RECT 502.410 0.000 502.690 4.000 ;
    END
  END tl_u_ram_o[90]
  PIN tl_u_ram_o[91]
    DIRECTION OUTPUT ;
    USE SIGNAL ;
    ANTENNADIFFAREA 0.445500 ;
    PORT
      LAYER met3 ;
        RECT 0.000 197.240 4.000 197.840 ;
    END
  END tl_u_ram_o[91]
  PIN tl_u_ram_o[92]
    DIRECTION OUTPUT ;
    USE SIGNAL ;
    ANTENNADIFFAREA 0.445500 ;
    PORT
      LAYER met3 ;
        RECT 0.000 119.040 4.000 119.640 ;
    END
  END tl_u_ram_o[92]
  PIN tl_u_ram_o[93]
    DIRECTION OUTPUT ;
    USE SIGNAL ;
    ANTENNADIFFAREA 0.445500 ;
    PORT
      LAYER met2 ;
        RECT 1088.450 1296.000 1088.730 1300.000 ;
    END
  END tl_u_ram_o[93]
  PIN tl_u_ram_o[94]
    DIRECTION OUTPUT ;
    USE SIGNAL ;
    ANTENNADIFFAREA 0.445500 ;
    PORT
      LAYER met2 ;
        RECT 959.650 0.000 959.930 4.000 ;
    END
  END tl_u_ram_o[94]
  PIN tl_u_ram_o[95]
    DIRECTION OUTPUT ;
    USE SIGNAL ;
    ANTENNADIFFAREA 0.445500 ;
    PORT
      LAYER met2 ;
        RECT 714.930 1296.000 715.210 1300.000 ;
    END
  END tl_u_ram_o[95]
  PIN tl_u_ram_o[96]
    DIRECTION OUTPUT ;
    USE SIGNAL ;
    ANTENNADIFFAREA 0.445500 ;
    PORT
      LAYER met3 ;
        RECT 0.000 700.440 4.000 701.040 ;
    END
  END tl_u_ram_o[96]
  PIN tl_u_ram_o[97]
    DIRECTION OUTPUT ;
    USE SIGNAL ;
    ANTENNADIFFAREA 0.445500 ;
    PORT
      LAYER met2 ;
        RECT 721.370 1296.000 721.650 1300.000 ;
    END
  END tl_u_ram_o[97]
  PIN tl_u_ram_o[98]
    DIRECTION OUTPUT ;
    USE SIGNAL ;
    ANTENNADIFFAREA 0.445500 ;
    PORT
      LAYER met3 ;
        RECT 0.000 591.640 4.000 592.240 ;
    END
  END tl_u_ram_o[98]
  PIN tl_u_ram_o[99]
    DIRECTION OUTPUT ;
    USE SIGNAL ;
    ANTENNADIFFAREA 0.445500 ;
    PORT
      LAYER met3 ;
        RECT 0.000 710.640 4.000 711.240 ;
    END
  END tl_u_ram_o[99]
  PIN tl_u_ram_o[9]
    DIRECTION OUTPUT ;
    USE SIGNAL ;
    ANTENNADIFFAREA 0.445500 ;
    PORT
      LAYER met3 ;
        RECT 1296.000 1285.240 1300.000 1285.840 ;
    END
  END tl_u_ram_o[9]
  PIN tl_u_rom_i[0]
    DIRECTION INPUT ;
    USE SIGNAL ;
    ANTENNAGATEAREA 0.647700 ;
    ANTENNADIFFAREA 0.434700 ;
    PORT
      LAYER met3 ;
        RECT 0.000 452.240 4.000 452.840 ;
    END
  END tl_u_rom_i[0]
  PIN tl_u_rom_i[10]
    DIRECTION INPUT ;
    USE SIGNAL ;
    ANTENNAGATEAREA 0.593700 ;
    ANTENNADIFFAREA 0.434700 ;
    PORT
      LAYER met3 ;
        RECT 0.000 1145.840 4.000 1146.440 ;
    END
  END tl_u_rom_i[10]
  PIN tl_u_rom_i[11]
    DIRECTION INPUT ;
    USE SIGNAL ;
    ANTENNAGATEAREA 0.647700 ;
    ANTENNADIFFAREA 0.434700 ;
    PORT
      LAYER met2 ;
        RECT 644.090 0.000 644.370 4.000 ;
    END
  END tl_u_rom_i[11]
  PIN tl_u_rom_i[12]
    DIRECTION INPUT ;
    USE SIGNAL ;
    ANTENNAGATEAREA 0.593700 ;
    ANTENNADIFFAREA 0.434700 ;
    PORT
      LAYER met3 ;
        RECT 1296.000 1030.240 1300.000 1030.840 ;
    END
  END tl_u_rom_i[12]
  PIN tl_u_rom_i[13]
    DIRECTION INPUT ;
    USE SIGNAL ;
    ANTENNAGATEAREA 0.682200 ;
    ANTENNADIFFAREA 0.434700 ;
    PORT
      LAYER met2 ;
        RECT 698.830 0.000 699.110 4.000 ;
    END
  END tl_u_rom_i[13]
  PIN tl_u_rom_i[14]
    DIRECTION INPUT ;
    USE SIGNAL ;
    ANTENNAGATEAREA 0.647700 ;
    ANTENNADIFFAREA 0.434700 ;
    PORT
      LAYER met3 ;
        RECT 0.000 1026.840 4.000 1027.440 ;
    END
  END tl_u_rom_i[14]
  PIN tl_u_rom_i[15]
    DIRECTION INPUT ;
    USE SIGNAL ;
    ANTENNAGATEAREA 0.647700 ;
    ANTENNADIFFAREA 0.434700 ;
    PORT
      LAYER met2 ;
        RECT 1107.770 0.000 1108.050 4.000 ;
    END
  END tl_u_rom_i[15]
  PIN tl_u_rom_i[16]
    DIRECTION INPUT ;
    USE SIGNAL ;
    ANTENNAGATEAREA 0.631200 ;
    ANTENNADIFFAREA 0.434700 ;
    PORT
      LAYER met3 ;
        RECT 1296.000 1278.440 1300.000 1279.040 ;
    END
  END tl_u_rom_i[16]
  PIN tl_u_rom_i[17]
    DIRECTION INPUT ;
    USE SIGNAL ;
    ANTENNAGATEAREA 0.647700 ;
    ANTENNADIFFAREA 0.434700 ;
    PORT
      LAYER met3 ;
        RECT 1296.000 1054.040 1300.000 1054.640 ;
    END
  END tl_u_rom_i[17]
  PIN tl_u_rom_i[18]
    DIRECTION INPUT ;
    USE SIGNAL ;
    ANTENNAGATEAREA 0.647700 ;
    ANTENNADIFFAREA 0.434700 ;
    PORT
      LAYER met2 ;
        RECT 872.710 0.000 872.990 4.000 ;
    END
  END tl_u_rom_i[18]
  PIN tl_u_rom_i[19]
    DIRECTION INPUT ;
    USE SIGNAL ;
    ANTENNAGATEAREA 0.647700 ;
    ANTENNADIFFAREA 0.434700 ;
    PORT
      LAYER met3 ;
        RECT 1296.000 731.040 1300.000 731.640 ;
    END
  END tl_u_rom_i[19]
  PIN tl_u_rom_i[1]
    DIRECTION INPUT ;
    USE SIGNAL ;
    ANTENNAGATEAREA 0.647700 ;
    ANTENNADIFFAREA 0.434700 ;
    PORT
      LAYER met3 ;
        RECT 1296.000 1190.040 1300.000 1190.640 ;
    END
  END tl_u_rom_i[1]
  PIN tl_u_rom_i[20]
    DIRECTION INPUT ;
    USE SIGNAL ;
    ANTENNAGATEAREA 0.593700 ;
    ANTENNADIFFAREA 0.434700 ;
    PORT
      LAYER met2 ;
        RECT 811.530 0.000 811.810 4.000 ;
    END
  END tl_u_rom_i[20]
  PIN tl_u_rom_i[21]
    DIRECTION INPUT ;
    USE SIGNAL ;
    ANTENNAGATEAREA 0.647700 ;
    ANTENNADIFFAREA 0.434700 ;
    PORT
      LAYER met2 ;
        RECT 653.750 0.000 654.030 4.000 ;
    END
  END tl_u_rom_i[21]
  PIN tl_u_rom_i[22]
    DIRECTION INPUT ;
    USE SIGNAL ;
    ANTENNAGATEAREA 0.631200 ;
    ANTENNADIFFAREA 0.434700 ;
    PORT
      LAYER met3 ;
        RECT 0.000 1258.040 4.000 1258.640 ;
    END
  END tl_u_rom_i[22]
  PIN tl_u_rom_i[23]
    DIRECTION INPUT ;
    USE SIGNAL ;
    ANTENNAGATEAREA 0.682200 ;
    ANTENNADIFFAREA 0.434700 ;
    PORT
      LAYER met3 ;
        RECT 1296.000 884.040 1300.000 884.640 ;
    END
  END tl_u_rom_i[23]
  PIN tl_u_rom_i[24]
    DIRECTION INPUT ;
    USE SIGNAL ;
    ANTENNAGATEAREA 0.560700 ;
    ANTENNADIFFAREA 0.434700 ;
    PORT
      LAYER met3 ;
        RECT 1296.000 1145.840 1300.000 1146.440 ;
    END
  END tl_u_rom_i[24]
  PIN tl_u_rom_i[25]
    DIRECTION INPUT ;
    USE SIGNAL ;
    ANTENNAGATEAREA 0.682200 ;
    ANTENNADIFFAREA 0.434700 ;
    PORT
      LAYER met3 ;
        RECT 1296.000 693.640 1300.000 694.240 ;
    END
  END tl_u_rom_i[25]
  PIN tl_u_rom_i[26]
    DIRECTION INPUT ;
    USE SIGNAL ;
    ANTENNAGATEAREA 0.593700 ;
    ANTENNADIFFAREA 0.434700 ;
    PORT
      LAYER met3 ;
        RECT 1296.000 941.840 1300.000 942.440 ;
    END
  END tl_u_rom_i[26]
  PIN tl_u_rom_i[27]
    DIRECTION INPUT ;
    USE SIGNAL ;
    ANTENNAGATEAREA 0.647700 ;
    ANTENNADIFFAREA 0.434700 ;
    PORT
      LAYER met2 ;
        RECT 1043.370 0.000 1043.650 4.000 ;
    END
  END tl_u_rom_i[27]
  PIN tl_u_rom_i[28]
    DIRECTION INPUT ;
    USE SIGNAL ;
    ANTENNAGATEAREA 0.560700 ;
    ANTENNADIFFAREA 0.434700 ;
    PORT
      LAYER met2 ;
        RECT 801.870 0.000 802.150 4.000 ;
    END
  END tl_u_rom_i[28]
  PIN tl_u_rom_i[29]
    DIRECTION INPUT ;
    USE SIGNAL ;
    ANTENNAGATEAREA 0.647700 ;
    ANTENNADIFFAREA 0.434700 ;
    PORT
      LAYER met3 ;
        RECT 1296.000 873.840 1300.000 874.440 ;
    END
  END tl_u_rom_i[29]
  PIN tl_u_rom_i[2]
    DIRECTION INPUT ;
    USE SIGNAL ;
    ANTENNAGATEAREA 0.593700 ;
    ANTENNADIFFAREA 0.434700 ;
    PORT
      LAYER met3 ;
        RECT 1296.000 1251.240 1300.000 1251.840 ;
    END
  END tl_u_rom_i[2]
  PIN tl_u_rom_i[30]
    DIRECTION INPUT ;
    USE SIGNAL ;
    ANTENNAGATEAREA 0.560700 ;
    ANTENNADIFFAREA 0.434700 ;
    PORT
      LAYER met2 ;
        RECT 924.230 0.000 924.510 4.000 ;
    END
  END tl_u_rom_i[30]
  PIN tl_u_rom_i[31]
    DIRECTION INPUT ;
    USE SIGNAL ;
    ANTENNAGATEAREA 0.682200 ;
    ANTENNADIFFAREA 0.434700 ;
    PORT
      LAYER met3 ;
        RECT 0.000 1169.640 4.000 1170.240 ;
    END
  END tl_u_rom_i[31]
  PIN tl_u_rom_i[32]
    DIRECTION INPUT ;
    USE SIGNAL ;
    ANTENNAGATEAREA 0.647700 ;
    ANTENNADIFFAREA 0.434700 ;
    PORT
      LAYER met2 ;
        RECT 856.610 0.000 856.890 4.000 ;
    END
  END tl_u_rom_i[32]
  PIN tl_u_rom_i[33]
    DIRECTION INPUT ;
    USE SIGNAL ;
    ANTENNAGATEAREA 1.177200 ;
    ANTENNADIFFAREA 0.434700 ;
    PORT
      LAYER met2 ;
        RECT 879.150 0.000 879.430 4.000 ;
    END
  END tl_u_rom_i[33]
  PIN tl_u_rom_i[34]
    DIRECTION INPUT ;
    USE SIGNAL ;
    ANTENNAGATEAREA 0.860700 ;
    ANTENNADIFFAREA 0.434700 ;
    PORT
      LAYER met2 ;
        RECT 982.190 0.000 982.470 4.000 ;
    END
  END tl_u_rom_i[34]
  PIN tl_u_rom_i[35]
    DIRECTION INPUT ;
    USE SIGNAL ;
    ANTENNAGATEAREA 0.593700 ;
    ANTENNADIFFAREA 0.434700 ;
    PORT
      LAYER met3 ;
        RECT 1296.000 996.240 1300.000 996.840 ;
    END
  END tl_u_rom_i[35]
  PIN tl_u_rom_i[36]
    DIRECTION INPUT ;
    USE SIGNAL ;
    ANTENNAGATEAREA 0.560700 ;
    ANTENNADIFFAREA 0.434700 ;
    PORT
      LAYER met3 ;
        RECT 1296.000 782.040 1300.000 782.640 ;
    END
  END tl_u_rom_i[36]
  PIN tl_u_rom_i[37]
    DIRECTION INPUT ;
    USE SIGNAL ;
    ANTENNAGATEAREA 0.593700 ;
    ANTENNADIFFAREA 0.434700 ;
    PORT
      LAYER met2 ;
        RECT 676.290 0.000 676.570 4.000 ;
    END
  END tl_u_rom_i[37]
  PIN tl_u_rom_i[38]
    DIRECTION INPUT ;
    USE SIGNAL ;
    ANTENNAGATEAREA 0.647700 ;
    ANTENNADIFFAREA 0.434700 ;
    PORT
      LAYER met3 ;
        RECT 0.000 1009.840 4.000 1010.440 ;
    END
  END tl_u_rom_i[38]
  PIN tl_u_rom_i[39]
    DIRECTION INPUT ;
    USE SIGNAL ;
    ANTENNAGATEAREA 0.647700 ;
    ANTENNADIFFAREA 0.434700 ;
    PORT
      LAYER met2 ;
        RECT 1223.690 0.000 1223.970 4.000 ;
    END
  END tl_u_rom_i[39]
  PIN tl_u_rom_i[3]
    DIRECTION INPUT ;
    USE SIGNAL ;
    ANTENNAGATEAREA 0.647700 ;
    ANTENNADIFFAREA 0.434700 ;
    PORT
      LAYER met3 ;
        RECT 1296.000 1193.440 1300.000 1194.040 ;
    END
  END tl_u_rom_i[3]
  PIN tl_u_rom_i[40]
    DIRECTION INPUT ;
    USE SIGNAL ;
    ANTENNAGATEAREA 0.593700 ;
    ANTENNADIFFAREA 0.434700 ;
    PORT
      LAYER met3 ;
        RECT 1296.000 921.440 1300.000 922.040 ;
    END
  END tl_u_rom_i[40]
  PIN tl_u_rom_i[41]
    DIRECTION INPUT ;
    USE SIGNAL ;
    ANTENNAGATEAREA 0.560700 ;
    ANTENNADIFFAREA 0.434700 ;
    PORT
      LAYER met3 ;
        RECT 1296.000 958.840 1300.000 959.440 ;
    END
  END tl_u_rom_i[41]
  PIN tl_u_rom_i[42]
    DIRECTION INPUT ;
    USE SIGNAL ;
    ANTENNAGATEAREA 0.560700 ;
    ANTENNADIFFAREA 0.434700 ;
    PORT
      LAYER met3 ;
        RECT 1296.000 727.640 1300.000 728.240 ;
    END
  END tl_u_rom_i[42]
  PIN tl_u_rom_i[43]
    DIRECTION INPUT ;
    USE SIGNAL ;
    ANTENNAGATEAREA 0.560700 ;
    ANTENNADIFFAREA 0.434700 ;
    PORT
      LAYER met2 ;
        RECT 1152.850 0.000 1153.130 4.000 ;
    END
  END tl_u_rom_i[43]
  PIN tl_u_rom_i[44]
    DIRECTION INPUT ;
    USE SIGNAL ;
    ANTENNAGATEAREA 0.682200 ;
    ANTENNADIFFAREA 0.434700 ;
    PORT
      LAYER met3 ;
        RECT 1296.000 741.240 1300.000 741.840 ;
    END
  END tl_u_rom_i[44]
  PIN tl_u_rom_i[45]
    DIRECTION INPUT ;
    USE SIGNAL ;
    ANTENNAGATEAREA 0.647700 ;
    ANTENNADIFFAREA 0.434700 ;
    PORT
      LAYER met3 ;
        RECT 1296.000 809.240 1300.000 809.840 ;
    END
  END tl_u_rom_i[45]
  PIN tl_u_rom_i[46]
    DIRECTION INPUT ;
    USE SIGNAL ;
    ANTENNAGATEAREA 0.647700 ;
    ANTENNADIFFAREA 0.434700 ;
    PORT
      LAYER met3 ;
        RECT 1296.000 904.440 1300.000 905.040 ;
    END
  END tl_u_rom_i[46]
  PIN tl_u_rom_i[47]
    DIRECTION INPUT ;
    USE SIGNAL ;
    ANTENNAGATEAREA 0.682200 ;
    ANTENNADIFFAREA 0.434700 ;
    PORT
      LAYER met3 ;
        RECT 1296.000 931.640 1300.000 932.240 ;
    END
  END tl_u_rom_i[47]
  PIN tl_u_rom_i[48]
    DIRECTION INPUT ;
    USE SIGNAL ;
    ANTENNAGATEAREA 0.631200 ;
    ANTENNADIFFAREA 0.434700 ;
    PORT
      LAYER met3 ;
        RECT 0.000 1074.440 4.000 1075.040 ;
    END
  END tl_u_rom_i[48]
  PIN tl_u_rom_i[49]
    DIRECTION INPUT ;
    USE SIGNAL ;
    ANTENNAGATEAREA 0.631200 ;
    ANTENNADIFFAREA 0.434700 ;
    PORT
      LAYER met3 ;
        RECT 1296.000 1196.840 1300.000 1197.440 ;
    END
  END tl_u_rom_i[49]
  PIN tl_u_rom_i[4]
    DIRECTION INPUT ;
    USE SIGNAL ;
    ANTENNAGATEAREA 0.593700 ;
    ANTENNADIFFAREA 0.434700 ;
    PORT
      LAYER met2 ;
        RECT 737.470 0.000 737.750 4.000 ;
    END
  END tl_u_rom_i[4]
  PIN tl_u_rom_i[50]
    DIRECTION INPUT ;
    USE SIGNAL ;
    ANTENNAGATEAREA 0.682200 ;
    ANTENNADIFFAREA 0.434700 ;
    PORT
      LAYER met3 ;
        RECT 0.000 1241.040 4.000 1241.640 ;
    END
  END tl_u_rom_i[50]
  PIN tl_u_rom_i[51]
    DIRECTION INPUT ;
    USE SIGNAL ;
    ANTENNAGATEAREA 0.593700 ;
    ANTENNADIFFAREA 0.434700 ;
    PORT
      LAYER met3 ;
        RECT 1296.000 972.440 1300.000 973.040 ;
    END
  END tl_u_rom_i[51]
  PIN tl_u_rom_i[52]
    DIRECTION INPUT ;
    USE SIGNAL ;
    ANTENNAGATEAREA 0.647700 ;
    ANTENNADIFFAREA 0.434700 ;
    PORT
      LAYER met3 ;
        RECT 1296.000 901.040 1300.000 901.640 ;
    END
  END tl_u_rom_i[52]
  PIN tl_u_rom_i[53]
    DIRECTION INPUT ;
    USE SIGNAL ;
    ANTENNAGATEAREA 0.647700 ;
    ANTENNADIFFAREA 0.434700 ;
    PORT
      LAYER met3 ;
        RECT 0.000 1237.640 4.000 1238.240 ;
    END
  END tl_u_rom_i[53]
  PIN tl_u_rom_i[54]
    DIRECTION INPUT ;
    USE SIGNAL ;
    ANTENNAGATEAREA 0.593700 ;
    ANTENNADIFFAREA 0.434700 ;
    PORT
      LAYER met2 ;
        RECT 682.730 0.000 683.010 4.000 ;
    END
  END tl_u_rom_i[54]
  PIN tl_u_rom_i[55]
    DIRECTION INPUT ;
    USE SIGNAL ;
    ANTENNAGATEAREA 0.560700 ;
    ANTENNADIFFAREA 0.434700 ;
    PORT
      LAYER met2 ;
        RECT 1278.430 0.000 1278.710 4.000 ;
    END
  END tl_u_rom_i[55]
  PIN tl_u_rom_i[56]
    DIRECTION INPUT ;
    USE SIGNAL ;
    ANTENNAGATEAREA 0.631200 ;
    ANTENNADIFFAREA 0.434700 ;
    PORT
      LAYER met3 ;
        RECT 0.000 952.040 4.000 952.640 ;
    END
  END tl_u_rom_i[56]
  PIN tl_u_rom_i[57]
    DIRECTION INPUT ;
    USE SIGNAL ;
    ANTENNAGATEAREA 0.647700 ;
    ANTENNADIFFAREA 0.434700 ;
    PORT
      LAYER met2 ;
        RECT 1226.910 0.000 1227.190 4.000 ;
    END
  END tl_u_rom_i[57]
  PIN tl_u_rom_i[58]
    DIRECTION INPUT ;
    USE SIGNAL ;
    ANTENNAGATEAREA 0.647700 ;
    ANTENNADIFFAREA 0.434700 ;
    PORT
      LAYER met3 ;
        RECT 1296.000 799.040 1300.000 799.640 ;
    END
  END tl_u_rom_i[58]
  PIN tl_u_rom_i[59]
    DIRECTION INPUT ;
    USE SIGNAL ;
    ANTENNAGATEAREA 0.647700 ;
    ANTENNADIFFAREA 0.434700 ;
    PORT
      LAYER met3 ;
        RECT 1296.000 690.240 1300.000 690.840 ;
    END
  END tl_u_rom_i[59]
  PIN tl_u_rom_i[5]
    DIRECTION INPUT ;
    USE SIGNAL ;
    ANTENNAGATEAREA 0.631200 ;
    ANTENNADIFFAREA 0.434700 ;
    PORT
      LAYER met3 ;
        RECT 1296.000 894.240 1300.000 894.840 ;
    END
  END tl_u_rom_i[5]
  PIN tl_u_rom_i[60]
    DIRECTION INPUT ;
    USE SIGNAL ;
    ANTENNAGATEAREA 0.593700 ;
    ANTENNADIFFAREA 0.434700 ;
    PORT
      LAYER met3 ;
        RECT 0.000 1135.640 4.000 1136.240 ;
    END
  END tl_u_rom_i[60]
  PIN tl_u_rom_i[61]
    DIRECTION INPUT ;
    USE SIGNAL ;
    ANTENNAGATEAREA 0.560700 ;
    ANTENNADIFFAREA 0.434700 ;
    PORT
      LAYER met3 ;
        RECT 1296.000 1200.240 1300.000 1200.840 ;
    END
  END tl_u_rom_i[61]
  PIN tl_u_rom_i[62]
    DIRECTION INPUT ;
    USE SIGNAL ;
    ANTENNAGATEAREA 0.647700 ;
    ANTENNADIFFAREA 0.434700 ;
    PORT
      LAYER met3 ;
        RECT 1296.000 1040.440 1300.000 1041.040 ;
    END
  END tl_u_rom_i[62]
  PIN tl_u_rom_i[63]
    DIRECTION INPUT ;
    USE SIGNAL ;
    ANTENNAGATEAREA 0.682200 ;
    ANTENNADIFFAREA 0.434700 ;
    PORT
      LAYER met3 ;
        RECT 0.000 1261.440 4.000 1262.040 ;
    END
  END tl_u_rom_i[63]
  PIN tl_u_rom_i[64]
    DIRECTION INPUT ;
    USE SIGNAL ;
    ANTENNAGATEAREA 0.647700 ;
    ANTENNADIFFAREA 0.434700 ;
    PORT
      LAYER met3 ;
        RECT 1296.000 686.840 1300.000 687.440 ;
    END
  END tl_u_rom_i[64]
  PIN tl_u_rom_i[65]
    DIRECTION INPUT ;
    USE SIGNAL ;
    ANTENNAGATEAREA 0.929700 ;
    ANTENNADIFFAREA 0.434700 ;
    PORT
      LAYER met3 ;
        RECT 1296.000 907.840 1300.000 908.440 ;
    END
  END tl_u_rom_i[65]
  PIN tl_u_rom_i[6]
    DIRECTION INPUT ;
    USE SIGNAL ;
    ANTENNAGATEAREA 0.647700 ;
    ANTENNADIFFAREA 0.434700 ;
    PORT
      LAYER met3 ;
        RECT 1296.000 1115.240 1300.000 1115.840 ;
    END
  END tl_u_rom_i[6]
  PIN tl_u_rom_i[7]
    DIRECTION INPUT ;
    USE SIGNAL ;
    ANTENNAGATEAREA 0.631200 ;
    ANTENNADIFFAREA 0.434700 ;
    PORT
      LAYER met3 ;
        RECT 1296.000 1203.640 1300.000 1204.240 ;
    END
  END tl_u_rom_i[7]
  PIN tl_u_rom_i[8]
    DIRECTION INPUT ;
    USE SIGNAL ;
    ANTENNAGATEAREA 0.647700 ;
    ANTENNADIFFAREA 0.434700 ;
    PORT
      LAYER met2 ;
        RECT 714.930 0.000 715.210 4.000 ;
    END
  END tl_u_rom_i[8]
  PIN tl_u_rom_i[9]
    DIRECTION INPUT ;
    USE SIGNAL ;
    ANTENNAGATEAREA 0.593700 ;
    ANTENNADIFFAREA 0.434700 ;
    PORT
      LAYER met3 ;
        RECT 1296.000 717.440 1300.000 718.040 ;
    END
  END tl_u_rom_i[9]
  PIN tl_u_rom_o[0]
    DIRECTION OUTPUT ;
    USE SIGNAL ;
    ANTENNADIFFAREA 0.445500 ;
    PORT
      LAYER met3 ;
        RECT 0.000 962.240 4.000 962.840 ;
    END
  END tl_u_rom_o[0]
  PIN tl_u_rom_o[100]
    DIRECTION OUTPUT ;
    USE SIGNAL ;
    ANTENNADIFFAREA 0.445500 ;
    PORT
      LAYER met3 ;
        RECT 0.000 1050.640 4.000 1051.240 ;
    END
  END tl_u_rom_o[100]
  PIN tl_u_rom_o[101]
    DIRECTION OUTPUT ;
    USE SIGNAL ;
    ANTENNADIFFAREA 0.445500 ;
    PORT
      LAYER met2 ;
        RECT 1030.490 0.000 1030.770 4.000 ;
    END
  END tl_u_rom_o[101]
  PIN tl_u_rom_o[102]
    DIRECTION OUTPUT ;
    USE SIGNAL ;
    ANTENNADIFFAREA 0.445500 ;
    PORT
      LAYER met3 ;
        RECT 0.000 714.040 4.000 714.640 ;
    END
  END tl_u_rom_o[102]
  PIN tl_u_rom_o[103]
    DIRECTION OUTPUT ;
    USE SIGNAL ;
    ANTENNADIFFAREA 0.445500 ;
    PORT
      LAYER met2 ;
        RECT 1056.250 0.000 1056.530 4.000 ;
    END
  END tl_u_rom_o[103]
  PIN tl_u_rom_o[104]
    DIRECTION OUTPUT ;
    USE SIGNAL ;
    ANTENNADIFFAREA 0.445500 ;
    PORT
      LAYER met2 ;
        RECT 1246.230 0.000 1246.510 4.000 ;
    END
  END tl_u_rom_o[104]
  PIN tl_u_rom_o[105]
    DIRECTION OUTPUT ;
    USE SIGNAL ;
    ANTENNADIFFAREA 0.445500 ;
    PORT
      LAYER met3 ;
        RECT 0.000 632.440 4.000 633.040 ;
    END
  END tl_u_rom_o[105]
  PIN tl_u_rom_o[106]
    DIRECTION OUTPUT ;
    USE SIGNAL ;
    ANTENNADIFFAREA 0.445500 ;
    PORT
      LAYER met3 ;
        RECT 0.000 612.040 4.000 612.640 ;
    END
  END tl_u_rom_o[106]
  PIN tl_u_rom_o[107]
    DIRECTION OUTPUT ;
    USE SIGNAL ;
    ANTENNADIFFAREA 0.445500 ;
    PORT
      LAYER met3 ;
        RECT 0.000 1033.640 4.000 1034.240 ;
    END
  END tl_u_rom_o[107]
  PIN tl_u_rom_o[108]
    DIRECTION OUTPUT ;
    USE SIGNAL ;
    ANTENNADIFFAREA 0.445500 ;
    PORT
      LAYER met3 ;
        RECT 0.000 51.040 4.000 51.640 ;
    END
  END tl_u_rom_o[108]
  PIN tl_u_rom_o[109]
    DIRECTION OUTPUT ;
    USE SIGNAL ;
    ANTENNADIFFAREA 0.445500 ;
    PORT
      LAYER met3 ;
        RECT 0.000 159.840 4.000 160.440 ;
    END
  END tl_u_rom_o[109]
  PIN tl_u_rom_o[10]
    DIRECTION OUTPUT ;
    USE SIGNAL ;
    ANTENNADIFFAREA 0.445500 ;
    PORT
      LAYER met3 ;
        RECT 0.000 550.840 4.000 551.440 ;
    END
  END tl_u_rom_o[10]
  PIN tl_u_rom_o[11]
    DIRECTION OUTPUT ;
    USE SIGNAL ;
    ANTENNADIFFAREA 0.445500 ;
    PORT
      LAYER met2 ;
        RECT 1130.310 0.000 1130.590 4.000 ;
    END
  END tl_u_rom_o[11]
  PIN tl_u_rom_o[12]
    DIRECTION OUTPUT ;
    USE SIGNAL ;
    ANTENNADIFFAREA 0.445500 ;
    PORT
      LAYER met3 ;
        RECT 0.000 945.240 4.000 945.840 ;
    END
  END tl_u_rom_o[12]
  PIN tl_u_rom_o[13]
    DIRECTION OUTPUT ;
    USE SIGNAL ;
    ANTENNADIFFAREA 0.445500 ;
    PORT
      LAYER met3 ;
        RECT 1296.000 965.640 1300.000 966.240 ;
    END
  END tl_u_rom_o[13]
  PIN tl_u_rom_o[14]
    DIRECTION OUTPUT ;
    USE SIGNAL ;
    ANTENNADIFFAREA 0.445500 ;
    PORT
      LAYER met3 ;
        RECT 0.000 333.240 4.000 333.840 ;
    END
  END tl_u_rom_o[14]
  PIN tl_u_rom_o[15]
    DIRECTION OUTPUT ;
    USE SIGNAL ;
    ANTENNADIFFAREA 0.445500 ;
    PORT
      LAYER met3 ;
        RECT 0.000 251.640 4.000 252.240 ;
    END
  END tl_u_rom_o[15]
  PIN tl_u_rom_o[16]
    DIRECTION OUTPUT ;
    USE SIGNAL ;
    ANTENNADIFFAREA 0.445500 ;
    PORT
      LAYER met2 ;
        RECT 1259.110 0.000 1259.390 4.000 ;
    END
  END tl_u_rom_o[16]
  PIN tl_u_rom_o[17]
    DIRECTION OUTPUT ;
    USE SIGNAL ;
    ANTENNADIFFAREA 0.445500 ;
    PORT
      LAYER met3 ;
        RECT 1296.000 870.440 1300.000 871.040 ;
    END
  END tl_u_rom_o[17]
  PIN tl_u_rom_o[18]
    DIRECTION OUTPUT ;
    USE SIGNAL ;
    ANTENNADIFFAREA 0.445500 ;
    PORT
      LAYER met3 ;
        RECT 0.000 1101.640 4.000 1102.240 ;
    END
  END tl_u_rom_o[18]
  PIN tl_u_rom_o[19]
    DIRECTION OUTPUT ;
    USE SIGNAL ;
    ANTENNADIFFAREA 0.445500 ;
    PORT
      LAYER met3 ;
        RECT 0.000 666.440 4.000 667.040 ;
    END
  END tl_u_rom_o[19]
  PIN tl_u_rom_o[1]
    DIRECTION OUTPUT ;
    USE SIGNAL ;
    ANTENNADIFFAREA 0.445500 ;
    PORT
      LAYER met3 ;
        RECT 0.000 1077.840 4.000 1078.440 ;
    END
  END tl_u_rom_o[1]
  PIN tl_u_rom_o[20]
    DIRECTION OUTPUT ;
    USE SIGNAL ;
    ANTENNADIFFAREA 0.445500 ;
    PORT
      LAYER met3 ;
        RECT 0.000 513.440 4.000 514.040 ;
    END
  END tl_u_rom_o[20]
  PIN tl_u_rom_o[21]
    DIRECTION OUTPUT ;
    USE SIGNAL ;
    ANTENNADIFFAREA 0.445500 ;
    PORT
      LAYER met2 ;
        RECT 914.570 0.000 914.850 4.000 ;
    END
  END tl_u_rom_o[21]
  PIN tl_u_rom_o[22]
    DIRECTION OUTPUT ;
    USE SIGNAL ;
    ANTENNADIFFAREA 0.445500 ;
    PORT
      LAYER met3 ;
        RECT 1296.000 935.040 1300.000 935.640 ;
    END
  END tl_u_rom_o[22]
  PIN tl_u_rom_o[23]
    DIRECTION OUTPUT ;
    USE SIGNAL ;
    ANTENNADIFFAREA 0.445500 ;
    PORT
      LAYER met3 ;
        RECT 0.000 340.040 4.000 340.640 ;
    END
  END tl_u_rom_o[23]
  PIN tl_u_rom_o[24]
    DIRECTION OUTPUT ;
    USE SIGNAL ;
    ANTENNADIFFAREA 0.445500 ;
    PORT
      LAYER met3 ;
        RECT 0.000 982.640 4.000 983.240 ;
    END
  END tl_u_rom_o[24]
  PIN tl_u_rom_o[25]
    DIRECTION OUTPUT ;
    USE SIGNAL ;
    ANTENNADIFFAREA 0.445500 ;
    PORT
      LAYER met3 ;
        RECT 0.000 421.640 4.000 422.240 ;
    END
  END tl_u_rom_o[25]
  PIN tl_u_rom_o[26]
    DIRECTION OUTPUT ;
    USE SIGNAL ;
    ANTENNADIFFAREA 0.445500 ;
    PORT
      LAYER met3 ;
        RECT 0.000 1098.240 4.000 1098.840 ;
    END
  END tl_u_rom_o[26]
  PIN tl_u_rom_o[27]
    DIRECTION OUTPUT ;
    USE SIGNAL ;
    ANTENNADIFFAREA 0.445500 ;
    PORT
      LAYER met3 ;
        RECT 0.000 564.440 4.000 565.040 ;
    END
  END tl_u_rom_o[27]
  PIN tl_u_rom_o[28]
    DIRECTION OUTPUT ;
    USE SIGNAL ;
    ANTENNADIFFAREA 0.445500 ;
    PORT
      LAYER met2 ;
        RECT 898.470 0.000 898.750 4.000 ;
    END
  END tl_u_rom_o[28]
  PIN tl_u_rom_o[29]
    DIRECTION OUTPUT ;
    USE SIGNAL ;
    ANTENNADIFFAREA 0.445500 ;
    PORT
      LAYER met3 ;
        RECT 0.000 3.440 4.000 4.040 ;
    END
  END tl_u_rom_o[29]
  PIN tl_u_rom_o[2]
    DIRECTION OUTPUT ;
    USE SIGNAL ;
    ANTENNADIFFAREA 0.445500 ;
    PORT
      LAYER met3 ;
        RECT 0.000 659.640 4.000 660.240 ;
    END
  END tl_u_rom_o[2]
  PIN tl_u_rom_o[30]
    DIRECTION OUTPUT ;
    USE SIGNAL ;
    ANTENNADIFFAREA 0.445500 ;
    PORT
      LAYER met3 ;
        RECT 1296.000 911.240 1300.000 911.840 ;
    END
  END tl_u_rom_o[30]
  PIN tl_u_rom_o[31]
    DIRECTION OUTPUT ;
    USE SIGNAL ;
    ANTENNADIFFAREA 0.445500 ;
    PORT
      LAYER met2 ;
        RECT 943.550 0.000 943.830 4.000 ;
    END
  END tl_u_rom_o[31]
  PIN tl_u_rom_o[32]
    DIRECTION OUTPUT ;
    USE SIGNAL ;
    ANTENNADIFFAREA 0.445500 ;
    PORT
      LAYER met2 ;
        RECT 776.110 0.000 776.390 4.000 ;
    END
  END tl_u_rom_o[32]
  PIN tl_u_rom_o[33]
    DIRECTION OUTPUT ;
    USE SIGNAL ;
    ANTENNADIFFAREA 0.445500 ;
    PORT
      LAYER met3 ;
        RECT 0.000 493.040 4.000 493.640 ;
    END
  END tl_u_rom_o[33]
  PIN tl_u_rom_o[34]
    DIRECTION OUTPUT ;
    USE SIGNAL ;
    ANTENNADIFFAREA 0.445500 ;
    PORT
      LAYER met3 ;
        RECT 0.000 625.640 4.000 626.240 ;
    END
  END tl_u_rom_o[34]
  PIN tl_u_rom_o[35]
    DIRECTION OUTPUT ;
    USE SIGNAL ;
    ANTENNADIFFAREA 0.445500 ;
    PORT
      LAYER met2 ;
        RECT 921.010 0.000 921.290 4.000 ;
    END
  END tl_u_rom_o[35]
  PIN tl_u_rom_o[36]
    DIRECTION OUTPUT ;
    USE SIGNAL ;
    ANTENNADIFFAREA 0.445500 ;
    PORT
      LAYER met3 ;
        RECT 0.000 724.240 4.000 724.840 ;
    END
  END tl_u_rom_o[36]
  PIN tl_u_rom_o[37]
    DIRECTION OUTPUT ;
    USE SIGNAL ;
    ANTENNADIFFAREA 0.445500 ;
    PORT
      LAYER met2 ;
        RECT 1284.870 0.000 1285.150 4.000 ;
    END
  END tl_u_rom_o[37]
  PIN tl_u_rom_o[38]
    DIRECTION OUTPUT ;
    USE SIGNAL ;
    ANTENNADIFFAREA 0.445500 ;
    PORT
      LAYER met3 ;
        RECT 0.000 540.640 4.000 541.240 ;
    END
  END tl_u_rom_o[38]
  PIN tl_u_rom_o[39]
    DIRECTION OUTPUT ;
    USE SIGNAL ;
    ANTENNADIFFAREA 0.445500 ;
    PORT
      LAYER met2 ;
        RECT 660.190 0.000 660.470 4.000 ;
    END
  END tl_u_rom_o[39]
  PIN tl_u_rom_o[3]
    DIRECTION OUTPUT ;
    USE SIGNAL ;
    ANTENNADIFFAREA 0.445500 ;
    PORT
      LAYER met2 ;
        RECT 1143.190 0.000 1143.470 4.000 ;
    END
  END tl_u_rom_o[3]
  PIN tl_u_rom_o[40]
    DIRECTION OUTPUT ;
    USE SIGNAL ;
    ANTENNADIFFAREA 0.445500 ;
    PORT
      LAYER met3 ;
        RECT 0.000 1060.840 4.000 1061.440 ;
    END
  END tl_u_rom_o[40]
  PIN tl_u_rom_o[41]
    DIRECTION OUTPUT ;
    USE SIGNAL ;
    ANTENNADIFFAREA 0.445500 ;
    PORT
      LAYER met2 ;
        RECT 937.110 0.000 937.390 4.000 ;
    END
  END tl_u_rom_o[41]
  PIN tl_u_rom_o[42]
    DIRECTION OUTPUT ;
    USE SIGNAL ;
    ANTENNADIFFAREA 0.445500 ;
    PORT
      LAYER met2 ;
        RECT 1191.490 0.000 1191.770 4.000 ;
    END
  END tl_u_rom_o[42]
  PIN tl_u_rom_o[43]
    DIRECTION OUTPUT ;
    USE SIGNAL ;
    ANTENNADIFFAREA 0.445500 ;
    PORT
      LAYER met3 ;
        RECT 0.000 635.840 4.000 636.440 ;
    END
  END tl_u_rom_o[43]
  PIN tl_u_rom_o[44]
    DIRECTION OUTPUT ;
    USE SIGNAL ;
    ANTENNADIFFAREA 0.445500 ;
    PORT
      LAYER met3 ;
        RECT 0.000 1251.240 4.000 1251.840 ;
    END
  END tl_u_rom_o[44]
  PIN tl_u_rom_o[45]
    DIRECTION OUTPUT ;
    USE SIGNAL ;
    ANTENNADIFFAREA 0.445500 ;
    PORT
      LAYER met2 ;
        RECT 1178.610 0.000 1178.890 4.000 ;
    END
  END tl_u_rom_o[45]
  PIN tl_u_rom_o[46]
    DIRECTION OUTPUT ;
    USE SIGNAL ;
    ANTENNADIFFAREA 0.445500 ;
    PORT
      LAYER met3 ;
        RECT 1296.000 999.640 1300.000 1000.240 ;
    END
  END tl_u_rom_o[46]
  PIN tl_u_rom_o[47]
    DIRECTION OUTPUT ;
    USE SIGNAL ;
    ANTENNADIFFAREA 0.445500 ;
    PORT
      LAYER met3 ;
        RECT 0.000 652.840 4.000 653.440 ;
    END
  END tl_u_rom_o[47]
  PIN tl_u_rom_o[48]
    DIRECTION OUTPUT ;
    USE SIGNAL ;
    ANTENNADIFFAREA 0.445500 ;
    PORT
      LAYER met3 ;
        RECT 0.000 897.640 4.000 898.240 ;
    END
  END tl_u_rom_o[48]
  PIN tl_u_rom_o[49]
    DIRECTION OUTPUT ;
    USE SIGNAL ;
    ANTENNADIFFAREA 0.445500 ;
    PORT
      LAYER met3 ;
        RECT 0.000 1013.240 4.000 1013.840 ;
    END
  END tl_u_rom_o[49]
  PIN tl_u_rom_o[4]
    DIRECTION OUTPUT ;
    USE SIGNAL ;
    ANTENNADIFFAREA 0.445500 ;
    PORT
      LAYER met2 ;
        RECT 727.810 0.000 728.090 4.000 ;
    END
  END tl_u_rom_o[4]
  PIN tl_u_rom_o[50]
    DIRECTION OUTPUT ;
    USE SIGNAL ;
    ANTENNADIFFAREA 0.445500 ;
    PORT
      LAYER met2 ;
        RECT 927.450 0.000 927.730 4.000 ;
    END
  END tl_u_rom_o[50]
  PIN tl_u_rom_o[51]
    DIRECTION OUTPUT ;
    USE SIGNAL ;
    ANTENNADIFFAREA 0.445500 ;
    PORT
      LAYER met3 ;
        RECT 0.000 690.240 4.000 690.840 ;
    END
  END tl_u_rom_o[51]
  PIN tl_u_rom_o[52]
    DIRECTION OUTPUT ;
    USE SIGNAL ;
    ANTENNADIFFAREA 0.445500 ;
    PORT
      LAYER met2 ;
        RECT 824.410 0.000 824.690 4.000 ;
    END
  END tl_u_rom_o[52]
  PIN tl_u_rom_o[53]
    DIRECTION OUTPUT ;
    USE SIGNAL ;
    ANTENNADIFFAREA 0.445500 ;
    PORT
      LAYER met3 ;
        RECT 1296.000 200.640 1300.000 201.240 ;
    END
  END tl_u_rom_o[53]
  PIN tl_u_rom_o[54]
    DIRECTION OUTPUT ;
    USE SIGNAL ;
    ANTENNADIFFAREA 0.445500 ;
    PORT
      LAYER met3 ;
        RECT 0.000 771.840 4.000 772.440 ;
    END
  END tl_u_rom_o[54]
  PIN tl_u_rom_o[55]
    DIRECTION OUTPUT ;
    USE SIGNAL ;
    ANTENNADIFFAREA 0.445500 ;
    PORT
      LAYER met3 ;
        RECT 0.000 1190.040 4.000 1190.640 ;
    END
  END tl_u_rom_o[55]
  PIN tl_u_rom_o[56]
    DIRECTION OUTPUT ;
    USE SIGNAL ;
    ANTENNADIFFAREA 0.445500 ;
    PORT
      LAYER met3 ;
        RECT 0.000 1159.440 4.000 1160.040 ;
    END
  END tl_u_rom_o[56]
  PIN tl_u_rom_o[57]
    DIRECTION OUTPUT ;
    USE SIGNAL ;
    ANTENNADIFFAREA 0.445500 ;
    PORT
      LAYER met3 ;
        RECT 0.000 1230.840 4.000 1231.440 ;
    END
  END tl_u_rom_o[57]
  PIN tl_u_rom_o[58]
    DIRECTION OUTPUT ;
    USE SIGNAL ;
    ANTENNADIFFAREA 0.445500 ;
    PORT
      LAYER met3 ;
        RECT 1296.000 1020.040 1300.000 1020.640 ;
    END
  END tl_u_rom_o[58]
  PIN tl_u_rom_o[59]
    DIRECTION OUTPUT ;
    USE SIGNAL ;
    ANTENNADIFFAREA 0.445500 ;
    PORT
      LAYER met3 ;
        RECT 1296.000 465.840 1300.000 466.440 ;
    END
  END tl_u_rom_o[59]
  PIN tl_u_rom_o[5]
    DIRECTION OUTPUT ;
    USE SIGNAL ;
    ANTENNADIFFAREA 0.445500 ;
    PORT
      LAYER met3 ;
        RECT 0.000 1054.040 4.000 1054.640 ;
    END
  END tl_u_rom_o[5]
  PIN tl_u_rom_o[60]
    DIRECTION OUTPUT ;
    USE SIGNAL ;
    ANTENNADIFFAREA 0.445500 ;
    PORT
      LAYER met3 ;
        RECT 1296.000 1111.840 1300.000 1112.440 ;
    END
  END tl_u_rom_o[60]
  PIN tl_u_rom_o[61]
    DIRECTION OUTPUT ;
    USE SIGNAL ;
    ANTENNADIFFAREA 0.445500 ;
    PORT
      LAYER met3 ;
        RECT 0.000 363.840 4.000 364.440 ;
    END
  END tl_u_rom_o[61]
  PIN tl_u_rom_o[62]
    DIRECTION OUTPUT ;
    USE SIGNAL ;
    ANTENNADIFFAREA 0.445500 ;
    PORT
      LAYER met3 ;
        RECT 0.000 37.440 4.000 38.040 ;
    END
  END tl_u_rom_o[62]
  PIN tl_u_rom_o[63]
    DIRECTION OUTPUT ;
    USE SIGNAL ;
    ANTENNADIFFAREA 0.445500 ;
    PORT
      LAYER met3 ;
        RECT 0.000 350.240 4.000 350.840 ;
    END
  END tl_u_rom_o[63]
  PIN tl_u_rom_o[64]
    DIRECTION OUTPUT ;
    USE SIGNAL ;
    ANTENNADIFFAREA 0.445500 ;
    PORT
      LAYER met3 ;
        RECT 0.000 482.840 4.000 483.440 ;
    END
  END tl_u_rom_o[64]
  PIN tl_u_rom_o[65]
    DIRECTION OUTPUT ;
    USE SIGNAL ;
    ANTENNADIFFAREA 0.445500 ;
    PORT
      LAYER met3 ;
        RECT 0.000 234.640 4.000 235.240 ;
    END
  END tl_u_rom_o[65]
  PIN tl_u_rom_o[66]
    DIRECTION OUTPUT ;
    USE SIGNAL ;
    ANTENNADIFFAREA 0.445500 ;
    PORT
      LAYER met3 ;
        RECT 0.000 306.040 4.000 306.640 ;
    END
  END tl_u_rom_o[66]
  PIN tl_u_rom_o[67]
    DIRECTION OUTPUT ;
    USE SIGNAL ;
    ANTENNADIFFAREA 0.445500 ;
    PORT
      LAYER met3 ;
        RECT 0.000 302.640 4.000 303.240 ;
    END
  END tl_u_rom_o[67]
  PIN tl_u_rom_o[68]
    DIRECTION OUTPUT ;
    USE SIGNAL ;
    ANTENNADIFFAREA 0.445500 ;
    PORT
      LAYER met3 ;
        RECT 0.000 391.040 4.000 391.640 ;
    END
  END tl_u_rom_o[68]
  PIN tl_u_rom_o[69]
    DIRECTION OUTPUT ;
    USE SIGNAL ;
    ANTENNADIFFAREA 0.445500 ;
    PORT
      LAYER met3 ;
        RECT 0.000 112.240 4.000 112.840 ;
    END
  END tl_u_rom_o[69]
  PIN tl_u_rom_o[6]
    DIRECTION OUTPUT ;
    USE SIGNAL ;
    ANTENNADIFFAREA 0.445500 ;
    PORT
      LAYER met3 ;
        RECT 0.000 839.840 4.000 840.440 ;
    END
  END tl_u_rom_o[6]
  PIN tl_u_rom_o[70]
    DIRECTION OUTPUT ;
    USE SIGNAL ;
    ANTENNADIFFAREA 0.445500 ;
    PORT
      LAYER met3 ;
        RECT 0.000 465.840 4.000 466.440 ;
    END
  END tl_u_rom_o[70]
  PIN tl_u_rom_o[71]
    DIRECTION OUTPUT ;
    USE SIGNAL ;
    ANTENNADIFFAREA 0.445500 ;
    PORT
      LAYER met3 ;
        RECT 0.000 404.640 4.000 405.240 ;
    END
  END tl_u_rom_o[71]
  PIN tl_u_rom_o[72]
    DIRECTION OUTPUT ;
    USE SIGNAL ;
    ANTENNADIFFAREA 0.445500 ;
    PORT
      LAYER met3 ;
        RECT 0.000 282.240 4.000 282.840 ;
    END
  END tl_u_rom_o[72]
  PIN tl_u_rom_o[73]
    DIRECTION OUTPUT ;
    USE SIGNAL ;
    ANTENNADIFFAREA 0.445500 ;
    PORT
      LAYER met3 ;
        RECT 0.000 74.840 4.000 75.440 ;
    END
  END tl_u_rom_o[73]
  PIN tl_u_rom_o[74]
    DIRECTION OUTPUT ;
    USE SIGNAL ;
    ANTENNADIFFAREA 0.445500 ;
    PORT
      LAYER met3 ;
        RECT 0.000 472.640 4.000 473.240 ;
    END
  END tl_u_rom_o[74]
  PIN tl_u_rom_o[75]
    DIRECTION OUTPUT ;
    USE SIGNAL ;
    ANTENNADIFFAREA 0.445500 ;
    PORT
      LAYER met3 ;
        RECT 0.000 170.040 4.000 170.640 ;
    END
  END tl_u_rom_o[75]
  PIN tl_u_rom_o[76]
    DIRECTION OUTPUT ;
    USE SIGNAL ;
    ANTENNADIFFAREA 0.445500 ;
    PORT
      LAYER met3 ;
        RECT 0.000 323.040 4.000 323.640 ;
    END
  END tl_u_rom_o[76]
  PIN tl_u_rom_o[77]
    DIRECTION OUTPUT ;
    USE SIGNAL ;
    ANTENNADIFFAREA 0.445500 ;
    PORT
      LAYER met3 ;
        RECT 0.000 207.440 4.000 208.040 ;
    END
  END tl_u_rom_o[77]
  PIN tl_u_rom_o[78]
    DIRECTION OUTPUT ;
    USE SIGNAL ;
    ANTENNADIFFAREA 0.445500 ;
    PORT
      LAYER met3 ;
        RECT 0.000 537.240 4.000 537.840 ;
    END
  END tl_u_rom_o[78]
  PIN tl_u_rom_o[79]
    DIRECTION OUTPUT ;
    USE SIGNAL ;
    ANTENNADIFFAREA 0.445500 ;
    PORT
      LAYER met3 ;
        RECT 0.000 163.240 4.000 163.840 ;
    END
  END tl_u_rom_o[79]
  PIN tl_u_rom_o[7]
    DIRECTION OUTPUT ;
    USE SIGNAL ;
    ANTENNADIFFAREA 0.445500 ;
    PORT
      LAYER met3 ;
        RECT 1296.000 496.440 1300.000 497.040 ;
    END
  END tl_u_rom_o[7]
  PIN tl_u_rom_o[80]
    DIRECTION OUTPUT ;
    USE SIGNAL ;
    ANTENNADIFFAREA 0.445500 ;
    PORT
      LAYER met3 ;
        RECT 0.000 244.840 4.000 245.440 ;
    END
  END tl_u_rom_o[80]
  PIN tl_u_rom_o[81]
    DIRECTION OUTPUT ;
    USE SIGNAL ;
    ANTENNADIFFAREA 0.445500 ;
    PORT
      LAYER met3 ;
        RECT 0.000 554.240 4.000 554.840 ;
    END
  END tl_u_rom_o[81]
  PIN tl_u_rom_o[82]
    DIRECTION OUTPUT ;
    USE SIGNAL ;
    ANTENNADIFFAREA 0.445500 ;
    PORT
      LAYER met3 ;
        RECT 0.000 261.840 4.000 262.440 ;
    END
  END tl_u_rom_o[82]
  PIN tl_u_rom_o[83]
    DIRECTION OUTPUT ;
    USE SIGNAL ;
    ANTENNADIFFAREA 0.445500 ;
    PORT
      LAYER met3 ;
        RECT 0.000 571.240 4.000 571.840 ;
    END
  END tl_u_rom_o[83]
  PIN tl_u_rom_o[84]
    DIRECTION OUTPUT ;
    USE SIGNAL ;
    ANTENNADIFFAREA 0.445500 ;
    PORT
      LAYER met3 ;
        RECT 0.000 523.640 4.000 524.240 ;
    END
  END tl_u_rom_o[84]
  PIN tl_u_rom_o[85]
    DIRECTION OUTPUT ;
    USE SIGNAL ;
    ANTENNADIFFAREA 0.445500 ;
    PORT
      LAYER met3 ;
        RECT 0.000 510.040 4.000 510.640 ;
    END
  END tl_u_rom_o[85]
  PIN tl_u_rom_o[86]
    DIRECTION OUTPUT ;
    USE SIGNAL ;
    ANTENNADIFFAREA 0.445500 ;
    PORT
      LAYER met3 ;
        RECT 0.000 370.640 4.000 371.240 ;
    END
  END tl_u_rom_o[86]
  PIN tl_u_rom_o[87]
    DIRECTION OUTPUT ;
    USE SIGNAL ;
    ANTENNADIFFAREA 0.445500 ;
    PORT
      LAYER met3 ;
        RECT 0.000 357.040 4.000 357.640 ;
    END
  END tl_u_rom_o[87]
  PIN tl_u_rom_o[88]
    DIRECTION OUTPUT ;
    USE SIGNAL ;
    ANTENNADIFFAREA 0.445500 ;
    PORT
      LAYER met3 ;
        RECT 0.000 105.440 4.000 106.040 ;
    END
  END tl_u_rom_o[88]
  PIN tl_u_rom_o[89]
    DIRECTION OUTPUT ;
    USE SIGNAL ;
    ANTENNADIFFAREA 0.445500 ;
    PORT
      LAYER met3 ;
        RECT 0.000 377.440 4.000 378.040 ;
    END
  END tl_u_rom_o[89]
  PIN tl_u_rom_o[8]
    DIRECTION OUTPUT ;
    USE SIGNAL ;
    ANTENNADIFFAREA 0.445500 ;
    PORT
      LAYER met3 ;
        RECT 1296.000 1254.640 1300.000 1255.240 ;
    END
  END tl_u_rom_o[8]
  PIN tl_u_rom_o[90]
    DIRECTION OUTPUT ;
    USE SIGNAL ;
    ANTENNADIFFAREA 0.445500 ;
    PORT
      LAYER met3 ;
        RECT 0.000 238.040 4.000 238.640 ;
    END
  END tl_u_rom_o[90]
  PIN tl_u_rom_o[91]
    DIRECTION OUTPUT ;
    USE SIGNAL ;
    ANTENNADIFFAREA 0.445500 ;
    PORT
      LAYER met3 ;
        RECT 0.000 336.640 4.000 337.240 ;
    END
  END tl_u_rom_o[91]
  PIN tl_u_rom_o[92]
    DIRECTION OUTPUT ;
    USE SIGNAL ;
    ANTENNADIFFAREA 0.445500 ;
    PORT
      LAYER met3 ;
        RECT 0.000 129.240 4.000 129.840 ;
    END
  END tl_u_rom_o[92]
  PIN tl_u_rom_o[93]
    DIRECTION OUTPUT ;
    USE SIGNAL ;
    ANTENNADIFFAREA 0.445500 ;
    PORT
      LAYER met3 ;
        RECT 1296.000 217.640 1300.000 218.240 ;
    END
  END tl_u_rom_o[93]
  PIN tl_u_rom_o[94]
    DIRECTION OUTPUT ;
    USE SIGNAL ;
    ANTENNADIFFAREA 0.445500 ;
    PORT
      LAYER met3 ;
        RECT 1296.000 425.040 1300.000 425.640 ;
    END
  END tl_u_rom_o[94]
  PIN tl_u_rom_o[95]
    DIRECTION OUTPUT ;
    USE SIGNAL ;
    ANTENNADIFFAREA 0.445500 ;
    PORT
      LAYER met3 ;
        RECT 1296.000 897.640 1300.000 898.240 ;
    END
  END tl_u_rom_o[95]
  PIN tl_u_rom_o[96]
    DIRECTION OUTPUT ;
    USE SIGNAL ;
    ANTENNADIFFAREA 0.445500 ;
    PORT
      LAYER met3 ;
        RECT 0.000 860.240 4.000 860.840 ;
    END
  END tl_u_rom_o[96]
  PIN tl_u_rom_o[97]
    DIRECTION OUTPUT ;
    USE SIGNAL ;
    ANTENNADIFFAREA 0.445500 ;
    PORT
      LAYER met3 ;
        RECT 1296.000 1091.440 1300.000 1092.040 ;
    END
  END tl_u_rom_o[97]
  PIN tl_u_rom_o[98]
    DIRECTION OUTPUT ;
    USE SIGNAL ;
    ANTENNADIFFAREA 0.445500 ;
    PORT
      LAYER met3 ;
        RECT 0.000 598.440 4.000 599.040 ;
    END
  END tl_u_rom_o[98]
  PIN tl_u_rom_o[99]
    DIRECTION OUTPUT ;
    USE SIGNAL ;
    ANTENNADIFFAREA 0.445500 ;
    PORT
      LAYER met3 ;
        RECT 0.000 833.040 4.000 833.640 ;
    END
  END tl_u_rom_o[99]
  PIN tl_u_rom_o[9]
    DIRECTION OUTPUT ;
    USE SIGNAL ;
    ANTENNADIFFAREA 0.445500 ;
    PORT
      LAYER met3 ;
        RECT 1296.000 1207.040 1300.000 1207.640 ;
    END
  END tl_u_rom_o[9]
  PIN tl_u_spi_host_i[0]
    DIRECTION INPUT ;
    USE SIGNAL ;
    ANTENNAGATEAREA 0.593700 ;
    ANTENNADIFFAREA 0.434700 ;
    PORT
      LAYER met3 ;
        RECT 0.000 408.040 4.000 408.640 ;
    END
  END tl_u_spi_host_i[0]
  PIN tl_u_spi_host_i[10]
    DIRECTION INPUT ;
    USE SIGNAL ;
    ANTENNAGATEAREA 0.631200 ;
    ANTENNADIFFAREA 0.434700 ;
    PORT
      LAYER met3 ;
        RECT 0.000 921.440 4.000 922.040 ;
    END
  END tl_u_spi_host_i[10]
  PIN tl_u_spi_host_i[11]
    DIRECTION INPUT ;
    USE SIGNAL ;
    ANTENNAGATEAREA 0.647700 ;
    ANTENNADIFFAREA 0.434700 ;
    PORT
      LAYER met3 ;
        RECT 1296.000 343.440 1300.000 344.040 ;
    END
  END tl_u_spi_host_i[11]
  PIN tl_u_spi_host_i[12]
    DIRECTION INPUT ;
    USE SIGNAL ;
    ANTENNAGATEAREA 0.631200 ;
    ANTENNADIFFAREA 0.434700 ;
    PORT
      LAYER met3 ;
        RECT 1296.000 1084.640 1300.000 1085.240 ;
    END
  END tl_u_spi_host_i[12]
  PIN tl_u_spi_host_i[13]
    DIRECTION INPUT ;
    USE SIGNAL ;
    ANTENNAGATEAREA 0.631200 ;
    ANTENNADIFFAREA 0.434700 ;
    PORT
      LAYER met3 ;
        RECT 1296.000 357.040 1300.000 357.640 ;
    END
  END tl_u_spi_host_i[13]
  PIN tl_u_spi_host_i[14]
    DIRECTION INPUT ;
    USE SIGNAL ;
    ANTENNAGATEAREA 0.631200 ;
    ANTENNADIFFAREA 0.434700 ;
    PORT
      LAYER met3 ;
        RECT 0.000 1156.040 4.000 1156.640 ;
    END
  END tl_u_spi_host_i[14]
  PIN tl_u_spi_host_i[15]
    DIRECTION INPUT ;
    USE SIGNAL ;
    ANTENNAGATEAREA 0.631200 ;
    ANTENNADIFFAREA 0.434700 ;
    PORT
      LAYER met3 ;
        RECT 1296.000 404.640 1300.000 405.240 ;
    END
  END tl_u_spi_host_i[15]
  PIN tl_u_spi_host_i[16]
    DIRECTION INPUT ;
    USE SIGNAL ;
    ANTENNAGATEAREA 0.631200 ;
    ANTENNADIFFAREA 0.434700 ;
    PORT
      LAYER met3 ;
        RECT 1296.000 1033.640 1300.000 1034.240 ;
    END
  END tl_u_spi_host_i[16]
  PIN tl_u_spi_host_i[17]
    DIRECTION INPUT ;
    USE SIGNAL ;
    ANTENNAGATEAREA 0.647700 ;
    ANTENNADIFFAREA 0.434700 ;
    PORT
      LAYER met3 ;
        RECT 1296.000 1006.440 1300.000 1007.040 ;
    END
  END tl_u_spi_host_i[17]
  PIN tl_u_spi_host_i[18]
    DIRECTION INPUT ;
    USE SIGNAL ;
    ANTENNAGATEAREA 0.631200 ;
    ANTENNADIFFAREA 0.434700 ;
    PORT
      LAYER met3 ;
        RECT 1296.000 377.440 1300.000 378.040 ;
    END
  END tl_u_spi_host_i[18]
  PIN tl_u_spi_host_i[19]
    DIRECTION INPUT ;
    USE SIGNAL ;
    ANTENNAGATEAREA 0.631200 ;
    ANTENNADIFFAREA 0.434700 ;
    PORT
      LAYER met3 ;
        RECT 1296.000 1074.440 1300.000 1075.040 ;
    END
  END tl_u_spi_host_i[19]
  PIN tl_u_spi_host_i[1]
    DIRECTION INPUT ;
    USE SIGNAL ;
    ANTENNAGATEAREA 0.647700 ;
    ANTENNADIFFAREA 0.434700 ;
    PORT
      LAYER met3 ;
        RECT 1296.000 1118.640 1300.000 1119.240 ;
    END
  END tl_u_spi_host_i[1]
  PIN tl_u_spi_host_i[20]
    DIRECTION INPUT ;
    USE SIGNAL ;
    ANTENNAGATEAREA 0.593700 ;
    ANTENNADIFFAREA 0.434700 ;
    PORT
      LAYER met3 ;
        RECT 1296.000 391.040 1300.000 391.640 ;
    END
  END tl_u_spi_host_i[20]
  PIN tl_u_spi_host_i[21]
    DIRECTION INPUT ;
    USE SIGNAL ;
    ANTENNAGATEAREA 0.647700 ;
    ANTENNADIFFAREA 0.434700 ;
    PORT
      LAYER met3 ;
        RECT 1296.000 625.640 1300.000 626.240 ;
    END
  END tl_u_spi_host_i[21]
  PIN tl_u_spi_host_i[22]
    DIRECTION INPUT ;
    USE SIGNAL ;
    ANTENNAGATEAREA 0.560700 ;
    ANTENNADIFFAREA 0.434700 ;
    PORT
      LAYER met3 ;
        RECT 0.000 1193.440 4.000 1194.040 ;
    END
  END tl_u_spi_host_i[22]
  PIN tl_u_spi_host_i[23]
    DIRECTION INPUT ;
    USE SIGNAL ;
    ANTENNAGATEAREA 0.593700 ;
    ANTENNADIFFAREA 0.434700 ;
    PORT
      LAYER met3 ;
        RECT 1296.000 1125.440 1300.000 1126.040 ;
    END
  END tl_u_spi_host_i[23]
  PIN tl_u_spi_host_i[24]
    DIRECTION INPUT ;
    USE SIGNAL ;
    ANTENNAGATEAREA 0.647700 ;
    ANTENNADIFFAREA 0.434700 ;
    PORT
      LAYER met3 ;
        RECT 1296.000 1258.040 1300.000 1258.640 ;
    END
  END tl_u_spi_host_i[24]
  PIN tl_u_spi_host_i[25]
    DIRECTION INPUT ;
    USE SIGNAL ;
    ANTENNAGATEAREA 0.647700 ;
    ANTENNADIFFAREA 0.434700 ;
    PORT
      LAYER met3 ;
        RECT 1296.000 1210.440 1300.000 1211.040 ;
    END
  END tl_u_spi_host_i[25]
  PIN tl_u_spi_host_i[26]
    DIRECTION INPUT ;
    USE SIGNAL ;
    ANTENNAGATEAREA 0.647700 ;
    ANTENNADIFFAREA 0.434700 ;
    PORT
      LAYER met3 ;
        RECT 1296.000 969.040 1300.000 969.640 ;
    END
  END tl_u_spi_host_i[26]
  PIN tl_u_spi_host_i[27]
    DIRECTION INPUT ;
    USE SIGNAL ;
    ANTENNAGATEAREA 0.631200 ;
    ANTENNADIFFAREA 0.434700 ;
    PORT
      LAYER met3 ;
        RECT 1296.000 350.240 1300.000 350.840 ;
    END
  END tl_u_spi_host_i[27]
  PIN tl_u_spi_host_i[28]
    DIRECTION INPUT ;
    USE SIGNAL ;
    ANTENNAGATEAREA 0.647700 ;
    ANTENNADIFFAREA 0.434700 ;
    PORT
      LAYER met3 ;
        RECT 1296.000 265.240 1300.000 265.840 ;
    END
  END tl_u_spi_host_i[28]
  PIN tl_u_spi_host_i[29]
    DIRECTION INPUT ;
    USE SIGNAL ;
    ANTENNAGATEAREA 0.682200 ;
    ANTENNADIFFAREA 0.434700 ;
    PORT
      LAYER met3 ;
        RECT 1296.000 697.040 1300.000 697.640 ;
    END
  END tl_u_spi_host_i[29]
  PIN tl_u_spi_host_i[2]
    DIRECTION INPUT ;
    USE SIGNAL ;
    ANTENNAGATEAREA 0.647700 ;
    ANTENNADIFFAREA 0.434700 ;
    PORT
      LAYER met3 ;
        RECT 1296.000 1037.040 1300.000 1037.640 ;
    END
  END tl_u_spi_host_i[2]
  PIN tl_u_spi_host_i[30]
    DIRECTION INPUT ;
    USE SIGNAL ;
    ANTENNAGATEAREA 0.647700 ;
    ANTENNADIFFAREA 0.434700 ;
    PORT
      LAYER met3 ;
        RECT 1296.000 289.040 1300.000 289.640 ;
    END
  END tl_u_spi_host_i[30]
  PIN tl_u_spi_host_i[31]
    DIRECTION INPUT ;
    USE SIGNAL ;
    ANTENNAGATEAREA 0.647700 ;
    ANTENNADIFFAREA 0.434700 ;
    PORT
      LAYER met3 ;
        RECT 0.000 795.640 4.000 796.240 ;
    END
  END tl_u_spi_host_i[31]
  PIN tl_u_spi_host_i[32]
    DIRECTION INPUT ;
    USE SIGNAL ;
    ANTENNAGATEAREA 0.631200 ;
    ANTENNADIFFAREA 0.434700 ;
    PORT
      LAYER met3 ;
        RECT 1296.000 336.640 1300.000 337.240 ;
    END
  END tl_u_spi_host_i[32]
  PIN tl_u_spi_host_i[33]
    DIRECTION INPUT ;
    USE SIGNAL ;
    ANTENNAGATEAREA 0.682200 ;
    ANTENNADIFFAREA 0.434700 ;
    PORT
      LAYER met3 ;
        RECT 1296.000 204.040 1300.000 204.640 ;
    END
  END tl_u_spi_host_i[33]
  PIN tl_u_spi_host_i[34]
    DIRECTION INPUT ;
    USE SIGNAL ;
    ANTENNAGATEAREA 0.647700 ;
    ANTENNADIFFAREA 0.434700 ;
    PORT
      LAYER met3 ;
        RECT 1296.000 227.840 1300.000 228.440 ;
    END
  END tl_u_spi_host_i[34]
  PIN tl_u_spi_host_i[35]
    DIRECTION INPUT ;
    USE SIGNAL ;
    ANTENNAGATEAREA 0.560700 ;
    ANTENNADIFFAREA 0.434700 ;
    PORT
      LAYER met3 ;
        RECT 1296.000 1050.640 1300.000 1051.240 ;
    END
  END tl_u_spi_host_i[35]
  PIN tl_u_spi_host_i[36]
    DIRECTION INPUT ;
    USE SIGNAL ;
    ANTENNAGATEAREA 0.560700 ;
    ANTENNADIFFAREA 0.434700 ;
    PORT
      LAYER met3 ;
        RECT 1296.000 771.840 1300.000 772.440 ;
    END
  END tl_u_spi_host_i[36]
  PIN tl_u_spi_host_i[37]
    DIRECTION INPUT ;
    USE SIGNAL ;
    ANTENNAGATEAREA 0.593700 ;
    ANTENNADIFFAREA 0.434700 ;
    PORT
      LAYER met3 ;
        RECT 1296.000 248.240 1300.000 248.840 ;
    END
  END tl_u_spi_host_i[37]
  PIN tl_u_spi_host_i[38]
    DIRECTION INPUT ;
    USE SIGNAL ;
    ANTENNAGATEAREA 0.631200 ;
    ANTENNADIFFAREA 0.434700 ;
    PORT
      LAYER met3 ;
        RECT 0.000 1217.240 4.000 1217.840 ;
    END
  END tl_u_spi_host_i[38]
  PIN tl_u_spi_host_i[39]
    DIRECTION INPUT ;
    USE SIGNAL ;
    ANTENNAGATEAREA 0.647700 ;
    ANTENNADIFFAREA 0.434700 ;
    PORT
      LAYER met3 ;
        RECT 1296.000 646.040 1300.000 646.640 ;
    END
  END tl_u_spi_host_i[39]
  PIN tl_u_spi_host_i[3]
    DIRECTION INPUT ;
    USE SIGNAL ;
    ANTENNAGATEAREA 0.593700 ;
    ANTENNADIFFAREA 0.434700 ;
    PORT
      LAYER met3 ;
        RECT 1296.000 887.440 1300.000 888.040 ;
    END
  END tl_u_spi_host_i[3]
  PIN tl_u_spi_host_i[40]
    DIRECTION INPUT ;
    USE SIGNAL ;
    ANTENNAGATEAREA 0.593700 ;
    ANTENNADIFFAREA 0.434700 ;
    PORT
      LAYER met3 ;
        RECT 1296.000 860.240 1300.000 860.840 ;
    END
  END tl_u_spi_host_i[40]
  PIN tl_u_spi_host_i[41]
    DIRECTION INPUT ;
    USE SIGNAL ;
    ANTENNAGATEAREA 0.631200 ;
    ANTENNADIFFAREA 0.434700 ;
    PORT
      LAYER met3 ;
        RECT 1296.000 1043.840 1300.000 1044.440 ;
    END
  END tl_u_spi_host_i[41]
  PIN tl_u_spi_host_i[42]
    DIRECTION INPUT ;
    USE SIGNAL ;
    ANTENNAGATEAREA 0.593700 ;
    ANTENNADIFFAREA 0.434700 ;
    PORT
      LAYER met3 ;
        RECT 1296.000 1132.240 1300.000 1132.840 ;
    END
  END tl_u_spi_host_i[42]
  PIN tl_u_spi_host_i[43]
    DIRECTION INPUT ;
    USE SIGNAL ;
    ANTENNAGATEAREA 0.647700 ;
    ANTENNADIFFAREA 0.434700 ;
    PORT
      LAYER met3 ;
        RECT 1296.000 622.240 1300.000 622.840 ;
    END
  END tl_u_spi_host_i[43]
  PIN tl_u_spi_host_i[44]
    DIRECTION INPUT ;
    USE SIGNAL ;
    ANTENNAGATEAREA 0.647700 ;
    ANTENNADIFFAREA 0.434700 ;
    PORT
      LAYER met3 ;
        RECT 1296.000 1013.240 1300.000 1013.840 ;
    END
  END tl_u_spi_host_i[44]
  PIN tl_u_spi_host_i[45]
    DIRECTION INPUT ;
    USE SIGNAL ;
    ANTENNAGATEAREA 0.647700 ;
    ANTENNADIFFAREA 0.434700 ;
    PORT
      LAYER met3 ;
        RECT 1296.000 795.640 1300.000 796.240 ;
    END
  END tl_u_spi_host_i[45]
  PIN tl_u_spi_host_i[46]
    DIRECTION INPUT ;
    USE SIGNAL ;
    ANTENNAGATEAREA 0.560700 ;
    ANTENNADIFFAREA 0.434700 ;
    PORT
      LAYER met3 ;
        RECT 1296.000 1016.640 1300.000 1017.240 ;
    END
  END tl_u_spi_host_i[46]
  PIN tl_u_spi_host_i[47]
    DIRECTION INPUT ;
    USE SIGNAL ;
    ANTENNAGATEAREA 0.860700 ;
    ANTENNADIFFAREA 0.434700 ;
    PORT
      LAYER met3 ;
        RECT 0.000 924.840 4.000 925.440 ;
    END
  END tl_u_spi_host_i[47]
  PIN tl_u_spi_host_i[48]
    DIRECTION INPUT ;
    USE SIGNAL ;
    ANTENNAGATEAREA 0.631200 ;
    ANTENNADIFFAREA 0.434700 ;
    PORT
      LAYER met3 ;
        RECT 0.000 1088.040 4.000 1088.640 ;
    END
  END tl_u_spi_host_i[48]
  PIN tl_u_spi_host_i[49]
    DIRECTION INPUT ;
    USE SIGNAL ;
    ANTENNAGATEAREA 0.631200 ;
    ANTENNADIFFAREA 0.434700 ;
    PORT
      LAYER met3 ;
        RECT 1296.000 666.440 1300.000 667.040 ;
    END
  END tl_u_spi_host_i[49]
  PIN tl_u_spi_host_i[4]
    DIRECTION INPUT ;
    USE SIGNAL ;
    ANTENNAGATEAREA 0.647700 ;
    ANTENNADIFFAREA 0.434700 ;
    PORT
      LAYER met3 ;
        RECT 1296.000 673.240 1300.000 673.840 ;
    END
  END tl_u_spi_host_i[4]
  PIN tl_u_spi_host_i[50]
    DIRECTION INPUT ;
    USE SIGNAL ;
    ANTENNAGATEAREA 0.860700 ;
    ANTENNADIFFAREA 0.434700 ;
    PORT
      LAYER met3 ;
        RECT 0.000 744.640 4.000 745.240 ;
    END
  END tl_u_spi_host_i[50]
  PIN tl_u_spi_host_i[51]
    DIRECTION INPUT ;
    USE SIGNAL ;
    ANTENNAGATEAREA 0.647700 ;
    ANTENNADIFFAREA 0.434700 ;
    PORT
      LAYER met3 ;
        RECT 1296.000 1213.840 1300.000 1214.440 ;
    END
  END tl_u_spi_host_i[51]
  PIN tl_u_spi_host_i[52]
    DIRECTION INPUT ;
    USE SIGNAL ;
    ANTENNAGATEAREA 0.647700 ;
    ANTENNADIFFAREA 0.434700 ;
    PORT
      LAYER met3 ;
        RECT 1296.000 1067.640 1300.000 1068.240 ;
    END
  END tl_u_spi_host_i[52]
  PIN tl_u_spi_host_i[53]
    DIRECTION INPUT ;
    USE SIGNAL ;
    ANTENNAGATEAREA 0.647700 ;
    ANTENNADIFFAREA 0.434700 ;
    PORT
      LAYER met3 ;
        RECT 0.000 1200.240 4.000 1200.840 ;
    END
  END tl_u_spi_host_i[53]
  PIN tl_u_spi_host_i[54]
    DIRECTION INPUT ;
    USE SIGNAL ;
    ANTENNAGATEAREA 0.593700 ;
    ANTENNADIFFAREA 0.434700 ;
    PORT
      LAYER met3 ;
        RECT 1296.000 384.240 1300.000 384.840 ;
    END
  END tl_u_spi_host_i[54]
  PIN tl_u_spi_host_i[55]
    DIRECTION INPUT ;
    USE SIGNAL ;
    ANTENNAGATEAREA 0.631200 ;
    ANTENNADIFFAREA 0.434700 ;
    PORT
      LAYER met3 ;
        RECT 1296.000 275.440 1300.000 276.040 ;
    END
  END tl_u_spi_host_i[55]
  PIN tl_u_spi_host_i[56]
    DIRECTION INPUT ;
    USE SIGNAL ;
    ANTENNAGATEAREA 0.631200 ;
    ANTENNADIFFAREA 0.434700 ;
    PORT
      LAYER met3 ;
        RECT 0.000 901.040 4.000 901.640 ;
    END
  END tl_u_spi_host_i[56]
  PIN tl_u_spi_host_i[57]
    DIRECTION INPUT ;
    USE SIGNAL ;
    ANTENNAGATEAREA 0.647700 ;
    ANTENNADIFFAREA 0.434700 ;
    PORT
      LAYER met3 ;
        RECT 1296.000 608.640 1300.000 609.240 ;
    END
  END tl_u_spi_host_i[57]
  PIN tl_u_spi_host_i[58]
    DIRECTION INPUT ;
    USE SIGNAL ;
    ANTENNAGATEAREA 0.647700 ;
    ANTENNADIFFAREA 0.434700 ;
    PORT
      LAYER met3 ;
        RECT 1296.000 914.640 1300.000 915.240 ;
    END
  END tl_u_spi_host_i[58]
  PIN tl_u_spi_host_i[59]
    DIRECTION INPUT ;
    USE SIGNAL ;
    ANTENNAGATEAREA 0.631200 ;
    ANTENNADIFFAREA 0.434700 ;
    PORT
      LAYER met3 ;
        RECT 1296.000 714.040 1300.000 714.640 ;
    END
  END tl_u_spi_host_i[59]
  PIN tl_u_spi_host_i[5]
    DIRECTION INPUT ;
    USE SIGNAL ;
    ANTENNAGATEAREA 0.631200 ;
    ANTENNADIFFAREA 0.434700 ;
    PORT
      LAYER met3 ;
        RECT 1296.000 792.240 1300.000 792.840 ;
    END
  END tl_u_spi_host_i[5]
  PIN tl_u_spi_host_i[60]
    DIRECTION INPUT ;
    USE SIGNAL ;
    ANTENNAGATEAREA 0.631200 ;
    ANTENNADIFFAREA 0.434700 ;
    PORT
      LAYER met3 ;
        RECT 0.000 1006.440 4.000 1007.040 ;
    END
  END tl_u_spi_host_i[60]
  PIN tl_u_spi_host_i[61]
    DIRECTION INPUT ;
    USE SIGNAL ;
    ANTENNAGATEAREA 0.631200 ;
    ANTENNADIFFAREA 0.434700 ;
    PORT
      LAYER met3 ;
        RECT 1296.000 1217.240 1300.000 1217.840 ;
    END
  END tl_u_spi_host_i[61]
  PIN tl_u_spi_host_i[62]
    DIRECTION INPUT ;
    USE SIGNAL ;
    ANTENNAGATEAREA 0.593700 ;
    ANTENNADIFFAREA 0.434700 ;
    PORT
      LAYER met3 ;
        RECT 1296.000 846.640 1300.000 847.240 ;
    END
  END tl_u_spi_host_i[62]
  PIN tl_u_spi_host_i[63]
    DIRECTION INPUT ;
    USE SIGNAL ;
    ANTENNAGATEAREA 0.682200 ;
    ANTENNADIFFAREA 0.434700 ;
    PORT
      LAYER met3 ;
        RECT 0.000 1196.840 4.000 1197.440 ;
    END
  END tl_u_spi_host_i[63]
  PIN tl_u_spi_host_i[64]
    DIRECTION INPUT ;
    USE SIGNAL ;
    ANTENNAGATEAREA 0.560700 ;
    ANTENNADIFFAREA 0.434700 ;
    PORT
      LAYER met3 ;
        RECT 1296.000 826.240 1300.000 826.840 ;
    END
  END tl_u_spi_host_i[64]
  PIN tl_u_spi_host_i[65]
    DIRECTION INPUT ;
    USE SIGNAL ;
    ANTENNAGATEAREA 0.631200 ;
    ANTENNADIFFAREA 0.434700 ;
    PORT
      LAYER met3 ;
        RECT 1296.000 962.240 1300.000 962.840 ;
    END
  END tl_u_spi_host_i[65]
  PIN tl_u_spi_host_i[6]
    DIRECTION INPUT ;
    USE SIGNAL ;
    ANTENNAGATEAREA 0.647700 ;
    ANTENNADIFFAREA 0.434700 ;
    PORT
      LAYER met3 ;
        RECT 1296.000 1220.640 1300.000 1221.240 ;
    END
  END tl_u_spi_host_i[6]
  PIN tl_u_spi_host_i[7]
    DIRECTION INPUT ;
    USE SIGNAL ;
    ANTENNAGATEAREA 0.682200 ;
    ANTENNADIFFAREA 0.434700 ;
    PORT
      LAYER met3 ;
        RECT 0.000 1247.840 4.000 1248.440 ;
    END
  END tl_u_spi_host_i[7]
  PIN tl_u_spi_host_i[8]
    DIRECTION INPUT ;
    USE SIGNAL ;
    ANTENNAGATEAREA 0.682200 ;
    ANTENNADIFFAREA 0.434700 ;
    PORT
      LAYER met3 ;
        RECT 1296.000 642.640 1300.000 643.240 ;
    END
  END tl_u_spi_host_i[8]
  PIN tl_u_spi_host_i[9]
    DIRECTION INPUT ;
    USE SIGNAL ;
    ANTENNAGATEAREA 0.647700 ;
    ANTENNADIFFAREA 0.434700 ;
    PORT
      LAYER met3 ;
        RECT 1296.000 1275.040 1300.000 1275.640 ;
    END
  END tl_u_spi_host_i[9]
  PIN tl_u_spi_host_o[0]
    DIRECTION OUTPUT ;
    USE SIGNAL ;
    ANTENNADIFFAREA 0.445500 ;
    PORT
      LAYER met3 ;
        RECT 0.000 1139.040 4.000 1139.640 ;
    END
  END tl_u_spi_host_o[0]
  PIN tl_u_spi_host_o[100]
    DIRECTION OUTPUT ;
    USE SIGNAL ;
    ANTENNADIFFAREA 0.445500 ;
    PORT
      LAYER met3 ;
        RECT 0.000 918.040 4.000 918.640 ;
    END
  END tl_u_spi_host_o[100]
  PIN tl_u_spi_host_o[101]
    DIRECTION OUTPUT ;
    USE SIGNAL ;
    ANTENNADIFFAREA 0.445500 ;
    PORT
      LAYER met3 ;
        RECT 1296.000 595.040 1300.000 595.640 ;
    END
  END tl_u_spi_host_o[101]
  PIN tl_u_spi_host_o[102]
    DIRECTION OUTPUT ;
    USE SIGNAL ;
    ANTENNADIFFAREA 0.445500 ;
    PORT
      LAYER met3 ;
        RECT 0.000 979.240 4.000 979.840 ;
    END
  END tl_u_spi_host_o[102]
  PIN tl_u_spi_host_o[103]
    DIRECTION OUTPUT ;
    USE SIGNAL ;
    ANTENNADIFFAREA 0.445500 ;
    PORT
      LAYER met3 ;
        RECT 1296.000 306.040 1300.000 306.640 ;
    END
  END tl_u_spi_host_o[103]
  PIN tl_u_spi_host_o[104]
    DIRECTION OUTPUT ;
    USE SIGNAL ;
    ANTENNADIFFAREA 0.445500 ;
    PORT
      LAYER met3 ;
        RECT 1296.000 486.240 1300.000 486.840 ;
    END
  END tl_u_spi_host_o[104]
  PIN tl_u_spi_host_o[105]
    DIRECTION OUTPUT ;
    USE SIGNAL ;
    ANTENNADIFFAREA 0.445500 ;
    PORT
      LAYER met3 ;
        RECT 0.000 622.240 4.000 622.840 ;
    END
  END tl_u_spi_host_o[105]
  PIN tl_u_spi_host_o[106]
    DIRECTION OUTPUT ;
    USE SIGNAL ;
    ANTENNADIFFAREA 0.445500 ;
    PORT
      LAYER met3 ;
        RECT 0.000 608.640 4.000 609.240 ;
    END
  END tl_u_spi_host_o[106]
  PIN tl_u_spi_host_o[107]
    DIRECTION OUTPUT ;
    USE SIGNAL ;
    ANTENNADIFFAREA 0.445500 ;
    PORT
      LAYER met3 ;
        RECT 0.000 788.840 4.000 789.440 ;
    END
  END tl_u_spi_host_o[107]
  PIN tl_u_spi_host_o[108]
    DIRECTION OUTPUT ;
    USE SIGNAL ;
    ANTENNADIFFAREA 0.445500 ;
    PORT
      LAYER met3 ;
        RECT 0.000 136.040 4.000 136.640 ;
    END
  END tl_u_spi_host_o[108]
  PIN tl_u_spi_host_o[109]
    DIRECTION OUTPUT ;
    USE SIGNAL ;
    ANTENNADIFFAREA 0.445500 ;
    PORT
      LAYER met3 ;
        RECT 0.000 486.240 4.000 486.840 ;
    END
  END tl_u_spi_host_o[109]
  PIN tl_u_spi_host_o[10]
    DIRECTION OUTPUT ;
    USE SIGNAL ;
    ANTENNADIFFAREA 0.445500 ;
    PORT
      LAYER met3 ;
        RECT 0.000 346.840 4.000 347.440 ;
    END
  END tl_u_spi_host_o[10]
  PIN tl_u_spi_host_o[11]
    DIRECTION OUTPUT ;
    USE SIGNAL ;
    ANTENNADIFFAREA 0.445500 ;
    PORT
      LAYER met3 ;
        RECT 1296.000 445.440 1300.000 446.040 ;
    END
  END tl_u_spi_host_o[11]
  PIN tl_u_spi_host_o[12]
    DIRECTION OUTPUT ;
    USE SIGNAL ;
    ANTENNADIFFAREA 0.445500 ;
    PORT
      LAYER met3 ;
        RECT 0.000 850.040 4.000 850.640 ;
    END
  END tl_u_spi_host_o[12]
  PIN tl_u_spi_host_o[13]
    DIRECTION OUTPUT ;
    USE SIGNAL ;
    ANTENNADIFFAREA 0.445500 ;
    PORT
      LAYER met3 ;
        RECT 1296.000 989.440 1300.000 990.040 ;
    END
  END tl_u_spi_host_o[13]
  PIN tl_u_spi_host_o[14]
    DIRECTION OUTPUT ;
    USE SIGNAL ;
    ANTENNADIFFAREA 0.445500 ;
    PORT
      LAYER met3 ;
        RECT 0.000 176.840 4.000 177.440 ;
    END
  END tl_u_spi_host_o[14]
  PIN tl_u_spi_host_o[15]
    DIRECTION OUTPUT ;
    USE SIGNAL ;
    ANTENNADIFFAREA 0.445500 ;
    PORT
      LAYER met3 ;
        RECT 0.000 278.840 4.000 279.440 ;
    END
  END tl_u_spi_host_o[15]
  PIN tl_u_spi_host_o[16]
    DIRECTION OUTPUT ;
    USE SIGNAL ;
    ANTENNADIFFAREA 0.445500 ;
    PORT
      LAYER met3 ;
        RECT 1296.000 516.840 1300.000 517.440 ;
    END
  END tl_u_spi_host_o[16]
  PIN tl_u_spi_host_o[17]
    DIRECTION OUTPUT ;
    USE SIGNAL ;
    ANTENNADIFFAREA 0.445500 ;
    PORT
      LAYER met3 ;
        RECT 1296.000 700.440 1300.000 701.040 ;
    END
  END tl_u_spi_host_o[17]
  PIN tl_u_spi_host_o[18]
    DIRECTION OUTPUT ;
    USE SIGNAL ;
    ANTENNADIFFAREA 0.445500 ;
    PORT
      LAYER met3 ;
        RECT 1296.000 1003.040 1300.000 1003.640 ;
    END
  END tl_u_spi_host_o[18]
  PIN tl_u_spi_host_o[19]
    DIRECTION OUTPUT ;
    USE SIGNAL ;
    ANTENNADIFFAREA 0.445500 ;
    PORT
      LAYER met2 ;
        RECT 312.430 1296.000 312.710 1300.000 ;
    END
  END tl_u_spi_host_o[19]
  PIN tl_u_spi_host_o[1]
    DIRECTION OUTPUT ;
    USE SIGNAL ;
    ANTENNADIFFAREA 0.445500 ;
    PORT
      LAYER met2 ;
        RECT 399.370 1296.000 399.650 1300.000 ;
    END
  END tl_u_spi_host_o[1]
  PIN tl_u_spi_host_o[20]
    DIRECTION OUTPUT ;
    USE SIGNAL ;
    ANTENNADIFFAREA 0.445500 ;
    PORT
      LAYER met3 ;
        RECT 0.000 224.440 4.000 225.040 ;
    END
  END tl_u_spi_host_o[20]
  PIN tl_u_spi_host_o[21]
    DIRECTION OUTPUT ;
    USE SIGNAL ;
    ANTENNADIFFAREA 0.445500 ;
    PORT
      LAYER met3 ;
        RECT 1296.000 414.840 1300.000 415.440 ;
    END
  END tl_u_spi_host_o[21]
  PIN tl_u_spi_host_o[22]
    DIRECTION OUTPUT ;
    USE SIGNAL ;
    ANTENNADIFFAREA 0.445500 ;
    PORT
      LAYER met3 ;
        RECT 1296.000 839.840 1300.000 840.440 ;
    END
  END tl_u_spi_host_o[22]
  PIN tl_u_spi_host_o[23]
    DIRECTION OUTPUT ;
    USE SIGNAL ;
    ANTENNADIFFAREA 0.445500 ;
    PORT
      LAYER met3 ;
        RECT 0.000 272.040 4.000 272.640 ;
    END
  END tl_u_spi_host_o[23]
  PIN tl_u_spi_host_o[24]
    DIRECTION OUTPUT ;
    USE SIGNAL ;
    ANTENNADIFFAREA 0.445500 ;
    PORT
      LAYER met2 ;
        RECT 363.950 1296.000 364.230 1300.000 ;
    END
  END tl_u_spi_host_o[24]
  PIN tl_u_spi_host_o[25]
    DIRECTION OUTPUT ;
    USE SIGNAL ;
    ANTENNADIFFAREA 0.445500 ;
    PORT
      LAYER met3 ;
        RECT 0.000 581.440 4.000 582.040 ;
    END
  END tl_u_spi_host_o[25]
  PIN tl_u_spi_host_o[26]
    DIRECTION OUTPUT ;
    USE SIGNAL ;
    ANTENNADIFFAREA 0.445500 ;
    PORT
      LAYER met2 ;
        RECT 450.890 1296.000 451.170 1300.000 ;
    END
  END tl_u_spi_host_o[26]
  PIN tl_u_spi_host_o[27]
    DIRECTION OUTPUT ;
    USE SIGNAL ;
    ANTENNADIFFAREA 0.445500 ;
    PORT
      LAYER met3 ;
        RECT 1296.000 547.440 1300.000 548.040 ;
    END
  END tl_u_spi_host_o[27]
  PIN tl_u_spi_host_o[28]
    DIRECTION OUTPUT ;
    USE SIGNAL ;
    ANTENNADIFFAREA 0.445500 ;
    PORT
      LAYER met3 ;
        RECT 1296.000 323.040 1300.000 323.640 ;
    END
  END tl_u_spi_host_o[28]
  PIN tl_u_spi_host_o[29]
    DIRECTION OUTPUT ;
    USE SIGNAL ;
    ANTENNADIFFAREA 0.445500 ;
    PORT
      LAYER met3 ;
        RECT 0.000 374.040 4.000 374.640 ;
    END
  END tl_u_spi_host_o[29]
  PIN tl_u_spi_host_o[2]
    DIRECTION OUTPUT ;
    USE SIGNAL ;
    ANTENNADIFFAREA 0.445500 ;
    PORT
      LAYER met2 ;
        RECT 444.450 1296.000 444.730 1300.000 ;
    END
  END tl_u_spi_host_o[2]
  PIN tl_u_spi_host_o[30]
    DIRECTION OUTPUT ;
    USE SIGNAL ;
    ANTENNADIFFAREA 0.445500 ;
    PORT
      LAYER met3 ;
        RECT 1296.000 1101.640 1300.000 1102.240 ;
    END
  END tl_u_spi_host_o[30]
  PIN tl_u_spi_host_o[31]
    DIRECTION OUTPUT ;
    USE SIGNAL ;
    ANTENNADIFFAREA 0.445500 ;
    PORT
      LAYER met3 ;
        RECT 1296.000 455.640 1300.000 456.240 ;
    END
  END tl_u_spi_host_o[31]
  PIN tl_u_spi_host_o[32]
    DIRECTION OUTPUT ;
    USE SIGNAL ;
    ANTENNADIFFAREA 0.445500 ;
    PORT
      LAYER met3 ;
        RECT 1296.000 527.040 1300.000 527.640 ;
    END
  END tl_u_spi_host_o[32]
  PIN tl_u_spi_host_o[33]
    DIRECTION OUTPUT ;
    USE SIGNAL ;
    ANTENNADIFFAREA 0.445500 ;
    PORT
      LAYER met3 ;
        RECT 0.000 503.240 4.000 503.840 ;
    END
  END tl_u_spi_host_o[33]
  PIN tl_u_spi_host_o[34]
    DIRECTION OUTPUT ;
    USE SIGNAL ;
    ANTENNADIFFAREA 0.445500 ;
    PORT
      LAYER met2 ;
        RECT 412.250 1296.000 412.530 1300.000 ;
    END
  END tl_u_spi_host_o[34]
  PIN tl_u_spi_host_o[35]
    DIRECTION OUTPUT ;
    USE SIGNAL ;
    ANTENNADIFFAREA 0.445500 ;
    PORT
      LAYER met3 ;
        RECT 1296.000 513.440 1300.000 514.040 ;
    END
  END tl_u_spi_host_o[35]
  PIN tl_u_spi_host_o[36]
    DIRECTION OUTPUT ;
    USE SIGNAL ;
    ANTENNADIFFAREA 0.445500 ;
    PORT
      LAYER met2 ;
        RECT 322.090 1296.000 322.370 1300.000 ;
    END
  END tl_u_spi_host_o[36]
  PIN tl_u_spi_host_o[37]
    DIRECTION OUTPUT ;
    USE SIGNAL ;
    ANTENNADIFFAREA 0.445500 ;
    PORT
      LAYER met3 ;
        RECT 1296.000 374.040 1300.000 374.640 ;
    END
  END tl_u_spi_host_o[37]
  PIN tl_u_spi_host_o[38]
    DIRECTION OUTPUT ;
    USE SIGNAL ;
    ANTENNADIFFAREA 0.445500 ;
    PORT
      LAYER met3 ;
        RECT 0.000 584.840 4.000 585.440 ;
    END
  END tl_u_spi_host_o[38]
  PIN tl_u_spi_host_o[39]
    DIRECTION OUTPUT ;
    USE SIGNAL ;
    ANTENNADIFFAREA 0.445500 ;
    PORT
      LAYER met3 ;
        RECT 1296.000 574.640 1300.000 575.240 ;
    END
  END tl_u_spi_host_o[39]
  PIN tl_u_spi_host_o[3]
    DIRECTION OUTPUT ;
    USE SIGNAL ;
    ANTENNADIFFAREA 0.445500 ;
    PORT
      LAYER met3 ;
        RECT 1296.000 523.640 1300.000 524.240 ;
    END
  END tl_u_spi_host_o[3]
  PIN tl_u_spi_host_o[40]
    DIRECTION OUTPUT ;
    USE SIGNAL ;
    ANTENNADIFFAREA 0.445500 ;
    PORT
      LAYER met2 ;
        RECT 357.510 1296.000 357.790 1300.000 ;
    END
  END tl_u_spi_host_o[40]
  PIN tl_u_spi_host_o[41]
    DIRECTION OUTPUT ;
    USE SIGNAL ;
    ANTENNADIFFAREA 0.445500 ;
    PORT
      LAYER met3 ;
        RECT 1296.000 479.440 1300.000 480.040 ;
    END
  END tl_u_spi_host_o[41]
  PIN tl_u_spi_host_o[42]
    DIRECTION OUTPUT ;
    USE SIGNAL ;
    ANTENNADIFFAREA 0.445500 ;
    PORT
      LAYER met3 ;
        RECT 1296.000 612.040 1300.000 612.640 ;
    END
  END tl_u_spi_host_o[42]
  PIN tl_u_spi_host_o[43]
    DIRECTION OUTPUT ;
    USE SIGNAL ;
    ANTENNADIFFAREA 0.445500 ;
    PORT
      LAYER met2 ;
        RECT 428.350 1296.000 428.630 1300.000 ;
    END
  END tl_u_spi_host_o[43]
  PIN tl_u_spi_host_o[44]
    DIRECTION OUTPUT ;
    USE SIGNAL ;
    ANTENNADIFFAREA 0.445500 ;
    PORT
      LAYER met2 ;
        RECT 557.150 1296.000 557.430 1300.000 ;
    END
  END tl_u_spi_host_o[44]
  PIN tl_u_spi_host_o[45]
    DIRECTION OUTPUT ;
    USE SIGNAL ;
    ANTENNADIFFAREA 0.445500 ;
    PORT
      LAYER met3 ;
        RECT 1296.000 564.440 1300.000 565.040 ;
    END
  END tl_u_spi_host_o[45]
  PIN tl_u_spi_host_o[46]
    DIRECTION OUTPUT ;
    USE SIGNAL ;
    ANTENNADIFFAREA 0.445500 ;
    PORT
      LAYER met3 ;
        RECT 1296.000 836.440 1300.000 837.040 ;
    END
  END tl_u_spi_host_o[46]
  PIN tl_u_spi_host_o[47]
    DIRECTION OUTPUT ;
    USE SIGNAL ;
    ANTENNADIFFAREA 0.445500 ;
    PORT
      LAYER met2 ;
        RECT 354.290 1296.000 354.570 1300.000 ;
    END
  END tl_u_spi_host_o[47]
  PIN tl_u_spi_host_o[48]
    DIRECTION OUTPUT ;
    USE SIGNAL ;
    ANTENNADIFFAREA 0.445500 ;
    PORT
      LAYER met2 ;
        RECT 602.230 1296.000 602.510 1300.000 ;
    END
  END tl_u_spi_host_o[48]
  PIN tl_u_spi_host_o[49]
    DIRECTION OUTPUT ;
    USE SIGNAL ;
    ANTENNADIFFAREA 0.445500 ;
    PORT
      LAYER met2 ;
        RECT 396.150 1296.000 396.430 1300.000 ;
    END
  END tl_u_spi_host_o[49]
  PIN tl_u_spi_host_o[4]
    DIRECTION OUTPUT ;
    USE SIGNAL ;
    ANTENNADIFFAREA 0.445500 ;
    PORT
      LAYER met3 ;
        RECT 1296.000 533.840 1300.000 534.440 ;
    END
  END tl_u_spi_host_o[4]
  PIN tl_u_spi_host_o[50]
    DIRECTION OUTPUT ;
    USE SIGNAL ;
    ANTENNADIFFAREA 0.445500 ;
    PORT
      LAYER met3 ;
        RECT 1296.000 601.840 1300.000 602.440 ;
    END
  END tl_u_spi_host_o[50]
  PIN tl_u_spi_host_o[51]
    DIRECTION OUTPUT ;
    USE SIGNAL ;
    ANTENNADIFFAREA 0.445500 ;
    PORT
      LAYER met2 ;
        RECT 351.070 1296.000 351.350 1300.000 ;
    END
  END tl_u_spi_host_o[51]
  PIN tl_u_spi_host_o[52]
    DIRECTION OUTPUT ;
    USE SIGNAL ;
    ANTENNADIFFAREA 0.445500 ;
    PORT
      LAYER met3 ;
        RECT 1296.000 221.040 1300.000 221.640 ;
    END
  END tl_u_spi_host_o[52]
  PIN tl_u_spi_host_o[53]
    DIRECTION OUTPUT ;
    USE SIGNAL ;
    ANTENNADIFFAREA 0.445500 ;
    PORT
      LAYER met3 ;
        RECT 1296.000 442.040 1300.000 442.640 ;
    END
  END tl_u_spi_host_o[53]
  PIN tl_u_spi_host_o[54]
    DIRECTION OUTPUT ;
    USE SIGNAL ;
    ANTENNADIFFAREA 0.445500 ;
    PORT
      LAYER met2 ;
        RECT 592.570 1296.000 592.850 1300.000 ;
    END
  END tl_u_spi_host_o[54]
  PIN tl_u_spi_host_o[55]
    DIRECTION OUTPUT ;
    USE SIGNAL ;
    ANTENNADIFFAREA 0.445500 ;
    PORT
      LAYER met2 ;
        RECT 579.690 1296.000 579.970 1300.000 ;
    END
  END tl_u_spi_host_o[55]
  PIN tl_u_spi_host_o[56]
    DIRECTION OUTPUT ;
    USE SIGNAL ;
    ANTENNADIFFAREA 0.445500 ;
    PORT
      LAYER met2 ;
        RECT 553.930 1296.000 554.210 1300.000 ;
    END
  END tl_u_spi_host_o[56]
  PIN tl_u_spi_host_o[57]
    DIRECTION OUTPUT ;
    USE SIGNAL ;
    ANTENNADIFFAREA 0.445500 ;
    PORT
      LAYER met2 ;
        RECT 370.390 1296.000 370.670 1300.000 ;
    END
  END tl_u_spi_host_o[57]
  PIN tl_u_spi_host_o[58]
    DIRECTION OUTPUT ;
    USE SIGNAL ;
    ANTENNADIFFAREA 0.445500 ;
    PORT
      LAYER met3 ;
        RECT 1296.000 751.440 1300.000 752.040 ;
    END
  END tl_u_spi_host_o[58]
  PIN tl_u_spi_host_o[59]
    DIRECTION OUTPUT ;
    USE SIGNAL ;
    ANTENNADIFFAREA 0.445500 ;
    PORT
      LAYER met3 ;
        RECT 1296.000 499.840 1300.000 500.440 ;
    END
  END tl_u_spi_host_o[59]
  PIN tl_u_spi_host_o[5]
    DIRECTION OUTPUT ;
    USE SIGNAL ;
    ANTENNADIFFAREA 0.445500 ;
    PORT
      LAYER met2 ;
        RECT 518.510 1296.000 518.790 1300.000 ;
    END
  END tl_u_spi_host_o[5]
  PIN tl_u_spi_host_o[60]
    DIRECTION OUTPUT ;
    USE SIGNAL ;
    ANTENNADIFFAREA 0.445500 ;
    PORT
      LAYER met3 ;
        RECT 1296.000 1159.440 1300.000 1160.040 ;
    END
  END tl_u_spi_host_o[60]
  PIN tl_u_spi_host_o[61]
    DIRECTION OUTPUT ;
    USE SIGNAL ;
    ANTENNADIFFAREA 0.445500 ;
    PORT
      LAYER met3 ;
        RECT 0.000 61.240 4.000 61.840 ;
    END
  END tl_u_spi_host_o[61]
  PIN tl_u_spi_host_o[62]
    DIRECTION OUTPUT ;
    USE SIGNAL ;
    ANTENNADIFFAREA 0.445500 ;
    PORT
      LAYER met3 ;
        RECT 0.000 268.640 4.000 269.240 ;
    END
  END tl_u_spi_host_o[62]
  PIN tl_u_spi_host_o[63]
    DIRECTION OUTPUT ;
    USE SIGNAL ;
    ANTENNADIFFAREA 0.445500 ;
    PORT
      LAYER met3 ;
        RECT 0.000 125.840 4.000 126.440 ;
    END
  END tl_u_spi_host_o[63]
  PIN tl_u_spi_host_o[64]
    DIRECTION OUTPUT ;
    USE SIGNAL ;
    ANTENNADIFFAREA 0.445500 ;
    PORT
      LAYER met3 ;
        RECT 0.000 397.840 4.000 398.440 ;
    END
  END tl_u_spi_host_o[64]
  PIN tl_u_spi_host_o[65]
    DIRECTION OUTPUT ;
    USE SIGNAL ;
    ANTENNADIFFAREA 0.445500 ;
    PORT
      LAYER met3 ;
        RECT 0.000 442.040 4.000 442.640 ;
    END
  END tl_u_spi_host_o[65]
  PIN tl_u_spi_host_o[66]
    DIRECTION OUTPUT ;
    USE SIGNAL ;
    ANTENNADIFFAREA 0.445500 ;
    PORT
      LAYER met3 ;
        RECT 0.000 81.640 4.000 82.240 ;
    END
  END tl_u_spi_host_o[66]
  PIN tl_u_spi_host_o[67]
    DIRECTION OUTPUT ;
    USE SIGNAL ;
    ANTENNADIFFAREA 0.445500 ;
    PORT
      LAYER met3 ;
        RECT 0.000 88.440 4.000 89.040 ;
    END
  END tl_u_spi_host_o[67]
  PIN tl_u_spi_host_o[68]
    DIRECTION OUTPUT ;
    USE SIGNAL ;
    ANTENNADIFFAREA 0.445500 ;
    PORT
      LAYER met3 ;
        RECT 0.000 200.640 4.000 201.240 ;
    END
  END tl_u_spi_host_o[68]
  PIN tl_u_spi_host_o[69]
    DIRECTION OUTPUT ;
    USE SIGNAL ;
    ANTENNADIFFAREA 0.445500 ;
    PORT
      LAYER met3 ;
        RECT 0.000 343.440 4.000 344.040 ;
    END
  END tl_u_spi_host_o[69]
  PIN tl_u_spi_host_o[6]
    DIRECTION OUTPUT ;
    USE SIGNAL ;
    ANTENNADIFFAREA 0.445500 ;
    PORT
      LAYER met2 ;
        RECT 499.190 1296.000 499.470 1300.000 ;
    END
  END tl_u_spi_host_o[6]
  PIN tl_u_spi_host_o[70]
    DIRECTION OUTPUT ;
    USE SIGNAL ;
    ANTENNADIFFAREA 0.445500 ;
    PORT
      LAYER met3 ;
        RECT 0.000 367.240 4.000 367.840 ;
    END
  END tl_u_spi_host_o[70]
  PIN tl_u_spi_host_o[71]
    DIRECTION OUTPUT ;
    USE SIGNAL ;
    ANTENNADIFFAREA 0.445500 ;
    PORT
      LAYER met3 ;
        RECT 0.000 425.040 4.000 425.640 ;
    END
  END tl_u_spi_host_o[71]
  PIN tl_u_spi_host_o[72]
    DIRECTION OUTPUT ;
    USE SIGNAL ;
    ANTENNADIFFAREA 0.445500 ;
    PORT
      LAYER met3 ;
        RECT 0.000 455.640 4.000 456.240 ;
    END
  END tl_u_spi_host_o[72]
  PIN tl_u_spi_host_o[73]
    DIRECTION OUTPUT ;
    USE SIGNAL ;
    ANTENNADIFFAREA 0.445500 ;
    PORT
      LAYER met3 ;
        RECT 0.000 499.840 4.000 500.440 ;
    END
  END tl_u_spi_host_o[73]
  PIN tl_u_spi_host_o[74]
    DIRECTION OUTPUT ;
    USE SIGNAL ;
    ANTENNADIFFAREA 0.445500 ;
    PORT
      LAYER met3 ;
        RECT 0.000 231.240 4.000 231.840 ;
    END
  END tl_u_spi_host_o[74]
  PIN tl_u_spi_host_o[75]
    DIRECTION OUTPUT ;
    USE SIGNAL ;
    ANTENNADIFFAREA 0.445500 ;
    PORT
      LAYER met3 ;
        RECT 0.000 312.840 4.000 313.440 ;
    END
  END tl_u_spi_host_o[75]
  PIN tl_u_spi_host_o[76]
    DIRECTION OUTPUT ;
    USE SIGNAL ;
    ANTENNADIFFAREA 0.445500 ;
    PORT
      LAYER met3 ;
        RECT 0.000 479.440 4.000 480.040 ;
    END
  END tl_u_spi_host_o[76]
  PIN tl_u_spi_host_o[77]
    DIRECTION OUTPUT ;
    USE SIGNAL ;
    ANTENNADIFFAREA 0.445500 ;
    PORT
      LAYER met3 ;
        RECT 0.000 605.240 4.000 605.840 ;
    END
  END tl_u_spi_host_o[77]
  PIN tl_u_spi_host_o[78]
    DIRECTION OUTPUT ;
    USE SIGNAL ;
    ANTENNADIFFAREA 0.445500 ;
    PORT
      LAYER met3 ;
        RECT 0.000 122.440 4.000 123.040 ;
    END
  END tl_u_spi_host_o[78]
  PIN tl_u_spi_host_o[79]
    DIRECTION OUTPUT ;
    USE SIGNAL ;
    ANTENNADIFFAREA 0.445500 ;
    PORT
      LAYER met3 ;
        RECT 0.000 601.840 4.000 602.440 ;
    END
  END tl_u_spi_host_o[79]
  PIN tl_u_spi_host_o[7]
    DIRECTION OUTPUT ;
    USE SIGNAL ;
    ANTENNADIFFAREA 0.445500 ;
    PORT
      LAYER met3 ;
        RECT 1296.000 493.040 1300.000 493.640 ;
    END
  END tl_u_spi_host_o[7]
  PIN tl_u_spi_host_o[80]
    DIRECTION OUTPUT ;
    USE SIGNAL ;
    ANTENNADIFFAREA 0.445500 ;
    PORT
      LAYER met3 ;
        RECT 0.000 462.440 4.000 463.040 ;
    END
  END tl_u_spi_host_o[80]
  PIN tl_u_spi_host_o[81]
    DIRECTION OUTPUT ;
    USE SIGNAL ;
    ANTENNADIFFAREA 0.445500 ;
    PORT
      LAYER met3 ;
        RECT 0.000 142.840 4.000 143.440 ;
    END
  END tl_u_spi_host_o[81]
  PIN tl_u_spi_host_o[82]
    DIRECTION OUTPUT ;
    USE SIGNAL ;
    ANTENNADIFFAREA 0.445500 ;
    PORT
      LAYER met3 ;
        RECT 0.000 527.040 4.000 527.640 ;
    END
  END tl_u_spi_host_o[82]
  PIN tl_u_spi_host_o[83]
    DIRECTION OUTPUT ;
    USE SIGNAL ;
    ANTENNADIFFAREA 0.445500 ;
    PORT
      LAYER met3 ;
        RECT 0.000 574.640 4.000 575.240 ;
    END
  END tl_u_spi_host_o[83]
  PIN tl_u_spi_host_o[84]
    DIRECTION OUTPUT ;
    USE SIGNAL ;
    ANTENNADIFFAREA 0.445500 ;
    PORT
      LAYER met3 ;
        RECT 0.000 173.440 4.000 174.040 ;
    END
  END tl_u_spi_host_o[84]
  PIN tl_u_spi_host_o[85]
    DIRECTION OUTPUT ;
    USE SIGNAL ;
    ANTENNADIFFAREA 0.445500 ;
    PORT
      LAYER met3 ;
        RECT 0.000 27.240 4.000 27.840 ;
    END
  END tl_u_spi_host_o[85]
  PIN tl_u_spi_host_o[86]
    DIRECTION OUTPUT ;
    USE SIGNAL ;
    ANTENNADIFFAREA 0.445500 ;
    PORT
      LAYER met3 ;
        RECT 0.000 34.040 4.000 34.640 ;
    END
  END tl_u_spi_host_o[86]
  PIN tl_u_spi_host_o[87]
    DIRECTION OUTPUT ;
    USE SIGNAL ;
    ANTENNADIFFAREA 0.445500 ;
    PORT
      LAYER met3 ;
        RECT 0.000 204.040 4.000 204.640 ;
    END
  END tl_u_spi_host_o[87]
  PIN tl_u_spi_host_o[88]
    DIRECTION OUTPUT ;
    USE SIGNAL ;
    ANTENNADIFFAREA 0.445500 ;
    PORT
      LAYER met3 ;
        RECT 0.000 476.040 4.000 476.640 ;
    END
  END tl_u_spi_host_o[88]
  PIN tl_u_spi_host_o[89]
    DIRECTION OUTPUT ;
    USE SIGNAL ;
    ANTENNADIFFAREA 0.445500 ;
    PORT
      LAYER met3 ;
        RECT 0.000 44.240 4.000 44.840 ;
    END
  END tl_u_spi_host_o[89]
  PIN tl_u_spi_host_o[8]
    DIRECTION OUTPUT ;
    USE SIGNAL ;
    ANTENNADIFFAREA 0.445500 ;
    PORT
      LAYER met3 ;
        RECT 1296.000 850.040 1300.000 850.640 ;
    END
  END tl_u_spi_host_o[8]
  PIN tl_u_spi_host_o[90]
    DIRECTION OUTPUT ;
    USE SIGNAL ;
    ANTENNADIFFAREA 0.445500 ;
    PORT
      LAYER met3 ;
        RECT 0.000 71.440 4.000 72.040 ;
    END
  END tl_u_spi_host_o[90]
  PIN tl_u_spi_host_o[91]
    DIRECTION OUTPUT ;
    USE SIGNAL ;
    ANTENNADIFFAREA 0.445500 ;
    PORT
      LAYER met3 ;
        RECT 0.000 309.440 4.000 310.040 ;
    END
  END tl_u_spi_host_o[91]
  PIN tl_u_spi_host_o[92]
    DIRECTION OUTPUT ;
    USE SIGNAL ;
    ANTENNADIFFAREA 0.445500 ;
    PORT
      LAYER met3 ;
        RECT 0.000 438.640 4.000 439.240 ;
    END
  END tl_u_spi_host_o[92]
  PIN tl_u_spi_host_o[93]
    DIRECTION OUTPUT ;
    USE SIGNAL ;
    ANTENNADIFFAREA 0.445500 ;
    PORT
      LAYER met3 ;
        RECT 1296.000 207.440 1300.000 208.040 ;
    END
  END tl_u_spi_host_o[93]
  PIN tl_u_spi_host_o[94]
    DIRECTION OUTPUT ;
    USE SIGNAL ;
    ANTENNADIFFAREA 0.445500 ;
    PORT
      LAYER met3 ;
        RECT 1296.000 605.240 1300.000 605.840 ;
    END
  END tl_u_spi_host_o[94]
  PIN tl_u_spi_host_o[95]
    DIRECTION OUTPUT ;
    USE SIGNAL ;
    ANTENNADIFFAREA 0.445500 ;
    PORT
      LAYER met3 ;
        RECT 1296.000 928.240 1300.000 928.840 ;
    END
  END tl_u_spi_host_o[95]
  PIN tl_u_spi_host_o[96]
    DIRECTION OUTPUT ;
    USE SIGNAL ;
    ANTENNADIFFAREA 0.445500 ;
    PORT
      LAYER met2 ;
        RECT 470.210 1296.000 470.490 1300.000 ;
    END
  END tl_u_spi_host_o[96]
  PIN tl_u_spi_host_o[97]
    DIRECTION OUTPUT ;
    USE SIGNAL ;
    ANTENNADIFFAREA 0.445500 ;
    PORT
      LAYER met3 ;
        RECT 1296.000 1224.040 1300.000 1224.640 ;
    END
  END tl_u_spi_host_o[97]
  PIN tl_u_spi_host_o[98]
    DIRECTION OUTPUT ;
    USE SIGNAL ;
    ANTENNADIFFAREA 0.445500 ;
    PORT
      LAYER met3 ;
        RECT 0.000 414.840 4.000 415.440 ;
    END
  END tl_u_spi_host_o[98]
  PIN tl_u_spi_host_o[99]
    DIRECTION OUTPUT ;
    USE SIGNAL ;
    ANTENNADIFFAREA 0.445500 ;
    PORT
      LAYER met2 ;
        RECT 560.370 1296.000 560.650 1300.000 ;
    END
  END tl_u_spi_host_o[99]
  PIN tl_u_spi_host_o[9]
    DIRECTION OUTPUT ;
    USE SIGNAL ;
    ANTENNADIFFAREA 0.445500 ;
    PORT
      LAYER met3 ;
        RECT 1296.000 918.040 1300.000 918.640 ;
    END
  END tl_u_spi_host_o[9]
  PIN tl_u_uart_i[0]
    DIRECTION INPUT ;
    USE SIGNAL ;
    ANTENNAGATEAREA 0.647700 ;
    ANTENNADIFFAREA 0.434700 ;
    PORT
      LAYER met3 ;
        RECT 0.000 57.840 4.000 58.440 ;
    END
  END tl_u_uart_i[0]
  PIN tl_u_uart_i[10]
    DIRECTION INPUT ;
    USE SIGNAL ;
    ANTENNAGATEAREA 0.860700 ;
    ANTENNADIFFAREA 0.434700 ;
    PORT
      LAYER met2 ;
        RECT 586.130 1296.000 586.410 1300.000 ;
    END
  END tl_u_uart_i[10]
  PIN tl_u_uart_i[11]
    DIRECTION INPUT ;
    USE SIGNAL ;
    ANTENNAGATEAREA 0.647700 ;
    ANTENNADIFFAREA 0.434700 ;
    PORT
      LAYER met3 ;
        RECT 1296.000 340.040 1300.000 340.640 ;
    END
  END tl_u_uart_i[11]
  PIN tl_u_uart_i[12]
    DIRECTION INPUT ;
    USE SIGNAL ;
    ANTENNAGATEAREA 0.647700 ;
    ANTENNADIFFAREA 0.434700 ;
    PORT
      LAYER met3 ;
        RECT 1296.000 955.440 1300.000 956.040 ;
    END
  END tl_u_uart_i[12]
  PIN tl_u_uart_i[13]
    DIRECTION INPUT ;
    USE SIGNAL ;
    ANTENNAGATEAREA 0.631200 ;
    ANTENNADIFFAREA 0.434700 ;
    PORT
      LAYER met3 ;
        RECT 1296.000 353.640 1300.000 354.240 ;
    END
  END tl_u_uart_i[13]
  PIN tl_u_uart_i[14]
    DIRECTION INPUT ;
    USE SIGNAL ;
    ANTENNAGATEAREA 0.682200 ;
    ANTENNADIFFAREA 0.434700 ;
    PORT
      LAYER met2 ;
        RECT 627.990 1296.000 628.270 1300.000 ;
    END
  END tl_u_uart_i[14]
  PIN tl_u_uart_i[15]
    DIRECTION INPUT ;
    USE SIGNAL ;
    ANTENNAGATEAREA 0.631200 ;
    ANTENNADIFFAREA 0.434700 ;
    PORT
      LAYER met3 ;
        RECT 1296.000 401.240 1300.000 401.840 ;
    END
  END tl_u_uart_i[15]
  PIN tl_u_uart_i[16]
    DIRECTION INPUT ;
    USE SIGNAL ;
    ANTENNAGATEAREA 0.631200 ;
    ANTENNADIFFAREA 0.434700 ;
    PORT
      LAYER met3 ;
        RECT 1296.000 979.240 1300.000 979.840 ;
    END
  END tl_u_uart_i[16]
  PIN tl_u_uart_i[17]
    DIRECTION INPUT ;
    USE SIGNAL ;
    ANTENNAGATEAREA 0.647700 ;
    ANTENNADIFFAREA 0.434700 ;
    PORT
      LAYER met3 ;
        RECT 1296.000 924.840 1300.000 925.440 ;
    END
  END tl_u_uart_i[17]
  PIN tl_u_uart_i[18]
    DIRECTION INPUT ;
    USE SIGNAL ;
    ANTENNAGATEAREA 0.631200 ;
    ANTENNADIFFAREA 0.434700 ;
    PORT
      LAYER met3 ;
        RECT 1296.000 370.640 1300.000 371.240 ;
    END
  END tl_u_uart_i[18]
  PIN tl_u_uart_i[19]
    DIRECTION INPUT ;
    USE SIGNAL ;
    ANTENNAGATEAREA 0.593700 ;
    ANTENNADIFFAREA 0.434700 ;
    PORT
      LAYER met3 ;
        RECT 1296.000 734.440 1300.000 735.040 ;
    END
  END tl_u_uart_i[19]
  PIN tl_u_uart_i[1]
    DIRECTION INPUT ;
    USE SIGNAL ;
    ANTENNAGATEAREA 0.647700 ;
    ANTENNADIFFAREA 0.434700 ;
    PORT
      LAYER met3 ;
        RECT 1296.000 1281.840 1300.000 1282.440 ;
    END
  END tl_u_uart_i[1]
  PIN tl_u_uart_i[20]
    DIRECTION INPUT ;
    USE SIGNAL ;
    ANTENNAGATEAREA 0.593700 ;
    ANTENNADIFFAREA 0.434700 ;
    PORT
      LAYER met3 ;
        RECT 1296.000 387.640 1300.000 388.240 ;
    END
  END tl_u_uart_i[20]
  PIN tl_u_uart_i[21]
    DIRECTION INPUT ;
    USE SIGNAL ;
    ANTENNAGATEAREA 0.647700 ;
    ANTENNADIFFAREA 0.434700 ;
    PORT
      LAYER met3 ;
        RECT 1296.000 367.240 1300.000 367.840 ;
    END
  END tl_u_uart_i[21]
  PIN tl_u_uart_i[22]
    DIRECTION INPUT ;
    USE SIGNAL ;
    ANTENNAGATEAREA 0.647700 ;
    ANTENNADIFFAREA 0.434700 ;
    PORT
      LAYER met2 ;
        RECT 573.250 1296.000 573.530 1300.000 ;
    END
  END tl_u_uart_i[22]
  PIN tl_u_uart_i[23]
    DIRECTION INPUT ;
    USE SIGNAL ;
    ANTENNAGATEAREA 0.593700 ;
    ANTENNADIFFAREA 0.434700 ;
    PORT
      LAYER met3 ;
        RECT 1296.000 1261.440 1300.000 1262.040 ;
    END
  END tl_u_uart_i[23]
  PIN tl_u_uart_i[24]
    DIRECTION INPUT ;
    USE SIGNAL ;
    ANTENNAGATEAREA 0.647700 ;
    ANTENNADIFFAREA 0.434700 ;
    PORT
      LAYER met3 ;
        RECT 1296.000 754.840 1300.000 755.440 ;
    END
  END tl_u_uart_i[24]
  PIN tl_u_uart_i[25]
    DIRECTION INPUT ;
    USE SIGNAL ;
    ANTENNAGATEAREA 0.647700 ;
    ANTENNADIFFAREA 0.434700 ;
    PORT
      LAYER met3 ;
        RECT 1296.000 724.240 1300.000 724.840 ;
    END
  END tl_u_uart_i[25]
  PIN tl_u_uart_i[26]
    DIRECTION INPUT ;
    USE SIGNAL ;
    ANTENNAGATEAREA 0.647700 ;
    ANTENNADIFFAREA 0.434700 ;
    PORT
      LAYER met3 ;
        RECT 1296.000 982.640 1300.000 983.240 ;
    END
  END tl_u_uart_i[26]
  PIN tl_u_uart_i[27]
    DIRECTION INPUT ;
    USE SIGNAL ;
    ANTENNAGATEAREA 0.631200 ;
    ANTENNADIFFAREA 0.434700 ;
    PORT
      LAYER met3 ;
        RECT 1296.000 346.840 1300.000 347.440 ;
    END
  END tl_u_uart_i[27]
  PIN tl_u_uart_i[28]
    DIRECTION INPUT ;
    USE SIGNAL ;
    ANTENNAGATEAREA 0.647700 ;
    ANTENNADIFFAREA 0.434700 ;
    PORT
      LAYER met3 ;
        RECT 1296.000 261.840 1300.000 262.440 ;
    END
  END tl_u_uart_i[28]
  PIN tl_u_uart_i[29]
    DIRECTION INPUT ;
    USE SIGNAL ;
    ANTENNAGATEAREA 0.647700 ;
    ANTENNADIFFAREA 0.434700 ;
    PORT
      LAYER met3 ;
        RECT 1296.000 1227.440 1300.000 1228.040 ;
    END
  END tl_u_uart_i[29]
  PIN tl_u_uart_i[2]
    DIRECTION INPUT ;
    USE SIGNAL ;
    ANTENNAGATEAREA 0.647700 ;
    ANTENNADIFFAREA 0.434700 ;
    PORT
      LAYER met3 ;
        RECT 1296.000 1060.840 1300.000 1061.440 ;
    END
  END tl_u_uart_i[2]
  PIN tl_u_uart_i[30]
    DIRECTION INPUT ;
    USE SIGNAL ;
    ANTENNAGATEAREA 0.647700 ;
    ANTENNADIFFAREA 0.434700 ;
    PORT
      LAYER met3 ;
        RECT 1296.000 285.640 1300.000 286.240 ;
    END
  END tl_u_uart_i[30]
  PIN tl_u_uart_i[31]
    DIRECTION INPUT ;
    USE SIGNAL ;
    ANTENNAGATEAREA 0.647700 ;
    ANTENNADIFFAREA 0.434700 ;
    PORT
      LAYER met2 ;
        RECT 515.290 1296.000 515.570 1300.000 ;
    END
  END tl_u_uart_i[31]
  PIN tl_u_uart_i[32]
    DIRECTION INPUT ;
    USE SIGNAL ;
    ANTENNAGATEAREA 0.593700 ;
    ANTENNADIFFAREA 0.434700 ;
    PORT
      LAYER met3 ;
        RECT 1296.000 629.040 1300.000 629.640 ;
    END
  END tl_u_uart_i[32]
  PIN tl_u_uart_i[33]
    DIRECTION INPUT ;
    USE SIGNAL ;
    ANTENNAGATEAREA 0.647700 ;
    ANTENNADIFFAREA 0.434700 ;
    PORT
      LAYER met3 ;
        RECT 1296.000 663.040 1300.000 663.640 ;
    END
  END tl_u_uart_i[33]
  PIN tl_u_uart_i[34]
    DIRECTION INPUT ;
    USE SIGNAL ;
    ANTENNAGATEAREA 0.631200 ;
    ANTENNADIFFAREA 0.434700 ;
    PORT
      LAYER met3 ;
        RECT 1296.000 656.240 1300.000 656.840 ;
    END
  END tl_u_uart_i[34]
  PIN tl_u_uart_i[35]
    DIRECTION INPUT ;
    USE SIGNAL ;
    ANTENNAGATEAREA 0.647700 ;
    ANTENNADIFFAREA 0.434700 ;
    PORT
      LAYER met3 ;
        RECT 1296.000 1139.040 1300.000 1139.640 ;
    END
  END tl_u_uart_i[35]
  PIN tl_u_uart_i[36]
    DIRECTION INPUT ;
    USE SIGNAL ;
    ANTENNAGATEAREA 0.560700 ;
    ANTENNADIFFAREA 0.434700 ;
    PORT
      LAYER met3 ;
        RECT 1296.000 1105.040 1300.000 1105.640 ;
    END
  END tl_u_uart_i[36]
  PIN tl_u_uart_i[37]
    DIRECTION INPUT ;
    USE SIGNAL ;
    ANTENNAGATEAREA 0.682200 ;
    ANTENNADIFFAREA 0.434700 ;
    PORT
      LAYER met3 ;
        RECT 1296.000 649.440 1300.000 650.040 ;
    END
  END tl_u_uart_i[37]
  PIN tl_u_uart_i[38]
    DIRECTION INPUT ;
    USE SIGNAL ;
    ANTENNAGATEAREA 0.682200 ;
    ANTENNADIFFAREA 0.434700 ;
    PORT
      LAYER met2 ;
        RECT 615.110 1296.000 615.390 1300.000 ;
    END
  END tl_u_uart_i[38]
  PIN tl_u_uart_i[39]
    DIRECTION INPUT ;
    USE SIGNAL ;
    ANTENNAGATEAREA 0.560700 ;
    ANTENNADIFFAREA 0.434700 ;
    PORT
      LAYER met3 ;
        RECT 1296.000 258.440 1300.000 259.040 ;
    END
  END tl_u_uart_i[39]
  PIN tl_u_uart_i[3]
    DIRECTION INPUT ;
    USE SIGNAL ;
    ANTENNAGATEAREA 0.631200 ;
    ANTENNADIFFAREA 0.434700 ;
    PORT
      LAYER met3 ;
        RECT 1296.000 1156.040 1300.000 1156.640 ;
    END
  END tl_u_uart_i[3]
  PIN tl_u_uart_i[40]
    DIRECTION INPUT ;
    USE SIGNAL ;
    ANTENNAGATEAREA 0.647700 ;
    ANTENNADIFFAREA 0.434700 ;
    PORT
      LAYER met3 ;
        RECT 1296.000 1071.040 1300.000 1071.640 ;
    END
  END tl_u_uart_i[40]
  PIN tl_u_uart_i[41]
    DIRECTION INPUT ;
    USE SIGNAL ;
    ANTENNAGATEAREA 0.560700 ;
    ANTENNADIFFAREA 0.434700 ;
    PORT
      LAYER met3 ;
        RECT 1296.000 1230.840 1300.000 1231.440 ;
    END
  END tl_u_uart_i[41]
  PIN tl_u_uart_i[42]
    DIRECTION INPUT ;
    USE SIGNAL ;
    ANTENNAGATEAREA 0.631200 ;
    ANTENNADIFFAREA 0.434700 ;
    PORT
      LAYER met3 ;
        RECT 1296.000 768.440 1300.000 769.040 ;
    END
  END tl_u_uart_i[42]
  PIN tl_u_uart_i[43]
    DIRECTION INPUT ;
    USE SIGNAL ;
    ANTENNAGATEAREA 0.631200 ;
    ANTENNADIFFAREA 0.434700 ;
    PORT
      LAYER met3 ;
        RECT 1296.000 397.840 1300.000 398.440 ;
    END
  END tl_u_uart_i[43]
  PIN tl_u_uart_i[44]
    DIRECTION INPUT ;
    USE SIGNAL ;
    ANTENNAGATEAREA 0.647700 ;
    ANTENNADIFFAREA 0.434700 ;
    PORT
      LAYER met3 ;
        RECT 1296.000 744.640 1300.000 745.240 ;
    END
  END tl_u_uart_i[44]
  PIN tl_u_uart_i[45]
    DIRECTION INPUT ;
    USE SIGNAL ;
    ANTENNAGATEAREA 0.593700 ;
    ANTENNADIFFAREA 0.434700 ;
    PORT
      LAYER met3 ;
        RECT 1296.000 703.840 1300.000 704.440 ;
    END
  END tl_u_uart_i[45]
  PIN tl_u_uart_i[46]
    DIRECTION INPUT ;
    USE SIGNAL ;
    ANTENNAGATEAREA 0.593700 ;
    ANTENNADIFFAREA 0.434700 ;
    PORT
      LAYER met3 ;
        RECT 1296.000 805.840 1300.000 806.440 ;
    END
  END tl_u_uart_i[46]
  PIN tl_u_uart_i[47]
    DIRECTION INPUT ;
    USE SIGNAL ;
    ANTENNAGATEAREA 0.631200 ;
    ANTENNADIFFAREA 0.434700 ;
    PORT
      LAYER met2 ;
        RECT 595.790 1296.000 596.070 1300.000 ;
    END
  END tl_u_uart_i[47]
  PIN tl_u_uart_i[48]
    DIRECTION INPUT ;
    USE SIGNAL ;
    ANTENNAGATEAREA 0.682200 ;
    ANTENNADIFFAREA 0.434700 ;
    PORT
      LAYER met2 ;
        RECT 483.090 1296.000 483.370 1300.000 ;
    END
  END tl_u_uart_i[48]
  PIN tl_u_uart_i[49]
    DIRECTION INPUT ;
    USE SIGNAL ;
    ANTENNAGATEAREA 0.631200 ;
    ANTENNADIFFAREA 0.434700 ;
    PORT
      LAYER met3 ;
        RECT 1296.000 669.840 1300.000 670.440 ;
    END
  END tl_u_uart_i[49]
  PIN tl_u_uart_i[4]
    DIRECTION INPUT ;
    USE SIGNAL ;
    ANTENNAGATEAREA 0.647700 ;
    ANTENNADIFFAREA 0.434700 ;
    PORT
      LAYER met3 ;
        RECT 1296.000 676.640 1300.000 677.240 ;
    END
  END tl_u_uart_i[4]
  PIN tl_u_uart_i[50]
    DIRECTION INPUT ;
    USE SIGNAL ;
    ANTENNAGATEAREA 0.593700 ;
    ANTENNADIFFAREA 0.434700 ;
    PORT
      LAYER met2 ;
        RECT 618.330 1296.000 618.610 1300.000 ;
    END
  END tl_u_uart_i[50]
  PIN tl_u_uart_i[51]
    DIRECTION INPUT ;
    USE SIGNAL ;
    ANTENNAGATEAREA 0.647700 ;
    ANTENNADIFFAREA 0.434700 ;
    PORT
      LAYER met3 ;
        RECT 1296.000 945.240 1300.000 945.840 ;
    END
  END tl_u_uart_i[51]
  PIN tl_u_uart_i[52]
    DIRECTION INPUT ;
    USE SIGNAL ;
    ANTENNAGATEAREA 0.560700 ;
    ANTENNADIFFAREA 0.434700 ;
    PORT
      LAYER met3 ;
        RECT 1296.000 1128.840 1300.000 1129.440 ;
    END
  END tl_u_uart_i[52]
  PIN tl_u_uart_i[53]
    DIRECTION INPUT ;
    USE SIGNAL ;
    ANTENNAGATEAREA 0.560700 ;
    ANTENNADIFFAREA 0.434700 ;
    PORT
      LAYER met2 ;
        RECT 315.650 1296.000 315.930 1300.000 ;
    END
  END tl_u_uart_i[53]
  PIN tl_u_uart_i[54]
    DIRECTION INPUT ;
    USE SIGNAL ;
    ANTENNAGATEAREA 0.593700 ;
    ANTENNADIFFAREA 0.434700 ;
    PORT
      LAYER met3 ;
        RECT 1296.000 380.840 1300.000 381.440 ;
    END
  END tl_u_uart_i[54]
  PIN tl_u_uart_i[55]
    DIRECTION INPUT ;
    USE SIGNAL ;
    ANTENNAGATEAREA 0.631200 ;
    ANTENNADIFFAREA 0.434700 ;
    PORT
      LAYER met3 ;
        RECT 1296.000 272.040 1300.000 272.640 ;
    END
  END tl_u_uart_i[55]
  PIN tl_u_uart_i[56]
    DIRECTION INPUT ;
    USE SIGNAL ;
    ANTENNAGATEAREA 0.682200 ;
    ANTENNADIFFAREA 0.434700 ;
    PORT
      LAYER met2 ;
        RECT 338.190 1296.000 338.470 1300.000 ;
    END
  END tl_u_uart_i[56]
  PIN tl_u_uart_i[57]
    DIRECTION INPUT ;
    USE SIGNAL ;
    ANTENNAGATEAREA 0.647700 ;
    ANTENNADIFFAREA 0.434700 ;
    PORT
      LAYER met3 ;
        RECT 1296.000 394.440 1300.000 395.040 ;
    END
  END tl_u_uart_i[57]
  PIN tl_u_uart_i[58]
    DIRECTION INPUT ;
    USE SIGNAL ;
    ANTENNAGATEAREA 0.593700 ;
    ANTENNADIFFAREA 0.434700 ;
    PORT
      LAYER met3 ;
        RECT 1296.000 765.040 1300.000 765.640 ;
    END
  END tl_u_uart_i[58]
  PIN tl_u_uart_i[59]
    DIRECTION INPUT ;
    USE SIGNAL ;
    ANTENNAGATEAREA 0.631200 ;
    ANTENNADIFFAREA 0.434700 ;
    PORT
      LAYER met3 ;
        RECT 1296.000 788.840 1300.000 789.440 ;
    END
  END tl_u_uart_i[59]
  PIN tl_u_uart_i[5]
    DIRECTION INPUT ;
    USE SIGNAL ;
    ANTENNAGATEAREA 0.631200 ;
    ANTENNADIFFAREA 0.434700 ;
    PORT
      LAYER met3 ;
        RECT 1296.000 853.440 1300.000 854.040 ;
    END
  END tl_u_uart_i[5]
  PIN tl_u_uart_i[60]
    DIRECTION INPUT ;
    USE SIGNAL ;
    ANTENNAGATEAREA 0.682200 ;
    ANTENNADIFFAREA 0.434700 ;
    PORT
      LAYER met2 ;
        RECT 460.550 1296.000 460.830 1300.000 ;
    END
  END tl_u_uart_i[60]
  PIN tl_u_uart_i[61]
    DIRECTION INPUT ;
    USE SIGNAL ;
    ANTENNAGATEAREA 0.647700 ;
    ANTENNADIFFAREA 0.434700 ;
    PORT
      LAYER met3 ;
        RECT 1296.000 775.240 1300.000 775.840 ;
    END
  END tl_u_uart_i[61]
  PIN tl_u_uart_i[62]
    DIRECTION INPUT ;
    USE SIGNAL ;
    ANTENNAGATEAREA 0.631200 ;
    ANTENNADIFFAREA 0.434700 ;
    PORT
      LAYER met3 ;
        RECT 1296.000 1162.840 1300.000 1163.440 ;
    END
  END tl_u_uart_i[62]
  PIN tl_u_uart_i[63]
    DIRECTION INPUT ;
    USE SIGNAL ;
    ANTENNAGATEAREA 0.631200 ;
    ANTENNADIFFAREA 0.434700 ;
    PORT
      LAYER met2 ;
        RECT 647.310 1296.000 647.590 1300.000 ;
    END
  END tl_u_uart_i[63]
  PIN tl_u_uart_i[64]
    DIRECTION INPUT ;
    USE SIGNAL ;
    ANTENNAGATEAREA 0.631200 ;
    ANTENNADIFFAREA 0.434700 ;
    PORT
      LAYER met3 ;
        RECT 1296.000 1009.840 1300.000 1010.440 ;
    END
  END tl_u_uart_i[64]
  PIN tl_u_uart_i[65]
    DIRECTION INPUT ;
    USE SIGNAL ;
    ANTENNAGATEAREA 0.593700 ;
    ANTENNADIFFAREA 0.434700 ;
    PORT
      LAYER met3 ;
        RECT 1296.000 1234.240 1300.000 1234.840 ;
    END
  END tl_u_uart_i[65]
  PIN tl_u_uart_i[6]
    DIRECTION INPUT ;
    USE SIGNAL ;
    ANTENNAGATEAREA 0.560700 ;
    ANTENNADIFFAREA 0.434700 ;
    PORT
      LAYER met3 ;
        RECT 1296.000 1149.240 1300.000 1149.840 ;
    END
  END tl_u_uart_i[6]
  PIN tl_u_uart_i[7]
    DIRECTION INPUT ;
    USE SIGNAL ;
    ANTENNAGATEAREA 0.631200 ;
    ANTENNADIFFAREA 0.434700 ;
    PORT
      LAYER met2 ;
        RECT 650.530 1296.000 650.810 1300.000 ;
    END
  END tl_u_uart_i[7]
  PIN tl_u_uart_i[8]
    DIRECTION INPUT ;
    USE SIGNAL ;
    ANTENNAGATEAREA 0.593700 ;
    ANTENNADIFFAREA 0.434700 ;
    PORT
      LAYER met3 ;
        RECT 1296.000 282.240 1300.000 282.840 ;
    END
  END tl_u_uart_i[8]
  PIN tl_u_uart_i[9]
    DIRECTION INPUT ;
    USE SIGNAL ;
    ANTENNAGATEAREA 0.593700 ;
    ANTENNADIFFAREA 0.434700 ;
    PORT
      LAYER met3 ;
        RECT 1296.000 720.840 1300.000 721.440 ;
    END
  END tl_u_uart_i[9]
  PIN tl_u_uart_o[0]
    DIRECTION OUTPUT ;
    USE SIGNAL ;
    ANTENNADIFFAREA 0.445500 ;
    PORT
      LAYER met2 ;
        RECT 402.590 1296.000 402.870 1300.000 ;
    END
  END tl_u_uart_o[0]
  PIN tl_u_uart_o[100]
    DIRECTION OUTPUT ;
    USE SIGNAL ;
    ANTENNADIFFAREA 0.445500 ;
    PORT
      LAYER met2 ;
        RECT 405.810 1296.000 406.090 1300.000 ;
    END
  END tl_u_uart_o[100]
  PIN tl_u_uart_o[101]
    DIRECTION OUTPUT ;
    USE SIGNAL ;
    ANTENNADIFFAREA 0.445500 ;
    PORT
      LAYER met3 ;
        RECT 1296.000 591.640 1300.000 592.240 ;
    END
  END tl_u_uart_o[101]
  PIN tl_u_uart_o[102]
    DIRECTION OUTPUT ;
    USE SIGNAL ;
    ANTENNADIFFAREA 0.445500 ;
    PORT
      LAYER met2 ;
        RECT 486.310 1296.000 486.590 1300.000 ;
    END
  END tl_u_uart_o[102]
  PIN tl_u_uart_o[103]
    DIRECTION OUTPUT ;
    USE SIGNAL ;
    ANTENNADIFFAREA 0.445500 ;
    PORT
      LAYER met3 ;
        RECT 1296.000 299.240 1300.000 299.840 ;
    END
  END tl_u_uart_o[103]
  PIN tl_u_uart_o[104]
    DIRECTION OUTPUT ;
    USE SIGNAL ;
    ANTENNADIFFAREA 0.445500 ;
    PORT
      LAYER met3 ;
        RECT 1296.000 584.840 1300.000 585.440 ;
    END
  END tl_u_uart_o[104]
  PIN tl_u_uart_o[105]
    DIRECTION OUTPUT ;
    USE SIGNAL ;
    ANTENNADIFFAREA 0.445500 ;
    PORT
      LAYER met2 ;
        RECT 389.710 1296.000 389.990 1300.000 ;
    END
  END tl_u_uart_o[105]
  PIN tl_u_uart_o[106]
    DIRECTION OUTPUT ;
    USE SIGNAL ;
    ANTENNADIFFAREA 0.445500 ;
    PORT
      LAYER met3 ;
        RECT 0.000 615.440 4.000 616.040 ;
    END
  END tl_u_uart_o[106]
  PIN tl_u_uart_o[107]
    DIRECTION OUTPUT ;
    USE SIGNAL ;
    ANTENNADIFFAREA 0.445500 ;
    PORT
      LAYER met2 ;
        RECT 537.830 1296.000 538.110 1300.000 ;
    END
  END tl_u_uart_o[107]
  PIN tl_u_uart_o[108]
    DIRECTION OUTPUT ;
    USE SIGNAL ;
    ANTENNADIFFAREA 0.445500 ;
    PORT
      LAYER met3 ;
        RECT 0.000 319.640 4.000 320.240 ;
    END
  END tl_u_uart_o[108]
  PIN tl_u_uart_o[109]
    DIRECTION OUTPUT ;
    USE SIGNAL ;
    ANTENNADIFFAREA 0.445500 ;
    PORT
      LAYER met3 ;
        RECT 0.000 394.440 4.000 395.040 ;
    END
  END tl_u_uart_o[109]
  PIN tl_u_uart_o[10]
    DIRECTION OUTPUT ;
    USE SIGNAL ;
    ANTENNADIFFAREA 0.445500 ;
    PORT
      LAYER met3 ;
        RECT 0.000 78.240 4.000 78.840 ;
    END
  END tl_u_uart_o[10]
  PIN tl_u_uart_o[11]
    DIRECTION OUTPUT ;
    USE SIGNAL ;
    ANTENNADIFFAREA 0.445500 ;
    PORT
      LAYER met3 ;
        RECT 1296.000 438.640 1300.000 439.240 ;
    END
  END tl_u_uart_o[11]
  PIN tl_u_uart_o[12]
    DIRECTION OUTPUT ;
    USE SIGNAL ;
    ANTENNADIFFAREA 0.445500 ;
    PORT
      LAYER met2 ;
        RECT 479.870 1296.000 480.150 1300.000 ;
    END
  END tl_u_uart_o[12]
  PIN tl_u_uart_o[13]
    DIRECTION OUTPUT ;
    USE SIGNAL ;
    ANTENNADIFFAREA 0.445500 ;
    PORT
      LAYER met3 ;
        RECT 1296.000 1264.840 1300.000 1265.440 ;
    END
  END tl_u_uart_o[13]
  PIN tl_u_uart_o[14]
    DIRECTION OUTPUT ;
    USE SIGNAL ;
    ANTENNADIFFAREA 0.445500 ;
    PORT
      LAYER met3 ;
        RECT 0.000 47.640 4.000 48.240 ;
    END
  END tl_u_uart_o[14]
  PIN tl_u_uart_o[15]
    DIRECTION OUTPUT ;
    USE SIGNAL ;
    ANTENNADIFFAREA 0.445500 ;
    PORT
      LAYER met3 ;
        RECT 0.000 108.840 4.000 109.440 ;
    END
  END tl_u_uart_o[15]
  PIN tl_u_uart_o[16]
    DIRECTION OUTPUT ;
    USE SIGNAL ;
    ANTENNADIFFAREA 0.445500 ;
    PORT
      LAYER met3 ;
        RECT 1296.000 554.240 1300.000 554.840 ;
    END
  END tl_u_uart_o[16]
  PIN tl_u_uart_o[17]
    DIRECTION OUTPUT ;
    USE SIGNAL ;
    ANTENNADIFFAREA 0.445500 ;
    PORT
      LAYER met3 ;
        RECT 1296.000 710.640 1300.000 711.240 ;
    END
  END tl_u_uart_o[17]
  PIN tl_u_uart_o[18]
    DIRECTION OUTPUT ;
    USE SIGNAL ;
    ANTENNADIFFAREA 0.445500 ;
    PORT
      LAYER met3 ;
        RECT 1296.000 952.040 1300.000 952.640 ;
    END
  END tl_u_uart_o[18]
  PIN tl_u_uart_o[19]
    DIRECTION OUTPUT ;
    USE SIGNAL ;
    ANTENNADIFFAREA 0.445500 ;
    PORT
      LAYER met2 ;
        RECT 318.870 1296.000 319.150 1300.000 ;
    END
  END tl_u_uart_o[19]
  PIN tl_u_uart_o[1]
    DIRECTION OUTPUT ;
    USE SIGNAL ;
    ANTENNADIFFAREA 0.445500 ;
    PORT
      LAYER met2 ;
        RECT 566.810 1296.000 567.090 1300.000 ;
    END
  END tl_u_uart_o[1]
  PIN tl_u_uart_o[20]
    DIRECTION OUTPUT ;
    USE SIGNAL ;
    ANTENNADIFFAREA 0.445500 ;
    PORT
      LAYER met3 ;
        RECT 0.000 459.040 4.000 459.640 ;
    END
  END tl_u_uart_o[20]
  PIN tl_u_uart_o[21]
    DIRECTION OUTPUT ;
    USE SIGNAL ;
    ANTENNADIFFAREA 0.445500 ;
    PORT
      LAYER met3 ;
        RECT 1296.000 408.040 1300.000 408.640 ;
    END
  END tl_u_uart_o[21]
  PIN tl_u_uart_o[22]
    DIRECTION OUTPUT ;
    USE SIGNAL ;
    ANTENNADIFFAREA 0.445500 ;
    PORT
      LAYER met3 ;
        RECT 1296.000 843.240 1300.000 843.840 ;
    END
  END tl_u_uart_o[22]
  PIN tl_u_uart_o[23]
    DIRECTION OUTPUT ;
    USE SIGNAL ;
    ANTENNADIFFAREA 0.445500 ;
    PORT
      LAYER met3 ;
        RECT 0.000 544.040 4.000 544.640 ;
    END
  END tl_u_uart_o[23]
  PIN tl_u_uart_o[24]
    DIRECTION OUTPUT ;
    USE SIGNAL ;
    ANTENNADIFFAREA 0.445500 ;
    PORT
      LAYER met2 ;
        RECT 392.930 1296.000 393.210 1300.000 ;
    END
  END tl_u_uart_o[24]
  PIN tl_u_uart_o[25]
    DIRECTION OUTPUT ;
    USE SIGNAL ;
    ANTENNADIFFAREA 0.445500 ;
    PORT
      LAYER met3 ;
        RECT 0.000 0.040 4.000 0.640 ;
    END
  END tl_u_uart_o[25]
  PIN tl_u_uart_o[26]
    DIRECTION OUTPUT ;
    USE SIGNAL ;
    ANTENNADIFFAREA 0.445500 ;
    PORT
      LAYER met2 ;
        RECT 454.110 1296.000 454.390 1300.000 ;
    END
  END tl_u_uart_o[26]
  PIN tl_u_uart_o[27]
    DIRECTION OUTPUT ;
    USE SIGNAL ;
    ANTENNADIFFAREA 0.445500 ;
    PORT
      LAYER met3 ;
        RECT 0.000 431.840 4.000 432.440 ;
    END
  END tl_u_uart_o[27]
  PIN tl_u_uart_o[28]
    DIRECTION OUTPUT ;
    USE SIGNAL ;
    ANTENNADIFFAREA 0.445500 ;
    PORT
      LAYER met3 ;
        RECT 1296.000 316.240 1300.000 316.840 ;
    END
  END tl_u_uart_o[28]
  PIN tl_u_uart_o[29]
    DIRECTION OUTPUT ;
    USE SIGNAL ;
    ANTENNADIFFAREA 0.445500 ;
    PORT
      LAYER met3 ;
        RECT 0.000 156.440 4.000 157.040 ;
    END
  END tl_u_uart_o[29]
  PIN tl_u_uart_o[2]
    DIRECTION OUTPUT ;
    USE SIGNAL ;
    ANTENNADIFFAREA 0.445500 ;
    PORT
      LAYER met2 ;
        RECT 492.750 1296.000 493.030 1300.000 ;
    END
  END tl_u_uart_o[2]
  PIN tl_u_uart_o[30]
    DIRECTION OUTPUT ;
    USE SIGNAL ;
    ANTENNADIFFAREA 0.445500 ;
    PORT
      LAYER met3 ;
        RECT 1296.000 975.840 1300.000 976.440 ;
    END
  END tl_u_uart_o[30]
  PIN tl_u_uart_o[31]
    DIRECTION OUTPUT ;
    USE SIGNAL ;
    ANTENNADIFFAREA 0.445500 ;
    PORT
      LAYER met3 ;
        RECT 1296.000 459.040 1300.000 459.640 ;
    END
  END tl_u_uart_o[31]
  PIN tl_u_uart_o[32]
    DIRECTION OUTPUT ;
    USE SIGNAL ;
    ANTENNADIFFAREA 0.445500 ;
    PORT
      LAYER met3 ;
        RECT 1296.000 537.240 1300.000 537.840 ;
    END
  END tl_u_uart_o[32]
  PIN tl_u_uart_o[33]
    DIRECTION OUTPUT ;
    USE SIGNAL ;
    ANTENNADIFFAREA 0.445500 ;
    PORT
      LAYER met3 ;
        RECT 0.000 418.240 4.000 418.840 ;
    END
  END tl_u_uart_o[33]
  PIN tl_u_uart_o[34]
    DIRECTION OUTPUT ;
    USE SIGNAL ;
    ANTENNADIFFAREA 0.445500 ;
    PORT
      LAYER met3 ;
        RECT 0.000 618.840 4.000 619.440 ;
    END
  END tl_u_uart_o[34]
  PIN tl_u_uart_o[35]
    DIRECTION OUTPUT ;
    USE SIGNAL ;
    ANTENNADIFFAREA 0.445500 ;
    PORT
      LAYER met3 ;
        RECT 1296.000 588.240 1300.000 588.840 ;
    END
  END tl_u_uart_o[35]
  PIN tl_u_uart_o[36]
    DIRECTION OUTPUT ;
    USE SIGNAL ;
    ANTENNADIFFAREA 0.445500 ;
    PORT
      LAYER met2 ;
        RECT 328.530 1296.000 328.810 1300.000 ;
    END
  END tl_u_uart_o[36]
  PIN tl_u_uart_o[37]
    DIRECTION OUTPUT ;
    USE SIGNAL ;
    ANTENNADIFFAREA 0.445500 ;
    PORT
      LAYER met3 ;
        RECT 1296.000 363.840 1300.000 364.440 ;
    END
  END tl_u_uart_o[37]
  PIN tl_u_uart_o[38]
    DIRECTION OUTPUT ;
    USE SIGNAL ;
    ANTENNADIFFAREA 0.445500 ;
    PORT
      LAYER met3 ;
        RECT 0.000 533.840 4.000 534.440 ;
    END
  END tl_u_uart_o[38]
  PIN tl_u_uart_o[39]
    DIRECTION OUTPUT ;
    USE SIGNAL ;
    ANTENNADIFFAREA 0.445500 ;
    PORT
      LAYER met3 ;
        RECT 1296.000 561.040 1300.000 561.640 ;
    END
  END tl_u_uart_o[39]
  PIN tl_u_uart_o[3]
    DIRECTION OUTPUT ;
    USE SIGNAL ;
    ANTENNADIFFAREA 0.445500 ;
    PORT
      LAYER met3 ;
        RECT 1296.000 581.440 1300.000 582.040 ;
    END
  END tl_u_uart_o[3]
  PIN tl_u_uart_o[40]
    DIRECTION OUTPUT ;
    USE SIGNAL ;
    ANTENNADIFFAREA 0.445500 ;
    PORT
      LAYER met2 ;
        RECT 547.490 1296.000 547.770 1300.000 ;
    END
  END tl_u_uart_o[40]
  PIN tl_u_uart_o[41]
    DIRECTION OUTPUT ;
    USE SIGNAL ;
    ANTENNADIFFAREA 0.445500 ;
    PORT
      LAYER met3 ;
        RECT 1296.000 469.240 1300.000 469.840 ;
    END
  END tl_u_uart_o[41]
  PIN tl_u_uart_o[42]
    DIRECTION OUTPUT ;
    USE SIGNAL ;
    ANTENNADIFFAREA 0.445500 ;
    PORT
      LAYER met3 ;
        RECT 1296.000 618.840 1300.000 619.440 ;
    END
  END tl_u_uart_o[42]
  PIN tl_u_uart_o[43]
    DIRECTION OUTPUT ;
    USE SIGNAL ;
    ANTENNADIFFAREA 0.445500 ;
    PORT
      LAYER met2 ;
        RECT 531.390 1296.000 531.670 1300.000 ;
    END
  END tl_u_uart_o[43]
  PIN tl_u_uart_o[44]
    DIRECTION OUTPUT ;
    USE SIGNAL ;
    ANTENNADIFFAREA 0.445500 ;
    PORT
      LAYER met2 ;
        RECT 434.790 1296.000 435.070 1300.000 ;
    END
  END tl_u_uart_o[44]
  PIN tl_u_uart_o[45]
    DIRECTION OUTPUT ;
    USE SIGNAL ;
    ANTENNADIFFAREA 0.445500 ;
    PORT
      LAYER met3 ;
        RECT 1296.000 571.240 1300.000 571.840 ;
    END
  END tl_u_uart_o[45]
  PIN tl_u_uart_o[46]
    DIRECTION OUTPUT ;
    USE SIGNAL ;
    ANTENNADIFFAREA 0.445500 ;
    PORT
      LAYER met3 ;
        RECT 1296.000 1152.640 1300.000 1153.240 ;
    END
  END tl_u_uart_o[46]
  PIN tl_u_uart_o[47]
    DIRECTION OUTPUT ;
    USE SIGNAL ;
    ANTENNADIFFAREA 0.445500 ;
    PORT
      LAYER met2 ;
        RECT 431.570 1296.000 431.850 1300.000 ;
    END
  END tl_u_uart_o[47]
  PIN tl_u_uart_o[48]
    DIRECTION OUTPUT ;
    USE SIGNAL ;
    ANTENNADIFFAREA 0.445500 ;
    PORT
      LAYER met2 ;
        RECT 380.050 1296.000 380.330 1300.000 ;
    END
  END tl_u_uart_o[48]
  PIN tl_u_uart_o[49]
    DIRECTION OUTPUT ;
    USE SIGNAL ;
    ANTENNADIFFAREA 0.445500 ;
    PORT
      LAYER met2 ;
        RECT 541.050 1296.000 541.330 1300.000 ;
    END
  END tl_u_uart_o[49]
  PIN tl_u_uart_o[4]
    DIRECTION OUTPUT ;
    USE SIGNAL ;
    ANTENNADIFFAREA 0.445500 ;
    PORT
      LAYER met3 ;
        RECT 1296.000 530.440 1300.000 531.040 ;
    END
  END tl_u_uart_o[4]
  PIN tl_u_uart_o[50]
    DIRECTION OUTPUT ;
    USE SIGNAL ;
    ANTENNADIFFAREA 0.445500 ;
    PORT
      LAYER met3 ;
        RECT 1296.000 452.240 1300.000 452.840 ;
    END
  END tl_u_uart_o[50]
  PIN tl_u_uart_o[51]
    DIRECTION OUTPUT ;
    USE SIGNAL ;
    ANTENNADIFFAREA 0.445500 ;
    PORT
      LAYER met2 ;
        RECT 425.130 1296.000 425.410 1300.000 ;
    END
  END tl_u_uart_o[51]
  PIN tl_u_uart_o[52]
    DIRECTION OUTPUT ;
    USE SIGNAL ;
    ANTENNADIFFAREA 0.445500 ;
    PORT
      LAYER met3 ;
        RECT 1296.000 231.240 1300.000 231.840 ;
    END
  END tl_u_uart_o[52]
  PIN tl_u_uart_o[53]
    DIRECTION OUTPUT ;
    USE SIGNAL ;
    ANTENNADIFFAREA 0.445500 ;
    PORT
      LAYER met3 ;
        RECT 1296.000 462.440 1300.000 463.040 ;
    END
  END tl_u_uart_o[53]
  PIN tl_u_uart_o[54]
    DIRECTION OUTPUT ;
    USE SIGNAL ;
    ANTENNADIFFAREA 0.445500 ;
    PORT
      LAYER met2 ;
        RECT 544.270 1296.000 544.550 1300.000 ;
    END
  END tl_u_uart_o[54]
  PIN tl_u_uart_o[55]
    DIRECTION OUTPUT ;
    USE SIGNAL ;
    ANTENNADIFFAREA 0.445500 ;
    PORT
      LAYER met2 ;
        RECT 563.590 1296.000 563.870 1300.000 ;
    END
  END tl_u_uart_o[55]
  PIN tl_u_uart_o[56]
    DIRECTION OUTPUT ;
    USE SIGNAL ;
    ANTENNADIFFAREA 0.445500 ;
    PORT
      LAYER met2 ;
        RECT 605.450 1296.000 605.730 1300.000 ;
    END
  END tl_u_uart_o[56]
  PIN tl_u_uart_o[57]
    DIRECTION OUTPUT ;
    USE SIGNAL ;
    ANTENNADIFFAREA 0.445500 ;
    PORT
      LAYER met2 ;
        RECT 599.010 1296.000 599.290 1300.000 ;
    END
  END tl_u_uart_o[57]
  PIN tl_u_uart_o[58]
    DIRECTION OUTPUT ;
    USE SIGNAL ;
    ANTENNADIFFAREA 0.445500 ;
    PORT
      LAYER met3 ;
        RECT 1296.000 1166.240 1300.000 1166.840 ;
    END
  END tl_u_uart_o[58]
  PIN tl_u_uart_o[59]
    DIRECTION OUTPUT ;
    USE SIGNAL ;
    ANTENNADIFFAREA 0.445500 ;
    PORT
      LAYER met3 ;
        RECT 1296.000 506.640 1300.000 507.240 ;
    END
  END tl_u_uart_o[59]
  PIN tl_u_uart_o[5]
    DIRECTION OUTPUT ;
    USE SIGNAL ;
    ANTENNADIFFAREA 0.445500 ;
    PORT
      LAYER met2 ;
        RECT 621.550 1296.000 621.830 1300.000 ;
    END
  END tl_u_uart_o[5]
  PIN tl_u_uart_o[60]
    DIRECTION OUTPUT ;
    USE SIGNAL ;
    ANTENNADIFFAREA 0.445500 ;
    PORT
      LAYER met3 ;
        RECT 1296.000 812.640 1300.000 813.240 ;
    END
  END tl_u_uart_o[60]
  PIN tl_u_uart_o[61]
    DIRECTION OUTPUT ;
    USE SIGNAL ;
    ANTENNADIFFAREA 0.445500 ;
    PORT
      LAYER met3 ;
        RECT 0.000 54.440 4.000 55.040 ;
    END
  END tl_u_uart_o[61]
  PIN tl_u_uart_o[62]
    DIRECTION OUTPUT ;
    USE SIGNAL ;
    ANTENNADIFFAREA 0.445500 ;
    PORT
      LAYER met3 ;
        RECT 0.000 255.040 4.000 255.640 ;
    END
  END tl_u_uart_o[62]
  PIN tl_u_uart_o[63]
    DIRECTION OUTPUT ;
    USE SIGNAL ;
    ANTENNADIFFAREA 0.445500 ;
    PORT
      LAYER met3 ;
        RECT 0.000 20.440 4.000 21.040 ;
    END
  END tl_u_uart_o[63]
  PIN tl_u_uart_o[64]
    DIRECTION OUTPUT ;
    USE SIGNAL ;
    ANTENNADIFFAREA 0.445500 ;
    PORT
      LAYER met3 ;
        RECT 0.000 115.640 4.000 116.240 ;
    END
  END tl_u_uart_o[64]
  PIN tl_u_uart_o[65]
    DIRECTION OUTPUT ;
    USE SIGNAL ;
    ANTENNADIFFAREA 0.445500 ;
    PORT
      LAYER met3 ;
        RECT 0.000 132.640 4.000 133.240 ;
    END
  END tl_u_uart_o[65]
  PIN tl_u_uart_o[66]
    DIRECTION OUTPUT ;
    USE SIGNAL ;
    ANTENNADIFFAREA 0.445500 ;
    PORT
      LAYER met3 ;
        RECT 0.000 265.240 4.000 265.840 ;
    END
  END tl_u_uart_o[66]
  PIN tl_u_uart_o[67]
    DIRECTION OUTPUT ;
    USE SIGNAL ;
    ANTENNADIFFAREA 0.445500 ;
    PORT
      LAYER met3 ;
        RECT 0.000 353.640 4.000 354.240 ;
    END
  END tl_u_uart_o[67]
  PIN tl_u_uart_o[68]
    DIRECTION OUTPUT ;
    USE SIGNAL ;
    ANTENNADIFFAREA 0.445500 ;
    PORT
      LAYER met3 ;
        RECT 0.000 295.840 4.000 296.440 ;
    END
  END tl_u_uart_o[68]
  PIN tl_u_uart_o[69]
    DIRECTION OUTPUT ;
    USE SIGNAL ;
    ANTENNADIFFAREA 0.445500 ;
    PORT
      LAYER met3 ;
        RECT 0.000 193.840 4.000 194.440 ;
    END
  END tl_u_uart_o[69]
  PIN tl_u_uart_o[6]
    DIRECTION OUTPUT ;
    USE SIGNAL ;
    ANTENNADIFFAREA 0.445500 ;
    PORT
      LAYER met2 ;
        RECT 473.430 1296.000 473.710 1300.000 ;
    END
  END tl_u_uart_o[6]
  PIN tl_u_uart_o[70]
    DIRECTION OUTPUT ;
    USE SIGNAL ;
    ANTENNADIFFAREA 0.445500 ;
    PORT
      LAYER met3 ;
        RECT 0.000 469.240 4.000 469.840 ;
    END
  END tl_u_uart_o[70]
  PIN tl_u_uart_o[71]
    DIRECTION OUTPUT ;
    USE SIGNAL ;
    ANTENNADIFFAREA 0.445500 ;
    PORT
      LAYER met3 ;
        RECT 0.000 227.840 4.000 228.440 ;
    END
  END tl_u_uart_o[71]
  PIN tl_u_uart_o[72]
    DIRECTION OUTPUT ;
    USE SIGNAL ;
    ANTENNADIFFAREA 0.445500 ;
    PORT
      LAYER met3 ;
        RECT 0.000 91.840 4.000 92.440 ;
    END
  END tl_u_uart_o[72]
  PIN tl_u_uart_o[73]
    DIRECTION OUTPUT ;
    USE SIGNAL ;
    ANTENNADIFFAREA 0.445500 ;
    PORT
      LAYER met3 ;
        RECT 0.000 149.640 4.000 150.240 ;
    END
  END tl_u_uart_o[73]
  PIN tl_u_uart_o[74]
    DIRECTION OUTPUT ;
    USE SIGNAL ;
    ANTENNADIFFAREA 0.445500 ;
    PORT
      LAYER met3 ;
        RECT 0.000 428.440 4.000 429.040 ;
    END
  END tl_u_uart_o[74]
  PIN tl_u_uart_o[75]
    DIRECTION OUTPUT ;
    USE SIGNAL ;
    ANTENNADIFFAREA 0.445500 ;
    PORT
      LAYER met3 ;
        RECT 0.000 326.440 4.000 327.040 ;
    END
  END tl_u_uart_o[75]
  PIN tl_u_uart_o[76]
    DIRECTION OUTPUT ;
    USE SIGNAL ;
    ANTENNADIFFAREA 0.445500 ;
    PORT
      LAYER met3 ;
        RECT 0.000 387.640 4.000 388.240 ;
    END
  END tl_u_uart_o[76]
  PIN tl_u_uart_o[77]
    DIRECTION OUTPUT ;
    USE SIGNAL ;
    ANTENNADIFFAREA 0.445500 ;
    PORT
      LAYER met3 ;
        RECT 0.000 530.440 4.000 531.040 ;
    END
  END tl_u_uart_o[77]
  PIN tl_u_uart_o[78]
    DIRECTION OUTPUT ;
    USE SIGNAL ;
    ANTENNADIFFAREA 0.445500 ;
    PORT
      LAYER met3 ;
        RECT 0.000 10.240 4.000 10.840 ;
    END
  END tl_u_uart_o[78]
  PIN tl_u_uart_o[79]
    DIRECTION OUTPUT ;
    USE SIGNAL ;
    ANTENNADIFFAREA 0.445500 ;
    PORT
      LAYER met3 ;
        RECT 0.000 102.040 4.000 102.640 ;
    END
  END tl_u_uart_o[79]
  PIN tl_u_uart_o[7]
    DIRECTION OUTPUT ;
    USE SIGNAL ;
    ANTENNADIFFAREA 0.445500 ;
    PORT
      LAYER met3 ;
        RECT 1296.000 489.640 1300.000 490.240 ;
    END
  END tl_u_uart_o[7]
  PIN tl_u_uart_o[80]
    DIRECTION OUTPUT ;
    USE SIGNAL ;
    ANTENNADIFFAREA 0.445500 ;
    PORT
      LAYER met3 ;
        RECT 0.000 299.240 4.000 299.840 ;
    END
  END tl_u_uart_o[80]
  PIN tl_u_uart_o[81]
    DIRECTION OUTPUT ;
    USE SIGNAL ;
    ANTENNADIFFAREA 0.445500 ;
    PORT
      LAYER met3 ;
        RECT 0.000 258.440 4.000 259.040 ;
    END
  END tl_u_uart_o[81]
  PIN tl_u_uart_o[82]
    DIRECTION OUTPUT ;
    USE SIGNAL ;
    ANTENNADIFFAREA 0.445500 ;
    PORT
      LAYER met3 ;
        RECT 0.000 489.640 4.000 490.240 ;
    END
  END tl_u_uart_o[82]
  PIN tl_u_uart_o[83]
    DIRECTION OUTPUT ;
    USE SIGNAL ;
    ANTENNADIFFAREA 0.445500 ;
    PORT
      LAYER met3 ;
        RECT 0.000 595.040 4.000 595.640 ;
    END
  END tl_u_uart_o[83]
  PIN tl_u_uart_o[84]
    DIRECTION OUTPUT ;
    USE SIGNAL ;
    ANTENNADIFFAREA 0.445500 ;
    PORT
      LAYER met3 ;
        RECT 0.000 516.840 4.000 517.440 ;
    END
  END tl_u_uart_o[84]
  PIN tl_u_uart_o[85]
    DIRECTION OUTPUT ;
    USE SIGNAL ;
    ANTENNADIFFAREA 0.445500 ;
    PORT
      LAYER met3 ;
        RECT 0.000 13.640 4.000 14.240 ;
    END
  END tl_u_uart_o[85]
  PIN tl_u_uart_o[86]
    DIRECTION OUTPUT ;
    USE SIGNAL ;
    ANTENNADIFFAREA 0.445500 ;
    PORT
      LAYER met3 ;
        RECT 0.000 329.840 4.000 330.440 ;
    END
  END tl_u_uart_o[86]
  PIN tl_u_uart_o[87]
    DIRECTION OUTPUT ;
    USE SIGNAL ;
    ANTENNADIFFAREA 0.445500 ;
    PORT
      LAYER met3 ;
        RECT 0.000 30.640 4.000 31.240 ;
    END
  END tl_u_uart_o[87]
  PIN tl_u_uart_o[88]
    DIRECTION OUTPUT ;
    USE SIGNAL ;
    ANTENNADIFFAREA 0.445500 ;
    PORT
      LAYER met3 ;
        RECT 0.000 40.840 4.000 41.440 ;
    END
  END tl_u_uart_o[88]
  PIN tl_u_uart_o[89]
    DIRECTION OUTPUT ;
    USE SIGNAL ;
    ANTENNADIFFAREA 0.445500 ;
    PORT
      LAYER met3 ;
        RECT 0.000 183.640 4.000 184.240 ;
    END
  END tl_u_uart_o[89]
  PIN tl_u_uart_o[8]
    DIRECTION OUTPUT ;
    USE SIGNAL ;
    ANTENNADIFFAREA 0.445500 ;
    PORT
      LAYER met3 ;
        RECT 1296.000 1237.640 1300.000 1238.240 ;
    END
  END tl_u_uart_o[8]
  PIN tl_u_uart_o[90]
    DIRECTION OUTPUT ;
    USE SIGNAL ;
    ANTENNADIFFAREA 0.445500 ;
    PORT
      LAYER met3 ;
        RECT 0.000 380.840 4.000 381.440 ;
    END
  END tl_u_uart_o[90]
  PIN tl_u_uart_o[91]
    DIRECTION OUTPUT ;
    USE SIGNAL ;
    ANTENNADIFFAREA 0.445500 ;
    PORT
      LAYER met3 ;
        RECT 0.000 411.440 4.000 412.040 ;
    END
  END tl_u_uart_o[91]
  PIN tl_u_uart_o[92]
    DIRECTION OUTPUT ;
    USE SIGNAL ;
    ANTENNADIFFAREA 0.445500 ;
    PORT
      LAYER met3 ;
        RECT 0.000 23.840 4.000 24.440 ;
    END
  END tl_u_uart_o[92]
  PIN tl_u_uart_o[93]
    DIRECTION OUTPUT ;
    USE SIGNAL ;
    ANTENNADIFFAREA 0.445500 ;
    PORT
      LAYER met3 ;
        RECT 1296.000 214.240 1300.000 214.840 ;
    END
  END tl_u_uart_o[93]
  PIN tl_u_uart_o[94]
    DIRECTION OUTPUT ;
    USE SIGNAL ;
    ANTENNADIFFAREA 0.445500 ;
    PORT
      LAYER met3 ;
        RECT 1296.000 421.640 1300.000 422.240 ;
    END
  END tl_u_uart_o[94]
  PIN tl_u_uart_o[95]
    DIRECTION OUTPUT ;
    USE SIGNAL ;
    ANTENNADIFFAREA 0.445500 ;
    PORT
      LAYER met3 ;
        RECT 1296.000 1023.440 1300.000 1024.040 ;
    END
  END tl_u_uart_o[95]
  PIN tl_u_uart_o[96]
    DIRECTION OUTPUT ;
    USE SIGNAL ;
    ANTENNADIFFAREA 0.445500 ;
    PORT
      LAYER met2 ;
        RECT 447.670 1296.000 447.950 1300.000 ;
    END
  END tl_u_uart_o[96]
  PIN tl_u_uart_o[97]
    DIRECTION OUTPUT ;
    USE SIGNAL ;
    ANTENNADIFFAREA 0.445500 ;
    PORT
      LAYER met3 ;
        RECT 1296.000 938.440 1300.000 939.040 ;
    END
  END tl_u_uart_o[97]
  PIN tl_u_uart_o[98]
    DIRECTION OUTPUT ;
    USE SIGNAL ;
    ANTENNADIFFAREA 0.445500 ;
    PORT
      LAYER met3 ;
        RECT 0.000 557.640 4.000 558.240 ;
    END
  END tl_u_uart_o[98]
  PIN tl_u_uart_o[99]
    DIRECTION OUTPUT ;
    USE SIGNAL ;
    ANTENNADIFFAREA 0.445500 ;
    PORT
      LAYER met2 ;
        RECT 534.610 1296.000 534.890 1300.000 ;
    END
  END tl_u_uart_o[99]
  PIN tl_u_uart_o[9]
    DIRECTION OUTPUT ;
    USE SIGNAL ;
    ANTENNADIFFAREA 0.445500 ;
    PORT
      LAYER met3 ;
        RECT 1296.000 822.840 1300.000 823.440 ;
    END
  END tl_u_uart_o[9]
  PIN tl_u_xbar_apb_i[0]
    DIRECTION INPUT ;
    USE SIGNAL ;
    ANTENNAGATEAREA 0.560700 ;
    ANTENNADIFFAREA 0.434700 ;
    PORT
      LAYER met3 ;
        RECT 0.000 146.240 4.000 146.840 ;
    END
  END tl_u_xbar_apb_i[0]
  PIN tl_u_xbar_apb_i[10]
    DIRECTION INPUT ;
    USE SIGNAL ;
    ANTENNAGATEAREA 0.682200 ;
    ANTENNADIFFAREA 0.434700 ;
    PORT
      LAYER met2 ;
        RECT 512.070 1296.000 512.350 1300.000 ;
    END
  END tl_u_xbar_apb_i[10]
  PIN tl_u_xbar_apb_i[11]
    DIRECTION INPUT ;
    USE SIGNAL ;
    ANTENNAGATEAREA 0.682200 ;
    ANTENNADIFFAREA 0.434700 ;
    PORT
      LAYER met3 ;
        RECT 1296.000 312.840 1300.000 313.440 ;
    END
  END tl_u_xbar_apb_i[11]
  PIN tl_u_xbar_apb_i[12]
    DIRECTION INPUT ;
    USE SIGNAL ;
    ANTENNAGATEAREA 0.682200 ;
    ANTENNADIFFAREA 0.434700 ;
    PORT
      LAYER met3 ;
        RECT 1296.000 833.040 1300.000 833.640 ;
    END
  END tl_u_xbar_apb_i[12]
  PIN tl_u_xbar_apb_i[13]
    DIRECTION INPUT ;
    USE SIGNAL ;
    ANTENNAGATEAREA 0.647700 ;
    ANTENNADIFFAREA 0.434700 ;
    PORT
      LAYER met3 ;
        RECT 1296.000 309.440 1300.000 310.040 ;
    END
  END tl_u_xbar_apb_i[13]
  PIN tl_u_xbar_apb_i[14]
    DIRECTION INPUT ;
    USE SIGNAL ;
    ANTENNAGATEAREA 0.682200 ;
    ANTENNADIFFAREA 0.434700 ;
    PORT
      LAYER met2 ;
        RECT 637.650 1296.000 637.930 1300.000 ;
    END
  END tl_u_xbar_apb_i[14]
  PIN tl_u_xbar_apb_i[15]
    DIRECTION INPUT ;
    USE SIGNAL ;
    ANTENNAGATEAREA 0.560700 ;
    ANTENNADIFFAREA 0.434700 ;
    PORT
      LAYER met3 ;
        RECT 1296.000 333.240 1300.000 333.840 ;
    END
  END tl_u_xbar_apb_i[15]
  PIN tl_u_xbar_apb_i[16]
    DIRECTION INPUT ;
    USE SIGNAL ;
    ANTENNAGATEAREA 0.647700 ;
    ANTENNADIFFAREA 0.434700 ;
    PORT
      LAYER met3 ;
        RECT 1296.000 1169.640 1300.000 1170.240 ;
    END
  END tl_u_xbar_apb_i[16]
  PIN tl_u_xbar_apb_i[17]
    DIRECTION INPUT ;
    USE SIGNAL ;
    ANTENNAGATEAREA 0.647700 ;
    ANTENNADIFFAREA 0.434700 ;
    PORT
      LAYER met3 ;
        RECT 1296.000 1108.440 1300.000 1109.040 ;
    END
  END tl_u_xbar_apb_i[17]
  PIN tl_u_xbar_apb_i[18]
    DIRECTION INPUT ;
    USE SIGNAL ;
    ANTENNAGATEAREA 0.682200 ;
    ANTENNADIFFAREA 0.434700 ;
    PORT
      LAYER met3 ;
        RECT 1296.000 635.840 1300.000 636.440 ;
    END
  END tl_u_xbar_apb_i[18]
  PIN tl_u_xbar_apb_i[19]
    DIRECTION INPUT ;
    USE SIGNAL ;
    ANTENNAGATEAREA 0.631200 ;
    ANTENNADIFFAREA 0.434700 ;
    PORT
      LAYER met3 ;
        RECT 1296.000 1088.040 1300.000 1088.640 ;
    END
  END tl_u_xbar_apb_i[19]
  PIN tl_u_xbar_apb_i[1]
    DIRECTION INPUT ;
    USE SIGNAL ;
    ANTENNAGATEAREA 0.682200 ;
    ANTENNADIFFAREA 0.434700 ;
    PORT
      LAYER met3 ;
        RECT 1296.000 829.640 1300.000 830.240 ;
    END
  END tl_u_xbar_apb_i[1]
  PIN tl_u_xbar_apb_i[20]
    DIRECTION INPUT ;
    USE SIGNAL ;
    ANTENNAGATEAREA 0.647700 ;
    ANTENNADIFFAREA 0.434700 ;
    PORT
      LAYER met3 ;
        RECT 1296.000 326.440 1300.000 327.040 ;
    END
  END tl_u_xbar_apb_i[20]
  PIN tl_u_xbar_apb_i[21]
    DIRECTION INPUT ;
    USE SIGNAL ;
    ANTENNAGATEAREA 0.682200 ;
    ANTENNADIFFAREA 0.434700 ;
    PORT
      LAYER met3 ;
        RECT 1296.000 292.440 1300.000 293.040 ;
    END
  END tl_u_xbar_apb_i[21]
  PIN tl_u_xbar_apb_i[22]
    DIRECTION INPUT ;
    USE SIGNAL ;
    ANTENNAGATEAREA 0.682200 ;
    ANTENNADIFFAREA 0.434700 ;
    PORT
      LAYER met2 ;
        RECT 640.870 1296.000 641.150 1300.000 ;
    END
  END tl_u_xbar_apb_i[22]
  PIN tl_u_xbar_apb_i[23]
    DIRECTION INPUT ;
    USE SIGNAL ;
    ANTENNAGATEAREA 0.647700 ;
    ANTENNADIFFAREA 0.434700 ;
    PORT
      LAYER met3 ;
        RECT 1296.000 1047.240 1300.000 1047.840 ;
    END
  END tl_u_xbar_apb_i[23]
  PIN tl_u_xbar_apb_i[24]
    DIRECTION INPUT ;
    USE SIGNAL ;
    ANTENNAGATEAREA 0.682200 ;
    ANTENNADIFFAREA 0.434700 ;
    PORT
      LAYER met3 ;
        RECT 1296.000 863.640 1300.000 864.240 ;
    END
  END tl_u_xbar_apb_i[24]
  PIN tl_u_xbar_apb_i[25]
    DIRECTION INPUT ;
    USE SIGNAL ;
    ANTENNAGATEAREA 0.682200 ;
    ANTENNADIFFAREA 0.434700 ;
    PORT
      LAYER met3 ;
        RECT 1296.000 683.440 1300.000 684.040 ;
    END
  END tl_u_xbar_apb_i[25]
  PIN tl_u_xbar_apb_i[26]
    DIRECTION INPUT ;
    USE SIGNAL ;
    ANTENNAGATEAREA 0.647700 ;
    ANTENNADIFFAREA 0.434700 ;
    PORT
      LAYER met3 ;
        RECT 1296.000 816.040 1300.000 816.640 ;
    END
  END tl_u_xbar_apb_i[26]
  PIN tl_u_xbar_apb_i[27]
    DIRECTION INPUT ;
    USE SIGNAL ;
    ANTENNAGATEAREA 0.593700 ;
    ANTENNADIFFAREA 0.434700 ;
    PORT
      LAYER met3 ;
        RECT 1296.000 295.840 1300.000 296.440 ;
    END
  END tl_u_xbar_apb_i[27]
  PIN tl_u_xbar_apb_i[28]
    DIRECTION INPUT ;
    USE SIGNAL ;
    ANTENNAGATEAREA 0.682200 ;
    ANTENNADIFFAREA 0.434700 ;
    PORT
      LAYER met3 ;
        RECT 1296.000 268.640 1300.000 269.240 ;
    END
  END tl_u_xbar_apb_i[28]
  PIN tl_u_xbar_apb_i[29]
    DIRECTION INPUT ;
    USE SIGNAL ;
    ANTENNAGATEAREA 0.647700 ;
    ANTENNADIFFAREA 0.434700 ;
    PORT
      LAYER met3 ;
        RECT 1296.000 1173.040 1300.000 1173.640 ;
    END
  END tl_u_xbar_apb_i[29]
  PIN tl_u_xbar_apb_i[2]
    DIRECTION INPUT ;
    USE SIGNAL ;
    ANTENNAGATEAREA 0.682200 ;
    ANTENNADIFFAREA 0.434700 ;
    PORT
      LAYER met3 ;
        RECT 1296.000 778.640 1300.000 779.240 ;
    END
  END tl_u_xbar_apb_i[2]
  PIN tl_u_xbar_apb_i[30]
    DIRECTION INPUT ;
    USE SIGNAL ;
    ANTENNAGATEAREA 0.647700 ;
    ANTENNADIFFAREA 0.434700 ;
    PORT
      LAYER met3 ;
        RECT 1296.000 244.840 1300.000 245.440 ;
    END
  END tl_u_xbar_apb_i[30]
  PIN tl_u_xbar_apb_i[31]
    DIRECTION INPUT ;
    USE SIGNAL ;
    ANTENNAGATEAREA 0.647700 ;
    ANTENNADIFFAREA 0.434700 ;
    PORT
      LAYER met2 ;
        RECT 634.430 1296.000 634.710 1300.000 ;
    END
  END tl_u_xbar_apb_i[31]
  PIN tl_u_xbar_apb_i[32]
    DIRECTION INPUT ;
    USE SIGNAL ;
    ANTENNAGATEAREA 0.647700 ;
    ANTENNADIFFAREA 0.434700 ;
    PORT
      LAYER met3 ;
        RECT 1296.000 278.840 1300.000 279.440 ;
    END
  END tl_u_xbar_apb_i[32]
  PIN tl_u_xbar_apb_i[33]
    DIRECTION INPUT ;
    USE SIGNAL ;
    ANTENNAGATEAREA 0.647700 ;
    ANTENNADIFFAREA 0.434700 ;
    PORT
      LAYER met3 ;
        RECT 1296.000 1241.040 1300.000 1241.640 ;
    END
  END tl_u_xbar_apb_i[33]
  PIN tl_u_xbar_apb_i[34]
    DIRECTION INPUT ;
    USE SIGNAL ;
    ANTENNAGATEAREA 0.560700 ;
    ANTENNADIFFAREA 0.434700 ;
    PORT
      LAYER met3 ;
        RECT 1296.000 659.640 1300.000 660.240 ;
    END
  END tl_u_xbar_apb_i[34]
  PIN tl_u_xbar_apb_i[35]
    DIRECTION INPUT ;
    USE SIGNAL ;
    ANTENNAGATEAREA 0.593700 ;
    ANTENNADIFFAREA 0.434700 ;
    PORT
      LAYER met3 ;
        RECT 1296.000 986.040 1300.000 986.640 ;
    END
  END tl_u_xbar_apb_i[35]
  PIN tl_u_xbar_apb_i[36]
    DIRECTION INPUT ;
    USE SIGNAL ;
    ANTENNAGATEAREA 0.631200 ;
    ANTENNADIFFAREA 0.434700 ;
    PORT
      LAYER met3 ;
        RECT 1296.000 1176.440 1300.000 1177.040 ;
    END
  END tl_u_xbar_apb_i[36]
  PIN tl_u_xbar_apb_i[37]
    DIRECTION INPUT ;
    USE SIGNAL ;
    ANTENNAGATEAREA 0.860700 ;
    ANTENNADIFFAREA 0.434700 ;
    PORT
      LAYER met3 ;
        RECT 1296.000 652.840 1300.000 653.440 ;
    END
  END tl_u_xbar_apb_i[37]
  PIN tl_u_xbar_apb_i[38]
    DIRECTION INPUT ;
    USE SIGNAL ;
    ANTENNAGATEAREA 0.682200 ;
    ANTENNADIFFAREA 0.434700 ;
    PORT
      LAYER met2 ;
        RECT 611.890 1296.000 612.170 1300.000 ;
    END
  END tl_u_xbar_apb_i[38]
  PIN tl_u_xbar_apb_i[39]
    DIRECTION INPUT ;
    USE SIGNAL ;
    ANTENNAGATEAREA 0.647700 ;
    ANTENNADIFFAREA 0.434700 ;
    PORT
      LAYER met3 ;
        RECT 1296.000 251.640 1300.000 252.240 ;
    END
  END tl_u_xbar_apb_i[39]
  PIN tl_u_xbar_apb_i[3]
    DIRECTION INPUT ;
    USE SIGNAL ;
    ANTENNAGATEAREA 0.593700 ;
    ANTENNADIFFAREA 0.434700 ;
    PORT
      LAYER met3 ;
        RECT 1296.000 1094.840 1300.000 1095.440 ;
    END
  END tl_u_xbar_apb_i[3]
  PIN tl_u_xbar_apb_i[40]
    DIRECTION INPUT ;
    USE SIGNAL ;
    ANTENNAGATEAREA 0.682200 ;
    ANTENNADIFFAREA 0.434700 ;
    PORT
      LAYER met3 ;
        RECT 1296.000 758.240 1300.000 758.840 ;
    END
  END tl_u_xbar_apb_i[40]
  PIN tl_u_xbar_apb_i[41]
    DIRECTION INPUT ;
    USE SIGNAL ;
    ANTENNAGATEAREA 0.593700 ;
    ANTENNADIFFAREA 0.434700 ;
    PORT
      LAYER met3 ;
        RECT 1296.000 785.440 1300.000 786.040 ;
    END
  END tl_u_xbar_apb_i[41]
  PIN tl_u_xbar_apb_i[42]
    DIRECTION INPUT ;
    USE SIGNAL ;
    ANTENNAGATEAREA 0.631200 ;
    ANTENNADIFFAREA 0.434700 ;
    PORT
      LAYER met3 ;
        RECT 1296.000 802.440 1300.000 803.040 ;
    END
  END tl_u_xbar_apb_i[42]
  PIN tl_u_xbar_apb_i[43]
    DIRECTION INPUT ;
    USE SIGNAL ;
    ANTENNAGATEAREA 0.647700 ;
    ANTENNADIFFAREA 0.434700 ;
    PORT
      LAYER met3 ;
        RECT 1296.000 329.840 1300.000 330.440 ;
    END
  END tl_u_xbar_apb_i[43]
  PIN tl_u_xbar_apb_i[44]
    DIRECTION INPUT ;
    USE SIGNAL ;
    ANTENNAGATEAREA 0.647700 ;
    ANTENNADIFFAREA 0.434700 ;
    PORT
      LAYER met3 ;
        RECT 1296.000 1179.840 1300.000 1180.440 ;
    END
  END tl_u_xbar_apb_i[44]
  PIN tl_u_xbar_apb_i[45]
    DIRECTION INPUT ;
    USE SIGNAL ;
    ANTENNAGATEAREA 0.647700 ;
    ANTENNADIFFAREA 0.434700 ;
    PORT
      LAYER met3 ;
        RECT 1296.000 819.440 1300.000 820.040 ;
    END
  END tl_u_xbar_apb_i[45]
  PIN tl_u_xbar_apb_i[46]
    DIRECTION INPUT ;
    USE SIGNAL ;
    ANTENNAGATEAREA 0.593700 ;
    ANTENNADIFFAREA 0.434700 ;
    PORT
      LAYER met3 ;
        RECT 1296.000 867.040 1300.000 867.640 ;
    END
  END tl_u_xbar_apb_i[46]
  PIN tl_u_xbar_apb_i[47]
    DIRECTION INPUT ;
    USE SIGNAL ;
    ANTENNAGATEAREA 0.647700 ;
    ANTENNADIFFAREA 0.434700 ;
    PORT
      LAYER met3 ;
        RECT 1296.000 1244.440 1300.000 1245.040 ;
    END
  END tl_u_xbar_apb_i[47]
  PIN tl_u_xbar_apb_i[48]
    DIRECTION INPUT ;
    USE SIGNAL ;
    ANTENNAGATEAREA 0.682200 ;
    ANTENNADIFFAREA 0.434700 ;
    PORT
      LAYER met2 ;
        RECT 550.710 1296.000 550.990 1300.000 ;
    END
  END tl_u_xbar_apb_i[48]
  PIN tl_u_xbar_apb_i[49]
    DIRECTION INPUT ;
    USE SIGNAL ;
    ANTENNAGATEAREA 0.647700 ;
    ANTENNADIFFAREA 0.434700 ;
    PORT
      LAYER met3 ;
        RECT 1296.000 680.040 1300.000 680.640 ;
    END
  END tl_u_xbar_apb_i[49]
  PIN tl_u_xbar_apb_i[4]
    DIRECTION INPUT ;
    USE SIGNAL ;
    ANTENNAGATEAREA 0.647700 ;
    ANTENNADIFFAREA 0.434700 ;
    PORT
      LAYER met3 ;
        RECT 1296.000 241.440 1300.000 242.040 ;
    END
  END tl_u_xbar_apb_i[4]
  PIN tl_u_xbar_apb_i[50]
    DIRECTION INPUT ;
    USE SIGNAL ;
    ANTENNAGATEAREA 1.286700 ;
    ANTENNADIFFAREA 0.434700 ;
    PORT
      LAYER met3 ;
        RECT 1296.000 255.040 1300.000 255.640 ;
    END
  END tl_u_xbar_apb_i[50]
  PIN tl_u_xbar_apb_i[51]
    DIRECTION INPUT ;
    USE SIGNAL ;
    ANTENNAGATEAREA 0.593700 ;
    ANTENNADIFFAREA 0.434700 ;
    PORT
      LAYER met3 ;
        RECT 1296.000 992.840 1300.000 993.440 ;
    END
  END tl_u_xbar_apb_i[51]
  PIN tl_u_xbar_apb_i[52]
    DIRECTION INPUT ;
    USE SIGNAL ;
    ANTENNAGATEAREA 0.593700 ;
    ANTENNADIFFAREA 0.434700 ;
    PORT
      LAYER met3 ;
        RECT 1296.000 1077.840 1300.000 1078.440 ;
    END
  END tl_u_xbar_apb_i[52]
  PIN tl_u_xbar_apb_i[53]
    DIRECTION INPUT ;
    USE SIGNAL ;
    ANTENNAGATEAREA 0.647700 ;
    ANTENNADIFFAREA 0.434700 ;
    PORT
      LAYER met2 ;
        RECT 589.350 1296.000 589.630 1300.000 ;
    END
  END tl_u_xbar_apb_i[53]
  PIN tl_u_xbar_apb_i[54]
    DIRECTION INPUT ;
    USE SIGNAL ;
    ANTENNAGATEAREA 0.860700 ;
    ANTENNADIFFAREA 0.434700 ;
    PORT
      LAYER met3 ;
        RECT 1296.000 639.240 1300.000 639.840 ;
    END
  END tl_u_xbar_apb_i[54]
  PIN tl_u_xbar_apb_i[55]
    DIRECTION INPUT ;
    USE SIGNAL ;
    ANTENNAGATEAREA 0.647700 ;
    ANTENNADIFFAREA 0.434700 ;
    PORT
      LAYER met3 ;
        RECT 1296.000 238.040 1300.000 238.640 ;
    END
  END tl_u_xbar_apb_i[55]
  PIN tl_u_xbar_apb_i[56]
    DIRECTION INPUT ;
    USE SIGNAL ;
    ANTENNAGATEAREA 0.860700 ;
    ANTENNADIFFAREA 0.434700 ;
    PORT
      LAYER met2 ;
        RECT 570.030 1296.000 570.310 1300.000 ;
    END
  END tl_u_xbar_apb_i[56]
  PIN tl_u_xbar_apb_i[57]
    DIRECTION INPUT ;
    USE SIGNAL ;
    ANTENNAGATEAREA 0.682200 ;
    ANTENNADIFFAREA 0.434700 ;
    PORT
      LAYER met3 ;
        RECT 1296.000 632.440 1300.000 633.040 ;
    END
  END tl_u_xbar_apb_i[57]
  PIN tl_u_xbar_apb_i[58]
    DIRECTION INPUT ;
    USE SIGNAL ;
    ANTENNAGATEAREA 0.593700 ;
    ANTENNADIFFAREA 0.434700 ;
    PORT
      LAYER met3 ;
        RECT 1296.000 1142.440 1300.000 1143.040 ;
    END
  END tl_u_xbar_apb_i[58]
  PIN tl_u_xbar_apb_i[59]
    DIRECTION INPUT ;
    USE SIGNAL ;
    ANTENNAGATEAREA 0.647700 ;
    ANTENNADIFFAREA 0.434700 ;
    PORT
      LAYER met3 ;
        RECT 1296.000 707.240 1300.000 707.840 ;
    END
  END tl_u_xbar_apb_i[59]
  PIN tl_u_xbar_apb_i[5]
    DIRECTION INPUT ;
    USE SIGNAL ;
    ANTENNAGATEAREA 0.631200 ;
    ANTENNADIFFAREA 0.434700 ;
    PORT
      LAYER met3 ;
        RECT 1296.000 1268.240 1300.000 1268.840 ;
    END
  END tl_u_xbar_apb_i[5]
  PIN tl_u_xbar_apb_i[60]
    DIRECTION INPUT ;
    USE SIGNAL ;
    ANTENNAGATEAREA 0.860700 ;
    ANTENNADIFFAREA 0.434700 ;
    PORT
      LAYER met2 ;
        RECT 631.210 1296.000 631.490 1300.000 ;
    END
  END tl_u_xbar_apb_i[60]
  PIN tl_u_xbar_apb_i[61]
    DIRECTION INPUT ;
    USE SIGNAL ;
    ANTENNAGATEAREA 0.593700 ;
    ANTENNADIFFAREA 0.434700 ;
    PORT
      LAYER met3 ;
        RECT 1296.000 1064.240 1300.000 1064.840 ;
    END
  END tl_u_xbar_apb_i[61]
  PIN tl_u_xbar_apb_i[62]
    DIRECTION INPUT ;
    USE SIGNAL ;
    ANTENNAGATEAREA 0.647700 ;
    ANTENNADIFFAREA 0.434700 ;
    PORT
      LAYER met3 ;
        RECT 1296.000 748.040 1300.000 748.640 ;
    END
  END tl_u_xbar_apb_i[62]
  PIN tl_u_xbar_apb_i[63]
    DIRECTION INPUT ;
    USE SIGNAL ;
    ANTENNAGATEAREA 0.631200 ;
    ANTENNADIFFAREA 0.434700 ;
    PORT
      LAYER met2 ;
        RECT 644.090 1296.000 644.370 1300.000 ;
    END
  END tl_u_xbar_apb_i[63]
  PIN tl_u_xbar_apb_i[64]
    DIRECTION INPUT ;
    USE SIGNAL ;
    ANTENNAGATEAREA 0.631200 ;
    ANTENNADIFFAREA 0.434700 ;
    PORT
      LAYER met3 ;
        RECT 1296.000 1183.240 1300.000 1183.840 ;
    END
  END tl_u_xbar_apb_i[64]
  PIN tl_u_xbar_apb_i[65]
    DIRECTION INPUT ;
    USE SIGNAL ;
    ANTENNAGATEAREA 0.647700 ;
    ANTENNADIFFAREA 0.434700 ;
    PORT
      LAYER met3 ;
        RECT 1296.000 877.240 1300.000 877.840 ;
    END
  END tl_u_xbar_apb_i[65]
  PIN tl_u_xbar_apb_i[6]
    DIRECTION INPUT ;
    USE SIGNAL ;
    ANTENNAGATEAREA 0.682200 ;
    ANTENNADIFFAREA 0.434700 ;
    PORT
      LAYER met3 ;
        RECT 1296.000 737.840 1300.000 738.440 ;
    END
  END tl_u_xbar_apb_i[6]
  PIN tl_u_xbar_apb_i[7]
    DIRECTION INPUT ;
    USE SIGNAL ;
    ANTENNAGATEAREA 0.631200 ;
    ANTENNADIFFAREA 0.434700 ;
    PORT
      LAYER met3 ;
        RECT 1296.000 1186.640 1300.000 1187.240 ;
    END
  END tl_u_xbar_apb_i[7]
  PIN tl_u_xbar_apb_i[8]
    DIRECTION INPUT ;
    USE SIGNAL ;
    ANTENNAGATEAREA 0.647700 ;
    ANTENNADIFFAREA 0.434700 ;
    PORT
      LAYER met3 ;
        RECT 1296.000 234.640 1300.000 235.240 ;
    END
  END tl_u_xbar_apb_i[8]
  PIN tl_u_xbar_apb_i[9]
    DIRECTION INPUT ;
    USE SIGNAL ;
    ANTENNAGATEAREA 0.631200 ;
    ANTENNADIFFAREA 0.434700 ;
    PORT
      LAYER met3 ;
        RECT 1296.000 948.640 1300.000 949.240 ;
    END
  END tl_u_xbar_apb_i[9]
  PIN tl_u_xbar_apb_o[0]
    DIRECTION OUTPUT ;
    USE SIGNAL ;
    ANTENNADIFFAREA 0.445500 ;
    PORT
      LAYER met2 ;
        RECT 418.690 1296.000 418.970 1300.000 ;
    END
  END tl_u_xbar_apb_o[0]
  PIN tl_u_xbar_apb_o[100]
    DIRECTION OUTPUT ;
    USE SIGNAL ;
    ANTENNADIFFAREA 0.445500 ;
    PORT
      LAYER met2 ;
        RECT 334.970 1296.000 335.250 1300.000 ;
    END
  END tl_u_xbar_apb_o[100]
  PIN tl_u_xbar_apb_o[101]
    DIRECTION OUTPUT ;
    USE SIGNAL ;
    ANTENNADIFFAREA 0.445500 ;
    PORT
      LAYER met3 ;
        RECT 1296.000 476.040 1300.000 476.640 ;
    END
  END tl_u_xbar_apb_o[101]
  PIN tl_u_xbar_apb_o[102]
    DIRECTION OUTPUT ;
    USE SIGNAL ;
    ANTENNADIFFAREA 0.445500 ;
    PORT
      LAYER met2 ;
        RECT 383.270 1296.000 383.550 1300.000 ;
    END
  END tl_u_xbar_apb_o[102]
  PIN tl_u_xbar_apb_o[103]
    DIRECTION OUTPUT ;
    USE SIGNAL ;
    ANTENNADIFFAREA 0.445500 ;
    PORT
      LAYER met3 ;
        RECT 1296.000 302.640 1300.000 303.240 ;
    END
  END tl_u_xbar_apb_o[103]
  PIN tl_u_xbar_apb_o[104]
    DIRECTION OUTPUT ;
    USE SIGNAL ;
    ANTENNADIFFAREA 0.445500 ;
    PORT
      LAYER met3 ;
        RECT 1296.000 578.040 1300.000 578.640 ;
    END
  END tl_u_xbar_apb_o[104]
  PIN tl_u_xbar_apb_o[105]
    DIRECTION OUTPUT ;
    USE SIGNAL ;
    ANTENNADIFFAREA 0.445500 ;
    PORT
      LAYER met2 ;
        RECT 508.850 1296.000 509.130 1300.000 ;
    END
  END tl_u_xbar_apb_o[105]
  PIN tl_u_xbar_apb_o[106]
    DIRECTION OUTPUT ;
    USE SIGNAL ;
    ANTENNADIFFAREA 0.445500 ;
    PORT
      LAYER met3 ;
        RECT 0.000 547.440 4.000 548.040 ;
    END
  END tl_u_xbar_apb_o[106]
  PIN tl_u_xbar_apb_o[107]
    DIRECTION OUTPUT ;
    USE SIGNAL ;
    ANTENNADIFFAREA 0.445500 ;
    PORT
      LAYER met2 ;
        RECT 367.170 1296.000 367.450 1300.000 ;
    END
  END tl_u_xbar_apb_o[107]
  PIN tl_u_xbar_apb_o[108]
    DIRECTION OUTPUT ;
    USE SIGNAL ;
    ANTENNADIFFAREA 0.445500 ;
    PORT
      LAYER met3 ;
        RECT 0.000 190.440 4.000 191.040 ;
    END
  END tl_u_xbar_apb_o[108]
  PIN tl_u_xbar_apb_o[109]
    DIRECTION OUTPUT ;
    USE SIGNAL ;
    ANTENNADIFFAREA 0.445500 ;
    PORT
      LAYER met3 ;
        RECT 0.000 210.840 4.000 211.440 ;
    END
  END tl_u_xbar_apb_o[109]
  PIN tl_u_xbar_apb_o[10]
    DIRECTION OUTPUT ;
    USE SIGNAL ;
    ANTENNADIFFAREA 0.445500 ;
    PORT
      LAYER met3 ;
        RECT 0.000 285.640 4.000 286.240 ;
    END
  END tl_u_xbar_apb_o[10]
  PIN tl_u_xbar_apb_o[11]
    DIRECTION OUTPUT ;
    USE SIGNAL ;
    ANTENNADIFFAREA 0.445500 ;
    PORT
      LAYER met3 ;
        RECT 1296.000 448.840 1300.000 449.440 ;
    END
  END tl_u_xbar_apb_o[11]
  PIN tl_u_xbar_apb_o[12]
    DIRECTION OUTPUT ;
    USE SIGNAL ;
    ANTENNADIFFAREA 0.445500 ;
    PORT
      LAYER met2 ;
        RECT 386.490 1296.000 386.770 1300.000 ;
    END
  END tl_u_xbar_apb_o[12]
  PIN tl_u_xbar_apb_o[13]
    DIRECTION OUTPUT ;
    USE SIGNAL ;
    ANTENNADIFFAREA 0.445500 ;
    PORT
      LAYER met3 ;
        RECT 1296.000 1057.440 1300.000 1058.040 ;
    END
  END tl_u_xbar_apb_o[13]
  PIN tl_u_xbar_apb_o[14]
    DIRECTION OUTPUT ;
    USE SIGNAL ;
    ANTENNADIFFAREA 0.445500 ;
    PORT
      LAYER met3 ;
        RECT 0.000 217.640 4.000 218.240 ;
    END
  END tl_u_xbar_apb_o[14]
  PIN tl_u_xbar_apb_o[15]
    DIRECTION OUTPUT ;
    USE SIGNAL ;
    ANTENNADIFFAREA 0.445500 ;
    PORT
      LAYER met3 ;
        RECT 0.000 292.440 4.000 293.040 ;
    END
  END tl_u_xbar_apb_o[15]
  PIN tl_u_xbar_apb_o[16]
    DIRECTION OUTPUT ;
    USE SIGNAL ;
    ANTENNADIFFAREA 0.445500 ;
    PORT
      LAYER met3 ;
        RECT 1296.000 550.840 1300.000 551.440 ;
    END
  END tl_u_xbar_apb_o[16]
  PIN tl_u_xbar_apb_o[17]
    DIRECTION OUTPUT ;
    USE SIGNAL ;
    ANTENNADIFFAREA 0.445500 ;
    PORT
      LAYER met3 ;
        RECT 1296.000 761.640 1300.000 762.240 ;
    END
  END tl_u_xbar_apb_o[17]
  PIN tl_u_xbar_apb_o[18]
    DIRECTION OUTPUT ;
    USE SIGNAL ;
    ANTENNADIFFAREA 0.445500 ;
    PORT
      LAYER met3 ;
        RECT 1296.000 856.840 1300.000 857.440 ;
    END
  END tl_u_xbar_apb_o[18]
  PIN tl_u_xbar_apb_o[19]
    DIRECTION OUTPUT ;
    USE SIGNAL ;
    ANTENNADIFFAREA 0.445500 ;
    PORT
      LAYER met2 ;
        RECT 495.970 1296.000 496.250 1300.000 ;
    END
  END tl_u_xbar_apb_o[19]
  PIN tl_u_xbar_apb_o[1]
    DIRECTION OUTPUT ;
    USE SIGNAL ;
    ANTENNADIFFAREA 0.445500 ;
    PORT
      LAYER met2 ;
        RECT 344.630 1296.000 344.910 1300.000 ;
    END
  END tl_u_xbar_apb_o[1]
  PIN tl_u_xbar_apb_o[20]
    DIRECTION OUTPUT ;
    USE SIGNAL ;
    ANTENNADIFFAREA 0.445500 ;
    PORT
      LAYER met3 ;
        RECT 0.000 448.840 4.000 449.440 ;
    END
  END tl_u_xbar_apb_o[20]
  PIN tl_u_xbar_apb_o[21]
    DIRECTION OUTPUT ;
    USE SIGNAL ;
    ANTENNADIFFAREA 0.445500 ;
    PORT
      LAYER met3 ;
        RECT 1296.000 411.440 1300.000 412.040 ;
    END
  END tl_u_xbar_apb_o[21]
  PIN tl_u_xbar_apb_o[22]
    DIRECTION OUTPUT ;
    USE SIGNAL ;
    ANTENNADIFFAREA 0.445500 ;
    PORT
      LAYER met3 ;
        RECT 1296.000 1122.040 1300.000 1122.640 ;
    END
  END tl_u_xbar_apb_o[22]
  PIN tl_u_xbar_apb_o[23]
    DIRECTION OUTPUT ;
    USE SIGNAL ;
    ANTENNADIFFAREA 0.445500 ;
    PORT
      LAYER met3 ;
        RECT 0.000 316.240 4.000 316.840 ;
    END
  END tl_u_xbar_apb_o[23]
  PIN tl_u_xbar_apb_o[24]
    DIRECTION OUTPUT ;
    USE SIGNAL ;
    ANTENNADIFFAREA 0.445500 ;
    PORT
      LAYER met2 ;
        RECT 524.950 1296.000 525.230 1300.000 ;
    END
  END tl_u_xbar_apb_o[24]
  PIN tl_u_xbar_apb_o[25]
    DIRECTION OUTPUT ;
    USE SIGNAL ;
    ANTENNADIFFAREA 0.445500 ;
    PORT
      LAYER met3 ;
        RECT 0.000 578.040 4.000 578.640 ;
    END
  END tl_u_xbar_apb_o[25]
  PIN tl_u_xbar_apb_o[26]
    DIRECTION OUTPUT ;
    USE SIGNAL ;
    ANTENNADIFFAREA 0.445500 ;
    PORT
      LAYER met2 ;
        RECT 521.730 1296.000 522.010 1300.000 ;
    END
  END tl_u_xbar_apb_o[26]
  PIN tl_u_xbar_apb_o[27]
    DIRECTION OUTPUT ;
    USE SIGNAL ;
    ANTENNADIFFAREA 0.445500 ;
    PORT
      LAYER met3 ;
        RECT 0.000 567.840 4.000 568.440 ;
    END
  END tl_u_xbar_apb_o[27]
  PIN tl_u_xbar_apb_o[28]
    DIRECTION OUTPUT ;
    USE SIGNAL ;
    ANTENNADIFFAREA 0.445500 ;
    PORT
      LAYER met3 ;
        RECT 1296.000 319.640 1300.000 320.240 ;
    END
  END tl_u_xbar_apb_o[28]
  PIN tl_u_xbar_apb_o[29]
    DIRECTION OUTPUT ;
    USE SIGNAL ;
    ANTENNADIFFAREA 0.445500 ;
    PORT
      LAYER met3 ;
        RECT 0.000 153.040 4.000 153.640 ;
    END
  END tl_u_xbar_apb_o[29]
  PIN tl_u_xbar_apb_o[2]
    DIRECTION OUTPUT ;
    USE SIGNAL ;
    ANTENNADIFFAREA 0.445500 ;
    PORT
      LAYER met2 ;
        RECT 528.170 1296.000 528.450 1300.000 ;
    END
  END tl_u_xbar_apb_o[2]
  PIN tl_u_xbar_apb_o[30]
    DIRECTION OUTPUT ;
    USE SIGNAL ;
    ANTENNADIFFAREA 0.445500 ;
    PORT
      LAYER met3 ;
        RECT 1296.000 1026.840 1300.000 1027.440 ;
    END
  END tl_u_xbar_apb_o[30]
  PIN tl_u_xbar_apb_o[31]
    DIRECTION OUTPUT ;
    USE SIGNAL ;
    ANTENNADIFFAREA 0.445500 ;
    PORT
      LAYER met3 ;
        RECT 1296.000 428.440 1300.000 429.040 ;
    END
  END tl_u_xbar_apb_o[31]
  PIN tl_u_xbar_apb_o[32]
    DIRECTION OUTPUT ;
    USE SIGNAL ;
    ANTENNADIFFAREA 0.445500 ;
    PORT
      LAYER met3 ;
        RECT 1296.000 540.640 1300.000 541.240 ;
    END
  END tl_u_xbar_apb_o[32]
  PIN tl_u_xbar_apb_o[33]
    DIRECTION OUTPUT ;
    USE SIGNAL ;
    ANTENNADIFFAREA 0.445500 ;
    PORT
      LAYER met3 ;
        RECT 0.000 401.240 4.000 401.840 ;
    END
  END tl_u_xbar_apb_o[33]
  PIN tl_u_xbar_apb_o[34]
    DIRECTION OUTPUT ;
    USE SIGNAL ;
    ANTENNADIFFAREA 0.445500 ;
    PORT
      LAYER met2 ;
        RECT 608.670 1296.000 608.950 1300.000 ;
    END
  END tl_u_xbar_apb_o[34]
  PIN tl_u_xbar_apb_o[35]
    DIRECTION OUTPUT ;
    USE SIGNAL ;
    ANTENNADIFFAREA 0.445500 ;
    PORT
      LAYER met3 ;
        RECT 1296.000 482.840 1300.000 483.440 ;
    END
  END tl_u_xbar_apb_o[35]
  PIN tl_u_xbar_apb_o[36]
    DIRECTION OUTPUT ;
    USE SIGNAL ;
    ANTENNADIFFAREA 0.445500 ;
    PORT
      LAYER met2 ;
        RECT 463.770 1296.000 464.050 1300.000 ;
    END
  END tl_u_xbar_apb_o[36]
  PIN tl_u_xbar_apb_o[37]
    DIRECTION OUTPUT ;
    USE SIGNAL ;
    ANTENNADIFFAREA 0.445500 ;
    PORT
      LAYER met3 ;
        RECT 1296.000 360.440 1300.000 361.040 ;
    END
  END tl_u_xbar_apb_o[37]
  PIN tl_u_xbar_apb_o[38]
    DIRECTION OUTPUT ;
    USE SIGNAL ;
    ANTENNADIFFAREA 0.445500 ;
    PORT
      LAYER met3 ;
        RECT 0.000 384.240 4.000 384.840 ;
    END
  END tl_u_xbar_apb_o[38]
  PIN tl_u_xbar_apb_o[39]
    DIRECTION OUTPUT ;
    USE SIGNAL ;
    ANTENNADIFFAREA 0.445500 ;
    PORT
      LAYER met3 ;
        RECT 1296.000 557.640 1300.000 558.240 ;
    END
  END tl_u_xbar_apb_o[39]
  PIN tl_u_xbar_apb_o[3]
    DIRECTION OUTPUT ;
    USE SIGNAL ;
    ANTENNADIFFAREA 0.445500 ;
    PORT
      LAYER met3 ;
        RECT 1296.000 520.240 1300.000 520.840 ;
    END
  END tl_u_xbar_apb_o[3]
  PIN tl_u_xbar_apb_o[40]
    DIRECTION OUTPUT ;
    USE SIGNAL ;
    ANTENNADIFFAREA 0.445500 ;
    PORT
      LAYER met2 ;
        RECT 360.730 1296.000 361.010 1300.000 ;
    END
  END tl_u_xbar_apb_o[40]
  PIN tl_u_xbar_apb_o[41]
    DIRECTION OUTPUT ;
    USE SIGNAL ;
    ANTENNADIFFAREA 0.445500 ;
    PORT
      LAYER met3 ;
        RECT 1296.000 472.640 1300.000 473.240 ;
    END
  END tl_u_xbar_apb_o[41]
  PIN tl_u_xbar_apb_o[42]
    DIRECTION OUTPUT ;
    USE SIGNAL ;
    ANTENNADIFFAREA 0.445500 ;
    PORT
      LAYER met3 ;
        RECT 1296.000 615.440 1300.000 616.040 ;
    END
  END tl_u_xbar_apb_o[42]
  PIN tl_u_xbar_apb_o[43]
    DIRECTION OUTPUT ;
    USE SIGNAL ;
    ANTENNADIFFAREA 0.445500 ;
    PORT
      LAYER met2 ;
        RECT 415.470 1296.000 415.750 1300.000 ;
    END
  END tl_u_xbar_apb_o[43]
  PIN tl_u_xbar_apb_o[44]
    DIRECTION OUTPUT ;
    USE SIGNAL ;
    ANTENNADIFFAREA 0.445500 ;
    PORT
      LAYER met2 ;
        RECT 466.990 1296.000 467.270 1300.000 ;
    END
  END tl_u_xbar_apb_o[44]
  PIN tl_u_xbar_apb_o[45]
    DIRECTION OUTPUT ;
    USE SIGNAL ;
    ANTENNADIFFAREA 0.445500 ;
    PORT
      LAYER met3 ;
        RECT 1296.000 567.840 1300.000 568.440 ;
    END
  END tl_u_xbar_apb_o[45]
  PIN tl_u_xbar_apb_o[46]
    DIRECTION OUTPUT ;
    USE SIGNAL ;
    ANTENNADIFFAREA 0.445500 ;
    PORT
      LAYER met3 ;
        RECT 1296.000 890.840 1300.000 891.440 ;
    END
  END tl_u_xbar_apb_o[46]
  PIN tl_u_xbar_apb_o[47]
    DIRECTION OUTPUT ;
    USE SIGNAL ;
    ANTENNADIFFAREA 0.445500 ;
    PORT
      LAYER met2 ;
        RECT 341.410 1296.000 341.690 1300.000 ;
    END
  END tl_u_xbar_apb_o[47]
  PIN tl_u_xbar_apb_o[48]
    DIRECTION OUTPUT ;
    USE SIGNAL ;
    ANTENNADIFFAREA 0.445500 ;
    PORT
      LAYER met2 ;
        RECT 325.310 1296.000 325.590 1300.000 ;
    END
  END tl_u_xbar_apb_o[48]
  PIN tl_u_xbar_apb_o[49]
    DIRECTION OUTPUT ;
    USE SIGNAL ;
    ANTENNADIFFAREA 0.445500 ;
    PORT
      LAYER met2 ;
        RECT 376.830 1296.000 377.110 1300.000 ;
    END
  END tl_u_xbar_apb_o[49]
  PIN tl_u_xbar_apb_o[4]
    DIRECTION OUTPUT ;
    USE SIGNAL ;
    ANTENNADIFFAREA 0.445500 ;
    PORT
      LAYER met3 ;
        RECT 1296.000 544.040 1300.000 544.640 ;
    END
  END tl_u_xbar_apb_o[4]
  PIN tl_u_xbar_apb_o[50]
    DIRECTION OUTPUT ;
    USE SIGNAL ;
    ANTENNADIFFAREA 0.445500 ;
    PORT
      LAYER met3 ;
        RECT 1296.000 598.440 1300.000 599.040 ;
    END
  END tl_u_xbar_apb_o[50]
  PIN tl_u_xbar_apb_o[51]
    DIRECTION OUTPUT ;
    USE SIGNAL ;
    ANTENNADIFFAREA 0.445500 ;
    PORT
      LAYER met2 ;
        RECT 505.630 1296.000 505.910 1300.000 ;
    END
  END tl_u_xbar_apb_o[51]
  PIN tl_u_xbar_apb_o[52]
    DIRECTION OUTPUT ;
    USE SIGNAL ;
    ANTENNADIFFAREA 0.445500 ;
    PORT
      LAYER met3 ;
        RECT 1296.000 224.440 1300.000 225.040 ;
    END
  END tl_u_xbar_apb_o[52]
  PIN tl_u_xbar_apb_o[53]
    DIRECTION OUTPUT ;
    USE SIGNAL ;
    ANTENNADIFFAREA 0.445500 ;
    PORT
      LAYER met3 ;
        RECT 1296.000 435.240 1300.000 435.840 ;
    END
  END tl_u_xbar_apb_o[53]
  PIN tl_u_xbar_apb_o[54]
    DIRECTION OUTPUT ;
    USE SIGNAL ;
    ANTENNADIFFAREA 0.445500 ;
    PORT
      LAYER met2 ;
        RECT 576.470 1296.000 576.750 1300.000 ;
    END
  END tl_u_xbar_apb_o[54]
  PIN tl_u_xbar_apb_o[55]
    DIRECTION OUTPUT ;
    USE SIGNAL ;
    ANTENNADIFFAREA 0.445500 ;
    PORT
      LAYER met2 ;
        RECT 624.770 1296.000 625.050 1300.000 ;
    END
  END tl_u_xbar_apb_o[55]
  PIN tl_u_xbar_apb_o[56]
    DIRECTION OUTPUT ;
    USE SIGNAL ;
    ANTENNADIFFAREA 0.445500 ;
    PORT
      LAYER met2 ;
        RECT 582.910 1296.000 583.190 1300.000 ;
    END
  END tl_u_xbar_apb_o[56]
  PIN tl_u_xbar_apb_o[57]
    DIRECTION OUTPUT ;
    USE SIGNAL ;
    ANTENNADIFFAREA 0.445500 ;
    PORT
      LAYER met2 ;
        RECT 409.030 1296.000 409.310 1300.000 ;
    END
  END tl_u_xbar_apb_o[57]
  PIN tl_u_xbar_apb_o[58]
    DIRECTION OUTPUT ;
    USE SIGNAL ;
    ANTENNADIFFAREA 0.445500 ;
    PORT
      LAYER met3 ;
        RECT 1296.000 1135.640 1300.000 1136.240 ;
    END
  END tl_u_xbar_apb_o[58]
  PIN tl_u_xbar_apb_o[59]
    DIRECTION OUTPUT ;
    USE SIGNAL ;
    ANTENNADIFFAREA 0.445500 ;
    PORT
      LAYER met3 ;
        RECT 1296.000 503.240 1300.000 503.840 ;
    END
  END tl_u_xbar_apb_o[59]
  PIN tl_u_xbar_apb_o[5]
    DIRECTION OUTPUT ;
    USE SIGNAL ;
    ANTENNADIFFAREA 0.445500 ;
    PORT
      LAYER met2 ;
        RECT 653.750 1296.000 654.030 1300.000 ;
    END
  END tl_u_xbar_apb_o[5]
  PIN tl_u_xbar_apb_o[60]
    DIRECTION OUTPUT ;
    USE SIGNAL ;
    ANTENNADIFFAREA 0.445500 ;
    PORT
      LAYER met3 ;
        RECT 1296.000 1098.240 1300.000 1098.840 ;
    END
  END tl_u_xbar_apb_o[60]
  PIN tl_u_xbar_apb_o[61]
    DIRECTION OUTPUT ;
    USE SIGNAL ;
    ANTENNADIFFAREA 0.445500 ;
    PORT
      LAYER met3 ;
        RECT 0.000 506.640 4.000 507.240 ;
    END
  END tl_u_xbar_apb_o[61]
  PIN tl_u_xbar_apb_o[62]
    DIRECTION OUTPUT ;
    USE SIGNAL ;
    ANTENNADIFFAREA 0.445500 ;
    PORT
      LAYER met3 ;
        RECT 0.000 214.240 4.000 214.840 ;
    END
  END tl_u_xbar_apb_o[62]
  PIN tl_u_xbar_apb_o[63]
    DIRECTION OUTPUT ;
    USE SIGNAL ;
    ANTENNADIFFAREA 0.445500 ;
    PORT
      LAYER met3 ;
        RECT 0.000 241.440 4.000 242.040 ;
    END
  END tl_u_xbar_apb_o[63]
  PIN tl_u_xbar_apb_o[64]
    DIRECTION OUTPUT ;
    USE SIGNAL ;
    ANTENNADIFFAREA 0.445500 ;
    PORT
      LAYER met3 ;
        RECT 0.000 187.040 4.000 187.640 ;
    END
  END tl_u_xbar_apb_o[64]
  PIN tl_u_xbar_apb_o[65]
    DIRECTION OUTPUT ;
    USE SIGNAL ;
    ANTENNADIFFAREA 0.445500 ;
    PORT
      LAYER met3 ;
        RECT 0.000 360.440 4.000 361.040 ;
    END
  END tl_u_xbar_apb_o[65]
  PIN tl_u_xbar_apb_o[66]
    DIRECTION OUTPUT ;
    USE SIGNAL ;
    ANTENNADIFFAREA 0.445500 ;
    PORT
      LAYER met3 ;
        RECT 0.000 139.440 4.000 140.040 ;
    END
  END tl_u_xbar_apb_o[66]
  PIN tl_u_xbar_apb_o[67]
    DIRECTION OUTPUT ;
    USE SIGNAL ;
    ANTENNADIFFAREA 0.445500 ;
    PORT
      LAYER met3 ;
        RECT 0.000 435.240 4.000 435.840 ;
    END
  END tl_u_xbar_apb_o[67]
  PIN tl_u_xbar_apb_o[68]
    DIRECTION OUTPUT ;
    USE SIGNAL ;
    ANTENNADIFFAREA 0.445500 ;
    PORT
      LAYER met3 ;
        RECT 0.000 248.240 4.000 248.840 ;
    END
  END tl_u_xbar_apb_o[68]
  PIN tl_u_xbar_apb_o[69]
    DIRECTION OUTPUT ;
    USE SIGNAL ;
    ANTENNADIFFAREA 0.445500 ;
    PORT
      LAYER met3 ;
        RECT 0.000 64.640 4.000 65.240 ;
    END
  END tl_u_xbar_apb_o[69]
  PIN tl_u_xbar_apb_o[6]
    DIRECTION OUTPUT ;
    USE SIGNAL ;
    ANTENNADIFFAREA 0.445500 ;
    PORT
      LAYER met2 ;
        RECT 347.850 1296.000 348.130 1300.000 ;
    END
  END tl_u_xbar_apb_o[6]
  PIN tl_u_xbar_apb_o[70]
    DIRECTION OUTPUT ;
    USE SIGNAL ;
    ANTENNADIFFAREA 0.445500 ;
    PORT
      LAYER met3 ;
        RECT 0.000 561.040 4.000 561.640 ;
    END
  END tl_u_xbar_apb_o[70]
  PIN tl_u_xbar_apb_o[71]
    DIRECTION OUTPUT ;
    USE SIGNAL ;
    ANTENNADIFFAREA 0.445500 ;
    PORT
      LAYER met3 ;
        RECT 0.000 6.840 4.000 7.440 ;
    END
  END tl_u_xbar_apb_o[71]
  PIN tl_u_xbar_apb_o[72]
    DIRECTION OUTPUT ;
    USE SIGNAL ;
    ANTENNADIFFAREA 0.445500 ;
    PORT
      LAYER met3 ;
        RECT 0.000 289.040 4.000 289.640 ;
    END
  END tl_u_xbar_apb_o[72]
  PIN tl_u_xbar_apb_o[73]
    DIRECTION OUTPUT ;
    USE SIGNAL ;
    ANTENNADIFFAREA 0.445500 ;
    PORT
      LAYER met3 ;
        RECT 0.000 17.040 4.000 17.640 ;
    END
  END tl_u_xbar_apb_o[73]
  PIN tl_u_xbar_apb_o[74]
    DIRECTION OUTPUT ;
    USE SIGNAL ;
    ANTENNADIFFAREA 0.445500 ;
    PORT
      LAYER met3 ;
        RECT 0.000 221.040 4.000 221.640 ;
    END
  END tl_u_xbar_apb_o[74]
  PIN tl_u_xbar_apb_o[75]
    DIRECTION OUTPUT ;
    USE SIGNAL ;
    ANTENNADIFFAREA 0.445500 ;
    PORT
      LAYER met3 ;
        RECT 0.000 180.240 4.000 180.840 ;
    END
  END tl_u_xbar_apb_o[75]
  PIN tl_u_xbar_apb_o[76]
    DIRECTION OUTPUT ;
    USE SIGNAL ;
    ANTENNADIFFAREA 0.445500 ;
    PORT
      LAYER met3 ;
        RECT 0.000 98.640 4.000 99.240 ;
    END
  END tl_u_xbar_apb_o[76]
  PIN tl_u_xbar_apb_o[77]
    DIRECTION OUTPUT ;
    USE SIGNAL ;
    ANTENNADIFFAREA 0.445500 ;
    PORT
      LAYER met3 ;
        RECT 0.000 445.440 4.000 446.040 ;
    END
  END tl_u_xbar_apb_o[77]
  PIN tl_u_xbar_apb_o[78]
    DIRECTION OUTPUT ;
    USE SIGNAL ;
    ANTENNADIFFAREA 0.445500 ;
    PORT
      LAYER met3 ;
        RECT 0.000 95.240 4.000 95.840 ;
    END
  END tl_u_xbar_apb_o[78]
  PIN tl_u_xbar_apb_o[79]
    DIRECTION OUTPUT ;
    USE SIGNAL ;
    ANTENNADIFFAREA 0.445500 ;
    PORT
      LAYER met3 ;
        RECT 0.000 275.440 4.000 276.040 ;
    END
  END tl_u_xbar_apb_o[79]
  PIN tl_u_xbar_apb_o[7]
    DIRECTION OUTPUT ;
    USE SIGNAL ;
    ANTENNADIFFAREA 0.445500 ;
    PORT
      LAYER met3 ;
        RECT 1296.000 510.040 1300.000 510.640 ;
    END
  END tl_u_xbar_apb_o[7]
  PIN tl_u_xbar_apb_o[80]
    DIRECTION OUTPUT ;
    USE SIGNAL ;
    ANTENNADIFFAREA 0.445500 ;
    PORT
      LAYER met3 ;
        RECT 0.000 85.040 4.000 85.640 ;
    END
  END tl_u_xbar_apb_o[80]
  PIN tl_u_xbar_apb_o[81]
    DIRECTION OUTPUT ;
    USE SIGNAL ;
    ANTENNADIFFAREA 0.445500 ;
    PORT
      LAYER met3 ;
        RECT 0.000 166.640 4.000 167.240 ;
    END
  END tl_u_xbar_apb_o[81]
  PIN tl_u_xbar_apb_o[82]
    DIRECTION OUTPUT ;
    USE SIGNAL ;
    ANTENNADIFFAREA 0.445500 ;
    PORT
      LAYER met3 ;
        RECT 0.000 588.240 4.000 588.840 ;
    END
  END tl_u_xbar_apb_o[82]
  PIN tl_u_xbar_apb_o[83]
    DIRECTION OUTPUT ;
    USE SIGNAL ;
    ANTENNADIFFAREA 0.445500 ;
    PORT
      LAYER met3 ;
        RECT 0.000 496.440 4.000 497.040 ;
    END
  END tl_u_xbar_apb_o[83]
  PIN tl_u_xbar_apb_o[84]
    DIRECTION OUTPUT ;
    USE SIGNAL ;
    ANTENNADIFFAREA 0.445500 ;
    PORT
      LAYER met3 ;
        RECT 0.000 520.240 4.000 520.840 ;
    END
  END tl_u_xbar_apb_o[84]
  PIN tl_u_xbar_apb_o[85]
    DIRECTION OUTPUT ;
    USE SIGNAL ;
    ANTENNADIFFAREA 0.445500 ;
    PORT
      LAYER met3 ;
        RECT 0.000 68.040 4.000 68.640 ;
    END
  END tl_u_xbar_apb_o[85]
  PIN tl_u_xbar_apb_o[86]
    DIRECTION OUTPUT ;
    USE SIGNAL ;
    ANTENNADIFFAREA 0.445500 ;
    PORT
      LAYER met2 ;
        RECT 331.750 1296.000 332.030 1300.000 ;
    END
  END tl_u_xbar_apb_o[86]
  PIN tl_u_xbar_apb_o[87]
    DIRECTION OUTPUT ;
    USE SIGNAL ;
    ANTENNADIFFAREA 0.445500 ;
    PORT
      LAYER met2 ;
        RECT 421.910 1296.000 422.190 1300.000 ;
    END
  END tl_u_xbar_apb_o[87]
  PIN tl_u_xbar_apb_o[88]
    DIRECTION OUTPUT ;
    USE SIGNAL ;
    ANTENNADIFFAREA 0.445500 ;
    PORT
      LAYER met2 ;
        RECT 373.610 1296.000 373.890 1300.000 ;
    END
  END tl_u_xbar_apb_o[88]
  PIN tl_u_xbar_apb_o[89]
    DIRECTION OUTPUT ;
    USE SIGNAL ;
    ANTENNADIFFAREA 0.445500 ;
    PORT
      LAYER met2 ;
        RECT 502.410 1296.000 502.690 1300.000 ;
    END
  END tl_u_xbar_apb_o[89]
  PIN tl_u_xbar_apb_o[8]
    DIRECTION OUTPUT ;
    USE SIGNAL ;
    ANTENNADIFFAREA 0.445500 ;
    PORT
      LAYER met3 ;
        RECT 1296.000 1247.840 1300.000 1248.440 ;
    END
  END tl_u_xbar_apb_o[8]
  PIN tl_u_xbar_apb_o[90]
    DIRECTION OUTPUT ;
    USE SIGNAL ;
    ANTENNADIFFAREA 0.445500 ;
    PORT
      LAYER met2 ;
        RECT 441.230 1296.000 441.510 1300.000 ;
    END
  END tl_u_xbar_apb_o[90]
  PIN tl_u_xbar_apb_o[91]
    DIRECTION OUTPUT ;
    USE SIGNAL ;
    ANTENNADIFFAREA 0.445500 ;
    PORT
      LAYER met2 ;
        RECT 489.530 1296.000 489.810 1300.000 ;
    END
  END tl_u_xbar_apb_o[91]
  PIN tl_u_xbar_apb_o[92]
    DIRECTION OUTPUT ;
    USE SIGNAL ;
    ANTENNADIFFAREA 0.445500 ;
    PORT
      LAYER met2 ;
        RECT 457.330 1296.000 457.610 1300.000 ;
    END
  END tl_u_xbar_apb_o[92]
  PIN tl_u_xbar_apb_o[93]
    DIRECTION OUTPUT ;
    USE SIGNAL ;
    ANTENNADIFFAREA 0.445500 ;
    PORT
      LAYER met3 ;
        RECT 1296.000 210.840 1300.000 211.440 ;
    END
  END tl_u_xbar_apb_o[93]
  PIN tl_u_xbar_apb_o[94]
    DIRECTION OUTPUT ;
    USE SIGNAL ;
    ANTENNADIFFAREA 0.445500 ;
    PORT
      LAYER met3 ;
        RECT 1296.000 418.240 1300.000 418.840 ;
    END
  END tl_u_xbar_apb_o[94]
  PIN tl_u_xbar_apb_o[95]
    DIRECTION OUTPUT ;
    USE SIGNAL ;
    ANTENNADIFFAREA 0.445500 ;
    PORT
      LAYER met3 ;
        RECT 1296.000 880.640 1300.000 881.240 ;
    END
  END tl_u_xbar_apb_o[95]
  PIN tl_u_xbar_apb_o[96]
    DIRECTION OUTPUT ;
    USE SIGNAL ;
    ANTENNADIFFAREA 0.445500 ;
    PORT
      LAYER met2 ;
        RECT 438.010 1296.000 438.290 1300.000 ;
    END
  END tl_u_xbar_apb_o[96]
  PIN tl_u_xbar_apb_o[97]
    DIRECTION OUTPUT ;
    USE SIGNAL ;
    ANTENNADIFFAREA 0.445500 ;
    PORT
      LAYER met3 ;
        RECT 1296.000 1271.640 1300.000 1272.240 ;
    END
  END tl_u_xbar_apb_o[97]
  PIN tl_u_xbar_apb_o[98]
    DIRECTION OUTPUT ;
    USE SIGNAL ;
    ANTENNADIFFAREA 0.445500 ;
    PORT
      LAYER met3 ;
        RECT 1296.000 431.840 1300.000 432.440 ;
    END
  END tl_u_xbar_apb_o[98]
  PIN tl_u_xbar_apb_o[99]
    DIRECTION OUTPUT ;
    USE SIGNAL ;
    ANTENNADIFFAREA 0.445500 ;
    PORT
      LAYER met2 ;
        RECT 476.650 1296.000 476.930 1300.000 ;
    END
  END tl_u_xbar_apb_o[99]
  PIN tl_u_xbar_apb_o[9]
    DIRECTION OUTPUT ;
    USE SIGNAL ;
    ANTENNADIFFAREA 0.445500 ;
    PORT
      LAYER met3 ;
        RECT 1296.000 1081.240 1300.000 1081.840 ;
    END
  END tl_u_xbar_apb_o[9]
  OBS
      LAYER nwell ;
        RECT 5.330 10.760 1294.630 1286.750 ;
      LAYER li1 ;
        RECT 5.520 10.795 1294.440 1286.645 ;
      LAYER met1 ;
        RECT 0.530 0.380 1298.510 1296.720 ;
      LAYER met2 ;
        RECT 0.550 1295.720 312.150 1299.325 ;
        RECT 312.990 1295.720 315.370 1299.325 ;
        RECT 316.210 1295.720 318.590 1299.325 ;
        RECT 319.430 1295.720 321.810 1299.325 ;
        RECT 322.650 1295.720 325.030 1299.325 ;
        RECT 325.870 1295.720 328.250 1299.325 ;
        RECT 329.090 1295.720 331.470 1299.325 ;
        RECT 332.310 1295.720 334.690 1299.325 ;
        RECT 335.530 1295.720 337.910 1299.325 ;
        RECT 338.750 1295.720 341.130 1299.325 ;
        RECT 341.970 1295.720 344.350 1299.325 ;
        RECT 345.190 1295.720 347.570 1299.325 ;
        RECT 348.410 1295.720 350.790 1299.325 ;
        RECT 351.630 1295.720 354.010 1299.325 ;
        RECT 354.850 1295.720 357.230 1299.325 ;
        RECT 358.070 1295.720 360.450 1299.325 ;
        RECT 361.290 1295.720 363.670 1299.325 ;
        RECT 364.510 1295.720 366.890 1299.325 ;
        RECT 367.730 1295.720 370.110 1299.325 ;
        RECT 370.950 1295.720 373.330 1299.325 ;
        RECT 374.170 1295.720 376.550 1299.325 ;
        RECT 377.390 1295.720 379.770 1299.325 ;
        RECT 380.610 1295.720 382.990 1299.325 ;
        RECT 383.830 1295.720 386.210 1299.325 ;
        RECT 387.050 1295.720 389.430 1299.325 ;
        RECT 390.270 1295.720 392.650 1299.325 ;
        RECT 393.490 1295.720 395.870 1299.325 ;
        RECT 396.710 1295.720 399.090 1299.325 ;
        RECT 399.930 1295.720 402.310 1299.325 ;
        RECT 403.150 1295.720 405.530 1299.325 ;
        RECT 406.370 1295.720 408.750 1299.325 ;
        RECT 409.590 1295.720 411.970 1299.325 ;
        RECT 412.810 1295.720 415.190 1299.325 ;
        RECT 416.030 1295.720 418.410 1299.325 ;
        RECT 419.250 1295.720 421.630 1299.325 ;
        RECT 422.470 1295.720 424.850 1299.325 ;
        RECT 425.690 1295.720 428.070 1299.325 ;
        RECT 428.910 1295.720 431.290 1299.325 ;
        RECT 432.130 1295.720 434.510 1299.325 ;
        RECT 435.350 1295.720 437.730 1299.325 ;
        RECT 438.570 1295.720 440.950 1299.325 ;
        RECT 441.790 1295.720 444.170 1299.325 ;
        RECT 445.010 1295.720 447.390 1299.325 ;
        RECT 448.230 1295.720 450.610 1299.325 ;
        RECT 451.450 1295.720 453.830 1299.325 ;
        RECT 454.670 1295.720 457.050 1299.325 ;
        RECT 457.890 1295.720 460.270 1299.325 ;
        RECT 461.110 1295.720 463.490 1299.325 ;
        RECT 464.330 1295.720 466.710 1299.325 ;
        RECT 467.550 1295.720 469.930 1299.325 ;
        RECT 470.770 1295.720 473.150 1299.325 ;
        RECT 473.990 1295.720 476.370 1299.325 ;
        RECT 477.210 1295.720 479.590 1299.325 ;
        RECT 480.430 1295.720 482.810 1299.325 ;
        RECT 483.650 1295.720 486.030 1299.325 ;
        RECT 486.870 1295.720 489.250 1299.325 ;
        RECT 490.090 1295.720 492.470 1299.325 ;
        RECT 493.310 1295.720 495.690 1299.325 ;
        RECT 496.530 1295.720 498.910 1299.325 ;
        RECT 499.750 1295.720 502.130 1299.325 ;
        RECT 502.970 1295.720 505.350 1299.325 ;
        RECT 506.190 1295.720 508.570 1299.325 ;
        RECT 509.410 1295.720 511.790 1299.325 ;
        RECT 512.630 1295.720 515.010 1299.325 ;
        RECT 515.850 1295.720 518.230 1299.325 ;
        RECT 519.070 1295.720 521.450 1299.325 ;
        RECT 522.290 1295.720 524.670 1299.325 ;
        RECT 525.510 1295.720 527.890 1299.325 ;
        RECT 528.730 1295.720 531.110 1299.325 ;
        RECT 531.950 1295.720 534.330 1299.325 ;
        RECT 535.170 1295.720 537.550 1299.325 ;
        RECT 538.390 1295.720 540.770 1299.325 ;
        RECT 541.610 1295.720 543.990 1299.325 ;
        RECT 544.830 1295.720 547.210 1299.325 ;
        RECT 548.050 1295.720 550.430 1299.325 ;
        RECT 551.270 1295.720 553.650 1299.325 ;
        RECT 554.490 1295.720 556.870 1299.325 ;
        RECT 557.710 1295.720 560.090 1299.325 ;
        RECT 560.930 1295.720 563.310 1299.325 ;
        RECT 564.150 1295.720 566.530 1299.325 ;
        RECT 567.370 1295.720 569.750 1299.325 ;
        RECT 570.590 1295.720 572.970 1299.325 ;
        RECT 573.810 1295.720 576.190 1299.325 ;
        RECT 577.030 1295.720 579.410 1299.325 ;
        RECT 580.250 1295.720 582.630 1299.325 ;
        RECT 583.470 1295.720 585.850 1299.325 ;
        RECT 586.690 1295.720 589.070 1299.325 ;
        RECT 589.910 1295.720 592.290 1299.325 ;
        RECT 593.130 1295.720 595.510 1299.325 ;
        RECT 596.350 1295.720 598.730 1299.325 ;
        RECT 599.570 1295.720 601.950 1299.325 ;
        RECT 602.790 1295.720 605.170 1299.325 ;
        RECT 606.010 1295.720 608.390 1299.325 ;
        RECT 609.230 1295.720 611.610 1299.325 ;
        RECT 612.450 1295.720 614.830 1299.325 ;
        RECT 615.670 1295.720 618.050 1299.325 ;
        RECT 618.890 1295.720 621.270 1299.325 ;
        RECT 622.110 1295.720 624.490 1299.325 ;
        RECT 625.330 1295.720 627.710 1299.325 ;
        RECT 628.550 1295.720 630.930 1299.325 ;
        RECT 631.770 1295.720 634.150 1299.325 ;
        RECT 634.990 1295.720 637.370 1299.325 ;
        RECT 638.210 1295.720 640.590 1299.325 ;
        RECT 641.430 1295.720 643.810 1299.325 ;
        RECT 644.650 1295.720 647.030 1299.325 ;
        RECT 647.870 1295.720 650.250 1299.325 ;
        RECT 651.090 1295.720 653.470 1299.325 ;
        RECT 654.310 1295.720 656.690 1299.325 ;
        RECT 657.530 1295.720 659.910 1299.325 ;
        RECT 660.750 1295.720 663.130 1299.325 ;
        RECT 663.970 1295.720 666.350 1299.325 ;
        RECT 667.190 1295.720 669.570 1299.325 ;
        RECT 670.410 1295.720 672.790 1299.325 ;
        RECT 673.630 1295.720 676.010 1299.325 ;
        RECT 676.850 1295.720 679.230 1299.325 ;
        RECT 680.070 1295.720 682.450 1299.325 ;
        RECT 683.290 1295.720 685.670 1299.325 ;
        RECT 686.510 1295.720 688.890 1299.325 ;
        RECT 689.730 1295.720 692.110 1299.325 ;
        RECT 692.950 1295.720 695.330 1299.325 ;
        RECT 696.170 1295.720 698.550 1299.325 ;
        RECT 699.390 1295.720 701.770 1299.325 ;
        RECT 702.610 1295.720 704.990 1299.325 ;
        RECT 705.830 1295.720 708.210 1299.325 ;
        RECT 709.050 1295.720 711.430 1299.325 ;
        RECT 712.270 1295.720 714.650 1299.325 ;
        RECT 715.490 1295.720 717.870 1299.325 ;
        RECT 718.710 1295.720 721.090 1299.325 ;
        RECT 721.930 1295.720 724.310 1299.325 ;
        RECT 725.150 1295.720 727.530 1299.325 ;
        RECT 728.370 1295.720 730.750 1299.325 ;
        RECT 731.590 1295.720 733.970 1299.325 ;
        RECT 734.810 1295.720 737.190 1299.325 ;
        RECT 738.030 1295.720 740.410 1299.325 ;
        RECT 741.250 1295.720 743.630 1299.325 ;
        RECT 744.470 1295.720 746.850 1299.325 ;
        RECT 747.690 1295.720 750.070 1299.325 ;
        RECT 750.910 1295.720 753.290 1299.325 ;
        RECT 754.130 1295.720 756.510 1299.325 ;
        RECT 757.350 1295.720 759.730 1299.325 ;
        RECT 760.570 1295.720 762.950 1299.325 ;
        RECT 763.790 1295.720 766.170 1299.325 ;
        RECT 767.010 1295.720 769.390 1299.325 ;
        RECT 770.230 1295.720 772.610 1299.325 ;
        RECT 773.450 1295.720 775.830 1299.325 ;
        RECT 776.670 1295.720 779.050 1299.325 ;
        RECT 779.890 1295.720 782.270 1299.325 ;
        RECT 783.110 1295.720 785.490 1299.325 ;
        RECT 786.330 1295.720 788.710 1299.325 ;
        RECT 789.550 1295.720 791.930 1299.325 ;
        RECT 792.770 1295.720 795.150 1299.325 ;
        RECT 795.990 1295.720 798.370 1299.325 ;
        RECT 799.210 1295.720 801.590 1299.325 ;
        RECT 802.430 1295.720 804.810 1299.325 ;
        RECT 805.650 1295.720 808.030 1299.325 ;
        RECT 808.870 1295.720 811.250 1299.325 ;
        RECT 812.090 1295.720 814.470 1299.325 ;
        RECT 815.310 1295.720 817.690 1299.325 ;
        RECT 818.530 1295.720 820.910 1299.325 ;
        RECT 821.750 1295.720 824.130 1299.325 ;
        RECT 824.970 1295.720 827.350 1299.325 ;
        RECT 828.190 1295.720 830.570 1299.325 ;
        RECT 831.410 1295.720 833.790 1299.325 ;
        RECT 834.630 1295.720 837.010 1299.325 ;
        RECT 837.850 1295.720 840.230 1299.325 ;
        RECT 841.070 1295.720 843.450 1299.325 ;
        RECT 844.290 1295.720 846.670 1299.325 ;
        RECT 847.510 1295.720 849.890 1299.325 ;
        RECT 850.730 1295.720 853.110 1299.325 ;
        RECT 853.950 1295.720 856.330 1299.325 ;
        RECT 857.170 1295.720 859.550 1299.325 ;
        RECT 860.390 1295.720 862.770 1299.325 ;
        RECT 863.610 1295.720 865.990 1299.325 ;
        RECT 866.830 1295.720 869.210 1299.325 ;
        RECT 870.050 1295.720 872.430 1299.325 ;
        RECT 873.270 1295.720 875.650 1299.325 ;
        RECT 876.490 1295.720 878.870 1299.325 ;
        RECT 879.710 1295.720 882.090 1299.325 ;
        RECT 882.930 1295.720 885.310 1299.325 ;
        RECT 886.150 1295.720 888.530 1299.325 ;
        RECT 889.370 1295.720 891.750 1299.325 ;
        RECT 892.590 1295.720 894.970 1299.325 ;
        RECT 895.810 1295.720 898.190 1299.325 ;
        RECT 899.030 1295.720 901.410 1299.325 ;
        RECT 902.250 1295.720 904.630 1299.325 ;
        RECT 905.470 1295.720 907.850 1299.325 ;
        RECT 908.690 1295.720 911.070 1299.325 ;
        RECT 911.910 1295.720 914.290 1299.325 ;
        RECT 915.130 1295.720 917.510 1299.325 ;
        RECT 918.350 1295.720 920.730 1299.325 ;
        RECT 921.570 1295.720 923.950 1299.325 ;
        RECT 924.790 1295.720 927.170 1299.325 ;
        RECT 928.010 1295.720 930.390 1299.325 ;
        RECT 931.230 1295.720 933.610 1299.325 ;
        RECT 934.450 1295.720 936.830 1299.325 ;
        RECT 937.670 1295.720 940.050 1299.325 ;
        RECT 940.890 1295.720 943.270 1299.325 ;
        RECT 944.110 1295.720 946.490 1299.325 ;
        RECT 947.330 1295.720 949.710 1299.325 ;
        RECT 950.550 1295.720 952.930 1299.325 ;
        RECT 953.770 1295.720 956.150 1299.325 ;
        RECT 956.990 1295.720 959.370 1299.325 ;
        RECT 960.210 1295.720 962.590 1299.325 ;
        RECT 963.430 1295.720 965.810 1299.325 ;
        RECT 966.650 1295.720 969.030 1299.325 ;
        RECT 969.870 1295.720 972.250 1299.325 ;
        RECT 973.090 1295.720 975.470 1299.325 ;
        RECT 976.310 1295.720 978.690 1299.325 ;
        RECT 979.530 1295.720 981.910 1299.325 ;
        RECT 982.750 1295.720 985.130 1299.325 ;
        RECT 985.970 1295.720 988.350 1299.325 ;
        RECT 989.190 1295.720 991.570 1299.325 ;
        RECT 992.410 1295.720 994.790 1299.325 ;
        RECT 995.630 1295.720 998.010 1299.325 ;
        RECT 998.850 1295.720 1001.230 1299.325 ;
        RECT 1002.070 1295.720 1004.450 1299.325 ;
        RECT 1005.290 1295.720 1007.670 1299.325 ;
        RECT 1008.510 1295.720 1010.890 1299.325 ;
        RECT 1011.730 1295.720 1014.110 1299.325 ;
        RECT 1014.950 1295.720 1017.330 1299.325 ;
        RECT 1018.170 1295.720 1020.550 1299.325 ;
        RECT 1021.390 1295.720 1023.770 1299.325 ;
        RECT 1024.610 1295.720 1026.990 1299.325 ;
        RECT 1027.830 1295.720 1030.210 1299.325 ;
        RECT 1031.050 1295.720 1033.430 1299.325 ;
        RECT 1034.270 1295.720 1036.650 1299.325 ;
        RECT 1037.490 1295.720 1039.870 1299.325 ;
        RECT 1040.710 1295.720 1043.090 1299.325 ;
        RECT 1043.930 1295.720 1046.310 1299.325 ;
        RECT 1047.150 1295.720 1049.530 1299.325 ;
        RECT 1050.370 1295.720 1052.750 1299.325 ;
        RECT 1053.590 1295.720 1055.970 1299.325 ;
        RECT 1056.810 1295.720 1059.190 1299.325 ;
        RECT 1060.030 1295.720 1062.410 1299.325 ;
        RECT 1063.250 1295.720 1065.630 1299.325 ;
        RECT 1066.470 1295.720 1068.850 1299.325 ;
        RECT 1069.690 1295.720 1072.070 1299.325 ;
        RECT 1072.910 1295.720 1075.290 1299.325 ;
        RECT 1076.130 1295.720 1078.510 1299.325 ;
        RECT 1079.350 1295.720 1081.730 1299.325 ;
        RECT 1082.570 1295.720 1084.950 1299.325 ;
        RECT 1085.790 1295.720 1088.170 1299.325 ;
        RECT 1089.010 1295.720 1091.390 1299.325 ;
        RECT 1092.230 1295.720 1094.610 1299.325 ;
        RECT 1095.450 1295.720 1097.830 1299.325 ;
        RECT 1098.670 1295.720 1101.050 1299.325 ;
        RECT 1101.890 1295.720 1104.270 1299.325 ;
        RECT 1105.110 1295.720 1107.490 1299.325 ;
        RECT 1108.330 1295.720 1110.710 1299.325 ;
        RECT 1111.550 1295.720 1113.930 1299.325 ;
        RECT 1114.770 1295.720 1117.150 1299.325 ;
        RECT 1117.990 1295.720 1120.370 1299.325 ;
        RECT 1121.210 1295.720 1123.590 1299.325 ;
        RECT 1124.430 1295.720 1126.810 1299.325 ;
        RECT 1127.650 1295.720 1130.030 1299.325 ;
        RECT 1130.870 1295.720 1133.250 1299.325 ;
        RECT 1134.090 1295.720 1136.470 1299.325 ;
        RECT 1137.310 1295.720 1139.690 1299.325 ;
        RECT 1140.530 1295.720 1142.910 1299.325 ;
        RECT 1143.750 1295.720 1146.130 1299.325 ;
        RECT 1146.970 1295.720 1149.350 1299.325 ;
        RECT 1150.190 1295.720 1152.570 1299.325 ;
        RECT 1153.410 1295.720 1155.790 1299.325 ;
        RECT 1156.630 1295.720 1159.010 1299.325 ;
        RECT 1159.850 1295.720 1162.230 1299.325 ;
        RECT 1163.070 1295.720 1165.450 1299.325 ;
        RECT 1166.290 1295.720 1168.670 1299.325 ;
        RECT 1169.510 1295.720 1171.890 1299.325 ;
        RECT 1172.730 1295.720 1175.110 1299.325 ;
        RECT 1175.950 1295.720 1178.330 1299.325 ;
        RECT 1179.170 1295.720 1181.550 1299.325 ;
        RECT 1182.390 1295.720 1184.770 1299.325 ;
        RECT 1185.610 1295.720 1187.990 1299.325 ;
        RECT 1188.830 1295.720 1191.210 1299.325 ;
        RECT 1192.050 1295.720 1194.430 1299.325 ;
        RECT 1195.270 1295.720 1197.650 1299.325 ;
        RECT 1198.490 1295.720 1200.870 1299.325 ;
        RECT 1201.710 1295.720 1204.090 1299.325 ;
        RECT 1204.930 1295.720 1207.310 1299.325 ;
        RECT 1208.150 1295.720 1210.530 1299.325 ;
        RECT 1211.370 1295.720 1213.750 1299.325 ;
        RECT 1214.590 1295.720 1216.970 1299.325 ;
        RECT 1217.810 1295.720 1220.190 1299.325 ;
        RECT 1221.030 1295.720 1223.410 1299.325 ;
        RECT 1224.250 1295.720 1226.630 1299.325 ;
        RECT 1227.470 1295.720 1229.850 1299.325 ;
        RECT 1230.690 1295.720 1233.070 1299.325 ;
        RECT 1233.910 1295.720 1236.290 1299.325 ;
        RECT 1237.130 1295.720 1239.510 1299.325 ;
        RECT 1240.350 1295.720 1242.730 1299.325 ;
        RECT 1243.570 1295.720 1245.950 1299.325 ;
        RECT 1246.790 1295.720 1249.170 1299.325 ;
        RECT 1250.010 1295.720 1252.390 1299.325 ;
        RECT 1253.230 1295.720 1255.610 1299.325 ;
        RECT 1256.450 1295.720 1258.830 1299.325 ;
        RECT 1259.670 1295.720 1262.050 1299.325 ;
        RECT 1262.890 1295.720 1265.270 1299.325 ;
        RECT 1266.110 1295.720 1268.490 1299.325 ;
        RECT 1269.330 1295.720 1271.710 1299.325 ;
        RECT 1272.550 1295.720 1274.930 1299.325 ;
        RECT 1275.770 1295.720 1278.150 1299.325 ;
        RECT 1278.990 1295.720 1281.370 1299.325 ;
        RECT 1282.210 1295.720 1284.590 1299.325 ;
        RECT 1285.430 1295.720 1287.810 1299.325 ;
        RECT 1288.650 1295.720 1291.030 1299.325 ;
        RECT 1291.870 1295.720 1294.250 1299.325 ;
        RECT 1295.090 1295.720 1297.470 1299.325 ;
        RECT 1298.310 1295.720 1298.480 1299.325 ;
        RECT 0.550 4.280 1298.480 1295.720 ;
        RECT 0.650 0.350 3.030 4.280 ;
        RECT 3.870 0.350 6.250 4.280 ;
        RECT 7.090 0.350 9.470 4.280 ;
        RECT 10.310 0.350 12.690 4.280 ;
        RECT 13.530 0.350 15.910 4.280 ;
        RECT 16.750 0.350 19.130 4.280 ;
        RECT 19.970 0.350 22.350 4.280 ;
        RECT 23.190 0.350 25.570 4.280 ;
        RECT 26.410 0.350 28.790 4.280 ;
        RECT 29.630 0.350 32.010 4.280 ;
        RECT 32.850 0.350 35.230 4.280 ;
        RECT 36.070 0.350 38.450 4.280 ;
        RECT 39.290 0.350 41.670 4.280 ;
        RECT 42.510 0.350 44.890 4.280 ;
        RECT 45.730 0.350 48.110 4.280 ;
        RECT 48.950 0.350 51.330 4.280 ;
        RECT 52.170 0.350 54.550 4.280 ;
        RECT 55.390 0.350 57.770 4.280 ;
        RECT 58.610 0.350 60.990 4.280 ;
        RECT 61.830 0.350 64.210 4.280 ;
        RECT 65.050 0.350 67.430 4.280 ;
        RECT 68.270 0.350 70.650 4.280 ;
        RECT 71.490 0.350 73.870 4.280 ;
        RECT 74.710 0.350 77.090 4.280 ;
        RECT 77.930 0.350 80.310 4.280 ;
        RECT 81.150 0.350 83.530 4.280 ;
        RECT 84.370 0.350 86.750 4.280 ;
        RECT 87.590 0.350 89.970 4.280 ;
        RECT 90.810 0.350 93.190 4.280 ;
        RECT 94.030 0.350 96.410 4.280 ;
        RECT 97.250 0.350 99.630 4.280 ;
        RECT 100.470 0.350 102.850 4.280 ;
        RECT 103.690 0.350 106.070 4.280 ;
        RECT 106.910 0.350 109.290 4.280 ;
        RECT 110.130 0.350 112.510 4.280 ;
        RECT 113.350 0.350 115.730 4.280 ;
        RECT 116.570 0.350 118.950 4.280 ;
        RECT 119.790 0.350 122.170 4.280 ;
        RECT 123.010 0.350 125.390 4.280 ;
        RECT 126.230 0.350 128.610 4.280 ;
        RECT 129.450 0.350 131.830 4.280 ;
        RECT 132.670 0.350 135.050 4.280 ;
        RECT 135.890 0.350 138.270 4.280 ;
        RECT 139.110 0.350 141.490 4.280 ;
        RECT 142.330 0.350 144.710 4.280 ;
        RECT 145.550 0.350 147.930 4.280 ;
        RECT 148.770 0.350 151.150 4.280 ;
        RECT 151.990 0.350 154.370 4.280 ;
        RECT 155.210 0.350 157.590 4.280 ;
        RECT 158.430 0.350 160.810 4.280 ;
        RECT 161.650 0.350 164.030 4.280 ;
        RECT 164.870 0.350 167.250 4.280 ;
        RECT 168.090 0.350 170.470 4.280 ;
        RECT 171.310 0.350 173.690 4.280 ;
        RECT 174.530 0.350 176.910 4.280 ;
        RECT 177.750 0.350 180.130 4.280 ;
        RECT 180.970 0.350 183.350 4.280 ;
        RECT 184.190 0.350 186.570 4.280 ;
        RECT 187.410 0.350 189.790 4.280 ;
        RECT 190.630 0.350 193.010 4.280 ;
        RECT 193.850 0.350 196.230 4.280 ;
        RECT 197.070 0.350 199.450 4.280 ;
        RECT 200.290 0.350 202.670 4.280 ;
        RECT 203.510 0.350 205.890 4.280 ;
        RECT 206.730 0.350 209.110 4.280 ;
        RECT 209.950 0.350 212.330 4.280 ;
        RECT 213.170 0.350 215.550 4.280 ;
        RECT 216.390 0.350 218.770 4.280 ;
        RECT 219.610 0.350 221.990 4.280 ;
        RECT 222.830 0.350 225.210 4.280 ;
        RECT 226.050 0.350 228.430 4.280 ;
        RECT 229.270 0.350 231.650 4.280 ;
        RECT 232.490 0.350 234.870 4.280 ;
        RECT 235.710 0.350 238.090 4.280 ;
        RECT 238.930 0.350 241.310 4.280 ;
        RECT 242.150 0.350 244.530 4.280 ;
        RECT 245.370 0.350 247.750 4.280 ;
        RECT 248.590 0.350 250.970 4.280 ;
        RECT 251.810 0.350 254.190 4.280 ;
        RECT 255.030 0.350 257.410 4.280 ;
        RECT 258.250 0.350 260.630 4.280 ;
        RECT 261.470 0.350 263.850 4.280 ;
        RECT 264.690 0.350 267.070 4.280 ;
        RECT 267.910 0.350 270.290 4.280 ;
        RECT 271.130 0.350 273.510 4.280 ;
        RECT 274.350 0.350 276.730 4.280 ;
        RECT 277.570 0.350 279.950 4.280 ;
        RECT 280.790 0.350 283.170 4.280 ;
        RECT 284.010 0.350 286.390 4.280 ;
        RECT 287.230 0.350 289.610 4.280 ;
        RECT 290.450 0.350 292.830 4.280 ;
        RECT 293.670 0.350 296.050 4.280 ;
        RECT 296.890 0.350 299.270 4.280 ;
        RECT 300.110 0.350 302.490 4.280 ;
        RECT 303.330 0.350 305.710 4.280 ;
        RECT 306.550 0.350 308.930 4.280 ;
        RECT 309.770 0.350 312.150 4.280 ;
        RECT 312.990 0.350 315.370 4.280 ;
        RECT 316.210 0.350 318.590 4.280 ;
        RECT 319.430 0.350 321.810 4.280 ;
        RECT 322.650 0.350 325.030 4.280 ;
        RECT 325.870 0.350 328.250 4.280 ;
        RECT 329.090 0.350 331.470 4.280 ;
        RECT 332.310 0.350 334.690 4.280 ;
        RECT 335.530 0.350 337.910 4.280 ;
        RECT 338.750 0.350 341.130 4.280 ;
        RECT 341.970 0.350 344.350 4.280 ;
        RECT 345.190 0.350 347.570 4.280 ;
        RECT 348.410 0.350 350.790 4.280 ;
        RECT 351.630 0.350 354.010 4.280 ;
        RECT 354.850 0.350 357.230 4.280 ;
        RECT 358.070 0.350 360.450 4.280 ;
        RECT 361.290 0.350 363.670 4.280 ;
        RECT 364.510 0.350 366.890 4.280 ;
        RECT 367.730 0.350 370.110 4.280 ;
        RECT 370.950 0.350 373.330 4.280 ;
        RECT 374.170 0.350 376.550 4.280 ;
        RECT 377.390 0.350 379.770 4.280 ;
        RECT 380.610 0.350 382.990 4.280 ;
        RECT 383.830 0.350 386.210 4.280 ;
        RECT 387.050 0.350 389.430 4.280 ;
        RECT 390.270 0.350 392.650 4.280 ;
        RECT 393.490 0.350 395.870 4.280 ;
        RECT 396.710 0.350 399.090 4.280 ;
        RECT 399.930 0.350 402.310 4.280 ;
        RECT 403.150 0.350 405.530 4.280 ;
        RECT 406.370 0.350 408.750 4.280 ;
        RECT 409.590 0.350 411.970 4.280 ;
        RECT 412.810 0.350 415.190 4.280 ;
        RECT 416.030 0.350 418.410 4.280 ;
        RECT 419.250 0.350 421.630 4.280 ;
        RECT 422.470 0.350 424.850 4.280 ;
        RECT 425.690 0.350 428.070 4.280 ;
        RECT 428.910 0.350 431.290 4.280 ;
        RECT 432.130 0.350 434.510 4.280 ;
        RECT 435.350 0.350 437.730 4.280 ;
        RECT 438.570 0.350 440.950 4.280 ;
        RECT 441.790 0.350 444.170 4.280 ;
        RECT 445.010 0.350 447.390 4.280 ;
        RECT 448.230 0.350 450.610 4.280 ;
        RECT 451.450 0.350 453.830 4.280 ;
        RECT 454.670 0.350 457.050 4.280 ;
        RECT 457.890 0.350 460.270 4.280 ;
        RECT 461.110 0.350 463.490 4.280 ;
        RECT 464.330 0.350 466.710 4.280 ;
        RECT 467.550 0.350 469.930 4.280 ;
        RECT 470.770 0.350 473.150 4.280 ;
        RECT 473.990 0.350 476.370 4.280 ;
        RECT 477.210 0.350 479.590 4.280 ;
        RECT 480.430 0.350 482.810 4.280 ;
        RECT 483.650 0.350 486.030 4.280 ;
        RECT 486.870 0.350 489.250 4.280 ;
        RECT 490.090 0.350 492.470 4.280 ;
        RECT 493.310 0.350 495.690 4.280 ;
        RECT 496.530 0.350 498.910 4.280 ;
        RECT 499.750 0.350 502.130 4.280 ;
        RECT 502.970 0.350 505.350 4.280 ;
        RECT 506.190 0.350 508.570 4.280 ;
        RECT 509.410 0.350 511.790 4.280 ;
        RECT 512.630 0.350 515.010 4.280 ;
        RECT 515.850 0.350 518.230 4.280 ;
        RECT 519.070 0.350 521.450 4.280 ;
        RECT 522.290 0.350 524.670 4.280 ;
        RECT 525.510 0.350 527.890 4.280 ;
        RECT 528.730 0.350 531.110 4.280 ;
        RECT 531.950 0.350 534.330 4.280 ;
        RECT 535.170 0.350 537.550 4.280 ;
        RECT 538.390 0.350 540.770 4.280 ;
        RECT 541.610 0.350 543.990 4.280 ;
        RECT 544.830 0.350 547.210 4.280 ;
        RECT 548.050 0.350 550.430 4.280 ;
        RECT 551.270 0.350 553.650 4.280 ;
        RECT 554.490 0.350 556.870 4.280 ;
        RECT 557.710 0.350 560.090 4.280 ;
        RECT 560.930 0.350 563.310 4.280 ;
        RECT 564.150 0.350 566.530 4.280 ;
        RECT 567.370 0.350 569.750 4.280 ;
        RECT 570.590 0.350 572.970 4.280 ;
        RECT 573.810 0.350 576.190 4.280 ;
        RECT 577.030 0.350 579.410 4.280 ;
        RECT 580.250 0.350 582.630 4.280 ;
        RECT 583.470 0.350 585.850 4.280 ;
        RECT 586.690 0.350 589.070 4.280 ;
        RECT 589.910 0.350 592.290 4.280 ;
        RECT 593.130 0.350 595.510 4.280 ;
        RECT 596.350 0.350 598.730 4.280 ;
        RECT 599.570 0.350 601.950 4.280 ;
        RECT 602.790 0.350 605.170 4.280 ;
        RECT 606.010 0.350 608.390 4.280 ;
        RECT 609.230 0.350 611.610 4.280 ;
        RECT 612.450 0.350 614.830 4.280 ;
        RECT 615.670 0.350 618.050 4.280 ;
        RECT 618.890 0.350 621.270 4.280 ;
        RECT 622.110 0.350 624.490 4.280 ;
        RECT 625.330 0.350 627.710 4.280 ;
        RECT 628.550 0.350 630.930 4.280 ;
        RECT 631.770 0.350 634.150 4.280 ;
        RECT 634.990 0.350 637.370 4.280 ;
        RECT 638.210 0.350 640.590 4.280 ;
        RECT 641.430 0.350 643.810 4.280 ;
        RECT 644.650 0.350 647.030 4.280 ;
        RECT 647.870 0.350 650.250 4.280 ;
        RECT 651.090 0.350 653.470 4.280 ;
        RECT 654.310 0.350 656.690 4.280 ;
        RECT 657.530 0.350 659.910 4.280 ;
        RECT 660.750 0.350 663.130 4.280 ;
        RECT 663.970 0.350 666.350 4.280 ;
        RECT 667.190 0.350 669.570 4.280 ;
        RECT 670.410 0.350 672.790 4.280 ;
        RECT 673.630 0.350 676.010 4.280 ;
        RECT 676.850 0.350 679.230 4.280 ;
        RECT 680.070 0.350 682.450 4.280 ;
        RECT 683.290 0.350 685.670 4.280 ;
        RECT 686.510 0.350 688.890 4.280 ;
        RECT 689.730 0.350 692.110 4.280 ;
        RECT 692.950 0.350 695.330 4.280 ;
        RECT 696.170 0.350 698.550 4.280 ;
        RECT 699.390 0.350 701.770 4.280 ;
        RECT 702.610 0.350 704.990 4.280 ;
        RECT 705.830 0.350 708.210 4.280 ;
        RECT 709.050 0.350 711.430 4.280 ;
        RECT 712.270 0.350 714.650 4.280 ;
        RECT 715.490 0.350 717.870 4.280 ;
        RECT 718.710 0.350 721.090 4.280 ;
        RECT 721.930 0.350 724.310 4.280 ;
        RECT 725.150 0.350 727.530 4.280 ;
        RECT 728.370 0.350 730.750 4.280 ;
        RECT 731.590 0.350 733.970 4.280 ;
        RECT 734.810 0.350 737.190 4.280 ;
        RECT 738.030 0.350 740.410 4.280 ;
        RECT 741.250 0.350 743.630 4.280 ;
        RECT 744.470 0.350 746.850 4.280 ;
        RECT 747.690 0.350 750.070 4.280 ;
        RECT 750.910 0.350 753.290 4.280 ;
        RECT 754.130 0.350 756.510 4.280 ;
        RECT 757.350 0.350 759.730 4.280 ;
        RECT 760.570 0.350 762.950 4.280 ;
        RECT 763.790 0.350 766.170 4.280 ;
        RECT 767.010 0.350 769.390 4.280 ;
        RECT 770.230 0.350 772.610 4.280 ;
        RECT 773.450 0.350 775.830 4.280 ;
        RECT 776.670 0.350 779.050 4.280 ;
        RECT 779.890 0.350 782.270 4.280 ;
        RECT 783.110 0.350 785.490 4.280 ;
        RECT 786.330 0.350 788.710 4.280 ;
        RECT 789.550 0.350 791.930 4.280 ;
        RECT 792.770 0.350 795.150 4.280 ;
        RECT 795.990 0.350 798.370 4.280 ;
        RECT 799.210 0.350 801.590 4.280 ;
        RECT 802.430 0.350 804.810 4.280 ;
        RECT 805.650 0.350 808.030 4.280 ;
        RECT 808.870 0.350 811.250 4.280 ;
        RECT 812.090 0.350 814.470 4.280 ;
        RECT 815.310 0.350 817.690 4.280 ;
        RECT 818.530 0.350 820.910 4.280 ;
        RECT 821.750 0.350 824.130 4.280 ;
        RECT 824.970 0.350 827.350 4.280 ;
        RECT 828.190 0.350 830.570 4.280 ;
        RECT 831.410 0.350 833.790 4.280 ;
        RECT 834.630 0.350 837.010 4.280 ;
        RECT 837.850 0.350 840.230 4.280 ;
        RECT 841.070 0.350 843.450 4.280 ;
        RECT 844.290 0.350 846.670 4.280 ;
        RECT 847.510 0.350 849.890 4.280 ;
        RECT 850.730 0.350 853.110 4.280 ;
        RECT 853.950 0.350 856.330 4.280 ;
        RECT 857.170 0.350 859.550 4.280 ;
        RECT 860.390 0.350 862.770 4.280 ;
        RECT 863.610 0.350 865.990 4.280 ;
        RECT 866.830 0.350 869.210 4.280 ;
        RECT 870.050 0.350 872.430 4.280 ;
        RECT 873.270 0.350 875.650 4.280 ;
        RECT 876.490 0.350 878.870 4.280 ;
        RECT 879.710 0.350 882.090 4.280 ;
        RECT 882.930 0.350 885.310 4.280 ;
        RECT 886.150 0.350 888.530 4.280 ;
        RECT 889.370 0.350 891.750 4.280 ;
        RECT 892.590 0.350 894.970 4.280 ;
        RECT 895.810 0.350 898.190 4.280 ;
        RECT 899.030 0.350 901.410 4.280 ;
        RECT 902.250 0.350 904.630 4.280 ;
        RECT 905.470 0.350 907.850 4.280 ;
        RECT 908.690 0.350 911.070 4.280 ;
        RECT 911.910 0.350 914.290 4.280 ;
        RECT 915.130 0.350 917.510 4.280 ;
        RECT 918.350 0.350 920.730 4.280 ;
        RECT 921.570 0.350 923.950 4.280 ;
        RECT 924.790 0.350 927.170 4.280 ;
        RECT 928.010 0.350 930.390 4.280 ;
        RECT 931.230 0.350 933.610 4.280 ;
        RECT 934.450 0.350 936.830 4.280 ;
        RECT 937.670 0.350 940.050 4.280 ;
        RECT 940.890 0.350 943.270 4.280 ;
        RECT 944.110 0.350 946.490 4.280 ;
        RECT 947.330 0.350 949.710 4.280 ;
        RECT 950.550 0.350 952.930 4.280 ;
        RECT 953.770 0.350 956.150 4.280 ;
        RECT 956.990 0.350 959.370 4.280 ;
        RECT 960.210 0.350 962.590 4.280 ;
        RECT 963.430 0.350 965.810 4.280 ;
        RECT 966.650 0.350 969.030 4.280 ;
        RECT 969.870 0.350 972.250 4.280 ;
        RECT 973.090 0.350 975.470 4.280 ;
        RECT 976.310 0.350 978.690 4.280 ;
        RECT 979.530 0.350 981.910 4.280 ;
        RECT 982.750 0.350 985.130 4.280 ;
        RECT 985.970 0.350 988.350 4.280 ;
        RECT 989.190 0.350 991.570 4.280 ;
        RECT 992.410 0.350 994.790 4.280 ;
        RECT 995.630 0.350 998.010 4.280 ;
        RECT 998.850 0.350 1001.230 4.280 ;
        RECT 1002.070 0.350 1004.450 4.280 ;
        RECT 1005.290 0.350 1007.670 4.280 ;
        RECT 1008.510 0.350 1010.890 4.280 ;
        RECT 1011.730 0.350 1014.110 4.280 ;
        RECT 1014.950 0.350 1017.330 4.280 ;
        RECT 1018.170 0.350 1020.550 4.280 ;
        RECT 1021.390 0.350 1023.770 4.280 ;
        RECT 1024.610 0.350 1026.990 4.280 ;
        RECT 1027.830 0.350 1030.210 4.280 ;
        RECT 1031.050 0.350 1033.430 4.280 ;
        RECT 1034.270 0.350 1036.650 4.280 ;
        RECT 1037.490 0.350 1039.870 4.280 ;
        RECT 1040.710 0.350 1043.090 4.280 ;
        RECT 1043.930 0.350 1046.310 4.280 ;
        RECT 1047.150 0.350 1049.530 4.280 ;
        RECT 1050.370 0.350 1052.750 4.280 ;
        RECT 1053.590 0.350 1055.970 4.280 ;
        RECT 1056.810 0.350 1059.190 4.280 ;
        RECT 1060.030 0.350 1062.410 4.280 ;
        RECT 1063.250 0.350 1065.630 4.280 ;
        RECT 1066.470 0.350 1068.850 4.280 ;
        RECT 1069.690 0.350 1072.070 4.280 ;
        RECT 1072.910 0.350 1075.290 4.280 ;
        RECT 1076.130 0.350 1078.510 4.280 ;
        RECT 1079.350 0.350 1081.730 4.280 ;
        RECT 1082.570 0.350 1084.950 4.280 ;
        RECT 1085.790 0.350 1088.170 4.280 ;
        RECT 1089.010 0.350 1091.390 4.280 ;
        RECT 1092.230 0.350 1094.610 4.280 ;
        RECT 1095.450 0.350 1097.830 4.280 ;
        RECT 1098.670 0.350 1101.050 4.280 ;
        RECT 1101.890 0.350 1104.270 4.280 ;
        RECT 1105.110 0.350 1107.490 4.280 ;
        RECT 1108.330 0.350 1110.710 4.280 ;
        RECT 1111.550 0.350 1113.930 4.280 ;
        RECT 1114.770 0.350 1117.150 4.280 ;
        RECT 1117.990 0.350 1120.370 4.280 ;
        RECT 1121.210 0.350 1123.590 4.280 ;
        RECT 1124.430 0.350 1126.810 4.280 ;
        RECT 1127.650 0.350 1130.030 4.280 ;
        RECT 1130.870 0.350 1133.250 4.280 ;
        RECT 1134.090 0.350 1136.470 4.280 ;
        RECT 1137.310 0.350 1139.690 4.280 ;
        RECT 1140.530 0.350 1142.910 4.280 ;
        RECT 1143.750 0.350 1146.130 4.280 ;
        RECT 1146.970 0.350 1149.350 4.280 ;
        RECT 1150.190 0.350 1152.570 4.280 ;
        RECT 1153.410 0.350 1155.790 4.280 ;
        RECT 1156.630 0.350 1159.010 4.280 ;
        RECT 1159.850 0.350 1162.230 4.280 ;
        RECT 1163.070 0.350 1165.450 4.280 ;
        RECT 1166.290 0.350 1168.670 4.280 ;
        RECT 1169.510 0.350 1171.890 4.280 ;
        RECT 1172.730 0.350 1175.110 4.280 ;
        RECT 1175.950 0.350 1178.330 4.280 ;
        RECT 1179.170 0.350 1181.550 4.280 ;
        RECT 1182.390 0.350 1184.770 4.280 ;
        RECT 1185.610 0.350 1187.990 4.280 ;
        RECT 1188.830 0.350 1191.210 4.280 ;
        RECT 1192.050 0.350 1194.430 4.280 ;
        RECT 1195.270 0.350 1197.650 4.280 ;
        RECT 1198.490 0.350 1200.870 4.280 ;
        RECT 1201.710 0.350 1204.090 4.280 ;
        RECT 1204.930 0.350 1207.310 4.280 ;
        RECT 1208.150 0.350 1210.530 4.280 ;
        RECT 1211.370 0.350 1213.750 4.280 ;
        RECT 1214.590 0.350 1216.970 4.280 ;
        RECT 1217.810 0.350 1220.190 4.280 ;
        RECT 1221.030 0.350 1223.410 4.280 ;
        RECT 1224.250 0.350 1226.630 4.280 ;
        RECT 1227.470 0.350 1229.850 4.280 ;
        RECT 1230.690 0.350 1233.070 4.280 ;
        RECT 1233.910 0.350 1236.290 4.280 ;
        RECT 1237.130 0.350 1239.510 4.280 ;
        RECT 1240.350 0.350 1242.730 4.280 ;
        RECT 1243.570 0.350 1245.950 4.280 ;
        RECT 1246.790 0.350 1249.170 4.280 ;
        RECT 1250.010 0.350 1252.390 4.280 ;
        RECT 1253.230 0.350 1255.610 4.280 ;
        RECT 1256.450 0.350 1258.830 4.280 ;
        RECT 1259.670 0.350 1262.050 4.280 ;
        RECT 1262.890 0.350 1265.270 4.280 ;
        RECT 1266.110 0.350 1268.490 4.280 ;
        RECT 1269.330 0.350 1271.710 4.280 ;
        RECT 1272.550 0.350 1274.930 4.280 ;
        RECT 1275.770 0.350 1278.150 4.280 ;
        RECT 1278.990 0.350 1281.370 4.280 ;
        RECT 1282.210 0.350 1284.590 4.280 ;
        RECT 1285.430 0.350 1298.480 4.280 ;
      LAYER met3 ;
        RECT 4.400 1298.440 1296.000 1299.305 ;
        RECT 0.525 1296.440 1296.000 1298.440 ;
        RECT 4.400 1295.040 1296.000 1296.440 ;
        RECT 0.525 1293.040 1296.000 1295.040 ;
        RECT 4.400 1291.640 1296.000 1293.040 ;
        RECT 0.525 1289.640 1296.000 1291.640 ;
        RECT 4.400 1288.240 1296.000 1289.640 ;
        RECT 0.525 1286.240 1296.000 1288.240 ;
        RECT 4.400 1284.840 1295.600 1286.240 ;
        RECT 0.525 1282.840 1296.000 1284.840 ;
        RECT 4.400 1281.440 1295.600 1282.840 ;
        RECT 0.525 1279.440 1296.000 1281.440 ;
        RECT 4.400 1278.040 1295.600 1279.440 ;
        RECT 0.525 1276.040 1296.000 1278.040 ;
        RECT 4.400 1274.640 1295.600 1276.040 ;
        RECT 0.525 1272.640 1296.000 1274.640 ;
        RECT 4.400 1271.240 1295.600 1272.640 ;
        RECT 0.525 1269.240 1296.000 1271.240 ;
        RECT 4.400 1267.840 1295.600 1269.240 ;
        RECT 0.525 1265.840 1296.000 1267.840 ;
        RECT 4.400 1264.440 1295.600 1265.840 ;
        RECT 0.525 1262.440 1296.000 1264.440 ;
        RECT 4.400 1261.040 1295.600 1262.440 ;
        RECT 0.525 1259.040 1296.000 1261.040 ;
        RECT 4.400 1257.640 1295.600 1259.040 ;
        RECT 0.525 1255.640 1296.000 1257.640 ;
        RECT 4.400 1254.240 1295.600 1255.640 ;
        RECT 0.525 1252.240 1296.000 1254.240 ;
        RECT 4.400 1250.840 1295.600 1252.240 ;
        RECT 0.525 1248.840 1296.000 1250.840 ;
        RECT 4.400 1247.440 1295.600 1248.840 ;
        RECT 0.525 1245.440 1296.000 1247.440 ;
        RECT 4.400 1244.040 1295.600 1245.440 ;
        RECT 0.525 1242.040 1296.000 1244.040 ;
        RECT 4.400 1240.640 1295.600 1242.040 ;
        RECT 0.525 1238.640 1296.000 1240.640 ;
        RECT 4.400 1237.240 1295.600 1238.640 ;
        RECT 0.525 1235.240 1296.000 1237.240 ;
        RECT 4.400 1233.840 1295.600 1235.240 ;
        RECT 0.525 1231.840 1296.000 1233.840 ;
        RECT 4.400 1230.440 1295.600 1231.840 ;
        RECT 0.525 1228.440 1296.000 1230.440 ;
        RECT 4.400 1227.040 1295.600 1228.440 ;
        RECT 0.525 1225.040 1296.000 1227.040 ;
        RECT 4.400 1223.640 1295.600 1225.040 ;
        RECT 0.525 1221.640 1296.000 1223.640 ;
        RECT 4.400 1220.240 1295.600 1221.640 ;
        RECT 0.525 1218.240 1296.000 1220.240 ;
        RECT 4.400 1216.840 1295.600 1218.240 ;
        RECT 0.525 1214.840 1296.000 1216.840 ;
        RECT 4.400 1213.440 1295.600 1214.840 ;
        RECT 0.525 1211.440 1296.000 1213.440 ;
        RECT 4.400 1210.040 1295.600 1211.440 ;
        RECT 0.525 1208.040 1296.000 1210.040 ;
        RECT 4.400 1206.640 1295.600 1208.040 ;
        RECT 0.525 1204.640 1296.000 1206.640 ;
        RECT 4.400 1203.240 1295.600 1204.640 ;
        RECT 0.525 1201.240 1296.000 1203.240 ;
        RECT 4.400 1199.840 1295.600 1201.240 ;
        RECT 0.525 1197.840 1296.000 1199.840 ;
        RECT 4.400 1196.440 1295.600 1197.840 ;
        RECT 0.525 1194.440 1296.000 1196.440 ;
        RECT 4.400 1193.040 1295.600 1194.440 ;
        RECT 0.525 1191.040 1296.000 1193.040 ;
        RECT 4.400 1189.640 1295.600 1191.040 ;
        RECT 0.525 1187.640 1296.000 1189.640 ;
        RECT 4.400 1186.240 1295.600 1187.640 ;
        RECT 0.525 1184.240 1296.000 1186.240 ;
        RECT 4.400 1182.840 1295.600 1184.240 ;
        RECT 0.525 1180.840 1296.000 1182.840 ;
        RECT 4.400 1179.440 1295.600 1180.840 ;
        RECT 0.525 1177.440 1296.000 1179.440 ;
        RECT 4.400 1176.040 1295.600 1177.440 ;
        RECT 0.525 1174.040 1296.000 1176.040 ;
        RECT 4.400 1172.640 1295.600 1174.040 ;
        RECT 0.525 1170.640 1296.000 1172.640 ;
        RECT 4.400 1169.240 1295.600 1170.640 ;
        RECT 0.525 1167.240 1296.000 1169.240 ;
        RECT 4.400 1165.840 1295.600 1167.240 ;
        RECT 0.525 1163.840 1296.000 1165.840 ;
        RECT 4.400 1162.440 1295.600 1163.840 ;
        RECT 0.525 1160.440 1296.000 1162.440 ;
        RECT 4.400 1159.040 1295.600 1160.440 ;
        RECT 0.525 1157.040 1296.000 1159.040 ;
        RECT 4.400 1155.640 1295.600 1157.040 ;
        RECT 0.525 1153.640 1296.000 1155.640 ;
        RECT 4.400 1152.240 1295.600 1153.640 ;
        RECT 0.525 1150.240 1296.000 1152.240 ;
        RECT 4.400 1148.840 1295.600 1150.240 ;
        RECT 0.525 1146.840 1296.000 1148.840 ;
        RECT 4.400 1145.440 1295.600 1146.840 ;
        RECT 0.525 1143.440 1296.000 1145.440 ;
        RECT 4.400 1142.040 1295.600 1143.440 ;
        RECT 0.525 1140.040 1296.000 1142.040 ;
        RECT 4.400 1138.640 1295.600 1140.040 ;
        RECT 0.525 1136.640 1296.000 1138.640 ;
        RECT 4.400 1135.240 1295.600 1136.640 ;
        RECT 0.525 1133.240 1296.000 1135.240 ;
        RECT 4.400 1131.840 1295.600 1133.240 ;
        RECT 0.525 1129.840 1296.000 1131.840 ;
        RECT 4.400 1128.440 1295.600 1129.840 ;
        RECT 0.525 1126.440 1296.000 1128.440 ;
        RECT 4.400 1125.040 1295.600 1126.440 ;
        RECT 0.525 1123.040 1296.000 1125.040 ;
        RECT 4.400 1121.640 1295.600 1123.040 ;
        RECT 0.525 1119.640 1296.000 1121.640 ;
        RECT 4.400 1118.240 1295.600 1119.640 ;
        RECT 0.525 1116.240 1296.000 1118.240 ;
        RECT 4.400 1114.840 1295.600 1116.240 ;
        RECT 0.525 1112.840 1296.000 1114.840 ;
        RECT 4.400 1111.440 1295.600 1112.840 ;
        RECT 0.525 1109.440 1296.000 1111.440 ;
        RECT 4.400 1108.040 1295.600 1109.440 ;
        RECT 0.525 1106.040 1296.000 1108.040 ;
        RECT 4.400 1104.640 1295.600 1106.040 ;
        RECT 0.525 1102.640 1296.000 1104.640 ;
        RECT 4.400 1101.240 1295.600 1102.640 ;
        RECT 0.525 1099.240 1296.000 1101.240 ;
        RECT 4.400 1097.840 1295.600 1099.240 ;
        RECT 0.525 1095.840 1296.000 1097.840 ;
        RECT 4.400 1094.440 1295.600 1095.840 ;
        RECT 0.525 1092.440 1296.000 1094.440 ;
        RECT 4.400 1091.040 1295.600 1092.440 ;
        RECT 0.525 1089.040 1296.000 1091.040 ;
        RECT 4.400 1087.640 1295.600 1089.040 ;
        RECT 0.525 1085.640 1296.000 1087.640 ;
        RECT 4.400 1084.240 1295.600 1085.640 ;
        RECT 0.525 1082.240 1296.000 1084.240 ;
        RECT 4.400 1080.840 1295.600 1082.240 ;
        RECT 0.525 1078.840 1296.000 1080.840 ;
        RECT 4.400 1077.440 1295.600 1078.840 ;
        RECT 0.525 1075.440 1296.000 1077.440 ;
        RECT 4.400 1074.040 1295.600 1075.440 ;
        RECT 0.525 1072.040 1296.000 1074.040 ;
        RECT 4.400 1070.640 1295.600 1072.040 ;
        RECT 0.525 1068.640 1296.000 1070.640 ;
        RECT 4.400 1067.240 1295.600 1068.640 ;
        RECT 0.525 1065.240 1296.000 1067.240 ;
        RECT 4.400 1063.840 1295.600 1065.240 ;
        RECT 0.525 1061.840 1296.000 1063.840 ;
        RECT 4.400 1060.440 1295.600 1061.840 ;
        RECT 0.525 1058.440 1296.000 1060.440 ;
        RECT 4.400 1057.040 1295.600 1058.440 ;
        RECT 0.525 1055.040 1296.000 1057.040 ;
        RECT 4.400 1053.640 1295.600 1055.040 ;
        RECT 0.525 1051.640 1296.000 1053.640 ;
        RECT 4.400 1050.240 1295.600 1051.640 ;
        RECT 0.525 1048.240 1296.000 1050.240 ;
        RECT 4.400 1046.840 1295.600 1048.240 ;
        RECT 0.525 1044.840 1296.000 1046.840 ;
        RECT 4.400 1043.440 1295.600 1044.840 ;
        RECT 0.525 1041.440 1296.000 1043.440 ;
        RECT 4.400 1040.040 1295.600 1041.440 ;
        RECT 0.525 1038.040 1296.000 1040.040 ;
        RECT 4.400 1036.640 1295.600 1038.040 ;
        RECT 0.525 1034.640 1296.000 1036.640 ;
        RECT 4.400 1033.240 1295.600 1034.640 ;
        RECT 0.525 1031.240 1296.000 1033.240 ;
        RECT 4.400 1029.840 1295.600 1031.240 ;
        RECT 0.525 1027.840 1296.000 1029.840 ;
        RECT 4.400 1026.440 1295.600 1027.840 ;
        RECT 0.525 1024.440 1296.000 1026.440 ;
        RECT 4.400 1023.040 1295.600 1024.440 ;
        RECT 0.525 1021.040 1296.000 1023.040 ;
        RECT 4.400 1019.640 1295.600 1021.040 ;
        RECT 0.525 1017.640 1296.000 1019.640 ;
        RECT 4.400 1016.240 1295.600 1017.640 ;
        RECT 0.525 1014.240 1296.000 1016.240 ;
        RECT 4.400 1012.840 1295.600 1014.240 ;
        RECT 0.525 1010.840 1296.000 1012.840 ;
        RECT 4.400 1009.440 1295.600 1010.840 ;
        RECT 0.525 1007.440 1296.000 1009.440 ;
        RECT 4.400 1006.040 1295.600 1007.440 ;
        RECT 0.525 1004.040 1296.000 1006.040 ;
        RECT 4.400 1002.640 1295.600 1004.040 ;
        RECT 0.525 1000.640 1296.000 1002.640 ;
        RECT 4.400 999.240 1295.600 1000.640 ;
        RECT 0.525 997.240 1296.000 999.240 ;
        RECT 4.400 995.840 1295.600 997.240 ;
        RECT 0.525 993.840 1296.000 995.840 ;
        RECT 4.400 992.440 1295.600 993.840 ;
        RECT 0.525 990.440 1296.000 992.440 ;
        RECT 4.400 989.040 1295.600 990.440 ;
        RECT 0.525 987.040 1296.000 989.040 ;
        RECT 4.400 985.640 1295.600 987.040 ;
        RECT 0.525 983.640 1296.000 985.640 ;
        RECT 4.400 982.240 1295.600 983.640 ;
        RECT 0.525 980.240 1296.000 982.240 ;
        RECT 4.400 978.840 1295.600 980.240 ;
        RECT 0.525 976.840 1296.000 978.840 ;
        RECT 4.400 975.440 1295.600 976.840 ;
        RECT 0.525 973.440 1296.000 975.440 ;
        RECT 4.400 972.040 1295.600 973.440 ;
        RECT 0.525 970.040 1296.000 972.040 ;
        RECT 4.400 968.640 1295.600 970.040 ;
        RECT 0.525 966.640 1296.000 968.640 ;
        RECT 4.400 965.240 1295.600 966.640 ;
        RECT 0.525 963.240 1296.000 965.240 ;
        RECT 4.400 961.840 1295.600 963.240 ;
        RECT 0.525 959.840 1296.000 961.840 ;
        RECT 4.400 958.440 1295.600 959.840 ;
        RECT 0.525 956.440 1296.000 958.440 ;
        RECT 4.400 955.040 1295.600 956.440 ;
        RECT 0.525 953.040 1296.000 955.040 ;
        RECT 4.400 951.640 1295.600 953.040 ;
        RECT 0.525 949.640 1296.000 951.640 ;
        RECT 4.400 948.240 1295.600 949.640 ;
        RECT 0.525 946.240 1296.000 948.240 ;
        RECT 4.400 944.840 1295.600 946.240 ;
        RECT 0.525 942.840 1296.000 944.840 ;
        RECT 4.400 941.440 1295.600 942.840 ;
        RECT 0.525 939.440 1296.000 941.440 ;
        RECT 4.400 938.040 1295.600 939.440 ;
        RECT 0.525 936.040 1296.000 938.040 ;
        RECT 4.400 934.640 1295.600 936.040 ;
        RECT 0.525 932.640 1296.000 934.640 ;
        RECT 4.400 931.240 1295.600 932.640 ;
        RECT 0.525 929.240 1296.000 931.240 ;
        RECT 4.400 927.840 1295.600 929.240 ;
        RECT 0.525 925.840 1296.000 927.840 ;
        RECT 4.400 924.440 1295.600 925.840 ;
        RECT 0.525 922.440 1296.000 924.440 ;
        RECT 4.400 921.040 1295.600 922.440 ;
        RECT 0.525 919.040 1296.000 921.040 ;
        RECT 4.400 917.640 1295.600 919.040 ;
        RECT 0.525 915.640 1296.000 917.640 ;
        RECT 4.400 914.240 1295.600 915.640 ;
        RECT 0.525 912.240 1296.000 914.240 ;
        RECT 4.400 910.840 1295.600 912.240 ;
        RECT 0.525 908.840 1296.000 910.840 ;
        RECT 4.400 907.440 1295.600 908.840 ;
        RECT 0.525 905.440 1296.000 907.440 ;
        RECT 4.400 904.040 1295.600 905.440 ;
        RECT 0.525 902.040 1296.000 904.040 ;
        RECT 4.400 900.640 1295.600 902.040 ;
        RECT 0.525 898.640 1296.000 900.640 ;
        RECT 4.400 897.240 1295.600 898.640 ;
        RECT 0.525 895.240 1296.000 897.240 ;
        RECT 4.400 893.840 1295.600 895.240 ;
        RECT 0.525 891.840 1296.000 893.840 ;
        RECT 4.400 890.440 1295.600 891.840 ;
        RECT 0.525 888.440 1296.000 890.440 ;
        RECT 4.400 887.040 1295.600 888.440 ;
        RECT 0.525 885.040 1296.000 887.040 ;
        RECT 4.400 883.640 1295.600 885.040 ;
        RECT 0.525 881.640 1296.000 883.640 ;
        RECT 4.400 880.240 1295.600 881.640 ;
        RECT 0.525 878.240 1296.000 880.240 ;
        RECT 4.400 876.840 1295.600 878.240 ;
        RECT 0.525 874.840 1296.000 876.840 ;
        RECT 4.400 873.440 1295.600 874.840 ;
        RECT 0.525 871.440 1296.000 873.440 ;
        RECT 4.400 870.040 1295.600 871.440 ;
        RECT 0.525 868.040 1296.000 870.040 ;
        RECT 4.400 866.640 1295.600 868.040 ;
        RECT 0.525 864.640 1296.000 866.640 ;
        RECT 4.400 863.240 1295.600 864.640 ;
        RECT 0.525 861.240 1296.000 863.240 ;
        RECT 4.400 859.840 1295.600 861.240 ;
        RECT 0.525 857.840 1296.000 859.840 ;
        RECT 4.400 856.440 1295.600 857.840 ;
        RECT 0.525 854.440 1296.000 856.440 ;
        RECT 4.400 853.040 1295.600 854.440 ;
        RECT 0.525 851.040 1296.000 853.040 ;
        RECT 4.400 849.640 1295.600 851.040 ;
        RECT 0.525 847.640 1296.000 849.640 ;
        RECT 4.400 846.240 1295.600 847.640 ;
        RECT 0.525 844.240 1296.000 846.240 ;
        RECT 4.400 842.840 1295.600 844.240 ;
        RECT 0.525 840.840 1296.000 842.840 ;
        RECT 4.400 839.440 1295.600 840.840 ;
        RECT 0.525 837.440 1296.000 839.440 ;
        RECT 4.400 836.040 1295.600 837.440 ;
        RECT 0.525 834.040 1296.000 836.040 ;
        RECT 4.400 832.640 1295.600 834.040 ;
        RECT 0.525 830.640 1296.000 832.640 ;
        RECT 4.400 829.240 1295.600 830.640 ;
        RECT 0.525 827.240 1296.000 829.240 ;
        RECT 4.400 825.840 1295.600 827.240 ;
        RECT 0.525 823.840 1296.000 825.840 ;
        RECT 4.400 822.440 1295.600 823.840 ;
        RECT 0.525 820.440 1296.000 822.440 ;
        RECT 4.400 819.040 1295.600 820.440 ;
        RECT 0.525 817.040 1296.000 819.040 ;
        RECT 4.400 815.640 1295.600 817.040 ;
        RECT 0.525 813.640 1296.000 815.640 ;
        RECT 4.400 812.240 1295.600 813.640 ;
        RECT 0.525 810.240 1296.000 812.240 ;
        RECT 4.400 808.840 1295.600 810.240 ;
        RECT 0.525 806.840 1296.000 808.840 ;
        RECT 4.400 805.440 1295.600 806.840 ;
        RECT 0.525 803.440 1296.000 805.440 ;
        RECT 4.400 802.040 1295.600 803.440 ;
        RECT 0.525 800.040 1296.000 802.040 ;
        RECT 4.400 798.640 1295.600 800.040 ;
        RECT 0.525 796.640 1296.000 798.640 ;
        RECT 4.400 795.240 1295.600 796.640 ;
        RECT 0.525 793.240 1296.000 795.240 ;
        RECT 4.400 791.840 1295.600 793.240 ;
        RECT 0.525 789.840 1296.000 791.840 ;
        RECT 4.400 788.440 1295.600 789.840 ;
        RECT 0.525 786.440 1296.000 788.440 ;
        RECT 4.400 785.040 1295.600 786.440 ;
        RECT 0.525 783.040 1296.000 785.040 ;
        RECT 4.400 781.640 1295.600 783.040 ;
        RECT 0.525 779.640 1296.000 781.640 ;
        RECT 4.400 778.240 1295.600 779.640 ;
        RECT 0.525 776.240 1296.000 778.240 ;
        RECT 4.400 774.840 1295.600 776.240 ;
        RECT 0.525 772.840 1296.000 774.840 ;
        RECT 4.400 771.440 1295.600 772.840 ;
        RECT 0.525 769.440 1296.000 771.440 ;
        RECT 4.400 768.040 1295.600 769.440 ;
        RECT 0.525 766.040 1296.000 768.040 ;
        RECT 4.400 764.640 1295.600 766.040 ;
        RECT 0.525 762.640 1296.000 764.640 ;
        RECT 4.400 761.240 1295.600 762.640 ;
        RECT 0.525 759.240 1296.000 761.240 ;
        RECT 4.400 757.840 1295.600 759.240 ;
        RECT 0.525 755.840 1296.000 757.840 ;
        RECT 4.400 754.440 1295.600 755.840 ;
        RECT 0.525 752.440 1296.000 754.440 ;
        RECT 4.400 751.040 1295.600 752.440 ;
        RECT 0.525 749.040 1296.000 751.040 ;
        RECT 4.400 747.640 1295.600 749.040 ;
        RECT 0.525 745.640 1296.000 747.640 ;
        RECT 4.400 744.240 1295.600 745.640 ;
        RECT 0.525 742.240 1296.000 744.240 ;
        RECT 4.400 740.840 1295.600 742.240 ;
        RECT 0.525 738.840 1296.000 740.840 ;
        RECT 4.400 737.440 1295.600 738.840 ;
        RECT 0.525 735.440 1296.000 737.440 ;
        RECT 4.400 734.040 1295.600 735.440 ;
        RECT 0.525 732.040 1296.000 734.040 ;
        RECT 4.400 730.640 1295.600 732.040 ;
        RECT 0.525 728.640 1296.000 730.640 ;
        RECT 4.400 727.240 1295.600 728.640 ;
        RECT 0.525 725.240 1296.000 727.240 ;
        RECT 4.400 723.840 1295.600 725.240 ;
        RECT 0.525 721.840 1296.000 723.840 ;
        RECT 4.400 720.440 1295.600 721.840 ;
        RECT 0.525 718.440 1296.000 720.440 ;
        RECT 4.400 717.040 1295.600 718.440 ;
        RECT 0.525 715.040 1296.000 717.040 ;
        RECT 4.400 713.640 1295.600 715.040 ;
        RECT 0.525 711.640 1296.000 713.640 ;
        RECT 4.400 710.240 1295.600 711.640 ;
        RECT 0.525 708.240 1296.000 710.240 ;
        RECT 4.400 706.840 1295.600 708.240 ;
        RECT 0.525 704.840 1296.000 706.840 ;
        RECT 4.400 703.440 1295.600 704.840 ;
        RECT 0.525 701.440 1296.000 703.440 ;
        RECT 4.400 700.040 1295.600 701.440 ;
        RECT 0.525 698.040 1296.000 700.040 ;
        RECT 4.400 696.640 1295.600 698.040 ;
        RECT 0.525 694.640 1296.000 696.640 ;
        RECT 4.400 693.240 1295.600 694.640 ;
        RECT 0.525 691.240 1296.000 693.240 ;
        RECT 4.400 689.840 1295.600 691.240 ;
        RECT 0.525 687.840 1296.000 689.840 ;
        RECT 4.400 686.440 1295.600 687.840 ;
        RECT 0.525 684.440 1296.000 686.440 ;
        RECT 4.400 683.040 1295.600 684.440 ;
        RECT 0.525 681.040 1296.000 683.040 ;
        RECT 4.400 679.640 1295.600 681.040 ;
        RECT 0.525 677.640 1296.000 679.640 ;
        RECT 4.400 676.240 1295.600 677.640 ;
        RECT 0.525 674.240 1296.000 676.240 ;
        RECT 4.400 672.840 1295.600 674.240 ;
        RECT 0.525 670.840 1296.000 672.840 ;
        RECT 4.400 669.440 1295.600 670.840 ;
        RECT 0.525 667.440 1296.000 669.440 ;
        RECT 4.400 666.040 1295.600 667.440 ;
        RECT 0.525 664.040 1296.000 666.040 ;
        RECT 4.400 662.640 1295.600 664.040 ;
        RECT 0.525 660.640 1296.000 662.640 ;
        RECT 4.400 659.240 1295.600 660.640 ;
        RECT 0.525 657.240 1296.000 659.240 ;
        RECT 4.400 655.840 1295.600 657.240 ;
        RECT 0.525 653.840 1296.000 655.840 ;
        RECT 4.400 652.440 1295.600 653.840 ;
        RECT 0.525 650.440 1296.000 652.440 ;
        RECT 4.400 649.040 1295.600 650.440 ;
        RECT 0.525 647.040 1296.000 649.040 ;
        RECT 4.400 645.640 1295.600 647.040 ;
        RECT 0.525 643.640 1296.000 645.640 ;
        RECT 4.400 642.240 1295.600 643.640 ;
        RECT 0.525 640.240 1296.000 642.240 ;
        RECT 4.400 638.840 1295.600 640.240 ;
        RECT 0.525 636.840 1296.000 638.840 ;
        RECT 4.400 635.440 1295.600 636.840 ;
        RECT 0.525 633.440 1296.000 635.440 ;
        RECT 4.400 632.040 1295.600 633.440 ;
        RECT 0.525 630.040 1296.000 632.040 ;
        RECT 4.400 628.640 1295.600 630.040 ;
        RECT 0.525 626.640 1296.000 628.640 ;
        RECT 4.400 625.240 1295.600 626.640 ;
        RECT 0.525 623.240 1296.000 625.240 ;
        RECT 4.400 621.840 1295.600 623.240 ;
        RECT 0.525 619.840 1296.000 621.840 ;
        RECT 4.400 618.440 1295.600 619.840 ;
        RECT 0.525 616.440 1296.000 618.440 ;
        RECT 4.400 615.040 1295.600 616.440 ;
        RECT 0.525 613.040 1296.000 615.040 ;
        RECT 4.400 611.640 1295.600 613.040 ;
        RECT 0.525 609.640 1296.000 611.640 ;
        RECT 4.400 608.240 1295.600 609.640 ;
        RECT 0.525 606.240 1296.000 608.240 ;
        RECT 4.400 604.840 1295.600 606.240 ;
        RECT 0.525 602.840 1296.000 604.840 ;
        RECT 4.400 601.440 1295.600 602.840 ;
        RECT 0.525 599.440 1296.000 601.440 ;
        RECT 4.400 598.040 1295.600 599.440 ;
        RECT 0.525 596.040 1296.000 598.040 ;
        RECT 4.400 594.640 1295.600 596.040 ;
        RECT 0.525 592.640 1296.000 594.640 ;
        RECT 4.400 591.240 1295.600 592.640 ;
        RECT 0.525 589.240 1296.000 591.240 ;
        RECT 4.400 587.840 1295.600 589.240 ;
        RECT 0.525 585.840 1296.000 587.840 ;
        RECT 4.400 584.440 1295.600 585.840 ;
        RECT 0.525 582.440 1296.000 584.440 ;
        RECT 4.400 581.040 1295.600 582.440 ;
        RECT 0.525 579.040 1296.000 581.040 ;
        RECT 4.400 577.640 1295.600 579.040 ;
        RECT 0.525 575.640 1296.000 577.640 ;
        RECT 4.400 574.240 1295.600 575.640 ;
        RECT 0.525 572.240 1296.000 574.240 ;
        RECT 4.400 570.840 1295.600 572.240 ;
        RECT 0.525 568.840 1296.000 570.840 ;
        RECT 4.400 567.440 1295.600 568.840 ;
        RECT 0.525 565.440 1296.000 567.440 ;
        RECT 4.400 564.040 1295.600 565.440 ;
        RECT 0.525 562.040 1296.000 564.040 ;
        RECT 4.400 560.640 1295.600 562.040 ;
        RECT 0.525 558.640 1296.000 560.640 ;
        RECT 4.400 557.240 1295.600 558.640 ;
        RECT 0.525 555.240 1296.000 557.240 ;
        RECT 4.400 553.840 1295.600 555.240 ;
        RECT 0.525 551.840 1296.000 553.840 ;
        RECT 4.400 550.440 1295.600 551.840 ;
        RECT 0.525 548.440 1296.000 550.440 ;
        RECT 4.400 547.040 1295.600 548.440 ;
        RECT 0.525 545.040 1296.000 547.040 ;
        RECT 4.400 543.640 1295.600 545.040 ;
        RECT 0.525 541.640 1296.000 543.640 ;
        RECT 4.400 540.240 1295.600 541.640 ;
        RECT 0.525 538.240 1296.000 540.240 ;
        RECT 4.400 536.840 1295.600 538.240 ;
        RECT 0.525 534.840 1296.000 536.840 ;
        RECT 4.400 533.440 1295.600 534.840 ;
        RECT 0.525 531.440 1296.000 533.440 ;
        RECT 4.400 530.040 1295.600 531.440 ;
        RECT 0.525 528.040 1296.000 530.040 ;
        RECT 4.400 526.640 1295.600 528.040 ;
        RECT 0.525 524.640 1296.000 526.640 ;
        RECT 4.400 523.240 1295.600 524.640 ;
        RECT 0.525 521.240 1296.000 523.240 ;
        RECT 4.400 519.840 1295.600 521.240 ;
        RECT 0.525 517.840 1296.000 519.840 ;
        RECT 4.400 516.440 1295.600 517.840 ;
        RECT 0.525 514.440 1296.000 516.440 ;
        RECT 4.400 513.040 1295.600 514.440 ;
        RECT 0.525 511.040 1296.000 513.040 ;
        RECT 4.400 509.640 1295.600 511.040 ;
        RECT 0.525 507.640 1296.000 509.640 ;
        RECT 4.400 506.240 1295.600 507.640 ;
        RECT 0.525 504.240 1296.000 506.240 ;
        RECT 4.400 502.840 1295.600 504.240 ;
        RECT 0.525 500.840 1296.000 502.840 ;
        RECT 4.400 499.440 1295.600 500.840 ;
        RECT 0.525 497.440 1296.000 499.440 ;
        RECT 4.400 496.040 1295.600 497.440 ;
        RECT 0.525 494.040 1296.000 496.040 ;
        RECT 4.400 492.640 1295.600 494.040 ;
        RECT 0.525 490.640 1296.000 492.640 ;
        RECT 4.400 489.240 1295.600 490.640 ;
        RECT 0.525 487.240 1296.000 489.240 ;
        RECT 4.400 485.840 1295.600 487.240 ;
        RECT 0.525 483.840 1296.000 485.840 ;
        RECT 4.400 482.440 1295.600 483.840 ;
        RECT 0.525 480.440 1296.000 482.440 ;
        RECT 4.400 479.040 1295.600 480.440 ;
        RECT 0.525 477.040 1296.000 479.040 ;
        RECT 4.400 475.640 1295.600 477.040 ;
        RECT 0.525 473.640 1296.000 475.640 ;
        RECT 4.400 472.240 1295.600 473.640 ;
        RECT 0.525 470.240 1296.000 472.240 ;
        RECT 4.400 468.840 1295.600 470.240 ;
        RECT 0.525 466.840 1296.000 468.840 ;
        RECT 4.400 465.440 1295.600 466.840 ;
        RECT 0.525 463.440 1296.000 465.440 ;
        RECT 4.400 462.040 1295.600 463.440 ;
        RECT 0.525 460.040 1296.000 462.040 ;
        RECT 4.400 458.640 1295.600 460.040 ;
        RECT 0.525 456.640 1296.000 458.640 ;
        RECT 4.400 455.240 1295.600 456.640 ;
        RECT 0.525 453.240 1296.000 455.240 ;
        RECT 4.400 451.840 1295.600 453.240 ;
        RECT 0.525 449.840 1296.000 451.840 ;
        RECT 4.400 448.440 1295.600 449.840 ;
        RECT 0.525 446.440 1296.000 448.440 ;
        RECT 4.400 445.040 1295.600 446.440 ;
        RECT 0.525 443.040 1296.000 445.040 ;
        RECT 4.400 441.640 1295.600 443.040 ;
        RECT 0.525 439.640 1296.000 441.640 ;
        RECT 4.400 438.240 1295.600 439.640 ;
        RECT 0.525 436.240 1296.000 438.240 ;
        RECT 4.400 434.840 1295.600 436.240 ;
        RECT 0.525 432.840 1296.000 434.840 ;
        RECT 4.400 431.440 1295.600 432.840 ;
        RECT 0.525 429.440 1296.000 431.440 ;
        RECT 4.400 428.040 1295.600 429.440 ;
        RECT 0.525 426.040 1296.000 428.040 ;
        RECT 4.400 424.640 1295.600 426.040 ;
        RECT 0.525 422.640 1296.000 424.640 ;
        RECT 4.400 421.240 1295.600 422.640 ;
        RECT 0.525 419.240 1296.000 421.240 ;
        RECT 4.400 417.840 1295.600 419.240 ;
        RECT 0.525 415.840 1296.000 417.840 ;
        RECT 4.400 414.440 1295.600 415.840 ;
        RECT 0.525 412.440 1296.000 414.440 ;
        RECT 4.400 411.040 1295.600 412.440 ;
        RECT 0.525 409.040 1296.000 411.040 ;
        RECT 4.400 407.640 1295.600 409.040 ;
        RECT 0.525 405.640 1296.000 407.640 ;
        RECT 4.400 404.240 1295.600 405.640 ;
        RECT 0.525 402.240 1296.000 404.240 ;
        RECT 4.400 400.840 1295.600 402.240 ;
        RECT 0.525 398.840 1296.000 400.840 ;
        RECT 4.400 397.440 1295.600 398.840 ;
        RECT 0.525 395.440 1296.000 397.440 ;
        RECT 4.400 394.040 1295.600 395.440 ;
        RECT 0.525 392.040 1296.000 394.040 ;
        RECT 4.400 390.640 1295.600 392.040 ;
        RECT 0.525 388.640 1296.000 390.640 ;
        RECT 4.400 387.240 1295.600 388.640 ;
        RECT 0.525 385.240 1296.000 387.240 ;
        RECT 4.400 383.840 1295.600 385.240 ;
        RECT 0.525 381.840 1296.000 383.840 ;
        RECT 4.400 380.440 1295.600 381.840 ;
        RECT 0.525 378.440 1296.000 380.440 ;
        RECT 4.400 377.040 1295.600 378.440 ;
        RECT 0.525 375.040 1296.000 377.040 ;
        RECT 4.400 373.640 1295.600 375.040 ;
        RECT 0.525 371.640 1296.000 373.640 ;
        RECT 4.400 370.240 1295.600 371.640 ;
        RECT 0.525 368.240 1296.000 370.240 ;
        RECT 4.400 366.840 1295.600 368.240 ;
        RECT 0.525 364.840 1296.000 366.840 ;
        RECT 4.400 363.440 1295.600 364.840 ;
        RECT 0.525 361.440 1296.000 363.440 ;
        RECT 4.400 360.040 1295.600 361.440 ;
        RECT 0.525 358.040 1296.000 360.040 ;
        RECT 4.400 356.640 1295.600 358.040 ;
        RECT 0.525 354.640 1296.000 356.640 ;
        RECT 4.400 353.240 1295.600 354.640 ;
        RECT 0.525 351.240 1296.000 353.240 ;
        RECT 4.400 349.840 1295.600 351.240 ;
        RECT 0.525 347.840 1296.000 349.840 ;
        RECT 4.400 346.440 1295.600 347.840 ;
        RECT 0.525 344.440 1296.000 346.440 ;
        RECT 4.400 343.040 1295.600 344.440 ;
        RECT 0.525 341.040 1296.000 343.040 ;
        RECT 4.400 339.640 1295.600 341.040 ;
        RECT 0.525 337.640 1296.000 339.640 ;
        RECT 4.400 336.240 1295.600 337.640 ;
        RECT 0.525 334.240 1296.000 336.240 ;
        RECT 4.400 332.840 1295.600 334.240 ;
        RECT 0.525 330.840 1296.000 332.840 ;
        RECT 4.400 329.440 1295.600 330.840 ;
        RECT 0.525 327.440 1296.000 329.440 ;
        RECT 4.400 326.040 1295.600 327.440 ;
        RECT 0.525 324.040 1296.000 326.040 ;
        RECT 4.400 322.640 1295.600 324.040 ;
        RECT 0.525 320.640 1296.000 322.640 ;
        RECT 4.400 319.240 1295.600 320.640 ;
        RECT 0.525 317.240 1296.000 319.240 ;
        RECT 4.400 315.840 1295.600 317.240 ;
        RECT 0.525 313.840 1296.000 315.840 ;
        RECT 4.400 312.440 1295.600 313.840 ;
        RECT 0.525 310.440 1296.000 312.440 ;
        RECT 4.400 309.040 1295.600 310.440 ;
        RECT 0.525 307.040 1296.000 309.040 ;
        RECT 4.400 305.640 1295.600 307.040 ;
        RECT 0.525 303.640 1296.000 305.640 ;
        RECT 4.400 302.240 1295.600 303.640 ;
        RECT 0.525 300.240 1296.000 302.240 ;
        RECT 4.400 298.840 1295.600 300.240 ;
        RECT 0.525 296.840 1296.000 298.840 ;
        RECT 4.400 295.440 1295.600 296.840 ;
        RECT 0.525 293.440 1296.000 295.440 ;
        RECT 4.400 292.040 1295.600 293.440 ;
        RECT 0.525 290.040 1296.000 292.040 ;
        RECT 4.400 288.640 1295.600 290.040 ;
        RECT 0.525 286.640 1296.000 288.640 ;
        RECT 4.400 285.240 1295.600 286.640 ;
        RECT 0.525 283.240 1296.000 285.240 ;
        RECT 4.400 281.840 1295.600 283.240 ;
        RECT 0.525 279.840 1296.000 281.840 ;
        RECT 4.400 278.440 1295.600 279.840 ;
        RECT 0.525 276.440 1296.000 278.440 ;
        RECT 4.400 275.040 1295.600 276.440 ;
        RECT 0.525 273.040 1296.000 275.040 ;
        RECT 4.400 271.640 1295.600 273.040 ;
        RECT 0.525 269.640 1296.000 271.640 ;
        RECT 4.400 268.240 1295.600 269.640 ;
        RECT 0.525 266.240 1296.000 268.240 ;
        RECT 4.400 264.840 1295.600 266.240 ;
        RECT 0.525 262.840 1296.000 264.840 ;
        RECT 4.400 261.440 1295.600 262.840 ;
        RECT 0.525 259.440 1296.000 261.440 ;
        RECT 4.400 258.040 1295.600 259.440 ;
        RECT 0.525 256.040 1296.000 258.040 ;
        RECT 4.400 254.640 1295.600 256.040 ;
        RECT 0.525 252.640 1296.000 254.640 ;
        RECT 4.400 251.240 1295.600 252.640 ;
        RECT 0.525 249.240 1296.000 251.240 ;
        RECT 4.400 247.840 1295.600 249.240 ;
        RECT 0.525 245.840 1296.000 247.840 ;
        RECT 4.400 244.440 1295.600 245.840 ;
        RECT 0.525 242.440 1296.000 244.440 ;
        RECT 4.400 241.040 1295.600 242.440 ;
        RECT 0.525 239.040 1296.000 241.040 ;
        RECT 4.400 237.640 1295.600 239.040 ;
        RECT 0.525 235.640 1296.000 237.640 ;
        RECT 4.400 234.240 1295.600 235.640 ;
        RECT 0.525 232.240 1296.000 234.240 ;
        RECT 4.400 230.840 1295.600 232.240 ;
        RECT 0.525 228.840 1296.000 230.840 ;
        RECT 4.400 227.440 1295.600 228.840 ;
        RECT 0.525 225.440 1296.000 227.440 ;
        RECT 4.400 224.040 1295.600 225.440 ;
        RECT 0.525 222.040 1296.000 224.040 ;
        RECT 4.400 220.640 1295.600 222.040 ;
        RECT 0.525 218.640 1296.000 220.640 ;
        RECT 4.400 217.240 1295.600 218.640 ;
        RECT 0.525 215.240 1296.000 217.240 ;
        RECT 4.400 213.840 1295.600 215.240 ;
        RECT 0.525 211.840 1296.000 213.840 ;
        RECT 4.400 210.440 1295.600 211.840 ;
        RECT 0.525 208.440 1296.000 210.440 ;
        RECT 4.400 207.040 1295.600 208.440 ;
        RECT 0.525 205.040 1296.000 207.040 ;
        RECT 4.400 203.640 1295.600 205.040 ;
        RECT 0.525 201.640 1296.000 203.640 ;
        RECT 4.400 200.240 1295.600 201.640 ;
        RECT 0.525 198.240 1296.000 200.240 ;
        RECT 4.400 196.840 1296.000 198.240 ;
        RECT 0.525 194.840 1296.000 196.840 ;
        RECT 4.400 193.440 1296.000 194.840 ;
        RECT 0.525 191.440 1296.000 193.440 ;
        RECT 4.400 190.040 1296.000 191.440 ;
        RECT 0.525 188.040 1296.000 190.040 ;
        RECT 4.400 186.640 1296.000 188.040 ;
        RECT 0.525 184.640 1296.000 186.640 ;
        RECT 4.400 183.240 1296.000 184.640 ;
        RECT 0.525 181.240 1296.000 183.240 ;
        RECT 4.400 179.840 1296.000 181.240 ;
        RECT 0.525 177.840 1296.000 179.840 ;
        RECT 4.400 176.440 1296.000 177.840 ;
        RECT 0.525 174.440 1296.000 176.440 ;
        RECT 4.400 173.040 1296.000 174.440 ;
        RECT 0.525 171.040 1296.000 173.040 ;
        RECT 4.400 169.640 1296.000 171.040 ;
        RECT 0.525 167.640 1296.000 169.640 ;
        RECT 4.400 166.240 1296.000 167.640 ;
        RECT 0.525 164.240 1296.000 166.240 ;
        RECT 4.400 162.840 1296.000 164.240 ;
        RECT 0.525 160.840 1296.000 162.840 ;
        RECT 4.400 159.440 1296.000 160.840 ;
        RECT 0.525 157.440 1296.000 159.440 ;
        RECT 4.400 156.040 1296.000 157.440 ;
        RECT 0.525 154.040 1296.000 156.040 ;
        RECT 4.400 152.640 1296.000 154.040 ;
        RECT 0.525 150.640 1296.000 152.640 ;
        RECT 4.400 149.240 1296.000 150.640 ;
        RECT 0.525 147.240 1296.000 149.240 ;
        RECT 4.400 145.840 1296.000 147.240 ;
        RECT 0.525 143.840 1296.000 145.840 ;
        RECT 4.400 142.440 1296.000 143.840 ;
        RECT 0.525 140.440 1296.000 142.440 ;
        RECT 4.400 139.040 1296.000 140.440 ;
        RECT 0.525 137.040 1296.000 139.040 ;
        RECT 4.400 135.640 1296.000 137.040 ;
        RECT 0.525 133.640 1296.000 135.640 ;
        RECT 4.400 132.240 1296.000 133.640 ;
        RECT 0.525 130.240 1296.000 132.240 ;
        RECT 4.400 128.840 1296.000 130.240 ;
        RECT 0.525 126.840 1296.000 128.840 ;
        RECT 4.400 125.440 1296.000 126.840 ;
        RECT 0.525 123.440 1296.000 125.440 ;
        RECT 4.400 122.040 1296.000 123.440 ;
        RECT 0.525 120.040 1296.000 122.040 ;
        RECT 4.400 118.640 1296.000 120.040 ;
        RECT 0.525 116.640 1296.000 118.640 ;
        RECT 4.400 115.240 1296.000 116.640 ;
        RECT 0.525 113.240 1296.000 115.240 ;
        RECT 4.400 111.840 1296.000 113.240 ;
        RECT 0.525 109.840 1296.000 111.840 ;
        RECT 4.400 108.440 1296.000 109.840 ;
        RECT 0.525 106.440 1296.000 108.440 ;
        RECT 4.400 105.040 1296.000 106.440 ;
        RECT 0.525 103.040 1296.000 105.040 ;
        RECT 4.400 101.640 1296.000 103.040 ;
        RECT 0.525 99.640 1296.000 101.640 ;
        RECT 4.400 98.240 1296.000 99.640 ;
        RECT 0.525 96.240 1296.000 98.240 ;
        RECT 4.400 94.840 1296.000 96.240 ;
        RECT 0.525 92.840 1296.000 94.840 ;
        RECT 4.400 91.440 1296.000 92.840 ;
        RECT 0.525 89.440 1296.000 91.440 ;
        RECT 4.400 88.040 1296.000 89.440 ;
        RECT 0.525 86.040 1296.000 88.040 ;
        RECT 4.400 84.640 1296.000 86.040 ;
        RECT 0.525 82.640 1296.000 84.640 ;
        RECT 4.400 81.240 1296.000 82.640 ;
        RECT 0.525 79.240 1296.000 81.240 ;
        RECT 4.400 77.840 1296.000 79.240 ;
        RECT 0.525 75.840 1296.000 77.840 ;
        RECT 4.400 74.440 1296.000 75.840 ;
        RECT 0.525 72.440 1296.000 74.440 ;
        RECT 4.400 71.040 1296.000 72.440 ;
        RECT 0.525 69.040 1296.000 71.040 ;
        RECT 4.400 67.640 1296.000 69.040 ;
        RECT 0.525 65.640 1296.000 67.640 ;
        RECT 4.400 64.240 1296.000 65.640 ;
        RECT 0.525 62.240 1296.000 64.240 ;
        RECT 4.400 60.840 1296.000 62.240 ;
        RECT 0.525 58.840 1296.000 60.840 ;
        RECT 4.400 57.440 1296.000 58.840 ;
        RECT 0.525 55.440 1296.000 57.440 ;
        RECT 4.400 54.040 1296.000 55.440 ;
        RECT 0.525 52.040 1296.000 54.040 ;
        RECT 4.400 50.640 1296.000 52.040 ;
        RECT 0.525 48.640 1296.000 50.640 ;
        RECT 4.400 47.240 1296.000 48.640 ;
        RECT 0.525 45.240 1296.000 47.240 ;
        RECT 4.400 43.840 1296.000 45.240 ;
        RECT 0.525 41.840 1296.000 43.840 ;
        RECT 4.400 40.440 1296.000 41.840 ;
        RECT 0.525 38.440 1296.000 40.440 ;
        RECT 4.400 37.040 1296.000 38.440 ;
        RECT 0.525 35.040 1296.000 37.040 ;
        RECT 4.400 33.640 1296.000 35.040 ;
        RECT 0.525 31.640 1296.000 33.640 ;
        RECT 4.400 30.240 1296.000 31.640 ;
        RECT 0.525 28.240 1296.000 30.240 ;
        RECT 4.400 26.840 1296.000 28.240 ;
        RECT 0.525 24.840 1296.000 26.840 ;
        RECT 4.400 23.440 1296.000 24.840 ;
        RECT 0.525 21.440 1296.000 23.440 ;
        RECT 4.400 20.040 1296.000 21.440 ;
        RECT 0.525 18.040 1296.000 20.040 ;
        RECT 4.400 16.640 1296.000 18.040 ;
        RECT 0.525 14.640 1296.000 16.640 ;
        RECT 4.400 13.240 1296.000 14.640 ;
        RECT 0.525 11.240 1296.000 13.240 ;
        RECT 4.400 9.840 1296.000 11.240 ;
        RECT 0.525 7.840 1296.000 9.840 ;
        RECT 4.400 6.440 1296.000 7.840 ;
        RECT 0.525 4.440 1296.000 6.440 ;
        RECT 4.400 3.040 1296.000 4.440 ;
        RECT 0.525 1.040 1296.000 3.040 ;
        RECT 4.400 0.190 1296.000 1.040 ;
      LAYER met4 ;
        RECT 3.975 10.240 20.640 1204.105 ;
        RECT 23.040 10.240 23.940 1204.105 ;
        RECT 26.340 10.240 174.240 1204.105 ;
        RECT 176.640 10.240 177.540 1204.105 ;
        RECT 179.940 10.240 327.840 1204.105 ;
        RECT 330.240 10.240 331.140 1204.105 ;
        RECT 333.540 10.240 481.440 1204.105 ;
        RECT 483.840 10.240 484.740 1204.105 ;
        RECT 487.140 10.240 635.040 1204.105 ;
        RECT 637.440 10.240 638.340 1204.105 ;
        RECT 640.740 10.240 788.640 1204.105 ;
        RECT 791.040 10.240 791.940 1204.105 ;
        RECT 794.340 10.240 942.240 1204.105 ;
        RECT 944.640 10.240 945.540 1204.105 ;
        RECT 947.940 10.240 1095.840 1204.105 ;
        RECT 1098.240 10.240 1099.140 1204.105 ;
        RECT 1101.540 10.240 1249.440 1204.105 ;
        RECT 1251.840 10.240 1252.740 1204.105 ;
        RECT 1255.140 10.240 1289.545 1204.105 ;
        RECT 3.975 6.295 1289.545 10.240 ;
  END
END xbar_main
END LIBRARY

